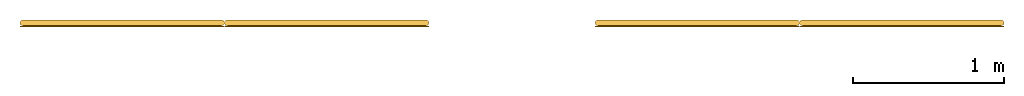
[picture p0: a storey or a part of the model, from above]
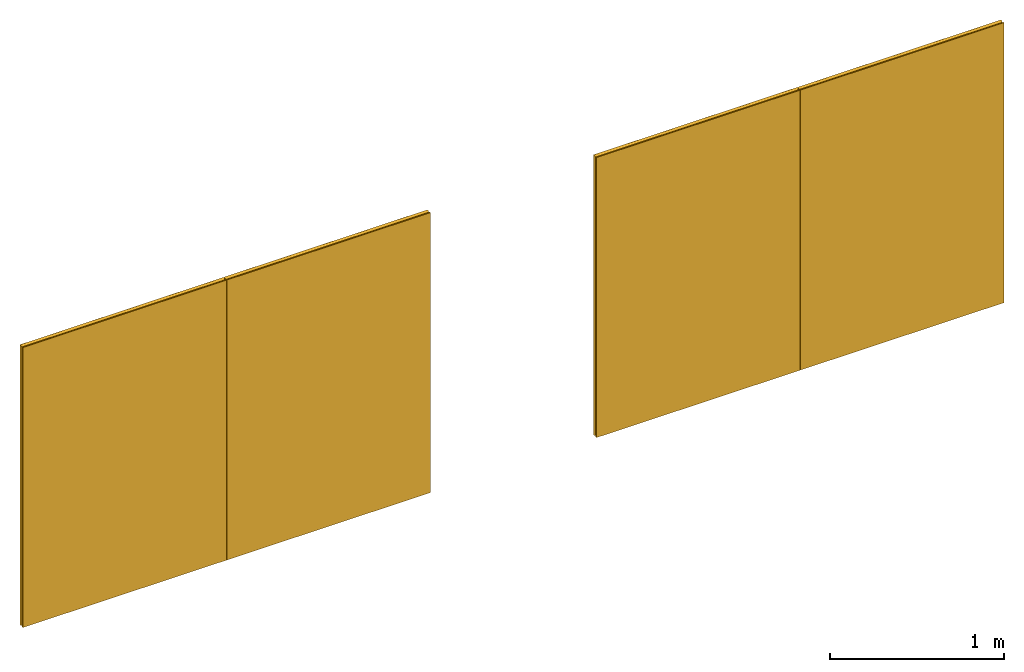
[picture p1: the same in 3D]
Properties of the parts of a building model (IFC2X3), part 1 of 11

# File
Description: ViewDefinition [CoordinationView]
File name: Project Number
Time: 2011-09-06T11:22:43
Written by: Autodesk Revit Architecture 2011 - 1.0
Made in: 20100326_1700

# IfcProject, Project Number
Phase: Project Status

# IfcSite, Default
RefLatitude: 42, 21, 30, 344238; RefLongitude: -71, -3, -35, -194702; RefElevation: 0 m

# IfcBuilding
Pset_BuildingCommon - NumberOfStoreys: 4
PSet_Revit_Other - Project Issue Date: Issue Date; Project Status: Project Status; Client Name: Owner; Project Address: Enter address here; Project Name: Project Name; Project Number: Project Number; Category Description: OmniClass Table 11 Description; Category Code: OmniClass Table 11 Code

# IfcBuildingStorey (4)
PSet_Revit_Type_Graphics - Line Weight: 1; Color: 0; Line Pattern: Centre; Symbol: M_Level Head - Circle; Symbol at End 1 Default: no; Symbol at End 2 Default: yes
PSet_Revit_Type_Constraints - Elevation Base: 0
PSet_Revit_Type_Dimensions - Automatic Room Computation Height: yes
Name | Elevation (m) | Name | PSet_Revit_Constraints, Elevation (m) | Category Code
TOF Footing | -1 | TOF Footing | -1 | Site
First Floor | -3.5315e-13 | First Floor | 0 | Floor
Second Floor | 4.57 | Second Floor | 4.57 | Floor
Roof - Main | 9.25 | Roof - Main | 9.25 | Roof

# IfcSpace (269)
InteriorOrExteriorSpace: INTERNAL
PSet_Revit_Phasing - Phase: New Construction
PSet_Revit_Other - RoomTag: RoomTag
Name | In | LongName = Name | GSA BIM Area (m2) = Area (m2) | Number | OmniClass Table 13 Category | Level | Upper Limit | Limit Offset (m) | Base Offset (m) | Perimeter (m) | Unbounded Height (m) | Volume (m3) | Category Description | Category Code | CirculationZoneName | FireAlarmZoneName | HistoricPreservationZoneName | LightingZoneName | OccupancyZoneName | VentilationZoneName
1AC2 | First Floor | CORRIDOR | 19.605 | 1AC2 | 13-85 11 11: Corridor | First Floor | First Floor | 2.8 | 0 | 24.0652 | 2.8 | 53.4757 | Corridor | 13-85 11 11 | Circulation Zone 1A | Fire Alarm Zone 1A | Historic Preservation Zone 1A | Lighting Zone 1A | Occupancy Zone 1A | Ventilation Zone 1A
1A01 | First Floor | PATIENT ADMIN. RECEPT. | 19.7671 | 1A01 | 13-11 11 31: Reception Space | First Floor | First Floor | 2.8 | 0 | 19.072 | 2.8 | 53.2474 | Reception Space | 13-11 11 31 | Circulation Zone 1A | Fire Alarm Zone 1A | Historic Preservation Zone 1A | Lighting Zone 1A | Occupancy Zone 1A | Ventilation Zone 1A
1A02 | First Floor | RMO ANALYST | 27.6932 | 1A02 | 13-15 11 34 11: Office | First Floor | First Floor | 2.8 | 0 | 26.5002 | 2.8 | 74.6419 | Office | 13-15 11 34 11 | Circulation Zone 1A | Fire Alarm Zone 1A | Historic Preservation Zone 1A | Lighting Zone 1A | Occupancy Zone 1A | Ventilation Zone 1A
1A03 | First Floor | TRICARE OFFICE | 8.87366 | 1A03 | 13-15 11 34 11: Office | First Floor | First Floor | 2.8 | 0 | 11.957 | 2.8 | 22.8438 | Office | 13-15 11 34 11 | Circulation Zone 1A | Fire Alarm Zone 1A | Historic Preservation Zone 1A | Lighting Zone 1A | Occupancy Zone 1A | Ventilation Zone 1A
1A04 | First Floor | TRICARE OFFICE | 9.54452 | 1A04 | 13-15 11 34 11: Office | First Floor | First Floor | 2.8 | 0 | 12.369 | 2.8 | 24.0527 | Office | 13-15 11 34 11 | Circulation Zone 1A | Fire Alarm Zone 1A | Historic Preservation Zone 1A | Lighting Zone 1A | Occupancy Zone 1A | Ventilation Zone 1A
1A05 | First Floor | TRICARE OFFICE | 8.99911 | 1A05 | 13-15 11 34 11: Office | First Floor | First Floor | 2.8 | 0 | 12.192 | 2.8 | 23.2335 | Office | 13-15 11 34 11 | Circulation Zone 1A | Fire Alarm Zone 1A | Historic Preservation Zone 1A | Lighting Zone 1A | Occupancy Zone 1A | Ventilation Zone 1A
1A06 | First Floor | TRICARE OFFICE | 10.4921 | 1A06 | 13-15 11 34 11: Office | First Floor | First Floor | 2.8 | 0 | 13.0265 | 2.8 | 26.1176 | Office | 13-15 11 34 11 | Circulation Zone 1A | Fire Alarm Zone 1A | Historic Preservation Zone 1A | Lighting Zone 1A | Occupancy Zone 1A | Ventilation Zone 1A
1A07 | First Floor | TRICARE OFFICE | 8.73012 | 1A07 | 13-15 11 34 11: Office | First Floor | First Floor | 2.8 | 0 | 12.5275 | 2.8 | 22.3143 | Office | 13-15 11 34 11 | Circulation Zone 1A | Fire Alarm Zone 1A | Historic Preservation Zone 1A | Lighting Zone 1A | Occupancy Zone 1A | Ventilation Zone 1A
1A08 | First Floor | PHARM. OFFICE | 10.4499 | 1A08 | 13-15 11 34 11: Office | First Floor | First Floor | 2.8 | 0 | 12.989 | 2.8 | 26.63 | Office | 13-15 11 34 11 | Circulation Zone 1A | Fire Alarm Zone 1A | Historic Preservation Zone 1A | Lighting Zone 1A | Occupancy Zone 1A | Ventilation Zone 1A
1A11 | First Floor | JAN. | 2.03661 | 1A11 | 13-75 11 11: Storage Room | First Floor | First Floor | 2.8 | 0 | 6.022 | 2.8 | 4.70014 | Storage Room | 13-75 11 11 | Circulation Zone 1A | Fire Alarm Zone 1A | Historic Preservation Zone 1A | Lighting Zone 1A | Occupancy Zone 1A | Ventilation Zone 1A
1A14 | First Floor | SUPER / NCOIC | 7.22988 | 1A14 | 13-15 11 34 11: Office | First Floor | First Floor | 2.8 | 0 | 10.1474 | 2.8 | 18.8948 | Office | 13-15 11 34 11 | Circulation Zone 1A | Fire Alarm Zone 1A | Historic Preservation Zone 1A | Lighting Zone 1A | Occupancy Zone 1A | Ventilation Zone 1A
1A15 | First Floor | COUNSELING | 6.39843 | 1A15 | 13-41 41 99: Other Healing Spaces | First Floor | First Floor | 2.8 | 0 | 10.157 | 2.8 | 16.4305 | Other Healing Spaces | 13-41 41 99 | Circulation Zone 1A | Fire Alarm Zone 1A | Historic Preservation Zone 1A | Lighting Zone 1A | Occupancy Zone 1A | Ventilation Zone 1A
1DC1 | First Floor | WAITING / ACTIVITY AREA | 182.28 | 1DC1 | 13-51 31 11: Waiting Room | First Floor | Second Floor | 0 | 0 | 80.656 | 4.57 | 814.452 | Waiting Room | 13-51 31 11 | Circulation Zone 1D | Fire Alarm Zone 1D | Historic Preservation Zone 1D | Lighting Zone 1D | Occupancy Zone 1D | Ventilation Zone 1D
1DC2 | First Floor | CORRIDOR | 6.34736 | 1DC2 | 13-85 11 11: Corridor | First Floor | First Floor | 2.8 | 0 | 10.67 | 2.8 | 16.6144 | Corridor | 13-85 11 11 | Circulation Zone 1D | Fire Alarm Zone 1D | Historic Preservation Zone 1D | Lighting Zone 1D | Occupancy Zone 1D | Ventilation Zone 1D
1DC3 | First Floor | CORRIDOR | 31.8109 | 1DC3 | 13-85 11 11: Corridor | First Floor | First Floor | 2.8 | 0 | 38.1194 | 2.8 | 83.0333 | Corridor | 13-85 11 11 | Circulation Zone 1D | Fire Alarm Zone 1D | Historic Preservation Zone 1D | Lighting Zone 1D | Occupancy Zone 1D | Ventilation Zone 1D
1DC4 | First Floor | CORRIDOR | 15.0608 | 1DC4 | 13-85 11 11: Corridor | First Floor | First Floor | 2.8 | 0 | 20.1242 | 2.8 | 39.4804 | Corridor | 13-85 11 11 | Circulation Zone 1D | Fire Alarm Zone 1D | Historic Preservation Zone 1D | Lighting Zone 1D | Occupancy Zone 1D | Ventilation Zone 1D
1CC2 | First Floor | CORRIDOR | 8.23209 | 1CC2 | 13-85 11 11: Corridor | First Floor | First Floor | 2.8 | 0 | 12.0636 | 2.8 | 21.1946 | Corridor | 13-85 11 11 | Circulation Zone 1C | Fire Alarm Zone 1C | Historic Preservation Zone 1C | Lighting Zone 1C | Occupancy Zone 1C | Ventilation Zone 1C
1CC3 | First Floor | CORRIDOR | 11.4965 | 1CC3 | 13-85 11 11: Corridor | First Floor | First Floor | 2.8 | 0 | 15.7842 | 2.8 | 29.7028 | Corridor | 13-85 11 11 | Circulation Zone 1C | Fire Alarm Zone 1C | Historic Preservation Zone 1C | Lighting Zone 1C | Occupancy Zone 1C | Ventilation Zone 1C
1C01 | First Floor | WAITING | 11.8597 | 1C01 | 13-51 31 11: Waiting Room | First Floor | First Floor | 2.8 | 0 | 13.5102 | 2.8 | 32.5825 | Waiting Room | 13-51 31 11 | Circulation Zone 1C | Fire Alarm Zone 1C | Historic Preservation Zone 1C | Lighting Zone 1C | Occupancy Zone 1C | Ventilation Zone 1C
1C02 | First Floor | RECEPTION | 9.31934 | 1C02 | 13-11 11 31: Reception Space | First Floor | First Floor | 2.8 | 0 | 12.2052 | 2.8 | 24.6922 | Reception Space | 13-11 11 31 | Circulation Zone 1C | Fire Alarm Zone 1C | Historic Preservation Zone 1C | Lighting Zone 1C | Occupancy Zone 1C | Ventilation Zone 1C
1C03 | First Floor | JAN. CL. | 4.1106 | 1C03 | 13-75 11 11: Storage Room | First Floor | First Floor | 2.8 | 0 | 8.924 | 2.8 | 9.93108 | Storage Room | 13-75 11 11 | Circulation Zone 1C | Fire Alarm Zone 1C | Historic Preservation Zone 1C | Lighting Zone 1C | Occupancy Zone 1C | Ventilation Zone 1C
1C04 | First Floor | FITTING / DISP. | 10.1189 | 1C04 | 13-41 41 99: Other Healing Spaces | First Floor | First Floor | 2.8 | 0 | 12.623 | 2.8 | 25.7339 | Other Healing Spaces | 13-41 41 99 | Circulation Zone 1C | Fire Alarm Zone 1C | Historic Preservation Zone 1C | Lighting Zone 1C | Occupancy Zone 1C | Ventilation Zone 1C
1C05 | First Floor | VISUAL FIELD | 11.3446 | 1C05 | 13-41 41 14: Physical Examination Room | First Floor | First Floor | 2.8 | 0 | 14.538 | 2.8 | 28.2926 | Physical Examination Room | 13-41 41 14 | Circulation Zone 1C | Fire Alarm Zone 1C | Historic Preservation Zone 1C | Lighting Zone 1C | Occupancy Zone 1C | Ventilation Zone 1C
1C06 | First Floor | SOIL. UTL. / TRASH | 5.40043 | 1C06 | 13-75 41 14: Soiled Storage Room Space | First Floor | First Floor | 2.8 | 0 | 9.3758 | 2.8 | 13.0309 | Soiled Storage Room Space | 13-75 41 14 | Circulation Zone 1C | Fire Alarm Zone 1C | Historic Preservation Zone 1C | Lighting Zone 1C | Occupancy Zone 1C | Ventilation Zone 1C
1C07 | First Floor | OPT. EXAM / OFF. | 17.5712 | 1C07 | 13-15 11 34 11: Office | First Floor | First Floor | 2.8 | 0 | 20.7032 | 2.8 | 45.6483 | Office | 13-15 11 34 11 | Circulation Zone 1C | Fire Alarm Zone 1C | Historic Preservation Zone 1C | Lighting Zone 1C | Occupancy Zone 1C | Ventilation Zone 1C
1C08 | First Floor | SCREEN EYE TEST | 9.81776 | 1C08 | 13-41 41 14: Physical Examination Room | First Floor | First Floor | 2.8 | 0 | 13.352 | 2.8 | 25.4762 | Physical Examination Room | 13-41 41 14 | Circulation Zone 1C | Fire Alarm Zone 1C | Historic Preservation Zone 1C | Lighting Zone 1C | Occupancy Zone 1C | Ventilation Zone 1C
1C09 | First Floor | FUNDUS CAMERA ROOM | 14.9278 | 1C09 | 13-41 41 31: Scanning/Imaging Room | First Floor | First Floor | 2.8 | 0 | 16.234 | 2.8 | 38.5611 | Scanning/Imaging Room | 13-41 41 31 | Circulation Zone 1C | Fire Alarm Zone 1C | Historic Preservation Zone 1C | Lighting Zone 1C | Occupancy Zone 1C | Ventilation Zone 1C
1C10 | First Floor | OPT. EXAM / OFF. | 18.2545 | 1C10 | 13-15 11 34 11: Office | First Floor | First Floor | 2.8 | 0 | 20.8688 | 2.8 | 47.5479 | Office | 13-15 11 34 11 | Circulation Zone 1C | Fire Alarm Zone 1C | Historic Preservation Zone 1C | Lighting Zone 1C | Occupancy Zone 1C | Ventilation Zone 1C
1D01 | First Floor | SL. LIN. / TRASH | 2.00168 | 1D01 | 13-75 41 14: Soiled Storage Room Space | First Floor | First Floor | 2.8 | 0 | 6.1929 | 2.8 | 4.65454 | Soiled Storage Room Space | 13-75 41 14 | Circulation Zone 1D | Fire Alarm Zone 1D | Historic Preservation Zone 1D | Lighting Zone 1D | Occupancy Zone 1D | Ventilation Zone 1D
1D03 | First Floor | CLEAN U. | 2.35008 | 1D03 | 13-15 21 11 21: Clean Room | First Floor | First Floor | 2.8 | 0 | 6.09322 | 2.8 | 5.84763 | Clean Room | 13-15 21 11 21 | Circulation Zone 1D | Fire Alarm Zone 1D | Historic Preservation Zone 1D | Lighting Zone 1D | Occupancy Zone 1D | Ventilation Zone 1D
1D12 | First Floor | SPECIMEN COLL. LAB | 10.2108 | 1D12 | 13-15 11 24 11: Laboratory | First Floor | First Floor | 2.8 | 0 | 13.1729 | 2.8 | 26.3971 | Laboratory | 13-15 11 24 11 | Circulation Zone 1D | Fire Alarm Zone 1D | Historic Preservation Zone 1D | Lighting Zone 1D | Occupancy Zone 1D | Ventilation Zone 1D
1D15 | First Floor | WTS & MEAS. ROOM | 5.06769 | 1D15 | 13-41 41 14: Physical Examination Room | First Floor | First Floor | 2.8 | 0 | 9.0729 | 2.8 | 12.8164 | Physical Examination Room | 13-41 41 14 | Circulation Zone 1D | Fire Alarm Zone 1D | Historic Preservation Zone 1D | Lighting Zone 1D | Occupancy Zone 1D | Ventilation Zone 1D
1D16 | First Floor | PROVIDER CUBICLES | 67.8336 | 1D16 | 13-15 11 34 11: Office | First Floor | First Floor | 2.8 | 0 | 36.731 | 2.8 | 182.732 | Office | 13-15 11 34 11 | Circulation Zone 1D | Fire Alarm Zone 1D | Historic Preservation Zone 1D | Lighting Zone 1D | Occupancy Zone 1D | Ventilation Zone 1D
1D17 | First Floor | JAN. CL. | 2.05671 | 1D17 | 13-75 11 11: Storage Room | First Floor | First Floor | 2.8 | 0 | 5.8058 | 2.8 | 4.67952 | Storage Room | 13-75 11 11 | Circulation Zone 1D | Fire Alarm Zone 1D | Historic Preservation Zone 1D | Lighting Zone 1D | Occupancy Zone 1D | Ventilation Zone 1D
1D19 | First Floor | MDIS VIEW | 5.63662 | 1D19 | 13-15 11 34 11: Office | First Floor | First Floor | 2.8 | 0 | 9.711 | 2.8 | 14.3243 | Office | 13-15 11 34 11 | Circulation Zone 1D | Fire Alarm Zone 1D | Historic Preservation Zone 1D | Lighting Zone 1D | Occupancy Zone 1D | Ventilation Zone 1D
1D20 | First Floor | APPMTS | 11.7909 | 1D20 | 13-15 11 34 11: Office | First Floor | First Floor | 2.8 | 0 | 13.74 | 2.8 | 30.6724 | Office | 13-15 11 34 11 | Circulation Zone 1D | Fire Alarm Zone 1D | Historic Preservation Zone 1D | Lighting Zone 1D | Occupancy Zone 1D | Ventilation Zone 1D
1D21 | First Floor | GROUP IS | 19.1917 | 1D21 | 13-41 41 99: Other Healing Spaces | First Floor | First Floor | 2.8 | 0 | 18.161 | 2.8 | 50.1831 | Other Healing Spaces | 13-41 41 99 | Circulation Zone 1D | Fire Alarm Zone 1D | Historic Preservation Zone 1D | Lighting Zone 1D | Occupancy Zone 1D | Ventilation Zone 1D
1D23 | First Floor | GROUP IS | 19.1868 | 1D23 | 13-41 41 99: Other Healing Spaces | First Floor | First Floor | 2.8 | 0 | 18.161 | 2.8 | 50.1702 | Other Healing Spaces | 13-41 41 99 | Circulation Zone 1D | Fire Alarm Zone 1D | Historic Preservation Zone 1D | Lighting Zone 1D | Occupancy Zone 1D | Ventilation Zone 1D
1D24 | First Floor | RECORDS | 11.7777 | 1D24 | 13-75 11 11: Storage Room | First Floor | First Floor | 2.8 | 0 | 13.705 | 2.8 | 30.6724 | Storage Room | 13-75 11 11 | Circulation Zone 1D | Fire Alarm Zone 1D | Historic Preservation Zone 1D | Lighting Zone 1D | Occupancy Zone 1D | Ventilation Zone 1D
1D25 | First Floor | PROVIDER CUBICLES | 67.8191 | 1D25 | 13-15 11 34 11: Office | First Floor | First Floor | 2.8 | 0 | 36.627 | 2.8 | 182.56 | Office | 13-15 11 34 11 | Circulation Zone 1D | Fire Alarm Zone 1D | Historic Preservation Zone 1D | Lighting Zone 1D | Occupancy Zone 1D | Ventilation Zone 1D
1D27 | First Floor | ADMIN WORK STATN. | 10.7499 | 1D27 | 13-15 11 34 11: Office | First Floor | First Floor | 2.8 | 0 | 13.412 | 2.8 | 27.8833 | Office | 13-15 11 34 11 | Circulation Zone 1D | Fire Alarm Zone 1D | Historic Preservation Zone 1D | Lighting Zone 1D | Occupancy Zone 1D | Ventilation Zone 1D
1D30 | First Floor | WTS & MEAS. ROOM | 9.26534 | 1D30 | 13-41 41 14: Physical Examination Room | First Floor | First Floor | 2.8 | 0 | 12.672 | 2.8 | 23.7861 | Physical Examination Room | 13-41 41 14 | Circulation Zone 1D | Fire Alarm Zone 1D | Historic Preservation Zone 1D | Lighting Zone 1D | Occupancy Zone 1D | Ventilation Zone 1D
1D33 | First Floor | PEDIATRIC WAITING | 12.7423 | 1D33 | 13-51 31 11: Waiting Room | First Floor | First Floor | 2.8 | 0 | 14.432 | 2.8 | 33.2712 | Waiting Room | 13-51 31 11 | Circulation Zone 1D | Fire Alarm Zone 1D | Historic Preservation Zone 1D | Lighting Zone 1D | Occupancy Zone 1D | Ventilation Zone 1D
1D37 | First Floor | CLEAN U. | 2.35008 | 1D37 | 13-15 21 11 21: Clean Room | First Floor | First Floor | 2.8 | 0 | 6.09322 | 2.8 | 5.84763 | Clean Room | 13-15 21 11 21 | Circulation Zone 1D | Fire Alarm Zone 1D | Historic Preservation Zone 1D | Lighting Zone 1D | Occupancy Zone 1D | Ventilation Zone 1D
1D39 | First Floor | JAN. CL. | 2.00067 | 1D39 | 13-75 11 11: Storage Room | First Floor | First Floor | 2.8 | 0 | 6.192 | 2.8 | 4.65202 | Storage Room | 13-75 11 11 | Circulation Zone 1D | Fire Alarm Zone 1D | Historic Preservation Zone 1D | Lighting Zone 1D | Occupancy Zone 1D | Ventilation Zone 1D
1DC5 | First Floor | CORRIDOR | 6.61219 | 1DC5 | 13-85 11 11: Corridor | First Floor | First Floor | 2.8 | 0 | 10.2786 | 2.8 | 17.0051 | Corridor | 13-85 11 11 | Circulation Zone 1D | Fire Alarm Zone 1D | Historic Preservation Zone 1D | Lighting Zone 1D | Occupancy Zone 1D | Ventilation Zone 1D
1DC6 | First Floor | CORRIDOR | 15.0065 | 1DC6 | 13-85 11 11: Corridor | First Floor | First Floor | 2.8 | 0 | 20.1568 | 2.8 | 38.8805 | Corridor | 13-85 11 11 | Circulation Zone 1D | Fire Alarm Zone 1D | Historic Preservation Zone 1D | Lighting Zone 1D | Occupancy Zone 1D | Ventilation Zone 1D
1DC7 | First Floor | CORRIDOR | 31.9069 | 1DC7 | 13-85 11 11: Corridor | First Floor | First Floor | 2.8 | 0 | 37.8435 | 2.8 | 83.5098 | Corridor | 13-85 11 11 | Circulation Zone 1D | Fire Alarm Zone 1D | Historic Preservation Zone 1D | Lighting Zone 1D | Occupancy Zone 1D | Ventilation Zone 1D
1DC8 | First Floor | CORRIDOR | 6.29243 | 1DC8 | 13-85 11 11: Corridor | First Floor | First Floor | 2.8 | 0 | 10.6091 | 2.8 | 16.4607 | Corridor | 13-85 11 11 | Circulation Zone 1D | Fire Alarm Zone 1D | Historic Preservation Zone 1D | Lighting Zone 1D | Occupancy Zone 1D | Ventilation Zone 1D
1C13 | First Floor | COMM. ROOM | 11.8973 | 1C13 | 13-15 11 34 11: Office | First Floor | First Floor | 2.8 | 0 | 14.159 | 2.8 | 30.9818 | Office | 13-15 11 34 11 | Circulation Zone 1C | Fire Alarm Zone 1C | Historic Preservation Zone 1C | Lighting Zone 1C | Occupancy Zone 1C | Ventilation Zone 1C
1C14 | First Floor | HIST. / INTV. | 8.18416 | 1C14 | 13-41 41 99: Other Healing Spaces | First Floor | First Floor | 2.8 | 0 | 11.509 | 2.8 | 20.4711 | Other Healing Spaces | 13-41 41 99 | Circulation Zone 1C | Fire Alarm Zone 1C | Historic Preservation Zone 1C | Lighting Zone 1C | Occupancy Zone 1C | Ventilation Zone 1C
1C15 | First Floor | PES ADMIN. OFFICE | 15.3931 | 1C15 | 13-15 11 34 11: Office | First Floor | First Floor | 2.8 | 0 | 15.77 | 2.8 | 40.8184 | Office | 13-15 11 34 11 | Circulation Zone 1C | Fire Alarm Zone 1C | Historic Preservation Zone 1C | Lighting Zone 1C | Occupancy Zone 1C | Ventilation Zone 1C
1C16 | First Floor | ECG TEST | 10.0079 | 1C16 | 13-41 41 31: Scanning/Imaging Room | First Floor | First Floor | 2.8 | 0 | 13.668 | 2.8 | 25.3019 | Scanning/Imaging Room | 13-41 41 31 | Circulation Zone 1C | Fire Alarm Zone 1C | Historic Preservation Zone 1C | Lighting Zone 1C | Occupancy Zone 1C | Ventilation Zone 1C
1C17 | First Floor | CHIEF AERO MED. | 9.94224 | 1C17 | 13-15 11 34 11: Office | First Floor | First Floor | 2.8 | 0 | 12.691 | 2.8 | 25.1968 | Office | 13-15 11 34 11 | Circulation Zone 1C | Fire Alarm Zone 1C | Historic Preservation Zone 1C | Lighting Zone 1C | Occupancy Zone 1C | Ventilation Zone 1C
1C18 | First Floor | PHYSICAL EXAM | 58.0301 | 1C18 | 13-41 41 14: Physical Examination Room | First Floor | First Floor | 2.8 | 0 | 41.077 | 2.8 | 155.057 | Physical Examination Room | 13-41 41 14 | Circulation Zone 1C | Fire Alarm Zone 1C | Historic Preservation Zone 1C | Lighting Zone 1C | Occupancy Zone 1C | Ventilation Zone 1C
1C19 | First Floor | AUDIO | 11.6268 | 1C19 | 13-81 21 11: Equipment Room | First Floor | First Floor | 2.8 | 0 | 13.798 | 2.8 | 29.1218 | Equipment Room | 13-81 21 11 | Circulation Zone 1C | Fire Alarm Zone 1C | Historic Preservation Zone 1C | Lighting Zone 1C | Occupancy Zone 1C | Ventilation Zone 1C
1C11 | First Floor | ELEC. CL. | 0.777824 | 1C11 | 13-81 21 21: Electrical Room | First Floor | First Floor | 2.8 | 0 | 4.44 | 2.8 | 1.51133 | Electrical Room | 13-81 21 21 | Circulation Zone 1C | Fire Alarm Zone 1C | Historic Preservation Zone 1C | Lighting Zone 1C | Occupancy Zone 1C | Ventilation Zone 1C
1CS3 | First Floor | STAIR | 13.9094 | 1CS3 | 13-85 21 11: Stairway | First Floor | First Floor | 2.8 | 0 | 18.996 | 2.8 | 35.7133 | Stairway | 13-85 21 11 | Circulation Zone 1C | Fire Alarm Zone 1C | Historic Preservation Zone 1C | Lighting Zone 1C | Occupancy Zone 1C | Ventilation Zone 1C
1E01 | First Floor | HK EQUIP. STORAGE | 9.72524 | 1E01 | 13-75 11 11: Storage Room | First Floor | First Floor | 2.8 | 0 | 12.492 | 2.8 | 25.1051 | Storage Room | 13-75 11 11 | Circulation Zone 1E | Fire Alarm Zone 1E | Historic Preservation Zone 1E | Lighting Zone 1E | Occupancy Zone 1E | Ventilation Zone 1E
1E02 | First Floor | ELEV. EQUIP. | 5.67552 | 1E02 | 13-81 21 11: Equipment Room | First Floor | First Floor | 2.8 | 0 | 9.752 | 2.8 | 14.2416 | Equipment Room | 13-81 21 11 | Circulation Zone 1E | Fire Alarm Zone 1E | Historic Preservation Zone 1E | Lighting Zone 1E | Occupancy Zone 1E | Ventilation Zone 1E
1E03 | First Floor | JAN. CL. | 3.96995 | 1E03 | 13-75 11 11: Storage Room | First Floor | First Floor | 2.8 | 0 | 8.652 | 2.8 | 9.71094 | Storage Room | 13-75 11 11 | Circulation Zone 1E | Fire Alarm Zone 1E | Historic Preservation Zone 1E | Lighting Zone 1E | Occupancy Zone 1E | Ventilation Zone 1E
1E05 | First Floor | CHIEF LOG OFFICE | 9.93876 | 1E05 | 13-15 11 34 11: Office | First Floor | First Floor | 2.8 | 0 | 12.628 | 2.8 | 25.6794 | Office | 13-15 11 34 11 | Circulation Zone 1E | Fire Alarm Zone 1E | Historic Preservation Zone 1E | Lighting Zone 1E | Occupancy Zone 1E | Ventilation Zone 1E
1E06 | First Floor | TECH. WORK STATION | 37.3792 | 1E06 | 13-15 11 34 11: Office | First Floor | First Floor | 2.8 | 0 | 24.978 | 2.8 | 100.456 | Office | 13-15 11 34 11 | Circulation Zone 1E | Fire Alarm Zone 1E | Historic Preservation Zone 1E | Lighting Zone 1E | Occupancy Zone 1E | Ventilation Zone 1E
1E07 | First Floor | CONF. LIBRARY | 11.6309 | 1E07 | 13-11 21 17: Conference Room | First Floor | First Floor | 2.8 | 0 | 13.652 | 2.8 | 30.2395 | Conference Room | 13-11 21 17 | Circulation Zone 1E | Fire Alarm Zone 1E | Historic Preservation Zone 1E | Lighting Zone 1E | Occupancy Zone 1E | Ventilation Zone 1E
1E08 | First Floor | SUPER | 9.86423 | 1E08 | 13-15 11 34 11: Office | First Floor | First Floor | 2.8 | 0 | 13.058 | 2.8 | 25.4832 | Office | 13-15 11 34 11 | Circulation Zone 1E | Fire Alarm Zone 1E | Historic Preservation Zone 1E | Lighting Zone 1E | Occupancy Zone 1E | Ventilation Zone 1E
1E14 | First Floor | DISASTER STOR. | 22.3553 | 1E14 | 13-75 11 11: Storage Room | First Floor | First Floor | 2.8 | 0 | 19.889 | 2.8 | 59.1954 | Storage Room | 13-75 11 11 | Circulation Zone 1E | Fire Alarm Zone 1E | Historic Preservation Zone 1E | Lighting Zone 1E | Occupancy Zone 1E | Ventilation Zone 1E
1E15 | First Floor | CENTRAL MECH. RM. | 28.9142 | 1E15 | 13-81 21 17: Mechanical Room | First Floor | First Floor | 2.8 | 0 | 24.1165 | 2.8 | 76.0404 | Mechanical Room | 13-81 21 17 | Circulation Zone 1E | Fire Alarm Zone 1E | Historic Preservation Zone 1E | Lighting Zone 1E | Occupancy Zone 1E | Ventilation Zone 1E
1E17 | First Floor | HAZ. STOR. | 9.78713 | 1E17 | 13-75 41 24: Hazardous Material Storage Space | First Floor | First Floor | 2.8 | 0 | 12.724 | 2.8 | 24.2384 | Hazardous Material Storage Space | 13-75 41 24 | Circulation Zone 1E | Fire Alarm Zone 1E | Historic Preservation Zone 1E | Lighting Zone 1E | Occupancy Zone 1E | Ventilation Zone 1E
1E18 | First Floor | BIOMED MAINT. ADMIN. | 15.5543 | 1E18 | 13-15 11 34 11: Office | First Floor | First Floor | 2.8 | 0 | 15.9435 | 2.8 | 40.2173 | Office | 13-15 11 34 11 | Circulation Zone 1E | Fire Alarm Zone 1E | Historic Preservation Zone 1E | Lighting Zone 1E | Occupancy Zone 1E | Ventilation Zone 1E
1E19 | First Floor | ELEC. ROOM | 9.6262 | 1E19 | 13-81 21 21: Electrical Room | First Floor | First Floor | 2.8 | 0 | 12.686 | 2.8 | 24.8866 | Electrical Room | 13-81 21 21 | Circulation Zone 1E | Fire Alarm Zone 1E | Historic Preservation Zone 1E | Lighting Zone 1E | Occupancy Zone 1E | Ventilation Zone 1E
1E20 | First Floor | TRASH | 8.95436 | 1E20 | 13-75 41 14: Soiled Storage Room Space | First Floor | First Floor | 2.8 | 0 | 12.6045 | 2.8 | 22.0557 | Soiled Storage Room Space | 13-75 41 14 | Circulation Zone 1E | Fire Alarm Zone 1E | Historic Preservation Zone 1E | Lighting Zone 1E | Occupancy Zone 1E | Ventilation Zone 1E
1E21 | First Floor | FLAMABLE STORAGE | 5.66451 | 1E21 | 13-75 41 24: Hazardous Material Storage Space | First Floor | First Floor | 2.8 | 0 | 9.75218 | 2.8 | 13.5165 | Hazardous Material Storage Space | 13-75 41 24 | Circulation Zone 1E | Fire Alarm Zone 1E | Historic Preservation Zone 1E | Lighting Zone 1E | Occupancy Zone 1E | Ventilation Zone 1E
1E22 | First Floor | SEC. STORAGE | 6.27284 | 1E22 | 13-75 11 11: Storage Room | First Floor | First Floor | 2.8 | 0 | 10.424 | 2.8 | 15.7974 | Storage Room | 13-75 11 11 | Circulation Zone 1E | Fire Alarm Zone 1E | Historic Preservation Zone 1E | Lighting Zone 1E | Occupancy Zone 1E | Ventilation Zone 1E
1E23 | First Floor | BEE EQUIP. STORAGE | 8.77894 | 1E23 | 13-81 21 11: Equipment Room | First Floor | First Floor | 2.8 | 0 | 12.981 | 2.8 | 22.5535 | Equipment Room | 13-81 21 11 | Circulation Zone 1E | Fire Alarm Zone 1E | Historic Preservation Zone 1E | Lighting Zone 1E | Occupancy Zone 1E | Ventilation Zone 1E
1E24 | First Floor | RECEIVING / STORAGE | 118.296 | 1E24 | 13-75 11 11: Storage Room | First Floor | First Floor | 2.8 | 0 | 48.0138 | 2.8 | 322.336 | Storage Room | 13-75 11 11 | Circulation Zone 1E | Fire Alarm Zone 1E | Historic Preservation Zone 1E | Lighting Zone 1E | Occupancy Zone 1E | Ventilation Zone 1E
1E25 | First Floor | ADP EQUIP SPACE | 11.3734 | 1E25 | 13-75 11 11: Storage Room | First Floor | First Floor | 2.8 | 0 | 13.9988 | 2.8 | 29.5705 | Storage Room | 13-75 11 11 | Circulation Zone 1E | Fire Alarm Zone 1E | Historic Preservation Zone 1E | Lighting Zone 1E | Occupancy Zone 1E | Ventilation Zone 1E
1E26 | First Floor | WORK ROOM | 19.7143 | 1E26 | 13-15 11 34 11: Office | First Floor | First Floor | 2.8 | 0 | 18.857 | 2.8 | 51.3677 | Office | 13-15 11 34 11 | Circulation Zone 1E | Fire Alarm Zone 1E | Historic Preservation Zone 1E | Lighting Zone 1E | Occupancy Zone 1E | Ventilation Zone 1E
1E27 | First Floor | BENCHSTOCK STORAGE | 9.51258 | 1E27 | 13-75 11 11: Storage Room | First Floor | First Floor | 2.8 | 0 | 12.337 | 2.8 | 23.9448 | Storage Room | 13-75 11 11 | Circulation Zone 1E | Fire Alarm Zone 1E | Historic Preservation Zone 1E | Lighting Zone 1E | Occupancy Zone 1E | Ventilation Zone 1E
1E28 | First Floor | FAC. MGR. OFFICE | 9.73829 | 1E28 | 13-15 11 34 11: Office | First Floor | First Floor | 2.8 | 0 | 12.614 | 2.8 | 24.1581 | Office | 13-15 11 34 11 | Circulation Zone 1E | Fire Alarm Zone 1E | Historic Preservation Zone 1E | Lighting Zone 1E | Occupancy Zone 1E | Ventilation Zone 1E
1E29 | First Floor | HK. SUPV. OFFICE | 11.0301 | 1E29 | 13-15 11 34 11: Office | First Floor | First Floor | 2.8 | 0 | 13.469 | 2.8 | 27.8587 | Office | 13-15 11 34 11 | Circulation Zone 1E | Fire Alarm Zone 1E | Historic Preservation Zone 1E | Lighting Zone 1E | Occupancy Zone 1E | Ventilation Zone 1E
1E33 | First Floor | ISOLATION INTERACTION STATION | 13.354 | 1E33 | 13-41 41 99: Other Healing Spaces | First Floor | First Floor | 2.8 | 0 | 15.028 | 2.8 | 34.8761 | Other Healing Spaces | 13-41 41 99 | Circulation Zone 1E | Fire Alarm Zone 1E | Historic Preservation Zone 1E | Lighting Zone 1E | Occupancy Zone 1E | Ventilation Zone 1E
1EC1 | First Floor | CORRIDOR | 54.6837 | 1EC1 | 13-85 11 11: Corridor | First Floor | First Floor | 2.8 | 0 | 63.909 | 2.8 | 142.662 | Corridor | 13-85 11 11 | Circulation Zone 1E | Fire Alarm Zone 1E | Historic Preservation Zone 1E | Lighting Zone 1E | Occupancy Zone 1E | Ventilation Zone 1E
1EC2 | First Floor | CORRIDOR | 7.91371 | 1EC2 | 13-85 11 11: Corridor | First Floor | First Floor | 2.8 | 0 | 11.7164 | 2.8 | 20.3634 | Corridor | 13-85 11 11 | Circulation Zone 1E | Fire Alarm Zone 1E | Historic Preservation Zone 1E | Lighting Zone 1E | Occupancy Zone 1E | Ventilation Zone 1E
1EC3 | First Floor | CORRIDOR | 8.75185 | 1EC3 | 13-85 11 11: Corridor | First Floor | First Floor | 2.8 | 0 | 12.6304 | 2.8 | 22.5515 | Corridor | 13-85 11 11 | Circulation Zone 1E | Fire Alarm Zone 1E | Historic Preservation Zone 1E | Lighting Zone 1E | Occupancy Zone 1E | Ventilation Zone 1E
1EC4 | First Floor | CORRIDOR | 9.30567 | 1EC4 | 13-85 11 11: Corridor | First Floor | First Floor | 2.8 | 0 | 12.6514 | 2.8 | 23.6975 | Corridor | 13-85 11 11 | Circulation Zone 1E | Fire Alarm Zone 1E | Historic Preservation Zone 1E | Lighting Zone 1E | Occupancy Zone 1E | Ventilation Zone 1E
1BC1 | First Floor | CORRIDOR | 5.69274 | 1BC1 | 13-85 11 11: Corridor | First Floor | First Floor | 2.8 | 0 | 9.876 | 2.8 | 14.2682 | Corridor | 13-85 11 11 | Circulation Zone 1B | Fire Alarm Zone 1B | Historic Preservation Zone 1B | Lighting Zone 1B | Occupancy Zone 1B | Ventilation Zone 1B
1BC3 | First Floor | CORRIDOR | 13.4396 | 1BC3 | 13-85 11 11: Corridor | First Floor | First Floor | 2.8 | 0 | 18.0333 | 2.8 | 34.7897 | Corridor | 13-85 11 11 | Circulation Zone 1B | Fire Alarm Zone 1B | Historic Preservation Zone 1B | Lighting Zone 1B | Occupancy Zone 1B | Ventilation Zone 1B
1BC4 | First Floor | CORRIDOR | 44.3648 | 1BC4 | 13-85 11 11: Corridor | First Floor | First Floor | 2.8 | 0 | 44.8858 | 2.8 | 116.82 | Corridor | 13-85 11 11 | Circulation Zone 1B | Fire Alarm Zone 1B | Historic Preservation Zone 1B | Lighting Zone 1B | Occupancy Zone 1B | Ventilation Zone 1B
1B01 | First Floor | RECEPTION | 9.47555 | 1B01 | 13-11 11 31: Reception Space | First Floor | First Floor | 2.8 | 0 | 12.664 | 2.8 | 24.6632 | Reception Space | 13-11 11 31 | Circulation Zone 1B | Fire Alarm Zone 1B | Historic Preservation Zone 1B | Lighting Zone 1B | Occupancy Zone 1B | Ventilation Zone 1B
1B03 | First Floor | BLOOD DRAW | 9.68098 | 1B03 | 13-41 41 99: Other Healing Spaces | First Floor | First Floor | 2.8 | 0 | 12.732 | 2.8 | 24.9395 | Other Healing Spaces | 13-41 41 99 | Circulation Zone 1B | Fire Alarm Zone 1B | Historic Preservation Zone 1B | Lighting Zone 1B | Occupancy Zone 1B | Ventilation Zone 1B
1B06 | First Floor | LAB OFFICE | 10.4755 | 1B06 | 13-15 11 34 11: Office | First Floor | First Floor | 2.8 | 0 | 13.1609 | 2.8 | 26.1831 | Office | 13-15 11 34 11 | Circulation Zone 1B | Fire Alarm Zone 1B | Historic Preservation Zone 1B | Lighting Zone 1B | Occupancy Zone 1B | Ventilation Zone 1B
1B07 | First Floor | DRESS | 4.42138 | 1B07 | 13-41 11 41 11: Dressing Room | First Floor | First Floor | 2.8 | 0 | 8.704 | 2.8 | 10.9119 | Dressing Room | 13-41 11 41 11 | Circulation Zone 1B | Fire Alarm Zone 1B | Historic Preservation Zone 1B | Lighting Zone 1B | Occupancy Zone 1B | Ventilation Zone 1B
1B08 | First Floor | CENT. STO. | 9.76711 | 1B08 | 13-75 11 11: Storage Room | First Floor | First Floor | 2.8 | 0 | 12.796 | 2.8 | 25.0222 | Storage Room | 13-75 11 11 | Circulation Zone 1B | Fire Alarm Zone 1B | Historic Preservation Zone 1B | Lighting Zone 1B | Occupancy Zone 1B | Ventilation Zone 1B
1B09 | First Floor | DRESS | 4.64607 | 1B09 | 13-41 11 41 11: Dressing Room | First Floor | First Floor | 2.8 | 0 | 8.64805 | 2.8 | 11.5507 | Dressing Room | 13-41 11 41 11 | Circulation Zone 1B | Fire Alarm Zone 1B | Historic Preservation Zone 1B | Lighting Zone 1B | Occupancy Zone 1B | Ventilation Zone 1B
1B12 | First Floor | CLEAN SUP. & EQUIP. | 3.90136 | 1B12 | 13-75 11 11: Storage Room | First Floor | First Floor | 2.8 | 0 | 8.51705 | 2.8 | 9.24604 | Storage Room | 13-75 11 11 | Circulation Zone 1B | Fire Alarm Zone 1B | Historic Preservation Zone 1B | Lighting Zone 1B | Occupancy Zone 1B | Ventilation Zone 1B
1B13 | First Floor | RECEPTION | 22.5898 | 1B13 | 13-11 11 31: Reception Space | First Floor | First Floor | 2.8 | 0 | 21.5613 | 2.8 | 60.089 | Reception Space | 13-11 11 31 | Circulation Zone 1B | Fire Alarm Zone 1B | Historic Preservation Zone 1B | Lighting Zone 1B | Occupancy Zone 1B | Ventilation Zone 1B
1B14 | First Floor | SOIL. UTL. | 4.03581 | 1B14 | 13-75 41 14: Soiled Storage Room Space | First Floor | First Floor | 2.8 | 0 | 8.609 | 2.8 | 9.59735 | Soiled Storage Room Space | 13-75 41 14 | Circulation Zone 1B | Fire Alarm Zone 1B | Historic Preservation Zone 1B | Lighting Zone 1B | Occupancy Zone 1B | Ventilation Zone 1B
1B15 | First Floor | FILM VIEW | 5.83705 | 1B15 | 13-41 41 31: Scanning/Imaging Room | First Floor | First Floor | 2.8 | 0 | 9.664 | 2.8 | 14.7091 | Scanning/Imaging Room | 13-41 41 31 | Circulation Zone 1B | Fire Alarm Zone 1B | Historic Preservation Zone 1B | Lighting Zone 1B | Occupancy Zone 1B | Ventilation Zone 1B
1B16 | First Floor | JAN. CL. | 4.03581 | 1B16 | 13-75 11 11: Storage Room | First Floor | First Floor | 2.8 | 0 | 8.609 | 2.8 | 9.59735 | Storage Room | 13-75 11 11 | Circulation Zone 1B | Fire Alarm Zone 1B | Historic Preservation Zone 1B | Lighting Zone 1B | Occupancy Zone 1B | Ventilation Zone 1B
1B17 | First Floor | TECH. WORK ROOM | 24.0437 | 1B17 | 13-15 11 34 11: Office | First Floor | First Floor | 2.8 | 0 | 20.0581 | 2.8 | 64.5027 | Office | 13-15 11 34 11 | Circulation Zone 1B | Fire Alarm Zone 1B | Historic Preservation Zone 1B | Lighting Zone 1B | Occupancy Zone 1B | Ventilation Zone 1B
1B19 | First Floor | RADIOGRAPHIC ROOM | 29.9132 | 1B19 | 13-41 41 99: Other Healing Spaces | First Floor | First Floor | 2.8 | 0 | 28.5508 | 2.8 | 79.0515 | Other Healing Spaces | 13-41 41 99 | Circulation Zone 1B | Fire Alarm Zone 1B | Historic Preservation Zone 1B | Lighting Zone 1B | Occupancy Zone 1B | Ventilation Zone 1B
1B21 | First Floor | COMM. ROOM | 9.80232 | 1B21 | 13-15 11 34 11: Office | First Floor | First Floor | 2.8 | 0 | 13.012 | 2.8 | 25.2307 | Office | 13-15 11 34 11 | Circulation Zone 1B | Fire Alarm Zone 1B | Historic Preservation Zone 1B | Lighting Zone 1B | Occupancy Zone 1B | Ventilation Zone 1B
1B23 | First Floor | ELEC. ROOM | 9.88297 | 1B23 | 13-81 21 21: Electrical Room | First Floor | First Floor | 2.8 | 0 | 13.0801 | 2.8 | 25.4447 | Electrical Room | 13-81 21 21 | Circulation Zone 1B | Fire Alarm Zone 1B | Historic Preservation Zone 1B | Lighting Zone 1B | Occupancy Zone 1B | Ventilation Zone 1B
1BS2 | First Floor | STAIR | 16.0319 | 1BS2 | 13-85 21 11: Stairway | First Floor | First Floor | 2.8 | 0 | 18.161 | 2.8 | 41.5241 | Stairway | 13-85 21 11 | Circulation Zone 1E | Fire Alarm Zone 1E | Historic Preservation Zone 1E | Lighting Zone 1E | Occupancy Zone 1E | Ventilation Zone 1E
1AS1 | First Floor | STAIR | 14.0577 | 1AS1 | 13-85 21 11: Stairway | First Floor | First Floor | 2.8 | 0 | 15.646 | 2.8 | 38.0143 | Stairway | 13-85 21 11 | Circulation Zone 1A | Fire Alarm Zone 1A | Historic Preservation Zone 1A | Lighting Zone 1A | Occupancy Zone 1A | Ventilation Zone 1A
1E15-A | First Floor | GAS STORAGE | 2.28945 | 1E15-A | 13-75 41 24: Hazardous Material Storage Space | First Floor | First Floor | 2.8 | 0 | 7.3006 | 2.8 | 4.64121 | Hazardous Material Storage Space | 13-75 41 24 | Circulation Zone 1E | Fire Alarm Zone 1E | Historic Preservation Zone 1E | Lighting Zone 1E | Occupancy Zone 1E | Ventilation Zone 1E
2AC1 | Second Floor | CORRIDOR | 39.5583 | 2AC1 | 13-85 11 11: Corridor | Second Floor | Roof - Main | 0 | 0 | 31.383 | 4.68 | 181.862 | Corridor | 13-85 11 11 | Circulation Zone 2A | Fire Alarm Zone 2A | Historic Preservation Zone 2A | Lighting Zone 2A | Occupancy Zone 2A | Ventilation Zone 2A
2AC2 | Second Floor | CORRIDOR | 15.0174 | 2AC2 | 13-85 11 11: Corridor | Second Floor | Second Floor | 2.8 | 0 | 21.167 | 2.8 | 38.9924 | Corridor | 13-85 11 11 | Circulation Zone 2A | Fire Alarm Zone 2A | Historic Preservation Zone 2A | Lighting Zone 2A | Occupancy Zone 2A | Ventilation Zone 2A
2AC3 | Second Floor | CORRIDOR | 27.093 | 2AC3 | 13-85 11 11: Corridor | Second Floor | Second Floor | 2.8 | 0 | 33.5372 | 2.8 | 71.9794 | Corridor | 13-85 11 11 | Circulation Zone 2A | Fire Alarm Zone 2A | Historic Preservation Zone 2A | Lighting Zone 2A | Occupancy Zone 2A | Ventilation Zone 2A
2AC4 | Second Floor | CORRIDOR | 14.3235 | 2AC4 | 13-85 11 11: Corridor | Second Floor | Second Floor | 2.8 | 0 | 19.474 | 2.8 | 37.5506 | Corridor | 13-85 11 11 | Circulation Zone 2A | Fire Alarm Zone 2A | Historic Preservation Zone 2A | Lighting Zone 2A | Occupancy Zone 2A | Ventilation Zone 2A
2AC5 | Second Floor | CORRIDOR | 9.10214 | 2AC5 | 13-85 11 11: Corridor | Second Floor | Second Floor | 2.8 | 0 | 13.0124 | 2.8 | 23.466 | Corridor | 13-85 11 11 | Circulation Zone 2A | Fire Alarm Zone 2A | Historic Preservation Zone 2A | Lighting Zone 2A | Occupancy Zone 2A | Ventilation Zone 2A
2AS1 | Second Floor | STAIR | 14.4483 | 2AS1 | 13-85 21 11: Stairway | Second Floor | Second Floor | 2.8 | 0 | 15.3236 | 2.8 | 38.2032 | Stairway | 13-85 21 11 | Circulation Zone 2A | Fire Alarm Zone 2A | Historic Preservation Zone 2A | Lighting Zone 2A | Occupancy Zone 2A | Ventilation Zone 2A
2A01 | Second Floor | LIBRARY / CONF. ROOM | 26.331 | 2A01 | 13-11 21 17: Conference Room | Second Floor | Second Floor | 2.8 | 0 | 21.7164 | 2.8 | 69.7917 | Conference Room | 13-11 21 17 | Circulation Zone 2A | Fire Alarm Zone 2A | Historic Preservation Zone 2A | Lighting Zone 2A | Occupancy Zone 2A | Ventilation Zone 2A
2A02 | Second Floor | SUPER OFFICE | 10.8708 | 2A02 | 13-15 11 34 11: Office | Second Floor | Second Floor | 2.8 | 0 | 14.101 | 2.8 | 28.0654 | Office | 13-15 11 34 11 | Circulation Zone 2A | Fire Alarm Zone 2A | Historic Preservation Zone 2A | Lighting Zone 2A | Occupancy Zone 2A | Ventilation Zone 2A
2A03 | Second Floor | SEC. OFFICE | 16.0095 | 2A03 | 13-15 11 34 11: Office | Second Floor | Second Floor | 2.8 | 0 | 16.097 | 2.8 | 41.3804 | Office | 13-15 11 34 11 | Circulation Zone 2A | Fire Alarm Zone 2A | Historic Preservation Zone 2A | Lighting Zone 2A | Occupancy Zone 2A | Ventilation Zone 2A
2A04 | Second Floor | DENTAL SURGEON OFFICE | 16.0139 | 2A04 | 13-15 11 34 11: Office | Second Floor | Second Floor | 2.8 | 0 | 16.099 | 2.8 | 41.8098 | Office | 13-15 11 34 11 | Circulation Zone 2A | Fire Alarm Zone 2A | Historic Preservation Zone 2A | Lighting Zone 2A | Occupancy Zone 2A | Ventilation Zone 2A
2A10 | Second Floor | DENTAL WAITING | 7.85686 | 2A10 | 13-51 31 11: Waiting Room | Second Floor | Second Floor | 2.8 | 0 | 10.8741 | 2.8 | 20.4537 | Waiting Room | 13-51 31 11 | Circulation Zone 2A | Fire Alarm Zone 2A | Historic Preservation Zone 2A | Lighting Zone 2A | Occupancy Zone 2A | Ventilation Zone 2A
2A11 | Second Floor | DENTAL WAITING | 33.4834 | 2A11 | 13-51 31 11: Waiting Room | Second Floor | Second Floor | 2.8 | 0 | 29.0513 | 2.8 | 88.9215 | Waiting Room | 13-51 31 11 | Circulation Zone 2A | Fire Alarm Zone 2A | Historic Preservation Zone 2A | Lighting Zone 2A | Occupancy Zone 2A | Ventilation Zone 2A
2A12-A | Second Floor | X-RAY ALCOVE | 2.28699 | 2A12-A | 13-41 41 31: Scanning/Imaging Room | Second Floor | Second Floor | 2.8 | 0 | 5.62774 | 2.8 | 5.58762 | Scanning/Imaging Room | 13-41 41 31 | Circulation Zone 2A | Fire Alarm Zone 2A | Historic Preservation Zone 2A | Lighting Zone 2A | Occupancy Zone 2A | Ventilation Zone 2A
2A14 | Second Floor | ADMIN | 32.8384 | 2A14 | 13-15 11 34 11: Office | Second Floor | Second Floor | 2.8 | 0 | 24.7893 | 2.8 | 88.1956 | Office | 13-15 11 34 11 | Circulation Zone 2A | Fire Alarm Zone 2A | Historic Preservation Zone 2A | Lighting Zone 2A | Occupancy Zone 2A | Ventilation Zone 2A
2C01 | Second Floor | DTR SUPPORT | 8.72505 | 2C01 | 13-15 11 34 11: Office | Second Floor | Second Floor | 2.8 | 0 | 11.958 | 2.8 | 22.7232 | Office | 13-15 11 34 11 | Circulation Zone 2C | Fire Alarm Zone 2C | Historic Preservation Zone 2C | Lighting Zone 2C | Occupancy Zone 2C | Ventilation Zone 2C
2C03 | Second Floor | CONSULT. | 33.4926 | 2C03 | 13-41 41 99: Other Healing Spaces | Second Floor | Second Floor | 2.8 | 0 | 28.4362 | 2.8 | 89.4233 | Other Healing Spaces | 13-41 41 99 | Circulation Zone 2C | Fire Alarm Zone 2C | Historic Preservation Zone 2C | Lighting Zone 2C | Occupancy Zone 2C | Ventilation Zone 2C
2C05 | Second Floor | JAN. CL. | 3.69253 | 2C05 | 13-75 11 11: Storage Room | Second Floor | Second Floor | 2.8 | 0 | 8.264 | 2.8 | 9.06385 | Storage Room | 13-75 11 11 | Circulation Zone 2C | Fire Alarm Zone 2C | Historic Preservation Zone 2C | Lighting Zone 2C | Occupancy Zone 2C | Ventilation Zone 2C
2C11 | Second Floor | HK | 5.0922 | 2C11 | 13-41 41 99: Other Healing Spaces | Second Floor | Second Floor | 2.8 | 0 | 9.49 | 2.8 | 12.8023 | Other Healing Spaces | 13-41 41 99 | Circulation Zone 2C | Fire Alarm Zone 2C | Historic Preservation Zone 2C | Lighting Zone 2C | Occupancy Zone 2C | Ventilation Zone 2C
2C13 | Second Floor | TRASH | 5.53953 | 2C13 | 13-75 41 14: Soiled Storage Room Space | Second Floor | Second Floor | 2.8 | 0 | 10.182 | 2.8 | 13.9686 | Soiled Storage Room Space | 13-75 41 14 | Circulation Zone 2C | Fire Alarm Zone 2C | Historic Preservation Zone 2C | Lighting Zone 2C | Occupancy Zone 2C | Ventilation Zone 2C
2C15 | Second Floor | COMM. ROOM | 9.58001 | 2C15 | 13-15 11 34 11: Office | Second Floor | Second Floor | 2.8 | 0 | 12.53 | 2.8 | 24.7051 | Office | 13-15 11 34 11 | Circulation Zone 2C | Fire Alarm Zone 2C | Historic Preservation Zone 2C | Lighting Zone 2C | Occupancy Zone 2C | Ventilation Zone 2C
2C18 | Second Floor | ELECTRICAL | 9.84 | 2C18 | 13-81 21 21: Electrical Room | Second Floor | Second Floor | 2.8 | 0 | 12.56 | 2.8 | 25.4146 | Electrical Room | 13-81 21 21 | Circulation Zone 2C | Fire Alarm Zone 2C | Historic Preservation Zone 2C | Lighting Zone 2C | Occupancy Zone 2C | Ventilation Zone 2C
2C19 | Second Floor | CENTRAL ISSUE | 21.0386 | 2C19 | 13-75 11 11: Storage Room | Second Floor | Second Floor | 2.8 | 0 | 19.886 | 2.8 | 55.4459 | Storage Room | 13-75 11 11 | Circulation Zone 2C | Fire Alarm Zone 2C | Historic Preservation Zone 2C | Lighting Zone 2C | Occupancy Zone 2C | Ventilation Zone 2C
2CC1 | Second Floor | CORRIDOR | 18.813 | 2CC1 | 13-85 11 11: Corridor | Second Floor | Second Floor | 2.8 | 0 | 23.5826 | 2.8 | 48.7709 | Corridor | 13-85 11 11 | Circulation Zone 2C | Fire Alarm Zone 2C | Historic Preservation Zone 2C | Lighting Zone 2C | Occupancy Zone 2C | Ventilation Zone 2C
2CC3 | Second Floor | CORRIDOR | 17.2506 | 2CC3 | 13-85 11 11: Corridor | Second Floor | Second Floor | 2.8 | 0 | 22.3132 | 2.8 | 45.0359 | Corridor | 13-85 11 11 | Circulation Zone 2C | Fire Alarm Zone 2C | Historic Preservation Zone 2C | Lighting Zone 2C | Occupancy Zone 2C | Ventilation Zone 2C
2CC4 | Second Floor | CORRIDOR | 10.846 | 2CC4 | 13-85 11 11: Corridor | Second Floor | Second Floor | 2.8 | 0 | 14.568 | 2.8 | 28.1375 | Corridor | 13-85 11 11 | Circulation Zone 2C | Fire Alarm Zone 2C | Historic Preservation Zone 2C | Lighting Zone 2C | Occupancy Zone 2C | Ventilation Zone 2C
2CC2 | Second Floor | CORRIDOR | 13.3735 | 2CC2 | 13-85 11 11: Corridor | Second Floor | Second Floor | 2.8 | 0 | 18.1884 | 2.8 | 34.7761 | Corridor | 13-85 11 11 | Circulation Zone 2C | Fire Alarm Zone 2C | Historic Preservation Zone 2C | Lighting Zone 2C | Occupancy Zone 2C | Ventilation Zone 2C
2D01 | Second Floor | PARTS STORAGE | 8.92422 | 2D01 | 13-75 11 11: Storage Room | Second Floor | Second Floor | 2.8 | 0 | 12.352 | 2.8 | 23.1004 | Storage Room | 13-75 11 11 | Circulation Zone 2D | Fire Alarm Zone 2D | Historic Preservation Zone 2D | Lighting Zone 2D | Occupancy Zone 2D | Ventilation Zone 2D
2D02 | Second Floor | DATA / ARCHIVE STORAGE | 9.92268 | 2D02 | 13-75 11 11: Storage Room | Second Floor | Second Floor | 2.8 | 0 | 12.868 | 2.8 | 25.8318 | Storage Room | 13-75 11 11 | Circulation Zone 2D | Fire Alarm Zone 2D | Historic Preservation Zone 2D | Lighting Zone 2D | Occupancy Zone 2D | Ventilation Zone 2D
2D03 | Second Floor | DIR. INFO MGR | 9.4116 | 2D03 | 13-15 11 34 11: Office | Second Floor | Second Floor | 2.8 | 0 | 12.5175 | 2.8 | 24.4264 | Office | 13-15 11 34 11 | Circulation Zone 2D | Fire Alarm Zone 2D | Historic Preservation Zone 2D | Lighting Zone 2D | Occupancy Zone 2D | Ventilation Zone 2D
2D04 | Second Floor | SYS. ANALYST | 20.7007 | 2D04 | 13-15 11 34 11: Office | Second Floor | Second Floor | 2.8 | 0 | 19.9515 | 2.8 | 54.4353 | Office | 13-15 11 34 11 | Circulation Zone 2D | Fire Alarm Zone 2D | Historic Preservation Zone 2D | Lighting Zone 2D | Occupancy Zone 2D | Ventilation Zone 2D
2D06 | Second Floor | COPY / FILE | 11.9777 | 2D06 | 13-15 11 34 27: Copy Room | Second Floor | Second Floor | 2.8 | 0 | 14.02 | 2.8 | 31.2346 | Copy Room | 13-15 11 34 27 | Circulation Zone 2D | Fire Alarm Zone 2D | Historic Preservation Zone 2D | Lighting Zone 2D | Occupancy Zone 2D | Ventilation Zone 2D
2D07 | Second Floor | SUPER | 9.21541 | 2D07 | 13-15 11 34 11: Office | Second Floor | Second Floor | 2.8 | 0 | 12.135 | 2.8 | 23.7885 | Office | 13-15 11 34 11 | Circulation Zone 2D | Fire Alarm Zone 2D | Historic Preservation Zone 2D | Lighting Zone 2D | Occupancy Zone 2D | Ventilation Zone 2D
2D08 | Second Floor | QA / HRD DIRECTOR | 8.98396 | 2D08 | 13-15 11 34 11: Office | Second Floor | Second Floor | 2.8 | 0 | 12.282 | 2.8 | 23.1926 | Office | 13-15 11 34 11 | Circulation Zone 2D | Fire Alarm Zone 2D | Historic Preservation Zone 2D | Lighting Zone 2D | Occupancy Zone 2D | Ventilation Zone 2D
2D09 | Second Floor | ADMIN OFFICE | 14.3932 | 2D09 | 13-15 11 34 11: Office | Second Floor | Second Floor | 2.8 | 0 | 15.445 | 2.8 | 37.2826 | Office | 13-15 11 34 11 | Circulation Zone 2D | Fire Alarm Zone 2D | Historic Preservation Zone 2D | Lighting Zone 2D | Occupancy Zone 2D | Ventilation Zone 2D
2D10 | Second Floor | SEC. WAIT | 16.632 | 2D10 | 13-51 31 11: Waiting Room | Second Floor | Second Floor | 2.8 | 0 | 17.017 | 2.8 | 43.8585 | Waiting Room | 13-51 31 11 | Circulation Zone 2D | Fire Alarm Zone 2D | Historic Preservation Zone 2D | Lighting Zone 2D | Occupancy Zone 2D | Ventilation Zone 2D
2D11 | Second Floor | CMDR OFFICE | 15.8554 | 2D11 | 13-15 11 34 11: Office | Second Floor | Second Floor | 2.8 | 0 | 16.0179 | 2.8 | 40.5592 | Office | 13-15 11 34 11 | Circulation Zone 2D | Fire Alarm Zone 2D | Historic Preservation Zone 2D | Lighting Zone 2D | Occupancy Zone 2D | Ventilation Zone 2D
2D12 | Second Floor | VEST. | 2.79678 | 2D12 | 13-85 31 11: Entry Vestibule | Second Floor | Second Floor | 2.8 | 0 | 6.5021 | 2.8 | 6.51539 | Entry Vestibule | 13-85 31 11 | Circulation Zone 2D | Fire Alarm Zone 2D | Historic Preservation Zone 2D | Lighting Zone 2D | Occupancy Zone 2D | Ventilation Zone 2D
2D14 | Second Floor | OPS SQUAD CMDR | 13.6001 | 2D14 | 13-15 11 34 11: Office | Second Floor | Second Floor | 2.8 | 0 | 15.4428 | 2.8 | 35.602 | Office | 13-15 11 34 11 | Circulation Zone 2D | Fire Alarm Zone 2D | Historic Preservation Zone 2D | Lighting Zone 2D | Occupancy Zone 2D | Ventilation Zone 2D
2D15 | Second Floor | 1ST SGT | 10.8297 | 2D15 | 13-15 11 34 11: Office | Second Floor | Second Floor | 2.8 | 0 | 13.588 | 2.8 | 27.7911 | Office | 13-15 11 34 11 | Circulation Zone 2D | Fire Alarm Zone 2D | Historic Preservation Zone 2D | Lighting Zone 2D | Occupancy Zone 2D | Ventilation Zone 2D
2D16 | Second Floor | RMO DIR. | 9.75054 | 2D16 | 13-15 11 34 11: Office | Second Floor | Second Floor | 2.8 | 0 | 13.1899 | 2.8 | 25.1084 | Office | 13-15 11 34 11 | Circulation Zone 2D | Fire Alarm Zone 2D | Historic Preservation Zone 2D | Lighting Zone 2D | Occupancy Zone 2D | Ventilation Zone 2D
2D17 | Second Floor | CREDENTIALS MGR | 9.64538 | 2D17 | 13-15 11 34 11: Office | Second Floor | Second Floor | 2.8 | 0 | 12.7579 | 2.8 | 24.3537 | Office | 13-15 11 34 11 | Circulation Zone 2D | Fire Alarm Zone 2D | Historic Preservation Zone 2D | Lighting Zone 2D | Occupancy Zone 2D | Ventilation Zone 2D
2D19 | Second Floor | READINESS NCOIC OFFICE | 10.9078 | 2D19 | 13-15 11 34 11: Office | Second Floor | Second Floor | 2.8 | 0 | 13.5279 | 2.8 | 27.9061 | Office | 13-15 11 34 11 | Circulation Zone 2D | Fire Alarm Zone 2D | Historic Preservation Zone 2D | Lighting Zone 2D | Occupancy Zone 2D | Ventilation Zone 2D
2D20 | Second Floor | CONF. ROOM | 30.712 | 2D20 | 13-11 21 17: Conference Room | Second Floor | Second Floor | 2.8 | 0 | 22.3024 | 2.8 | 82.195 | Conference Room | 13-11 21 17 | Circulation Zone 2D | Fire Alarm Zone 2D | Historic Preservation Zone 2D | Lighting Zone 2D | Occupancy Zone 2D | Ventilation Zone 2D
2D04A | Second Floor | COMPUTER ROOM | 33.5478 | 2D04A | 13-15 11 34 11: Office | Second Floor | Second Floor | 2.8 | 0 | 23.6075 | 2.8 | 89.8254 | Office | 13-15 11 34 11 | Circulation Zone 2D | Fire Alarm Zone 2D | Historic Preservation Zone 2D | Lighting Zone 2D | Occupancy Zone 2D | Ventilation Zone 2D
2DC2 | Second Floor | CORRIDOR | 30.1132 | 2DC2 | 13-85 11 11: Corridor | Second Floor | Second Floor | 2.8 | 0 | 36.3978 | 2.8 | 79.4525 | Corridor | 13-85 11 11 | Circulation Zone 2D | Fire Alarm Zone 2D | Historic Preservation Zone 2D | Lighting Zone 2D | Occupancy Zone 2D | Ventilation Zone 2D
2BC1 | Second Floor | CORRIDOR | 12.8241 | 2BC1 | 13-85 11 11: Corridor | Second Floor | Second Floor | 2.8 | 0 | 15.4512 | 2.8 | 34.0216 | Corridor | 13-85 11 11 | Circulation Zone 2B | Fire Alarm Zone 2B | Historic Preservation Zone 2B | Lighting Zone 2B | Occupancy Zone 2B | Ventilation Zone 2B
2BC2 | Second Floor | CORRIDOR | 29.512 | 2BC2 | 13-85 11 11: Corridor | Second Floor | Second Floor | 2.8 | 0 | 32.1099 | 2.8 | 77.2557 | Corridor | 13-85 11 11 | Circulation Zone 2B | Fire Alarm Zone 2B | Historic Preservation Zone 2B | Lighting Zone 2B | Occupancy Zone 2B | Ventilation Zone 2B
2BC3 | Second Floor | CORRIDOR | 26.8 | 2BC3 | 13-85 11 11: Corridor | Second Floor | Second Floor | 2.8 | 0 | 32.8839 | 2.8 | 69.7845 | Corridor | 13-85 11 11 | Circulation Zone 2B | Fire Alarm Zone 2B | Historic Preservation Zone 2B | Lighting Zone 2B | Occupancy Zone 2B | Ventilation Zone 2B
2BC4 | Second Floor | CORRIDOR | 12.4825 | 2BC4 | 13-85 11 11: Corridor | Second Floor | Second Floor | 2.8 | 0 | 16.6806 | 2.8 | 32.3314 | Corridor | 13-85 11 11 | Circulation Zone 2B | Fire Alarm Zone 2B | Historic Preservation Zone 2B | Lighting Zone 2B | Occupancy Zone 2B | Ventilation Zone 2B
2BC5 | Second Floor | CORRIDOR | 22.7376 | 2BC5 | 13-85 11 11: Corridor | Second Floor | Second Floor | 2.8 | 0 | 29.2148 | 2.8 | 58.6367 | Corridor | 13-85 11 11 | Circulation Zone 2B | Fire Alarm Zone 2B | Historic Preservation Zone 2B | Lighting Zone 2B | Occupancy Zone 2B | Ventilation Zone 2B
2BC6 | Second Floor | CORRIDOR | 8.57508 | 2BC6 | 13-85 11 11: Corridor | Second Floor | Second Floor | 2.8 | 0 | 12.7244 | 2.8 | 22.3116 | Corridor | 13-85 11 11 | Circulation Zone 2B | Fire Alarm Zone 2B | Historic Preservation Zone 2B | Lighting Zone 2B | Occupancy Zone 2B | Ventilation Zone 2B
2B01 | Second Floor | OFFICE | 9.36297 | 2B01 | 13-15 11 34 11: Office | Second Floor | Second Floor | 2.8 | 0 | 12.861 | 2.8 | 24.0738 | Office | 13-15 11 34 11 | Circulation Zone 2B | Fire Alarm Zone 2B | Historic Preservation Zone 2B | Lighting Zone 2B | Occupancy Zone 2B | Ventilation Zone 2B
2B2 | Second Floor | JAN. CL. | 2.20008 | 2B2 | 13-75 11 11: Storage Room | Second Floor | Second Floor | 2.8 | 0 | 5.938 | 2.8 | 5.29984 | Storage Room | 13-75 11 11 | Circulation Zone 2B | Fire Alarm Zone 2B | Historic Preservation Zone 2B | Lighting Zone 2B | Occupancy Zone 2B | Ventilation Zone 2B
2B3 | Second Floor | CONF. / GROUP THERAPY | 24.5482 | 2B3 | 13-11 21 17: Conference Room | Second Floor | Second Floor | 2.8 | 0 | 28.9479 | 2.8 | 63.2337 | Conference Room | 13-11 21 17 | Circulation Zone 2B | Fire Alarm Zone 2B | Historic Preservation Zone 2B | Lighting Zone 2B | Occupancy Zone 2B | Ventilation Zone 2B
2B4 | Second Floor | PSYCH TEST | 9.8406 | 2B4 | 13-15 11 34 11: Office | Second Floor | Second Floor | 2.8 | 0 | 12.61 | 2.8 | 25.6738 | Office | 13-15 11 34 11 | Circulation Zone 2B | Fire Alarm Zone 2B | Historic Preservation Zone 2B | Lighting Zone 2B | Occupancy Zone 2B | Ventilation Zone 2B
2B7 | Second Floor | TECH OFFICE | 9.9308 | 2B7 | 13-15 11 34 11: Office | Second Floor | Second Floor | 2.8 | 0 | 12.685 | 2.8 | 25.8629 | Office | 13-15 11 34 11 | Circulation Zone 2B | Fire Alarm Zone 2B | Historic Preservation Zone 2B | Lighting Zone 2B | Occupancy Zone 2B | Ventilation Zone 2B
2B8 | Second Floor | OFFICE / EXAM | 12.6405 | 2B8 | 13-15 11 34 11: Office | Second Floor | Second Floor | 2.8 | 0 | 14.84 | 2.8 | 32.8602 | Office | 13-15 11 34 11 | Circulation Zone 2B | Fire Alarm Zone 2B | Historic Preservation Zone 2B | Lighting Zone 2B | Occupancy Zone 2B | Ventilation Zone 2B
2B9 | Second Floor | TECH OFFICE | 9.94 | 2B9 | 13-15 11 34 11: Office | Second Floor | Second Floor | 2.8 | 0 | 12.68 | 2.8 | 25.6738 | Office | 13-15 11 34 11 | Circulation Zone 2B | Fire Alarm Zone 2B | Historic Preservation Zone 2B | Lighting Zone 2B | Occupancy Zone 2B | Ventilation Zone 2B
2B10 | Second Floor | RECEPTION | 15.1738 | 2B10 | 13-11 11 31: Reception Space | Second Floor | Second Floor | 2.8 | 0 | 16.625 | 2.8 | 39.7081 | Reception Space | 13-11 11 31 | Circulation Zone 2B | Fire Alarm Zone 2B | Historic Preservation Zone 2B | Lighting Zone 2B | Occupancy Zone 2B | Ventilation Zone 2B
2B11 | Second Floor | WAITING | 10.1069 | 2B11 | 13-51 31 11: Waiting Room | Second Floor | Second Floor | 2.8 | 0 | 12.908 | 2.8 | 26.6698 | Waiting Room | 13-51 31 11 | Circulation Zone 2B | Fire Alarm Zone 2B | Historic Preservation Zone 2B | Lighting Zone 2B | Occupancy Zone 2B | Ventilation Zone 2B
2B12 | Second Floor | COMM. ROOM | 9.92484 | 2B12 | 13-15 11 34 11: Office | Second Floor | Second Floor | 2.8 | 0 | 13.085 | 2.8 | 25.5702 | Office | 13-15 11 34 11 | Circulation Zone 2B | Fire Alarm Zone 2B | Historic Preservation Zone 2B | Lighting Zone 2B | Occupancy Zone 2B | Ventilation Zone 2B
2B13 | Second Floor | ELECTRICAL | 9.68587 | 2B13 | 13-81 21 21: Electrical Room | Second Floor | Second Floor | 2.8 | 0 | 12.977 | 2.8 | 24.9321 | Electrical Room | 13-81 21 21 | Circulation Zone 2B | Fire Alarm Zone 2B | Historic Preservation Zone 2B | Lighting Zone 2B | Occupancy Zone 2B | Ventilation Zone 2B
2B14 | Second Floor | RECS / FORMS STORAGE | 10.5466 | 2B14 | 13-75 11 11: Storage Room | Second Floor | Second Floor | 2.8 | 0 | 13.604 | 2.8 | 27.3185 | Storage Room | 13-75 11 11 | Circulation Zone 2B | Fire Alarm Zone 2B | Historic Preservation Zone 2B | Lighting Zone 2B | Occupancy Zone 2B | Ventilation Zone 2B
2B15 | Second Floor | WAIT / ERGOM | 9.11758 | 2B15 | 13-51 31 11: Waiting Room | Second Floor | Second Floor | 2.8 | 0 | 12.24 | 2.8 | 23.4474 | Waiting Room | 13-51 31 11 | Circulation Zone 2B | Fire Alarm Zone 2B | Historic Preservation Zone 2B | Lighting Zone 2B | Occupancy Zone 2B | Ventilation Zone 2B
2B16 | Second Floor | PH TECH | 9.51632 | 2B16 | 13-15 11 34 11: Office | Second Floor | Second Floor | 2.8 | 0 | 12.357 | 2.8 | 23.917 | Office | 13-15 11 34 11 | Circulation Zone 2B | Fire Alarm Zone 2B | Historic Preservation Zone 2B | Lighting Zone 2B | Occupancy Zone 2B | Ventilation Zone 2B
2B18 | Second Floor | PH TECH | 9.52429 | 2B18 | 13-15 11 34 11: Office | Second Floor | Second Floor | 2.8 | 0 | 13.8569 | 2.8 | 24.248 | Office | 13-15 11 34 11 | Circulation Zone 2B | Fire Alarm Zone 2B | Historic Preservation Zone 2B | Lighting Zone 2B | Occupancy Zone 2B | Ventilation Zone 2B
2B19 | Second Floor | OFFICE | 8.87578 | 2B19 | 13-15 11 34 11: Office | Second Floor | Second Floor | 2.8 | 0 | 12.104 | 2.8 | 22.794 | Office | 13-15 11 34 11 | Circulation Zone 2B | Fire Alarm Zone 2B | Historic Preservation Zone 2B | Lighting Zone 2B | Occupancy Zone 2B | Ventilation Zone 2B
2B20 | Second Floor | JAN. CL. | 3.23618 | 2B20 | 13-75 11 11: Storage Room | Second Floor | Second Floor | 2.8 | 0 | 7.53312 | 2.8 | 7.91441 | Storage Room | 13-75 11 11 | Circulation Zone 2B | Fire Alarm Zone 2B | Historic Preservation Zone 2B | Lighting Zone 2B | Occupancy Zone 2B | Ventilation Zone 2B
2B21 | Second Floor | PH SUPER | 9.25086 | 2B21 | 13-15 11 34 11: Office | Second Floor | Second Floor | 2.8 | 0 | 12.5366 | 2.8 | 23.6268 | Office | 13-15 11 34 11 | Circulation Zone 2B | Fire Alarm Zone 2B | Historic Preservation Zone 2B | Lighting Zone 2B | Occupancy Zone 2B | Ventilation Zone 2B
2B23 | Second Floor | BEE TECH | 10.7975 | 2B23 | 13-15 11 34 11: Office | Second Floor | Second Floor | 2.8 | 0 | 13.226 | 2.8 | 27.7575 | Office | 13-15 11 34 11 | Circulation Zone 2B | Fire Alarm Zone 2B | Historic Preservation Zone 2B | Lighting Zone 2B | Occupancy Zone 2B | Ventilation Zone 2B
2B24 | Second Floor | BEE TECH | 9.77601 | 2B24 | 13-15 11 34 11: Office | Second Floor | Second Floor | 2.8 | 0 | 12.67 | 2.8 | 24.7086 | Office | 13-15 11 34 11 | Circulation Zone 2B | Fire Alarm Zone 2B | Historic Preservation Zone 2B | Lighting Zone 2B | Occupancy Zone 2B | Ventilation Zone 2B
2B25 | Second Floor | SOIL. UTL. / TRASH | 7.46369 | 2B25 | 13-75 41 14: Soiled Storage Room Space | Second Floor | Second Floor | 2.8 | 0 | 13.21 | 2.8 | 18.8314 | Soiled Storage Room Space | 13-75 41 14 | Circulation Zone 2B | Fire Alarm Zone 2B | Historic Preservation Zone 2B | Lighting Zone 2B | Occupancy Zone 2B | Ventilation Zone 2B
2BS2 | Second Floor | STAIR | 15.4516 | 2BS2 | 13-85 21 11: Stairway | Second Floor | Second Floor | 2.8 | 0 | 17.332 | 2.8 | 40.2986 | Stairway | 13-85 21 11 | Circulation Zone 2B | Fire Alarm Zone 2B | Historic Preservation Zone 2B | Lighting Zone 2B | Occupancy Zone 2B | Ventilation Zone 2B
2CS3 | Second Floor | STAIR | 15.2659 | 2CS3 | 13-85 21 11: Stairway | Second Floor | Second Floor | 2.8 | 0 | 17.368 | 2.8 | 39.7725 | Stairway | 13-85 21 11 | Circulation Zone 2C | Fire Alarm Zone 2C | Historic Preservation Zone 2C | Lighting Zone 2C | Occupancy Zone 2C | Ventilation Zone 2C
2AC1-A | Second Floor | OPEN TO BELOW | 67.4123 | 2AC1-A | 13-85 31 99: Other Transitional Circulation Spaces | Second Floor | Second Floor | 2.8 | 0 | 37.7705 | 2.8 | 183.363 | Other Transitional Circulation Spaces | 13-85 31 99 | Circulation Zone 2A | Fire Alarm Zone 2A | Historic Preservation Zone 2A | Lighting Zone 2A | Occupancy Zone 2A | Ventilation Zone 2A
2AC1-B | Second Floor | OPEN TO BELOW | 75.807 | 2AC1-B | 13-85 31 99: Other Transitional Circulation Spaces | Second Floor | Roof - Main | 0 | 0 | 35.407 | 4.68 | 348.032 | Other Transitional Circulation Spaces | 13-85 31 99 | Circulation Zone 2A | Fire Alarm Zone 2A | Historic Preservation Zone 2A | Lighting Zone 2A | Occupancy Zone 2A | Ventilation Zone 2A
3D01 | Roof - Main | MECH. PENTHOUSE | 64.8322 | 3D01 | 13-81 21 17: Mechanical Room | Roof - Main | Roof - Main | 3.4 | 0 | 35.3365 | 3.4 | 206.555 | Mechanical Room | 13-81 21 17 | Circulation Zone 2D | Fire Alarm Zone 2D | Historic Preservation Zone 2D | Lighting Zone 2D | Occupancy Zone 2D | Ventilation Zone 2D
3AC1 | Roof - Main | OPEN TO BELOW | 99.1595 | 3AC1 | 13-85 31 99: Other Transitional Circulation Spaces | Roof - Main | Roof - Main | 3.4 | 0 | 40.4838 | 3.4 | 324.616 | Other Transitional Circulation Spaces | 13-85 31 99 | Circulation Zone 2D | Fire Alarm Zone 2D | Historic Preservation Zone 2D | Lighting Zone 2D | Occupancy Zone 2D | Ventilation Zone 2D
2CC5 | Second Floor | CORRIDOR | 8.1288 | 2CC5 | 13-85 11 11: Corridor | Second Floor | Second Floor | 4 | 0 | 12.632 | 4 | 29.6709 | Corridor | 13-85 11 11 | Circulation Zone 2C | Fire Alarm Zone 2C | Historic Preservation Zone 2C | Lighting Zone 2C | Occupancy Zone 2C | Ventilation Zone 2C
2D21 | Second Floor | LIBRARY / CLASSROOM | 27.3034 | 2D21 | 13-11 11 17: Classroom | Second Floor | Second Floor | 4 | 0 | 21.2805 | 4 | 105.77 | Classroom | 13-11 11 17 | Circulation Zone 2D | Fire Alarm Zone 2D | Historic Preservation Zone 2D | Lighting Zone 2D | Occupancy Zone 2D | Ventilation Zone 2D
1F01 | First Floor | MECH. YARD | 80.0652 | 1F01 | 13-81 21 11: Equipment Room | First Floor | Second Floor | 0 | -1 | 35.8195 | 5.57 | 439.567 | Equipment Room | 13-81 21 11 | Circulation Zone 1F | Fire Alarm Zone 1F | Historic Preservation Zone 1F | Lighting Zone 1F | Occupancy Zone 1F | Ventilation Zone 1F
2R02 | Second Floor | ROOF | 589.756 | 2R02 | 13-81 11 99: Other General Facility Service Spaces | Second Floor | Second Floor | 4 | 0 | 194.084 | 4 | 2314.97 | Other General Facility Service Spaces | 13-81 11 99 | Circulation Zone 2R | Fire Alarm Zone 2R | Historic Preservation Zone 2R | Lighting Zone 2R | Occupancy Zone 2R | Ventilation Zone 2R
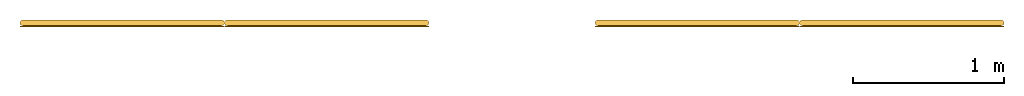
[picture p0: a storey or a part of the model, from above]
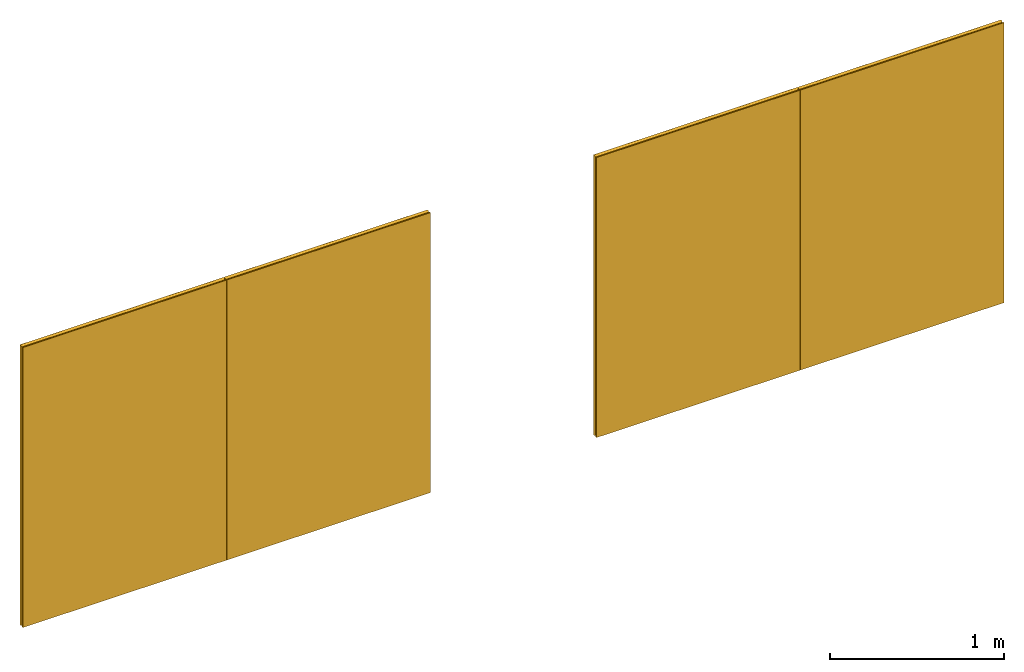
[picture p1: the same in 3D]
Properties of the parts of a building model (IFC2X3), part 2 of 11

# IfcSpace (269)
Name | In | LongName = Name | GSA BIM Area (m2) = Area (m2) | Number | OmniClass Table 13 Category | Level | Upper Limit | Limit Offset (m) | Base Offset (m) | Perimeter (m) | Unbounded Height (m) | Volume (m3) | Category Description | Category Code | CirculationZoneName | FireAlarmZoneName | HistoricPreservationZoneName | LightingZoneName | OccupancyZoneName | VentilationZoneName
2R01 | Second Floor | ROOF | 52.8728 | 2R01 | 13-81 11 99: Other General Facility Service Spaces | Second Floor | Second Floor | 4 | 0 | 29.706 | 4 | 203.631 | Other General Facility Service Spaces | 13-81 11 99 | Circulation Zone 2R | Fire Alarm Zone 2R | Historic Preservation Zone 2R | Lighting Zone 2R | Occupancy Zone 2R | Ventilation Zone 2R
3R01 | Roof - Main | ROOF | 1568.12 | 3R01 | 13-81 11 99: Other General Facility Service Spaces | Roof - Main | Roof - Main | 4 | 0 | 277.051 | 4 | 6257.34 | Other General Facility Service Spaces | 13-81 11 99 | Circulation Zone 3R | Fire Alarm Zone 3R | Historic Preservation Zone 3R | Lighting Zone 3R | Occupancy Zone 3R | Ventilation Zone 3R
3R02 | Roof - Main | ROOF | 15.1699 | 3R02 | 13-81 11 99: Other General Facility Service Spaces | Roof - Main | Roof - Main | 4 | -1.2 | 32.1464 | 5.2 | 77.0714 | Other General Facility Service Spaces | 13-81 11 99 | Circulation Zone 3R | Fire Alarm Zone 3R | Historic Preservation Zone 3R | Lighting Zone 3R | Occupancy Zone 3R | Ventilation Zone 3R
3R04 | Roof - Main | ROOF | 15.1622 | 3R04 | 13-81 11 99: Other General Facility Service Spaces | Roof - Main | Roof - Main | 4 | -1.2 | 32.1454 | 5.2 | 77.0318 | Other General Facility Service Spaces | 13-81 11 99 | Circulation Zone 3R | Fire Alarm Zone 3R | Historic Preservation Zone 3R | Lighting Zone 3R | Occupancy Zone 3R | Ventilation Zone 3R
3R03 | Roof - Main | ROOF | 58.0851 | 3R03 | 13-81 11 99: Other General Facility Service Spaces | Roof - Main | Roof - Main | 4 | -2.48688 | 30.3788 | 6.48688 | 376.329 | Other General Facility Service Spaces | 13-81 11 99 | Circulation Zone 3R | Fire Alarm Zone 3R | Historic Preservation Zone 3R | Lighting Zone 3R | Occupancy Zone 3R | Ventilation Zone 3R
E1 | First Floor | ELEVATOR | 4.35577 | E1 | 13-81 21 31: Elevator Shaft | First Floor | Roof - Main | 0 | 0 | 8.4154 | 9.25 | 36.1313 | Elevator Shaft | 13-81 21 31 | Circulation Zone 1B | Fire Alarm Zone 1B | Historic Preservation Zone 1B | Lighting Zone 1B | Occupancy Zone 1B | Ventilation Zone 1B
1D06 | First Floor | SCOPE WASH / DECON. | 8.99752 | 1D06 | 13-41 11 99: Other Grooming Spaces | First Floor | First Floor | 2.8 | 0 | 12.507 | 2.8 | 23.2834 | Other Grooming Spaces | 13-41 11 99 | Circulation Zone 1D | Fire Alarm Zone 1D | Historic Preservation Zone 1D | Lighting Zone 1D | Occupancy Zone 1D | Ventilation Zone 1D
1D40 | First Floor | IMMUNIZ'N ROOM | 16.5524 | 1D40 | 13-41 41 99: Other Healing Spaces | First Floor | First Floor | 2.8 | 0 | 19.222 | 2.8 | 43.1197 | Other Healing Spaces | 13-41 41 99 | Circulation Zone 1D | Fire Alarm Zone 1D | Historic Preservation Zone 1D | Lighting Zone 1D | Occupancy Zone 1D | Ventilation Zone 1D
1E04 | First Floor | HK BREAK ROOM | 9.73544 | 1E04 | 13-51 11 21: Break Room | First Floor | First Floor | 2.8 | 0 | 12.492 | 2.8 | 25.1337 | Break Room | 13-51 11 21 | Circulation Zone 1E | Fire Alarm Zone 1E | Historic Preservation Zone 1E | Lighting Zone 1E | Occupancy Zone 1E | Ventilation Zone 1E
1E11 | First Floor | STAFF LOUNGE | 14.5917 | 1E11 | 13-51 11 21: Break Room | First Floor | First Floor | 2.8 | 0 | 15.28 | 2.8 | 38.2473 | Break Room | 13-51 11 21 | Circulation Zone 1E | Fire Alarm Zone 1E | Historic Preservation Zone 1E | Lighting Zone 1E | Occupancy Zone 1E | Ventilation Zone 1E
1E30 | First Floor | SOIL. LIN. | 6.87827 | 1E30 | 13-75 41 14: Soiled Storage Room Space | First Floor | First Floor | 2.8 | 0 | 10.7732 | 2.8 | 17.3789 | Soiled Storage Room Space | 13-75 41 14 | Circulation Zone 1E | Fire Alarm Zone 1E | Historic Preservation Zone 1E | Lighting Zone 1E | Occupancy Zone 1E | Ventilation Zone 1E
1E16 | First Floor | BMET WORK STATION | 49.5978 | 1E16 | 13-15 11 34 11: Office | First Floor | First Floor | 2.8 | 0 | 30.9915 | 2.8 | 130.847 | Office | 13-15 11 34 11 | Circulation Zone 1E | Fire Alarm Zone 1E | Historic Preservation Zone 1E | Lighting Zone 1E | Occupancy Zone 1E | Ventilation Zone 1E
1B10 | First Floor | STAFF LOUNGE | 10.2834 | 1B10 | 13-51 11 21: Break Room | First Floor | First Floor | 2.8 | 0 | 13.649 | 2.8 | 26.3383 | Break Room | 13-51 11 21 | Circulation Zone 1B | Fire Alarm Zone 1B | Historic Preservation Zone 1B | Lighting Zone 1B | Occupancy Zone 1B | Ventilation Zone 1B
1A10 | First Floor | LOUNGE | 10.2725 | 1A10 | 13-51 11 21: Break Room | First Floor | First Floor | 2.8 | 0 | 14.38 | 2.8 | 26.6537 | Break Room | 13-51 11 21 | Circulation Zone 1A | Fire Alarm Zone 1A | Historic Preservation Zone 1A | Lighting Zone 1A | Occupancy Zone 1A | Ventilation Zone 1A
2A13 | Second Floor | DEVELOPING | 7.5623 | 2A13 | 13-41 41 31: Scanning/Imaging Room | Second Floor | Second Floor | 2.8 | 0 | 11.778 | 2.8 | 19.2781 | Scanning/Imaging Room | 13-41 41 31 | Circulation Zone 2A | Fire Alarm Zone 2A | Historic Preservation Zone 2A | Lighting Zone 2A | Occupancy Zone 2A | Ventilation Zone 2A
2A12 | Second Floor | X-RAY | 11.2172 | 2A12 | 13-41 41 31: Scanning/Imaging Room | Second Floor | Second Floor | 2.8 | 0 | 14.3622 | 2.8 | 28.9599 | Scanning/Imaging Room | 13-41 41 31 | Circulation Zone 2A | Fire Alarm Zone 2A | Historic Preservation Zone 2A | Lighting Zone 2A | Occupancy Zone 2A | Ventilation Zone 2A
2B17 | Second Floor | CL. UTL. / KITCHENET | 8.99668 | 2B17 | 13-11 19 11 11: Kitchen | Second Floor | Second Floor | 2.8 | 0 | 12.172 | 2.8 | 23.1207 | Kitchen | 13-11 19 11 11 | Circulation Zone 2B | Fire Alarm Zone 2B | Historic Preservation Zone 2B | Lighting Zone 2B | Occupancy Zone 2B | Ventilation Zone 2B
2C17 | Second Floor | PROSTH. LAB | 30.5599 | 2C17 | 13-15 11 24 11: Laboratory | Second Floor | Second Floor | 2.8 | 0 | 25.496 | 2.8 | 80.0399 | Laboratory | 13-15 11 24 11 | Circulation Zone 2C | Fire Alarm Zone 2C | Historic Preservation Zone 2C | Lighting Zone 2C | Occupancy Zone 2C | Ventilation Zone 2C
2C10 | Second Floor | DIPC DECON | 11.0309 | 2C10 | 13-41 41 99: Other Healing Spaces | Second Floor | Second Floor | 2.8 | 0 | 13.492 | 2.8 | 28.6997 | Other Healing Spaces | 13-41 41 99 | Circulation Zone 2C | Fire Alarm Zone 2C | Historic Preservation Zone 2C | Lighting Zone 2C | Occupancy Zone 2C | Ventilation Zone 2C
1BC2 | First Floor | CORRIDOR | 29.4368 | 1BC2 | 13-85 11 11: Corridor | First Floor | First Floor | 2.8 | 0 | 36.1589 | 2.8 | 76.4885 | Corridor | 13-85 11 11 | Circulation Zone 1B | Fire Alarm Zone 1B | Historic Preservation Zone 1B | Lighting Zone 1B | Occupancy Zone 1B | Ventilation Zone 1B
1AC1 | First Floor | CENTRAL WAITING | 139.755 | 1AC1 | 13-51 31 11: Waiting Room | First Floor | Second Floor | 0 | 0 | 75.3209 | 4.57 | 625.159 | Waiting Room | 13-51 31 11 | Circulation Zone 1A | Fire Alarm Zone 1A | Historic Preservation Zone 1A | Lighting Zone 1A | Occupancy Zone 1A | Ventilation Zone 1A
1AC3 | First Floor | CORRIDOR | 16.2935 | 1AC3 | 13-85 11 11: Corridor | First Floor | First Floor | 2.8 | 0 | 21.4955 | 2.8 | 42.0234 | Corridor | 13-85 11 11 | Circulation Zone 1A | Fire Alarm Zone 1A | Historic Preservation Zone 1A | Lighting Zone 1A | Occupancy Zone 1A | Ventilation Zone 1A
1AC5 | First Floor | CORRIDOR | 20.3751 | 1AC5 | 13-85 11 11: Corridor | First Floor | First Floor | 2.8 | 0 | 32.975 | 2.8 | 53.8137 | Corridor | 13-85 11 11 | Circulation Zone 1A | Fire Alarm Zone 1A | Historic Preservation Zone 1A | Lighting Zone 1A | Occupancy Zone 1A | Ventilation Zone 1A
1D22 | First Floor | TEAM INTERACTION | 24.237 | 1D22 | 13-15 11 34 11: Office | First Floor | First Floor | 2.8 | 0 | 20.765 | 2.8 | 63.1427 | Office | 13-15 11 34 11 | Circulation Zone 1D | Fire Alarm Zone 1D | Historic Preservation Zone 1D | Lighting Zone 1D | Occupancy Zone 1D | Ventilation Zone 1D
1A16 | First Floor | PHARM. DISP. | 67.5491 | 1A16 | 13-75 11 11: Storage Room | First Floor | First Floor | 2.8 | 0 | 42.597 | 2.8 | 182.629 | Storage Room | 13-75 11 11 | Circulation Zone 1A | Fire Alarm Zone 1A | Historic Preservation Zone 1A | Lighting Zone 1A | Occupancy Zone 1A | Ventilation Zone 1A
1AC4 | First Floor | CORRIDOR | 9.55147 | 1AC4 | 13-85 11 11: Corridor | First Floor | First Floor | 2.8 | 0 | 13.7932 | 2.8 | 24.639 | Corridor | 13-85 11 11 | Circulation Zone 1A | Fire Alarm Zone 1A | Historic Preservation Zone 1A | Lighting Zone 1A | Occupancy Zone 1A | Ventilation Zone 1A
2DC1 | Second Floor | CORRIDOR | 21.5518 | 2DC1 | 13-85 11 11: Corridor | Second Floor | Second Floor | 2.8 | 0 | 26.2857 | 2.8 | 56.4026 | Corridor | 13-85 11 11 | Circulation Zone 2D | Fire Alarm Zone 2D | Historic Preservation Zone 2D | Lighting Zone 2D | Occupancy Zone 2D | Ventilation Zone 2D
2D05 | Second Floor | MAIN MECHANICAL ROOM | 231.114 | 2D05 | 13-81 21 17: Mechanical Room | Second Floor | Second Floor | 2.8 | 0 | 65.482 | 2.8 | 632.921 | Mechanical Room | 13-81 21 17 | Circulation Zone 2D | Fire Alarm Zone 2D | Historic Preservation Zone 2D | Lighting Zone 2D | Occupancy Zone 2D | Ventilation Zone 2D
2C22 | Second Floor | LOUNGE | 11.1646 | 2C22 | 13-51 11 21: Break Room | Second Floor | Second Floor | 2.8 | 0 | 13.8043 | 2.8 | 28.9074 | Break Room | 13-51 11 21 | Circulation Zone 2C | Fire Alarm Zone 2C | Historic Preservation Zone 2C | Lighting Zone 2C | Occupancy Zone 2C | Ventilation Zone 2C
1D02 | First Floor | INTERACTION STATION | 11.5298 | 1D02 | 13-41 41 99: Other Healing Spaces | First Floor | First Floor | 2.8 | 0 | 13.802 | 2.8 | 30.0181 | Other Healing Spaces | 13-41 41 99 | Circulation Zone 1D | Fire Alarm Zone 1D | Historic Preservation Zone 1D | Lighting Zone 1D | Occupancy Zone 1D | Ventilation Zone 1D
1D08 | First Floor | INTERACTION STATION | 12.8273 | 1D08 | 13-41 41 99: Other Healing Spaces | First Floor | First Floor | 2.8 | 0 | 14.4329 | 2.8 | 33.4538 | Other Healing Spaces | 13-41 41 99 | Circulation Zone 1D | Fire Alarm Zone 1D | Historic Preservation Zone 1D | Lighting Zone 1D | Occupancy Zone 1D | Ventilation Zone 1D
1D10 | First Floor | INTERACTION STATION | 12.7437 | 1D10 | 13-41 41 99: Other Healing Spaces | First Floor | First Floor | 2.8 | 0 | 14.4329 | 2.8 | 33.2748 | Other Healing Spaces | 13-41 41 99 | Circulation Zone 1D | Fire Alarm Zone 1D | Historic Preservation Zone 1D | Lighting Zone 1D | Occupancy Zone 1D | Ventilation Zone 1D
1D11 | First Floor | INTERACTION STATION | 12.698 | 1D11 | 13-41 41 99: Other Healing Spaces | First Floor | First Floor | 2.8 | 0 | 14.779 | 2.8 | 33.249 | Other Healing Spaces | 13-41 41 99 | Circulation Zone 1D | Fire Alarm Zone 1D | Historic Preservation Zone 1D | Lighting Zone 1D | Occupancy Zone 1D | Ventilation Zone 1D
1D13 | First Floor | INTERACTION STATION | 12.8258 | 1D13 | 13-41 41 99: Other Healing Spaces | First Floor | First Floor | 2.8 | 0 | 14.432 | 2.8 | 33.45 | Other Healing Spaces | 13-41 41 99 | Circulation Zone 1D | Fire Alarm Zone 1D | Historic Preservation Zone 1D | Lighting Zone 1D | Occupancy Zone 1D | Ventilation Zone 1D
1D07 | First Floor | INTERACTION STATION | 12.5663 | 1D07 | 13-41 41 99: Other Healing Spaces | First Floor | First Floor | 2.8 | 0 | 14.397 | 2.8 | 32.8761 | Other Healing Spaces | 13-41 41 99 | Circulation Zone 1D | Fire Alarm Zone 1D | Historic Preservation Zone 1D | Lighting Zone 1D | Occupancy Zone 1D | Ventilation Zone 1D
1D09 | First Floor | INTERACTION STATION | 12.7792 | 1D09 | 13-41 41 99: Other Healing Spaces | First Floor | First Floor | 2.8 | 0 | 14.3048 | 2.8 | 33.45 | Other Healing Spaces | 13-41 41 99 | Circulation Zone 1D | Fire Alarm Zone 1D | Historic Preservation Zone 1D | Lighting Zone 1D | Occupancy Zone 1D | Ventilation Zone 1D
1D05 | First Floor | TRMT RM. DIRTY PROC. | 14.1331 | 1D05 | 13-41 41 11: Treatment Room | First Floor | First Floor | 2.8 | 0 | 15.0667 | 2.8 | 37.6077 | Treatment Room | 13-41 41 11 | Circulation Zone 1D | Fire Alarm Zone 1D | Historic Preservation Zone 1D | Lighting Zone 1D | Occupancy Zone 1D | Ventilation Zone 1D
1D28 | First Floor | INTERACTION STATION | 12.6883 | 1D28 | 13-41 41 99: Other Healing Spaces | First Floor | First Floor | 2.8 | 0 | 14.364 | 2.8 | 33.0766 | Other Healing Spaces | 13-41 41 99 | Circulation Zone 1D | Fire Alarm Zone 1D | Historic Preservation Zone 1D | Lighting Zone 1D | Occupancy Zone 1D | Ventilation Zone 1D
1D32 | First Floor | INTERACTION STATION | 12.7483 | 1D32 | 13-41 41 99: Other Healing Spaces | First Floor | First Floor | 2.8 | 0 | 14.814 | 2.8 | 33.249 | Other Healing Spaces | 13-41 41 99 | Circulation Zone 1D | Fire Alarm Zone 1D | Historic Preservation Zone 1D | Lighting Zone 1D | Occupancy Zone 1D | Ventilation Zone 1D
1D34 | First Floor | INTERACTION STATION | 12.8258 | 1D34 | 13-41 41 99: Other Healing Spaces | First Floor | First Floor | 2.8 | 0 | 14.432 | 2.8 | 33.45 | Other Healing Spaces | 13-41 41 99 | Circulation Zone 1D | Fire Alarm Zone 1D | Historic Preservation Zone 1D | Lighting Zone 1D | Occupancy Zone 1D | Ventilation Zone 1D
1D36 | First Floor | INTERACTION STATION | 12.7053 | 1D36 | 13-41 41 99: Other Healing Spaces | First Floor | First Floor | 2.8 | 0 | 14.432 | 2.8 | 33.1896 | Other Healing Spaces | 13-41 41 99 | Circulation Zone 1D | Fire Alarm Zone 1D | Historic Preservation Zone 1D | Lighting Zone 1D | Occupancy Zone 1D | Ventilation Zone 1D
1D38 | First Floor | TRMT ROOM | 23.2605 | 1D38 | 13-41 41 11: Treatment Room | First Floor | First Floor | 2.8 | 0 | 19.59 | 2.8 | 62.1559 | Treatment Room | 13-41 41 11 | Circulation Zone 1D | Fire Alarm Zone 1D | Historic Preservation Zone 1D | Lighting Zone 1D | Occupancy Zone 1D | Ventilation Zone 1D
1D35 | First Floor | INTERACTION STATION | 12.8258 | 1D35 | 13-41 41 99: Other Healing Spaces | First Floor | First Floor | 2.8 | 0 | 14.432 | 2.8 | 33.45 | Other Healing Spaces | 13-41 41 99 | Circulation Zone 1D | Fire Alarm Zone 1D | Historic Preservation Zone 1D | Lighting Zone 1D | Occupancy Zone 1D | Ventilation Zone 1D
1D31 | First Floor | PEDIATRIC WTS & MSRS | 11.0208 | 1D31 | 13-41 41 14: Physical Examination Room | First Floor | First Floor | 2.8 | 0 | 13.719 | 2.8 | 28.612 | Physical Examination Room | 13-41 41 14 | Circulation Zone 1D | Fire Alarm Zone 1D | Historic Preservation Zone 1D | Lighting Zone 1D | Occupancy Zone 1D | Ventilation Zone 1D
1B04 | First Floor | LAB | 53.5882 | 1B04 | 13-15 11 24 11: Laboratory | First Floor | First Floor | 2.8 | 0 | 36.948 | 2.8 | 143.346 | Laboratory | 13-15 11 24 11 | Circulation Zone 1B | Fire Alarm Zone 1B | Historic Preservation Zone 1B | Lighting Zone 1B | Occupancy Zone 1B | Ventilation Zone 1B
2C16 | Second Floor | CERAMIC LAB | 11.155 | 2C16 | 13-15 11 24 11: Laboratory | Second Floor | Second Floor | 2.8 | 0 | 14.018 | 2.8 | 28.386 | Laboratory | 13-15 11 24 11 | Circulation Zone 2C | Fire Alarm Zone 2C | Historic Preservation Zone 2C | Lighting Zone 2C | Occupancy Zone 2C | Ventilation Zone 2C
2C14 | Second Floor | GEN. DENT. DTR #10 | 12.0102 | 2C14 | 13-41 41 99: Other Healing Spaces | Second Floor | Second Floor | 2.8 | 0 | 13.997 | 2.8 | 30.9231 | Other Healing Spaces | 13-41 41 99 | Circulation Zone 2C | Fire Alarm Zone 2C | Historic Preservation Zone 2C | Lighting Zone 2C | Occupancy Zone 2C | Ventilation Zone 2C
2D18 | Second Floor | TECH. OFFICE | 84.8029 | 2D18 | 13-15 11 34 11: Office | Second Floor | Second Floor | 2.8 | 0 | 45.572 | 2.8 | 229.85 | Office | 13-15 11 34 11 | Circulation Zone 2D | Fire Alarm Zone 2D | Historic Preservation Zone 2D | Lighting Zone 2D | Occupancy Zone 2D | Ventilation Zone 2D
2C12 | Second Floor | DIPC CLEAN | 14.3677 | 2C12 | 13-41 41 99: Other Healing Spaces | Second Floor | Second Floor | 2.8 | 0 | 18.173 | 2.8 | 37.1189 | Other Healing Spaces | 13-41 41 99 | Circulation Zone 2C | Fire Alarm Zone 2C | Historic Preservation Zone 2C | Lighting Zone 2C | Occupancy Zone 2C | Ventilation Zone 2C
2C09 | Second Floor | GEN. DENT. DTR #9 | 11.3638 | 2C09 | 13-41 41 99: Other Healing Spaces | Second Floor | Second Floor | 2.8 | 0 | 13.8601 | 2.8 | 29.2875 | Other Healing Spaces | 13-41 41 99 | Circulation Zone 2C | Fire Alarm Zone 2C | Historic Preservation Zone 2C | Lighting Zone 2C | Occupancy Zone 2C | Ventilation Zone 2C
2C06 | Second Floor | GEN. DENT. DTR #8 | 12.0034 | 2C06 | 13-41 41 99: Other Healing Spaces | Second Floor | Second Floor | 2.8 | 0 | 13.8601 | 2.8 | 30.5886 | Other Healing Spaces | 13-41 41 99 | Circulation Zone 2C | Fire Alarm Zone 2C | Historic Preservation Zone 2C | Lighting Zone 2C | Occupancy Zone 2C | Ventilation Zone 2C
2C04 | Second Floor | GEN. DENT. DTR #7 | 11.1795 | 2C04 | 13-41 41 99: Other Healing Spaces | Second Floor | Second Floor | 2.8 | 0 | 13.8601 | 2.8 | 28.9039 | Other Healing Spaces | 13-41 41 99 | Circulation Zone 2C | Fire Alarm Zone 2C | Historic Preservation Zone 2C | Lighting Zone 2C | Occupancy Zone 2C | Ventilation Zone 2C
2C02 | Second Floor | GEN. DENT. DTR #6 | 12.0034 | 2C02 | 13-41 41 99: Other Healing Spaces | Second Floor | Second Floor | 2.8 | 0 | 13.8601 | 2.8 | 30.7475 | Other Healing Spaces | 13-41 41 99 | Circulation Zone 2C | Fire Alarm Zone 2C | Historic Preservation Zone 2C | Lighting Zone 2C | Occupancy Zone 2C | Ventilation Zone 2C
2A09 | Second Floor | GEN. DENT. DTR #5 | 11.3064 | 2A09 | 13-41 41 99: Other Healing Spaces | Second Floor | Second Floor | 2.8 | 0 | 13.5013 | 2.8 | 29.2712 | Other Healing Spaces | 13-41 41 99 | Circulation Zone 2A | Fire Alarm Zone 2A | Historic Preservation Zone 2A | Lighting Zone 2A | Occupancy Zone 2A | Ventilation Zone 2A
2A08 | Second Floor | GEN. DENT. DTR #4 | 11.7457 | 2A08 | 13-41 41 99: Other Healing Spaces | Second Floor | Second Floor | 2.8 | 0 | 13.5693 | 2.8 | 30.2529 | Other Healing Spaces | 13-41 41 99 | Circulation Zone 2A | Fire Alarm Zone 2A | Historic Preservation Zone 2A | Lighting Zone 2A | Occupancy Zone 2A | Ventilation Zone 2A
2A07 | Second Floor | OH DTR #3 | 12.0034 | 2A07 | 13-41 41 99: Other Healing Spaces | Second Floor | Second Floor | 2.8 | 0 | 13.5693 | 2.8 | 30.7592 | Other Healing Spaces | 13-41 41 99 | Circulation Zone 2A | Fire Alarm Zone 2A | Historic Preservation Zone 2A | Lighting Zone 2A | Occupancy Zone 2A | Ventilation Zone 2A
2A06 | Second Floor | OH DTR #2 | 12.0879 | 2A06 | 13-41 41 99: Other Healing Spaces | Second Floor | Second Floor | 2.8 | 0 | 13.9081 | 2.8 | 30.9712 | Other Healing Spaces | 13-41 41 99 | Circulation Zone 2A | Fire Alarm Zone 2A | Historic Preservation Zone 2A | Lighting Zone 2A | Occupancy Zone 2A | Ventilation Zone 2A
2A05 | Second Floor | OH DTR #1 | 11.3331 | 2A05 | 13-41 41 99: Other Healing Spaces | Second Floor | Second Floor | 2.8 | 0 | 13.8601 | 2.8 | 29.4101 | Other Healing Spaces | 13-41 41 99 | Circulation Zone 2A | Fire Alarm Zone 2A | Historic Preservation Zone 2A | Lighting Zone 2A | Occupancy Zone 2A | Ventilation Zone 2A
1CC1 | First Floor | CORRIDOR | 42.6545 | 1CC1 | 13-85 11 11: Corridor | First Floor | First Floor | 2.8 | 0 | 49.386 | 2.8 | 112.657 | Corridor | 13-85 11 11 | Circulation Zone 1C | Fire Alarm Zone 1C | Historic Preservation Zone 1C | Lighting Zone 1C | Occupancy Zone 1C | Ventilation Zone 1C
1C12 | First Floor | TOILET | 6.14704 | 1C12 | 13-41 11 14 21: Restroom | First Floor | First Floor | 2.8 | 0 | 10.0295 | 2.8 | 15.2844 | Restroom | 13-41 11 14 21 | Circulation Zone 1C | Fire Alarm Zone 1C | Historic Preservation Zone 1C | Lighting Zone 1C | Occupancy Zone 1C | Ventilation Zone 1C
1D18 | First Floor | TOILET | 8.26027 | 1D18 | 13-41 11 14 21: Restroom | First Floor | First Floor | 2.8 | 0 | 12.8768 | 2.8 | 20.6846 | Restroom | 13-41 11 14 21 | Circulation Zone 1D | Fire Alarm Zone 1D | Historic Preservation Zone 1D | Lighting Zone 1D | Occupancy Zone 1D | Ventilation Zone 1D
1D14 | First Floor | SPECIMEN TOILET | 4.75347 | 1D14 | 13-41 11 14 21: Restroom | First Floor | First Floor | 2.8 | 0 | 8.736 | 2.8 | 11.7172 | Restroom | 13-41 11 14 21 | Circulation Zone 1D | Fire Alarm Zone 1D | Historic Preservation Zone 1D | Lighting Zone 1D | Occupancy Zone 1D | Ventilation Zone 1D
1D04 | First Floor | TOILET | 5.10462 | 1D04 | 13-41 11 14 21: Restroom | First Floor | First Floor | 2.8 | 0 | 9.078 | 2.8 | 12.8262 | Restroom | 13-41 11 14 21 | Circulation Zone 1D | Fire Alarm Zone 1D | Historic Preservation Zone 1D | Lighting Zone 1D | Occupancy Zone 1D | Ventilation Zone 1D
1A12 | First Floor | M. TOILET | 9.91049 | 1A12 | 13-41 11 14 21: Restroom | First Floor | First Floor | 2.8 | 0 | 13.184 | 2.8 | 25.6114 | Restroom | 13-41 11 14 21 | Circulation Zone 1A | Fire Alarm Zone 1A | Historic Preservation Zone 1A | Lighting Zone 1A | Occupancy Zone 1A | Ventilation Zone 1A
1A09 | First Floor | W. TOILET | 10.8536 | 1A09 | 13-41 11 14 21: Restroom | First Floor | First Floor | 2.8 | 0 | 13.3715 | 2.8 | 27.4898 | Restroom | 13-41 11 14 21 | Circulation Zone 1A | Fire Alarm Zone 1A | Historic Preservation Zone 1A | Lighting Zone 1A | Occupancy Zone 1A | Ventilation Zone 1A
1A13 | First Floor | STAFF TOILET | 4.4685 | 1A13 | 13-41 11 14 21: Restroom | First Floor | First Floor | 2.8 | 0 | 8.506 | 2.8 | 11.0247 | Restroom | 13-41 11 14 21 | Circulation Zone 1A | Fire Alarm Zone 1A | Historic Preservation Zone 1A | Lighting Zone 1A | Occupancy Zone 1A | Ventilation Zone 1A
1B02 | First Floor | SPECIMEN TOILET | 5.54853 | 1B02 | 13-41 11 14 21: Restroom | First Floor | First Floor | 2.8 | 0 | 10.2769 | 2.8 | 13.7311 | Restroom | 13-41 11 14 21 | Circulation Zone 1B | Fire Alarm Zone 1B | Historic Preservation Zone 1B | Lighting Zone 1B | Occupancy Zone 1B | Ventilation Zone 1B
1B05 | First Floor | PAT. / STAFF TOILET | 4.78883 | 1B05 | 13-41 11 14 21: Restroom | First Floor | First Floor | 2.8 | 0 | 8.832 | 2.8 | 11.8083 | Restroom | 13-41 11 14 21 | Circulation Zone 1B | Fire Alarm Zone 1B | Historic Preservation Zone 1B | Lighting Zone 1B | Occupancy Zone 1B | Ventilation Zone 1B
1B11 | First Floor | STAFF TOILET | 4.99399 | 1B11 | 13-41 11 14 21: Restroom | First Floor | First Floor | 2.8 | 0 | 8.996 | 2.8 | 12.3492 | Restroom | 13-41 11 14 21 | Circulation Zone 1B | Fire Alarm Zone 1B | Historic Preservation Zone 1B | Lighting Zone 1B | Occupancy Zone 1B | Ventilation Zone 1B
1E10 | First Floor | M. TOILET | 5.06216 | 1E10 | 13-41 11 14 21: Restroom | First Floor | First Floor | 2.8 | 0 | 9.206 | 2.8 | 12.455 | Restroom | 13-41 11 14 21 | Circulation Zone 1E | Fire Alarm Zone 1E | Historic Preservation Zone 1E | Lighting Zone 1E | Occupancy Zone 1E | Ventilation Zone 1E
1E09 | First Floor | W. TOILET | 5.06216 | 1E09 | 13-41 11 14 21: Restroom | First Floor | First Floor | 2.8 | 0 | 9.206 | 2.8 | 12.455 | Restroom | 13-41 11 14 21 | Circulation Zone 1E | Fire Alarm Zone 1E | Historic Preservation Zone 1E | Lighting Zone 1E | Occupancy Zone 1E | Ventilation Zone 1E
1E12 | First Floor | ISOLATION TOILET | 5.25186 | 1E12 | 13-41 11 14 21: Restroom | First Floor | First Floor | 2.8 | 0 | 9.282 | 2.8 | 13.0241 | Restroom | 13-41 11 14 21 | Circulation Zone 1E | Fire Alarm Zone 1E | Historic Preservation Zone 1E | Lighting Zone 1E | Occupancy Zone 1E | Ventilation Zone 1E
1D26 | First Floor | TOILET | 5.04348 | 1D26 | 13-41 11 14 21: Restroom | First Floor | First Floor | 2.8 | 0 | 9.172 | 2.8 | 12.3514 | Restroom | 13-41 11 14 21 | Circulation Zone 1D | Fire Alarm Zone 1D | Historic Preservation Zone 1D | Lighting Zone 1D | Occupancy Zone 1D | Ventilation Zone 1D
2C08 | Second Floor | W. STAFF TOILET | 15.7322 | 2C08 | 13-41 11 14 21: Restroom | Second Floor | Second Floor | 2.8 | 0 | 21.984 | 2.8 | 39.9607 | Restroom | 13-41 11 14 21 | Circulation Zone 2C | Fire Alarm Zone 2C | Historic Preservation Zone 2C | Lighting Zone 2C | Occupancy Zone 2C | Ventilation Zone 2C
2C07 | Second Floor | M. STAFF TOILET | 18.2427 | 2C07 | 13-41 11 14 21: Restroom | Second Floor | Second Floor | 2.8 | 0 | 27.3188 | 2.8 | 46.0968 | Restroom | 13-41 11 14 21 | Circulation Zone 2C | Fire Alarm Zone 2C | Historic Preservation Zone 2C | Lighting Zone 2C | Occupancy Zone 2C | Ventilation Zone 2C
2C24 | Second Floor | W. TOILET | 9.22003 | 2C24 | 13-41 11 14 21: Restroom | Second Floor | Second Floor | 2.8 | 0 | 12.1502 | 2.8 | 23.7895 | Restroom | 13-41 11 14 21 | Circulation Zone 2C | Fire Alarm Zone 2C | Historic Preservation Zone 2C | Lighting Zone 2C | Occupancy Zone 2C | Ventilation Zone 2C
2C23 | Second Floor | M. TOILET | 8.65877 | 2C23 | 13-41 11 14 21: Restroom | Second Floor | Second Floor | 2.8 | 0 | 13.2267 | 2.8 | 21.4593 | Restroom | 13-41 11 14 21 | Circulation Zone 2C | Fire Alarm Zone 2C | Historic Preservation Zone 2C | Lighting Zone 2C | Occupancy Zone 2C | Ventilation Zone 2C
2B5 | Second Floor | W. TOILET | 4.73083 | 2B5 | 13-41 11 14 21: Restroom | Second Floor | Second Floor | 2.8 | 0 | 8.976 | 2.8 | 11.5666 | Restroom | 13-41 11 14 21 | Circulation Zone 2B | Fire Alarm Zone 2B | Historic Preservation Zone 2B | Lighting Zone 2B | Occupancy Zone 2B | Ventilation Zone 2B
2B6 | Second Floor | STAFF TOILET | 5.65351 | 2B6 | 13-41 11 14 21: Restroom | Second Floor | Second Floor | 2.8 | 0 | 9.636 | 2.8 | 14.0355 | Restroom | 13-41 11 14 21 | Circulation Zone 2B | Fire Alarm Zone 2B | Historic Preservation Zone 2B | Lighting Zone 2B | Occupancy Zone 2B | Ventilation Zone 2B
2B22 | Second Floor | M. TOILET | 5.16718 | 2B22 | 13-41 11 14 21: Restroom | Second Floor | Second Floor | 2.8 | 0 | 9.11944 | 2.8 | 12.433 | Restroom | 13-41 11 14 21 | Circulation Zone 2B | Fire Alarm Zone 2B | Historic Preservation Zone 2B | Lighting Zone 2B | Occupancy Zone 2B | Ventilation Zone 2B
2D13 | Second Floor | TOILET | 4.74366 | 2D13 | 13-41 11 14 21: Restroom | Second Floor | Second Floor | 2.8 | 0 | 9.012 | 2.8 | 11.7127 | Restroom | 13-41 11 14 21 | Circulation Zone 2D | Fire Alarm Zone 2D | Historic Preservation Zone 2D | Lighting Zone 2D | Occupancy Zone 2D | Ventilation Zone 2D

# IfcCovering: Compound Ceiling:ACT 600 x 600mm Grid (220)
PredefinedType: CEILING; Material: Default 0.036 m, Ceiling Tile 600 x 600 0.016 m
Pset_CoveringCommon - Reference: Compound Ceiling:ACT 600 x 600mm Grid; TotalThickness: 0.052 m
PSet_Revit_Constraints - Height Offset From Level: 2.68 m; Room Bounding: no
PSet_Revit_Other - InstallationDate: InstallationDate; SerialNumber: SerialNumber; WarrantyStartDate: WarrantyStartDate; BarCode: BarCode; AssetIdentifier: AssetIdentifier; TagNumber: TagNumber
PSet_Revit_Phasing - Phase Created: New Construction
PSet_Revit_Type_Construction - Thickness: 0.052 m
PSet_Revit_Type_Graphics - Coarse Scale Fill Color: 0
PSet_Revit_Type_Identity Data - Manufacturer: Manufacturer
PSet_Revit_Type_Other - AccessibilityPerformance: AccessibilityPerformance; CodePerformance: CodePerformance; Color: Color; Constituents: Constituents; Features: Features; Finish: Finish; Grade: Grade; Material: Material; ModelReference: ModelReference; NominalHeight: NominalHeight; NominalLength: NominalLength; NominalWidth: NominalWidth; ProductionYear: ProductionYear; Reference: Reference; Shape: Shape; Size: Size; SustainabilityPerformance: SustainabilityPerformance; WarrantyDescription: WarrantyDescription; WarrantyDurationLabor: WarrantyDurationLabor; WarrantyDurationParts: WarrantyDurationParts; WarrantyGuarantorLabor: WarrantyGuarantorLabor; WarrantyGuarantorParts: WarrantyGuarantorParts; ExpectedLife: ExpectedLife; ReplacementCost: ReplacementCost; AssetAccountingType: FIXED; Classification Code: 23-35 70 24; Classification Description: Ceilings; ModelLabel: ModelLabel
Name (Compound Ceiling:ACT 600 x 600mm Grid:...) | In | Level | Perimeter (m) | Area (m2) | Volume (m3)
268373 | First Floor | First Floor | 12.316 | 9.44535 | 0.491158 | Pset_CoveringCommon - Finish: Ceiling Tile 600 x 600;
268384 | First Floor | First Floor | 11.73 | 8.59024 | 0.446693
268392 | First Floor | First Floor | 11.696 | 8.29768 | 0.431479
268402 | First Floor | First Floor | 11.782 | 7.96938 | 0.414408
268415 | First Floor | First Floor | 11.496 | 8.15852 | 0.424243
268425 | First Floor | First Floor | 13.886 | 9.47323 | 0.492608
268437 | First Floor | First Floor | 12.42 | 9.5107 | 0.494557
268465 | First Floor | First Floor | 20.2071 | 16.303 | 0.847755
268477 | First Floor | First Floor | 142.979 | 133.191 | 6.92595
268544 | First Floor | First Floor | 8.384 | 3.54682 | 0.184434
268552 | First Floor | First Floor | 20.4078 | 16.9814 | 0.883032
268562 | First Floor | First Floor | 13.936 | 11.7415 | 0.610557
268574 | First Floor | First Floor | 13.936 | 11.9464 | 0.621213
268599 | First Floor | First Floor | 13.936 | 11.9464 | 0.621213
268607 | First Floor | First Floor | 12.116 | 8.31551 | 0.432407
268615 | First Floor | First Floor | 14.6785 | 13.4313 | 0.698429
268634 | First Floor | First Floor | 9.418 | 5.4587 | 0.283852
268643 | First Floor | First Floor | 10.87 | 7.31109 | 0.380177
268651 | First Floor | First Floor | 12.816 | 9.03638 | 0.469892
268663 | First Floor | First Floor | 13.016 | 10.4006 | 0.540833
268673 | First Floor | First Floor | 42.03 | 55.3775 | 2.87963
268695 | First Floor | First Floor | 15.344 | 14.578 | 0.758056
268719 | First Floor | First Floor | 36.219 | 65.7954 | 3.42136
268741 | First Floor | First Floor | 17.522 | 17.9225 | 0.931972
268753 | First Floor | First Floor | 13.244 | 10.9544 | 0.569631
268761 | First Floor | First Floor | 12.3368 | 7.38736 | 0.384143
268773 | First Floor | First Floor | 9.25 | 5.23442 | 0.27219
268781 | First Floor | First Floor | 20.463 | 23.2185 | 1.20736
268797 | First Floor | First Floor | 17.522 | 17.9225 | 0.931972
268809 | First Floor | First Floor | 13.244 | 10.9544 | 0.569631
268817 | First Floor | First Floor | 12.916 | 10.07 | 0.523642
268825 | First Floor | First Floor | 8.616 | 4.41123 | 0.229384
268833 | First Floor | First Floor | 35.918 | 65.1999 | 3.39039
268851 | First Floor | First Floor | 23.298 | 27.1573 | 1.41218
268864 | First Floor | First Floor | 19.428 | 21.1412 | 1.09934
268886 | First Floor | First Floor | 30.405 | 47.6375 | 2.47715
268903 | First Floor | First Floor | 12.19 | 8.88809 | 0.462181
268917 | First Floor | First Floor | 15.376 | 14.3633 | 0.746893
268930 | First Floor | First Floor | 11.942 | 8.84742 | 0.460066
268938 | First Floor | First Floor | 15.086 | 10.2462 | 0.532801
268971 | First Floor | First Floor | 11.5152 | 7.87915 | 0.409716
268981 | First Floor | First Floor | 10.2972 | 5.95577 | 0.3097
268989 | First Floor | First Floor | 9.928 | 5.64193 | 0.29338
268997 | First Floor | First Floor | 9.4192 | 4.82734 | 0.251021
269016 | First Floor | First Floor | 13.5028 | 10.5609 | 0.549166
269051 | First Floor | First Floor | 13.136 | 9.94955 | 0.517377
269061 | First Floor | First Floor | 18.218 | 18.3456 | 0.953972
269069 | First Floor | First Floor | 11.832 | 8.74554 | 0.454768
269077 | First Floor | First Floor | 11.698 | 8.55171 | 0.444689
269085 | First Floor | First Floor | 47.2508 | 115.12 | 5.98624
269125 | First Floor | First Floor | 14.784 | 13.6597 | 0.710306
269133 | First Floor | First Floor | 12.492 | 9.10116 | 0.47326
269145 | First Floor | First Floor | 8.666 | 4.4482 | 0.231307
269153 | First Floor | First Floor | 8.666 | 4.4482 | 0.231307
269161 | First Floor | First Floor | 13.156 | 10.7998 | 0.561591
269169 | First Floor | First Floor | 24.412 | 35.8771 | 1.86561
269181 | First Floor | First Floor | 12.132 | 9.1712 | 0.476902
269189 | First Floor | First Floor | 11.996 | 8.97631 | 0.466768
269197 | First Floor | First Floor | 11.996 | 8.96611 | 0.466238
269205 | First Floor | First Floor | 9.256 | 5.08627 | 0.264486
269213 | First Floor | First Floor | 50.8248 | 45.3219 | 2.35674
269237 | First Floor | First Floor | 13.868 | 11.8131 | 0.614279
269245 | First Floor | First Floor | 14.248 | 11.8747 | 0.617482
269257 | First Floor | First Floor | 13.936 | 11.9464 | 0.621213
269265 | First Floor | First Floor | 13.936 | 11.8534 | 0.616379
269275 | First Floor | First Floor | 19.164 | 22.1985 | 1.15432
269283 | First Floor | First Floor | 18.752 | 15.3999 | 0.800794
269293 | First Floor | First Floor | 13.936 | 11.8624 | 0.616843
269304 | First Floor | First Floor | 13.936 | 11.8826 | 0.617894
269314 | First Floor | First Floor | 13.188 | 10.2186 | 0.531365
269324 | First Floor | First Floor | 12.176 | 8.49505 | 0.441743
269332 | First Floor | First Floor | 5.696 | 1.81801 | 0.0945366
269365 | First Floor | First Floor | 12.516 | 9.01095 | 0.46857
269373 | First Floor | First Floor | 12.5841 | 9.08738 | 0.472544
269381 | First Floor | First Floor | 27.8608 | 28.2327 | 1.4681
269417 | First Floor | First Floor | 9.168 | 5.25326 | 0.27317
269425 | First Floor | First Floor | 50.639 | 39.8113 | 2.07019
269447 | First Floor | First Floor | 7.97 | 3.42762 | 0.178236
269455 | First Floor | First Floor | 7.97 | 3.42762 | 0.178236
269463 | First Floor | First Floor | 7.87805 | 3.30216 | 0.171712
269471 | First Floor | First Floor | 13.01 | 9.40654 | 0.48914
269483 | First Floor | First Floor | 12.256 | 8.93651 | 0.464699
269491 | First Floor | First Floor | 12.4779 | 9.35111 | 0.486258
269499 | First Floor | First Floor | 36.491 | 51.2575 | 2.66539
269523 | First Floor | First Floor | 8.456 | 4.41043 | 0.229342
269531 | First Floor | First Floor | 8.15205 | 4.12527 | 0.214514
269539 | First Floor | First Floor | 8.208 | 3.8971 | 0.202649
269547 | First Floor | First Floor | 8.292 | 4.21724 | 0.219296
269555 | First Floor | First Floor | 12.236 | 8.90697 | 0.463163
269565 | First Floor | First Floor | 9.38 | 5.0958 | 0.264982
269573 | First Floor | First Floor | 9.57795 | 4.90397 | 0.255006
269585 | First Floor | First Floor | 46.643 | 64.9592 | 3.37788
269613 | First Floor | First Floor | 12.644 | 9.09798 | 0.473095
269636 | First Floor | First Floor | 21.748 | 15.1396 | 0.787259
269651 | First Floor | First Floor | 7.988 | 3.93739 | 0.204744
269660 | First Floor | First Floor | 9.696 | 5.86803 | 0.305138
269669 | First Floor | First Floor | 13.332 | 10.7208 | 0.55748
269678 | First Floor | First Floor | 13.9369 | 11.9478 | 0.621285
269686 | First Floor | First Floor | 13.9369 | 11.8839 | 0.617961
269710 | First Floor | First Floor | 8.196 | 4.18471 | 0.217605
269718 | First Floor | First Floor | 15.688 | 13.7732 | 0.716206
269732 | First Floor | First Floor | 12.856 | 9.09866 | 0.47313
269742 | First Floor | First Floor | 8.7368 | 4.6539 | 0.242003
269750 | First Floor | First Floor | 13.756 | 10.2221 | 0.531551
269760 | First Floor | First Floor | 12.29 | 9.19069 | 0.477916
269795 | First Floor | First Floor | 8.592 | 4.58078 | 0.238201
271806 | First Floor | First Floor | 48.0894 | 51.8156 | 2.69441
271832 | First Floor | First Floor | 70.159 | 57.4393 | 2.98684
271854 | First Floor | First Floor | 72.996 | 59.0049 | 3.06826
272284 | First Floor | First Floor | 12.776 | 8.22531 | 0.427716
272729 | First Floor | First Floor | 11.9532 | 7.87029 | 0.409255
273116 | First Floor | First Floor | 11.678 | 7.06059 | 0.367151
273128 | First Floor | First Floor | 8.742 | 4.65145 | 0.241875
273149 | First Floor | First Floor | 14.532 | 12.4557 | 0.647699
273430 | First Floor | First Floor | 12.168 | 8.73296 | 0.454114
273459 | First Floor | First Floor | 13.3288 | 7.12941 | 0.370729
273488 | First Floor | First Floor | 12.6769 | 9.42752 | 0.490231
273777 | First Floor | First Floor | 12.052 | 8.99885 | 0.46794
273791 | First Floor | First Floor | 13.698 | 11.0649 | 0.575376
274187 | First Floor | First Floor | 56.56 | 80.2459 | 4.17279
274234 | First Floor | First Floor | 12.71 | 9.88238 | 0.513884
274246 | First Floor | First Floor | 5.526 | 1.67862 | 0.0872883
274286 | First Floor | First Floor | 5.2848 | 1.67126 | 0.0869055
274311 | Second Floor | Second Floor | 13.236 | 10.1378 | 0.527168
274323 | Second Floor | Second Floor | 23.912 | 18.4617 | 0.960008
274342 | Second Floor | Second Floor | 9.756 | 4.98879 | 0.259417
274352 | Second Floor | Second Floor | 53.6242 | 43.5515 | 2.26468
274368 | Second Floor | Second Floor | 13.2211 | 10.4598 | 0.54391
274378 | Second Floor | Second Floor | 9.064 | 4.57226 | 0.237757
274386 | Second Floor | Second Floor | 13.2211 | 10.9245 | 0.568074
274394 | Second Floor | Second Floor | 13.2211 | 10.3228 | 0.536786
276406 | Second Floor | Second Floor | 13.2211 | 10.9245 | 0.568074
276416 | Second Floor | Second Floor | 13.1531 | 10.3931 | 0.540439
276427 | Second Floor | Second Floor | 13.2211 | 10.7437 | 0.558672
276438 | Second Floor | Second Floor | 13.2211 | 10.9245 | 0.568074
276447 | Second Floor | Second Floor | 13.2691 | 11.0043 | 0.572223
276457 | Second Floor | Second Floor | 13.2211 | 10.4478 | 0.543285
276471 | Second Floor | Second Floor | 15.53 | 14.9321 | 0.776467
276479 | Second Floor | Second Floor | 15.458 | 14.7787 | 0.768494
276487 | Second Floor | Second Floor | 13.462 | 10.0234 | 0.521216
276499 | Second Floor | Second Floor | 18.3859 | 19.8431 | 1.03184
276513 | Second Floor | Second Floor | 50.3363 | 63.2829 | 3.29071
276544 | Second Floor | Second Floor | 71.452 | 57.8614 | 3.00879
276582 | Second Floor | Second Floor | 13.8449 | 10.3428 | 0.537826
276611 | Second Floor | Second Floor | 5.3818 | 1.87393 | 0.0974446
276687 | Second Floor | Second Floor | 11.358 | 6.88203 | 0.357866
277079 | Second Floor | Second Floor | 5.182 | 1.50651 | 0.0783385
277088 | Second Floor | Second Floor | 20.636 | 13.9259 | 0.724144
277099 | Second Floor | Second Floor | 26.1102 | 25.7128 | 1.33707
277115 | Second Floor | Second Floor | 14.2971 | 9.15778 | 0.476204
277127 | Second Floor | Second Floor | 11.9442 | 8.91626 | 0.463645
277135 | Second Floor | Second Floor | 11.532 | 8.11544 | 0.422003
277143 | Second Floor | Second Floor | 28.6413 | 32.3544 | 1.68243
277157 | Second Floor | Second Floor | 7.768 | 3.51126 | 0.182586
277165 | Second Floor | Second Floor | 21.7421 | 12.4663 | 0.648249
277185 | Second Floor | Second Floor | 7.95066 | 3.77244 | 0.196167
277194 | Second Floor | Second Floor | 6.22266 | 2.42 | 0.12584
277202 | Second Floor | Second Floor | 13.4453 | 10.3485 | 0.53812
277210 | Second Floor | Second Floor | 17.7373 | 11.7039 | 0.608604
277222 | Second Floor | Second Floor | 12.996 | 10.2499 | 0.532995
277254 | Second Floor | Second Floor | 12.064 | 8.86034 | 0.460737
277266 | Second Floor | Second Floor | 24.644 | 28.5857 | 1.48645
277320 | Second Floor | Second Floor | 12.064 | 9.07666 | 0.471986
277328 | Second Floor | Second Floor | 19.696 | 19.8021 | 1.02971
277340 | Second Floor | Second Floor | 17.668 | 13.2534 | 0.689176
277962 | Second Floor | Second Floor | 10.6509 | 7.08958 | 0.368658
278300 | Second Floor | Second Floor | 14.806 | 13.3152 | 0.692391
278310 | Second Floor | Second Floor | 11.786 | 8.28308 | 0.43072
278320 | Second Floor | Second Floor | 11.674 | 8.49589 | 0.441786
278328 | Second Floor | Second Floor | 13.524 | 11.1552 | 0.58007
278338 | Second Floor | Second Floor | 73.8269 | 63.6784 | 3.31128
278356 | Second Floor | Second Floor | 16.378 | 15.6638 | 0.814516
278389 | Second Floor | Second Floor | 45.466 | 82.1665 | 4.27266
278405 | Second Floor | Second Floor | 12.5509 | 8.96728 | 0.466299
278417 | Second Floor | Second Floor | 14.8388 | 12.7022 | 0.660512
278427 | Second Floor | Second Floor | 12.949 | 9.9254 | 0.516121
278437 | Second Floor | Second Floor | 12.1189 | 8.69774 | 0.452283
278447 | Second Floor | Second Floor | 12.8889 | 9.96802 | 0.518337
278457 | Second Floor | Second Floor | 30.7589 | 55.9301 | 2.90837
278467 | Second Floor | Second Floor | 8.516 | 4.18311 | 0.217522
278477 | Second Floor | Second Floor | 16.836 | 14.3924 | 0.748402
278485 | Second Floor | Second Floor | 11.718 | 8.54177 | 0.444172
278493 | Second Floor | Second Floor | 13.0049 | 8.66001 | 0.45032
278507 | Second Floor | Second Floor | 7.10712 | 2.82658 | 0.146982
278547 | Second Floor | Second Floor | 12.657 | 9.91341 | 0.515497
278555 | Second Floor | Second Floor | 12.031 | 8.82448 | 0.458873
278563 | Second Floor | Second Floor | 12.222 | 8.59695 | 0.447042
278576 | Second Floor | Second Floor | 45.9281 | 36.47 | 1.89644
278592 | Second Floor | Second Floor | 5.24088 | 1.52813 | 0.0794627
278600 | Second Floor | Second Floor | 12.516 | 8.90434 | 0.463025
278610 | Second Floor | Second Floor | 13.108 | 9.75662 | 0.507344
278620 | Second Floor | Second Floor | 11.744 | 8.37408 | 0.435452
278628 | Second Floor | Second Floor | 11.676 | 8.25739 | 0.429384
278636 | Second Floor | Second Floor | 11.608 | 8.1407 | 0.423317
278644 | Second Floor | Second Floor | 11.304 | 7.0337 | 0.365752
278652 | Second Floor | Second Floor | 14.344 | 11.7358 | 0.610261
278660 | Second Floor | Second Floor | 16.164 | 14.1815 | 0.737436
278671 | Second Floor | Second Floor | 12.624 | 9.1322 | 0.474874
278679 | Second Floor | Second Floor | 9.096 | 5.01267 | 0.260659
278687 | Second Floor | Second Floor | 8.436 | 4.13091 | 0.214807
278695 | Second Floor | Second Floor | 28.7188 | 20.9417 | 1.08897
278707 | Second Floor | Second Floor | 5.512 | 1.8928 | 0.0984256
278715 | Second Floor | Second Floor | 14.6881 | 12.5931 | 0.654841
278731 | Second Floor | Second Floor | 12.184 | 9.16922 | 0.476799
278739 | Second Floor | Second Floor | 12.224 | 9.23674 | 0.48031
278747 | Second Floor | Second Floor | 12.184 | 9.16922 | 0.476799
278755 | Second Floor | Second Floor | 18.9241 | 17.4934 | 0.909655
278769 | Second Floor | Second Floor | 22.5804 | 16.2993 | 0.847564
278789 | Second Floor | Second Floor | 11.926 | 8.25014 | 0.429007
278797 | Second Floor | Second Floor | 12.442 | 9.22564 | 0.479733
278805 | Second Floor | Second Floor | 12.48 | 8.83451 | 0.459394
278817 | Second Floor | Second Floor | 20.15 | 19.4927 | 1.01362
278829 | Second Floor | Second Floor | 23.63 | 32.8779 | 1.70965
278841 | Second Floor | Second Floor | 8.57488 | 4.43177 | 0.230452
279106 | Second Floor | Second Floor | 12.106 | 8.42956 | 0.438337
279431 | Second Floor | Second Floor | 19.8578 | 16.9372 | 0.880736
281666 | Second Floor | Second Floor | 15.3938 | 9.95542 | 0.517682
345544 | First Floor | First Floor | 19.5421 | 12.7946 | 0.665321
346744 | First Floor | First Floor | 18.352 | 18.7757 | 0.976335
377445 | First Floor | First Floor | 23.592 | 18.4704 | 0.960462

# IfcCovering: Compound Ceiling:Gypsum Board (30)
PredefinedType: CEILING; Material: Metal - Stud Layer 0.045 m, Plasterboard 0.012 m
Pset_CoveringCommon - Reference: Compound Ceiling:Gypsum Board; TotalThickness: 0.057 m
PSet_Revit_Constraints - Room Bounding: no
PSet_Revit_Other - InstallationDate: InstallationDate; SerialNumber: SerialNumber; WarrantyStartDate: WarrantyStartDate; BarCode: BarCode; AssetIdentifier: AssetIdentifier; TagNumber: TagNumber
PSet_Revit_Phasing - Phase Created: New Construction
PSet_Revit_Type_Construction - Thickness: 0.057 m
PSet_Revit_Type_Graphics - Coarse Scale Fill Color: 0
PSet_Revit_Type_Identity Data - Manufacturer: Manufacturer
PSet_Revit_Type_Other - AccessibilityPerformance: AccessibilityPerformance; CodePerformance: CodePerformance; Color: Color; Constituents: Constituents; Features: Features; Finish: Finish; Grade: Grade; Material: Material; ModelReference: ModelReference; NominalHeight: NominalHeight; NominalLength: NominalLength; NominalWidth: NominalWidth; ProductionYear: ProductionYear; Reference: Reference; Shape: Shape; Size: Size; SustainabilityPerformance: SustainabilityPerformance; WarrantyDescription: WarrantyDescription; WarrantyDurationLabor: WarrantyDurationLabor; WarrantyDurationParts: WarrantyDurationParts; WarrantyGuarantorLabor: WarrantyGuarantorLabor; WarrantyGuarantorParts: WarrantyGuarantorParts; ExpectedLife: ExpectedLife; ReplacementCost: ReplacementCost; AssetAccountingType: FIXED; Classification Code: 23-35 70 24; Classification Description: Ceilings; ModelLabel: ModelLabel
Name (Compound Ceiling:Gypsum Board:...) | In | Level | Height Offset From Level (m) | Perimeter (m) | Area (m2) | Volume (m3)
273443 | First Floor | First Floor | 2.8 | 4.739 | 1.12775 | 0.0642815
273451 | First Floor | First Floor | 2.8 | 5.104 | 1.43982 | 0.0820697
312926 | First Floor | First Floor | 3.8 | 23.8199 | 21.1034 | 1.20287
314477 | First Floor | First Floor | 3.8 | 2.264 | 0.19504 | 0.0111173
314485 | First Floor | First Floor | 3.8 | 2.264 | 0.19504 | 0.0111173
315041 | First Floor | First Floor | 3.8 | 43.1249 | 28.9689 | 1.65123
317328 | First Floor | First Floor | 2.8 | 65.1971 | 67.5822 | 3.85219
318636 | First Floor | First Floor | 3.8 | 4.3249 | 0.773693 | 0.0441005
318692 | First Floor | First Floor | 3.8 | 4.324 | 0.77292 | 0.0440564
371172 | First Floor | First Floor | 2.5 | 5.384 | 1.67922 | 0.0957154
371223 | First Floor | First Floor | 2.5 | 10.8561 | 3.34178 | 0.190481
371283 | First Floor | First Floor | 2.5 | 9.092 | 2.14858 | 0.122469
371391 | First Floor | First Floor | 2.5 | 4.232 | 0.69426 | 0.0395728
377269 | Roof - Main | Roof - Main | -0.05 | 85.693 | 51.8055 | 2.95291
378055 | First Floor | First Floor | 2.5 | 5.384 | 1.67922 | 0.0957154
378079 | First Floor | First Floor | 2.5 | 10.8561 | 3.34178 | 0.190481
378107 | First Floor | First Floor | 2.5 | 4.232 | 0.69426 | 0.0395728
378193 | First Floor | First Floor | 2.5 | 3.5295 | 0.551652 | 0.0314441
378212 | First Floor | First Floor | 2.5 | 4.232 | 0.69426 | 0.0395728
378229 | First Floor | First Floor | 2.5 | 3.5295 | 0.551652 | 0.0314441
396318 | Second Floor | Second Floor | 1.55 | 11.049 | 5.02992 | 0.286706
396768 | Second Floor | Second Floor | 1.55 | 10.293 | 4.82132 | 0.274815
420115 | First Floor | First Floor | 2.943 | 4.95509 | 0.840292 | 0.0478966
420122 | First Floor | First Floor | 2.943 | 4.956 | 0.841228 | 0.04795
420169 | First Floor | First Floor | 2.943 | 7.916 | 1.44211 | 0.0822004
420180 | First Floor | First Floor | 2.943 | 8.0235 | 1.46393 | 0.0834442
420246 | First Floor | First Floor | 2.943 | 4.876 | 0.824992 | 0.0470245
420253 | First Floor | First Floor | 2.943 | 8.3885 | 1.77601 | 0.101232
420313 | First Floor | First Floor | 2.943 | 10.966 | 2.06127 | 0.117493
420320 | First Floor | First Floor | 2.943 | 10.966 | 2.06126 | 0.117492

# IfcCurtainWall: Curtain Wall:Chain Link Fence:137002 (2)
In: First Floor
Pset_CurtainWallCommon - Reference: Curtain Wall:Chain Link Fence; IsExternal: yes
PSet_Revit_Constraints - Base Constraint: First Floor; Base Offset: -1 m; Base is Attached: no; Top Constraint: Up to level: First Floor; Unconnected Height: 2 m; Top Offset: 1 m; Top is Attached: no; Room Bounding: yes; Related to Mass: no
PSet_Revit_Other - InstallationDate: InstallationDate; SerialNumber: SerialNumber; WarrantyStartDate: WarrantyStartDate; BarCode: BarCode; AssetIdentifier: AssetIdentifier; TagNumber: TagNumber
PSet_Revit_Phasing - Phase Created: New Construction
PSet_Revit_Structural - Structural Usage: 0
PSet_Revit_Vertical Grid Pattern - Number: 1; Justification: 4; Angle: 0 deg; Offset: 0 m
PSet_Revit_Horizontal Grid Pattern - Justification: 1; Angle: 0 deg; Offset: 0 m
PSet_Revit_Type_Identity Data - Manufacturer: Manufacturer
PSet_Revit_Type_Construction - Function: 1; Automatically Embed: no; Curtain Panel: System Panel : Chain Link Fence Panel; Join Condition: 0
PSet_Revit_Type_Other - AccessibilityPerformance: AccessibilityPerformance; CodePerformance: CodePerformance; Color: Color; Constituents: Constituents; Features: Features; Finish: Finish; Grade: Grade; Material: Material; ModelReference: ModelReference; NominalHeight: NominalHeight; NominalLength: NominalLength; NominalWidth: NominalWidth; ProductionYear: ProductionYear; Reference: Reference; Shape: Shape; Size: Size; SustainabilityPerformance: SustainabilityPerformance; WarrantyDescription: WarrantyDescription; WarrantyDurationLabor: WarrantyDurationLabor; WarrantyDurationParts: WarrantyDurationParts; WarrantyGuarantorLabor: WarrantyGuarantorLabor; WarrantyGuarantorParts: WarrantyGuarantorParts; ExpectedLife: ExpectedLife; ReplacementCost: ReplacementCost; AssetAccountingType: FIXED; Classification Code: 23-25 40 21 17 11; Classification Description: Chain Link Fences; ModelLabel: ModelLabel
PSet_Revit_Type_Vertical Grid Pattern - Layout: 2; Spacing: 1.5 m; Adjust for Mullion Size: no
PSet_Revit_Type_Horizontal Grid Pattern - Layout: 0; Spacing: 2.4 m; Adjust for Mullion Size: no
PSet_Revit_Type_Vertical Mullions - Interior Type: Circular Mullion : 19mm Radius; Border 1 Type: Circular Mullion : 19mm Radius; Border 2 Type: Circular Mullion : 19mm Radius
PSet_Revit_Type_Horizontal Mullions - Interior Type: Circular Mullion : 19mm Radius; Border 2 Type: Circular Mullion : 19mm Radius
Name (Curtain Wall:Chain Link Fence:...) | Length (m) | Area (m2) | Number
346963 | 8.60208 | 17.2042 | 2
347580 | 2.2 | 4.4 | 4

# IfcCurtainWall: Curtain Wall:Storefront - Interior:421061 (8)
In: First Floor
Pset_CurtainWallCommon - Reference: Curtain Wall:Storefront - Interior; IsExternal: no
PSet_Revit_Constraints - Base Constraint: First Floor; Base is Attached: no; Top Constraint: Up to level: First Floor; Top is Attached: no; Related to Mass: no
PSet_Revit_Other - InstallationDate: InstallationDate; SerialNumber: SerialNumber; WarrantyStartDate: WarrantyStartDate; BarCode: BarCode; AssetIdentifier: AssetIdentifier; TagNumber: TagNumber
PSet_Revit_Phasing - Phase Created: New Construction
PSet_Revit_Structural - Structural Usage: 0
PSet_Revit_Vertical Grid Pattern - Justification: 4; Angle: 0 deg; Offset: 0 m
PSet_Revit_Horizontal Grid Pattern - Justification: 1; Angle: 0 deg; Offset: 0 m
PSet_Revit_Type_Identity Data - Manufacturer: Manufacturer
PSet_Revit_Type_Construction - Function: 0; Automatically Embed: yes; Curtain Panel: System Panel : Glazed; Join Condition: 1
PSet_Revit_Type_Other - AccessibilityPerformance: AccessibilityPerformance; CodePerformance: CodePerformance; Color: Color; Constituents: Constituents; Features: Features; Finish: Finish; Grade: Grade; Material: Material; ModelReference: ModelReference; NominalHeight: NominalHeight; NominalLength: NominalLength; NominalWidth: NominalWidth; ProductionYear: ProductionYear; Reference: Reference; Shape: Shape; Size: Size; SustainabilityPerformance: SustainabilityPerformance; WarrantyDescription: WarrantyDescription; WarrantyDurationLabor: WarrantyDurationLabor; WarrantyDurationParts: WarrantyDurationParts; WarrantyGuarantorLabor: WarrantyGuarantorLabor; WarrantyGuarantorParts: WarrantyGuarantorParts; ExpectedLife: ExpectedLife; ReplacementCost: ReplacementCost; AssetAccountingType: FIXED; Classification Code: 23-25 20 14 11; Classification Description: Curtain Walls; ModelLabel: ModelLabel
PSet_Revit_Type_Vertical Grid Pattern - Layout: 3; Spacing: 1.524 m; Adjust for Mullion Size: no
PSet_Revit_Type_Horizontal Grid Pattern - Layout: 1; Spacing: 2.4 m; Adjust for Mullion Size: no
PSet_Revit_Type_Vertical Mullions - Interior Type: Rectangular Mullion : 50 x 150mm; Border 1 Type: Rectangular Mullion : 50 x 150mm; Border 2 Type: Rectangular Mullion : 50 x 150mm; sets with these values: 2
Name (Curtain Wall:Storefront - Interior:...) | Base Offset (m) | Unconnected Height (m) | Top Offset (m) | Room Bounding | Length (m) | Area (m2) | PSet_Revit_Vertical Grid Pattern, Number | PSet_Revit_Horizontal Grid Pattern, Number
283067 | 0 | 2.8 | 2.8 | no | 1.532 | 4.116 | 4 | 1
283422 | 0 | 2.8 | 2.8 | no | 0.915 | 2.562 | 4 | 1
283650 | 0 | 2.8 | 2.8 | no | 3.23 | 9.044 | 2 | 1
283767 | 0 | 2.8 | 2.8 | no | 0.915 | 2.562 | 4 | 1
283882 | 0 | 2.8 | 2.8 | no | 1.53155 | 4.11473 | 4 | 1
284081 | 0 | 2.8 | 2.8 | no | 3.23 | 9.044 | 2 | 1
284567 | 1 | 1 | 2 | yes | 1.534 | 1.534 | 1 | 1
356367 | 1 | 1 | 2 | yes | 0.915 | 0.915 | 4 | 4

# IfcCurtainWall: Curtain Wall:Storefront:29097 (21)
Pset_CurtainWallCommon - Reference: Curtain Wall:Storefront; IsExternal: yes
PSet_Revit_Constraints - Base is Attached: no; Top is Attached: no; Room Bounding: yes; Related to Mass: no
PSet_Revit_Other - InstallationDate: InstallationDate; SerialNumber: SerialNumber; WarrantyStartDate: WarrantyStartDate; BarCode: BarCode; AssetIdentifier: AssetIdentifier; TagNumber: TagNumber
PSet_Revit_Phasing - Phase Created: New Construction
PSet_Revit_Structural - Structural Usage: 0
PSet_Revit_Vertical Grid Pattern - Justification: 4; Angle: 0 deg; Offset: 0 m
PSet_Revit_Horizontal Grid Pattern - Justification: 1; Angle: 0 deg; Offset: 0 m
PSet_Revit_Type_Identity Data - Manufacturer: Manufacturer
PSet_Revit_Type_Construction - Function: 1; Automatically Embed: yes; Curtain Panel: System Panel : Glazed; Join Condition: 1
PSet_Revit_Type_Other - AccessibilityPerformance: AccessibilityPerformance; CodePerformance: CodePerformance; Color: Color; Constituents: Constituents; Features: Features; Finish: Finish; Grade: Grade; Material: Material; ModelReference: ModelReference; NominalHeight: NominalHeight; NominalLength: NominalLength; NominalWidth: NominalWidth; ProductionYear: ProductionYear; Reference: Reference; Shape: Shape; Size: Size; SustainabilityPerformance: SustainabilityPerformance; WarrantyDescription: WarrantyDescription; WarrantyDurationLabor: WarrantyDurationLabor; WarrantyDurationParts: WarrantyDurationParts; WarrantyGuarantorLabor: WarrantyGuarantorLabor; WarrantyGuarantorParts: WarrantyGuarantorParts; ExpectedLife: ExpectedLife; ReplacementCost: ReplacementCost; AssetAccountingType: FIXED; Classification Code: 23-25 20 14 11; Classification Description: Curtain Walls; ModelLabel: ModelLabel
PSet_Revit_Type_Vertical Grid Pattern - Layout: 3; Spacing: 1.524 m; Adjust for Mullion Size: no
PSet_Revit_Type_Horizontal Grid Pattern - Layout: 1; Spacing: 2.4 m; Adjust for Mullion Size: no
PSet_Revit_Type_Vertical Mullions - Interior Type: Rectangular Mullion : 50 x 150mm; Border 1 Type: Rectangular Mullion : 50 x 150mm; Border 2 Type: Rectangular Mullion : 50 x 150mm; sets with these values: 2
Name (Curtain Wall:Storefront:...) | In | Base Constraint | Base Offset (m) | Top Constraint | Unconnected Height (m) | Top Offset (m) | Length (m) | Area (m2) | PSet_Revit_Vertical Grid Pattern, Number | PSet_Revit_Horizontal Grid Pattern, Number
200372 | Second Floor | Second Floor | 0 | Up to level: Second Floor | 2.4 | 2.4 | 6.10616 | 14.506 | 3 | 1
220417 | Second Floor | Second Floor | 0 | Up to level: Second Floor | 2.4 | 2.4 | 11.261 | 26.8776 | 7 | 1
256998 | First Floor | First Floor | 0.905 | Up to level: First Floor | 1.635 | 2.54 | 5.00051 | 8.17584 | 3 | 4
258059 | First Floor | First Floor | 0.905 | Up to level: First Floor | 1.635 | 2.54 | 5 | 8.175 | 3 | 4
258775 | First Floor | First Floor | 0.905 | Up to level: First Floor | 1.635 | 2.54 | 4 | 6.54 | 2 | 4
263355 | First Floor | First Floor | 0 | Up to level: Second Floor | 4.57 | 0 | 3.87 | 20.0381 | 2 | 2
285990 | Second Floor | Second Floor | 0 | Up to level: Second Floor | 2.4 | 2.4 | 4.95277 | 11.7379 | 3 | 1
295590 | Second Floor | Second Floor | 0 | Up to level: Roof - Main | 4.578 | -0.102 | 4.137 | 8.91992 | 2 | 1
296057 | Second Floor | Second Floor | 3.07 | Up to level: Roof - Main | 1.508 | -0.102 | 5.86 | 9.15689 | 3 | 1
298261 | Roof - Main | Roof - Main | 0 |  | 4.578 | -0.102 | 7.87031 | 12.3016 | 5 | 1
300135 | Roof - Main | Roof - Main | 0 |  | 4.578 | -0.102 | 8.31148 | 12.5546 | 5 | 1
301675 | Roof - Main | Roof - Main | 1.067 |  | 4.458 | -0.102 | 7.91637 | 22.9198 | 5 | 1
303219 | Roof - Main | Roof - Main | 1.067 |  | 1.8 | -0.102 | 5.18 | 9.324 | 3 | 1
374952 | Roof - Main | Roof - Main | 1.067 |  | 1.8 | -0.102 | 3.89 | 7.002 | 2 | 1
375176 | Roof - Main | Roof - Main | 1.067 |  | 1.8 | -0.102 | 6.905 | 12.429 | 4 | 1
379197 | Second Floor | Second Floor | 0 | Up to level: Second Floor | 2.4 | 2.4 | 11.018 | 26.3784 | 7 | 1
379239 | Second Floor | Second Floor | 0 | Up to level: Second Floor | 2.4 | 2.4 | 4.95277 | 11.7379 | 3 | 1
381804 | Roof - Main | Roof - Main | 0 |  | 4.578 | -0.102 | 7.87031 | 12.3016 | 5 | 1
381859 | Roof - Main | Roof - Main | 1.067 |  | 1.8 | -0.102 | 5.18 | 9.324 | 3 | 1
381965 | Roof - Main | Roof - Main | 1.067 |  | 1.8 | -0.102 | 3.89 | 7.002 | 2 | 1
381976 | Roof - Main | Roof - Main | 1.067 |  | 1.8 | -0.102 | 6.905 | 12.429 | 4 | 1

# IfcDoor: 0865 x 1500mm (6)
Type - OperationType: SINGLE_SWING_LEFT; ParameterTakesPrecedence: no; Sizeable: no
OverallHeight: 1.5 m; OverallWidth: 0.865 m
Pset_DoorCommon - Reference: M_Toilet Partition:0865 x 1500mm; IsExternal: no; FireRating: Fire Rating
PSet_Revit_Other - InstallationDate: InstallationDate; SerialNumber: SerialNumber; WarrantyStartDate: WarrantyStartDate; BarCode: BarCode; AssetIdentifier: AssetIdentifier
PSet_Revit_Phasing - Phase Created: New Construction
PSet_Revit_Type_Dimensions - Thickness: 0.025 m; Height: 1.5 m; Width: 0.865 m
PSet_Revit_Type_Construction - Function: 0; Wall Closure: 0; Construction Type: Construction Type
PSet_Revit_Type_Materials and Finishes - Door Material: Laminate - Ivory, Matte
PSet_Revit_Type_Identity Data - Manufacturer: Manufacturer; Type Mark: 56; Fire Rating: Fire Rating; OmniClass Number: 23.30.10.00; OmniClass Title: Doors
PSet_Revit_Type_Other - AccessibilityPerformance: AccessibilityPerformance; CodePerformance: CodePerformance; IsFireExit: IsFireExit; GlazingAreaFraction: GlazingAreaFraction; OperationType: OperationType; Area: Area; Color: Color; Constituents: Constituents; Features: Features; Finish: Finish; Grade: Grade; Material: Material; ModelReference: ModelReference; NominalHeight: NominalHeight; NominalLength: NominalLength; NominalWidth: NominalWidth; ProductionYear: ProductionYear; Reference: Reference; Shape: Shape; Size: Size; SustainabilityPerformance: SustainabilityPerformance; WarrantyDescription: WarrantyDescription; WarrantyDurationLabor: WarrantyDurationLabor; WarrantyDurationParts: WarrantyDurationParts; WarrantyGuarantorLabor: WarrantyGuarantorLabor; WarrantyGuarantorParts: WarrantyGuarantorParts; ExpectedLife: ExpectedLife; ReplacementCost: ReplacementCost; AssetAccountingType: FIXED; ModelLabel: ModelLabel
Name (M_Toilet Partition:0865 x 1500mm:0865 x 1500mm:...) | In | Level | Sill Height (m) | Head Height (m) | TagNumber = Mark
408825 | Second Floor | Second Floor | 0 | 1.5 | 2C07tp1
411832 | First Floor | First Floor | 0.25 | 1.75 | 1A09tp1
412670 | First Floor | First Floor | 0.25 | 1.75 | 1A09tp2
413234 | Second Floor | Second Floor | 0.25 | 1.75 | 2C24tp1
413317 | Second Floor | Second Floor | 0.25 | 1.75 | 2C24tp2
237666 | Second Floor | Second Floor | 0 | 1.5 | 2C08tp1

# IfcDoor: 0865 x 1500mm (2)
Type - OperationType: SINGLE_SWING_RIGHT; ParameterTakesPrecedence: no; Sizeable: no
OverallHeight: 1.5 m; OverallWidth: 0.865 m
Pset_DoorCommon - Reference: M_Toilet Partition:0865 x 1500mm; IsExternal: no; FireRating: Fire Rating
PSet_Revit_Constraints - Sill Height: 0.25 m
PSet_Revit_Other - Head Height: 1.75 m; InstallationDate: InstallationDate; SerialNumber: SerialNumber; WarrantyStartDate: WarrantyStartDate; BarCode: BarCode; AssetIdentifier: AssetIdentifier
PSet_Revit_Phasing - Phase Created: New Construction
PSet_Revit_Type_Dimensions - Thickness: 0.025 m; Height: 1.5 m; Width: 0.865 m
PSet_Revit_Type_Construction - Function: 0; Wall Closure: 0; Construction Type: Construction Type
PSet_Revit_Type_Materials and Finishes - Door Material: Laminate - Ivory, Matte
PSet_Revit_Type_Identity Data - Manufacturer: Manufacturer; Type Mark: 56; Fire Rating: Fire Rating; OmniClass Number: 23.30.10.00; OmniClass Title: Doors
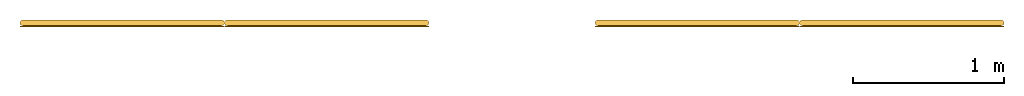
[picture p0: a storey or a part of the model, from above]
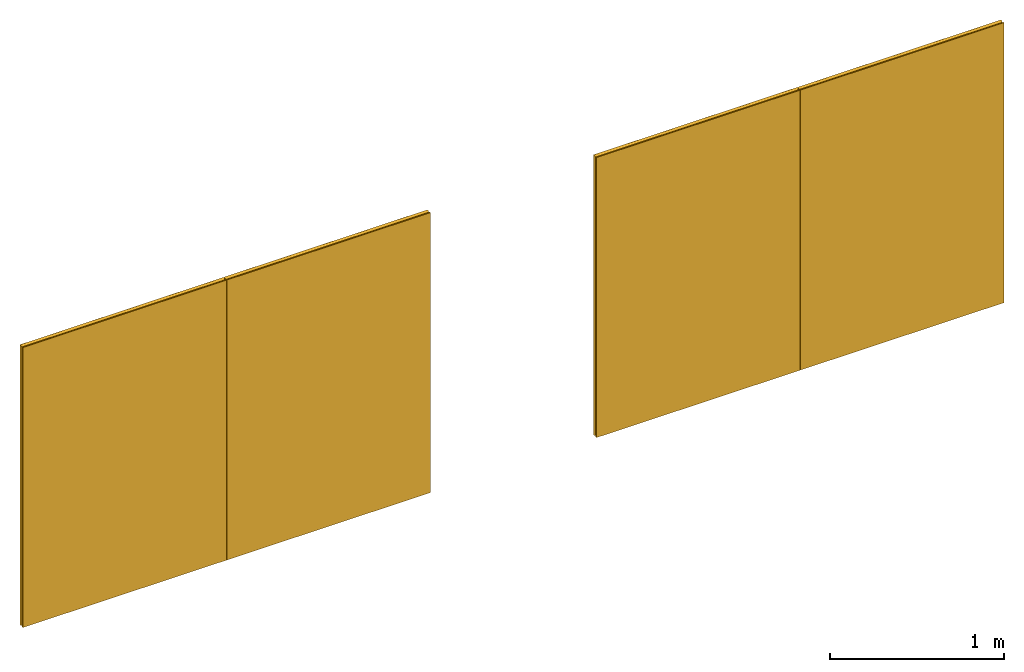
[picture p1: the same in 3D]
Properties of the parts of a building model (IFC2X3), part 3 of 11

# IfcDoor: 0865 x 1500mm (2)
PSet_Revit_Type_Other - AccessibilityPerformance: AccessibilityPerformance; CodePerformance: CodePerformance; IsFireExit: IsFireExit; GlazingAreaFraction: GlazingAreaFraction; OperationType: OperationType; Area: Area; Color: Color; Constituents: Constituents; Features: Features; Finish: Finish; Grade: Grade; Material: Material; ModelReference: ModelReference; NominalHeight: NominalHeight; NominalLength: NominalLength; NominalWidth: NominalWidth; ProductionYear: ProductionYear; Reference: Reference; Shape: Shape; Size: Size; SustainabilityPerformance: SustainabilityPerformance; WarrantyDescription: WarrantyDescription; WarrantyDurationLabor: WarrantyDurationLabor; WarrantyDurationParts: WarrantyDurationParts; WarrantyGuarantorLabor: WarrantyGuarantorLabor; WarrantyGuarantorParts: WarrantyGuarantorParts; ExpectedLife: ExpectedLife; ReplacementCost: ReplacementCost; AssetAccountingType: FIXED; ModelLabel: ModelLabel
Name (M_Toilet Partition:0865 x 1500mm:0865 x 1500mm:...) | In | Level | TagNumber = Mark
412771 | First Floor | First Floor | 1A12tp1
412955 | Second Floor | Second Floor | 2C23tp1

# IfcDoor: 0915 x 2134mm (102)
Type - OperationType: SINGLE_SWING_LEFT; ParameterTakesPrecedence: no; Sizeable: no
OverallHeight: 2.134 m; OverallWidth: 0.915 m
Pset_DoorCommon - Reference: M_Single-Flush:0915 x 2134mm; IsExternal: no; FireRating: Fire Rating
PSet_Revit_Constraints - Sill Height: 0 m
PSet_Revit_Other - Head Height: 2.134 m; InstallationDate: InstallationDate; SerialNumber: SerialNumber; WarrantyStartDate: WarrantyStartDate; BarCode: BarCode; AssetIdentifier: AssetIdentifier
PSet_Revit_Phasing - Phase Created: New Construction
PSet_Revit_Type_Dimensions - Thickness: 0.051 m; Height: 2.134 m; Trim Projection Ext: 0.025 m; Trim Projection Int: 0.025 m; Trim Width: 0.076 m; Width: 0.915 m
PSet_Revit_Type_Construction - Function: 0; Wall Closure: 0; Construction Type: Construction Type
PSet_Revit_Type_Materials and Finishes - Door Material: Door - Panel; Frame Material: Door - Frame
PSet_Revit_Type_Identity Data - Manufacturer: Manufacturer; Type Mark: 20; Fire Rating: Fire Rating; OmniClass Number: 23.30.10.00; OmniClass Title: Doors
PSet_Revit_Type_Other - AccessibilityPerformance: AccessibilityPerformance; CodePerformance: CodePerformance; IsFireExit: IsFireExit; GlazingAreaFraction: GlazingAreaFraction; OperationType: OperationType; Area: Area; Color: Color; Constituents: Constituents; Features: Features; Finish: Finish; Grade: Grade; Material: Material; ModelReference: ModelReference; NominalHeight: NominalHeight; NominalLength: NominalLength; NominalWidth: NominalWidth; ProductionYear: ProductionYear; Reference: Reference; Shape: Shape; Size: Size; SustainabilityPerformance: SustainabilityPerformance; WarrantyDescription: WarrantyDescription; WarrantyDurationLabor: WarrantyDurationLabor; WarrantyDurationParts: WarrantyDurationParts; WarrantyGuarantorLabor: WarrantyGuarantorLabor; WarrantyGuarantorParts: WarrantyGuarantorParts; ExpectedLife: ExpectedLife; ReplacementCost: ReplacementCost; AssetAccountingType: FIXED; ModelLabel: ModelLabel
Name (M_Single-Flush:0915 x 2134mm:0915 x 2134mm:...) | In | Level | TagNumber = Mark
221992 | First Floor | First Floor | 1C16
222050 | First Floor | First Floor | 1C14
222117 | First Floor | First Floor | 1C12
222740 | First Floor | First Floor | 1C09
222929 | First Floor | First Floor | 1C08
223212 | First Floor | First Floor | 1C06
223301 | First Floor | First Floor | 1C02
223378 | First Floor | First Floor | 1C10
223504 | First Floor | First Floor | 1A09
223773 | First Floor | First Floor | 1A08
223957 | First Floor | First Floor | 1A07
224146 | First Floor | First Floor | 1A05
224207 | First Floor | First Floor | 1A03
224424 | First Floor | First Floor | 1A15
224561 | First Floor | First Floor | 1AC4
224600 | First Floor | First Floor | 1AC2
224653 | First Floor | First Floor | 1D02
224873 | First Floor | First Floor | 1DC2
224980 | First Floor | First Floor | 1D05
225128 | First Floor | First Floor | 1D06A
225305 | First Floor | First Floor | 1D07
225574 | First Floor | First Floor | 1D11
225761 | First Floor | First Floor | 1D12
225828 | First Floor | First Floor | 1D10
226135 | First Floor | First Floor | 1D19
226564 | First Floor | First Floor | 1C17
226850 | First Floor | First Floor | 1D22A
226967 | First Floor | First Floor | 1D23
227366 | First Floor | First Floor | 1D26
227536 | First Floor | First Floor | 1D28
227769 | First Floor | First Floor | 1D34
228297 | First Floor | First Floor | 1B13
228575 | First Floor | First Floor | 1B01
229319 | First Floor | First Floor | 1B09
229539 | First Floor | First Floor | 1B10
229578 | First Floor | First Floor | 1B04a
230556 | First Floor | First Floor | 1B17
230814 | First Floor | First Floor | 1E02
230949 | First Floor | First Floor | 1E01
231041 | First Floor | First Floor | 1E29
231213 | First Floor | First Floor | 1E26
231377 | First Floor | First Floor | 1E27
231990 | First Floor | First Floor | 1E10
232154 | First Floor | First Floor | 1E12
232339 | First Floor | First Floor | 1E08
232576 | First Floor | First Floor | 1E06
232828 | First Floor | First Floor | 1E14
233072 | First Floor | First Floor | 1E16
233264 | First Floor | First Floor | 1E18
234428 | Second Floor | Second Floor | 2C13
234926 | Second Floor | Second Floor | 2C15
235194 | Second Floor | Second Floor | 2C07
235450 | Second Floor | Second Floor | 2C03
235529 | Second Floor | Second Floor | 2C01
236673 | Second Floor | Second Floor | 2A04
236858 | Second Floor | Second Floor | 2A13
236916 | Second Floor | Second Floor | 2A12
236942 | Second Floor | Second Floor | 2A11A
237063 | Second Floor | Second Floor | 2A01
237102 | Second Floor | Second Floor | 2A14
237452 | Second Floor | Second Floor | 2C22
237743 | Second Floor | Second Floor | 2C10
237881 | Second Floor | Second Floor | 2C12
238011 | Second Floor | Second Floor | 2C18
238096 | Second Floor | Second Floor | 2CC1
238499 | Second Floor | Second Floor | 2DC2
238538 | Second Floor | Second Floor | 2D06A
238815 | Second Floor | Second Floor | 2D01
239241 | Second Floor | Second Floor | 2BC6
239326 | Second Floor | Second Floor | 2B10
239383 | Second Floor | Second Floor | 2B9
239432 | Second Floor | Second Floor | 2B8
239639 | Second Floor | Second Floor | 2B4
239694 | Second Floor | Second Floor | 2B5
239799 | Second Floor | Second Floor | 2BC4
239888 | Second Floor | Second Floor | 2B01
240003 | Second Floor | Second Floor | 2B3
240928 | Second Floor | Second Floor | 2B17
241049 | Second Floor | Second Floor | 2B15
241616 | Second Floor | Second Floor | 2D11
241681 | Second Floor | Second Floor | 2D13
241822 | Second Floor | Second Floor | 2D15
241869 | Second Floor | Second Floor | 2D17
242080 | Second Floor | Second Floor | 2BC3
242262 | Second Floor | Second Floor | 2B16
250444 | Second Floor | Second Floor | 2A11
250602 | Second Floor | Second Floor | 2D20A
350102 | First Floor | First Floor | 1E03
355218 | First Floor | First Floor | 1D40A
364769 | First Floor | First Floor | 1C03
402047 | First Floor | First Floor | 1D01
225637 | First Floor | First Floor | 1D16
226297 | First Floor | First Floor | 1D18
227026 | First Floor | First Floor | 1D24
227305 | First Floor | First Floor | 1D33A
229736 | First Floor | First Floor | 1B14
229819 | First Floor | First Floor | 1B16
231726 | First Floor | First Floor | 1E30
237121 | Second Floor | Second Floor | 2C24
238316 | Second Floor | Second Floor | 2D08
238438 | Second Floor | Second Floor | 2D06
241351 | Second Floor | Second Floor | 2D21

# IfcDoor: 0915 x 2134mm (113)
Type - OperationType: SINGLE_SWING_RIGHT; ParameterTakesPrecedence: no; Sizeable: no
OverallHeight: 2.134 m; OverallWidth: 0.915 m
Pset_DoorCommon - Reference: M_Single-Flush:0915 x 2134mm; IsExternal: no; FireRating: Fire Rating
PSet_Revit_Constraints - Sill Height: 0 m
PSet_Revit_Other - Head Height: 2.134 m; InstallationDate: InstallationDate; SerialNumber: SerialNumber; WarrantyStartDate: WarrantyStartDate; BarCode: BarCode; AssetIdentifier: AssetIdentifier
PSet_Revit_Phasing - Phase Created: New Construction
PSet_Revit_Type_Dimensions - Thickness: 0.051 m; Height: 2.134 m; Trim Projection Ext: 0.025 m; Trim Projection Int: 0.025 m; Trim Width: 0.076 m; Width: 0.915 m
PSet_Revit_Type_Construction - Function: 0; Wall Closure: 0; Construction Type: Construction Type
PSet_Revit_Type_Materials and Finishes - Door Material: Door - Panel; Frame Material: Door - Frame
PSet_Revit_Type_Identity Data - Manufacturer: Manufacturer; Type Mark: 20; Fire Rating: Fire Rating; OmniClass Number: 23.30.10.00; OmniClass Title: Doors
PSet_Revit_Type_Other - AccessibilityPerformance: AccessibilityPerformance; CodePerformance: CodePerformance; IsFireExit: IsFireExit; GlazingAreaFraction: GlazingAreaFraction; OperationType: OperationType; Area: Area; Color: Color; Constituents: Constituents; Features: Features; Finish: Finish; Grade: Grade; Material: Material; ModelReference: ModelReference; NominalHeight: NominalHeight; NominalLength: NominalLength; NominalWidth: NominalWidth; ProductionYear: ProductionYear; Reference: Reference; Shape: Shape; Size: Size; SustainabilityPerformance: SustainabilityPerformance; WarrantyDescription: WarrantyDescription; WarrantyDurationLabor: WarrantyDurationLabor; WarrantyDurationParts: WarrantyDurationParts; WarrantyGuarantorLabor: WarrantyGuarantorLabor; WarrantyGuarantorParts: WarrantyGuarantorParts; ExpectedLife: ExpectedLife; ReplacementCost: ReplacementCost; AssetAccountingType: FIXED; ModelLabel: ModelLabel
Name (M_Single-Flush:0915 x 2134mm:0915 x 2134mm:...) | In | Level | TagNumber | Mark
221919 | First Floor | First Floor | 1C19 | 1C19
222344 | First Floor | First Floor | 1C18 | 1C18
223030 | First Floor | First Floor | 1C05 | 1C05
223137 | First Floor | First Floor | 1C04 | 1C04
223429 | First Floor | First Floor | 1C07 | 1C07
223457 | First Floor | First Floor | 1CC1 | 1CC1
223667 | First Floor | First Floor | 1A12 | 1A12
223704 | First Floor | First Floor | 1A10 | 1A10
223840 | First Floor | First Floor | 1A11 | 1A11
224018 | First Floor | First Floor | 1A06 | 1A06
224077 | First Floor | First Floor | 1A04 | 1A04
224302 | First Floor | First Floor | 1AC5 | 1AC5
224343 | First Floor | First Floor | 1A15a | 1A15a
224469 | First Floor | First Floor | 1A13 | 1A13
225051 | First Floor | First Floor | 1D06 | 1D06
225472 | First Floor | First Floor | 1D09 | 1D09
225517 | First Floor | First Floor | 1D13 | 1D13
225680 | First Floor | First Floor | 1D14 | 1D14
225883 | First Floor | First Floor | 1D08 | 1D08
225922 | First Floor | First Floor | 1DC4 | 1DC4
226204 | First Floor | First Floor | 1D20 | 1D20
226489 | First Floor | First Floor | 1C18A | 1C18A
226625 | First Floor | First Floor | 1C15 | 1C15
226737 | First Floor | First Floor | 1D22 | 1D22
227136 | First Floor | First Floor | 1D30 | 1D30
227199 | First Floor | First Floor | 1D33 | 1D33
227455 | First Floor | First Floor | 1D25 | 1D25
227615 | First Floor | First Floor | 1D32 | 1D32
227830 | First Floor | First Floor | 1D36 | 1D36
227879 | First Floor | First Floor | 1D38 | 1D38
227926 | First Floor | First Floor | 1D40 | 1D40
228354 | First Floor | First Floor | 1B15 | 1B15
228516 | First Floor | First Floor | 1BC2 | 1BC2
228650 | First Floor | First Floor | 1B03 | 1B03
228897 | First Floor | First Floor | 1BC1 | 1BC1
228938 | First Floor | First Floor | 1B02 | 1B02
228981 | First Floor | First Floor | 1B04 | 1B04
229120 | First Floor | First Floor | 1B05 | 1B05
229157 | First Floor | First Floor | 1B07 | 1B07
229354 | First Floor | First Floor | 1B11 | 1B11
229427 | First Floor | First Floor | 1B06 | 1B06
229478 | First Floor | First Floor | 1B08 | 1B08
230607 | First Floor | First Floor | 1B23 | 1B23
230738 | First Floor | First Floor | 1B21 | 1B21
230994 | First Floor | First Floor | 1E04 | 1E04
231180 | First Floor | First Floor | 1EC1 | 1EC1
231274 | First Floor | First Floor | 1E25 | 1E25
231452 | First Floor | First Floor | 1E28 | 1E28
231651 | First Floor | First Floor | 1E22 | 1E22
231755 | First Floor | First Floor | 1E23 | 1E23
232087 | First Floor | First Floor | 1E09 | 1E09
232239 | First Floor | First Floor | 1E11 | 1E11
232292 | First Floor | First Floor | 1E33 | 1E33
232388 | First Floor | First Floor | 1E07A | 1E07A
232467 | First Floor | First Floor | 1E07 | 1E07
232789 | First Floor | First Floor | 1EC3 | 1EC3
233169 | First Floor | First Floor | 1E19 | 1E19
234077 | First Floor | First Floor | 1D39 | 1D39
234202 | First Floor | First Floor | 1DC8 | 1DC8
234796 | Second Floor | Second Floor | 2CC3A | 2CC3A
234843 | Second Floor | Second Floor | 2C17 | 2C17
235137 | Second Floor | Second Floor | 2C05 | 2C05
235326 | Second Floor | Second Floor | 2CC3 | 2CC3
235604 | Second Floor | Second Floor | 2AC2 | 2AC2
236780 | Second Floor | Second Floor | 2A03 | 2A03
236819 | Second Floor | Second Floor | 2A02 | 2A02
236966 | Second Floor | Second Floor | 2AC5 | 2AC5
237365 | Second Floor | Second Floor | 2C23 | 2C23
237928 | Second Floor | Second Floor | 2C19 | 2C19
238171 | Second Floor | Second Floor | 2D09 | 2D09
238617 | Second Floor | Second Floor | 2D04A | 2D04A
238748 | Second Floor | Second Floor | 2D04 | 2D04
238886 | Second Floor | Second Floor | 2D02 | 2D02
238921 | Second Floor | Second Floor | 2D03 | 2D03
239113 | Second Floor | Second Floor | 2BC2 | 2BC2
239186 | Second Floor | Second Floor | 2BC1 | 2BC1
239511 | Second Floor | Second Floor | 2B6 | 2B6
239590 | Second Floor | Second Floor | 2B7 | 2B7
240310 | Second Floor | Second Floor | 2B2 | 2B2
240347 | Second Floor | Second Floor | 2B24 | 2B24
240436 | Second Floor | Second Floor | 2B25 | 2B25
240501 | Second Floor | Second Floor | 2B23 | 2B23
240588 | Second Floor | Second Floor | 2B19 | 2B19
240676 | Second Floor | Second Floor | 2B22 | 2B22
240742 | Second Floor | Second Floor | 2B21 | 2B21
240845 | Second Floor | Second Floor | 2B20 | 2B20
241124 | Second Floor | Second Floor | 2B14 | 2B14
241191 | Second Floor | Second Floor | 2B13 | 2B13
241266 | Second Floor | Second Floor | 2B13 | 2B12
241581 | Second Floor | Second Floor | 2D10 | 2D10
241748 | Second Floor | Second Floor | 2D16 | 2D16
241789 | Second Floor | Second Floor | 2D14 | 2D14
241966 | Second Floor | Second Floor | 2D19 | 2D19
242003 | Second Floor | Second Floor | 2D20 | 2D20
242319 | Second Floor | Second Floor | 2B18 | 2B18
250515 | Second Floor | Second Floor | 2AC2A | 2AC2A
403890 | First Floor | First Floor | 1DC5 | 1DC5
226378 | First Floor | First Floor | 1D21 | 1D21
226666 | First Floor | First Floor | 1C13 | 1C13
227089 | First Floor | First Floor | 1D27 | 1D27
227228 | First Floor | First Floor | 1D31 | 1D31
227652 | First Floor | First Floor | 1D35 | 1D35
229671 | First Floor | First Floor | 1B12 | 1B12
230781 | First Floor | First Floor | 1BC4 | 1BC4
234389 | Second Floor | Second Floor | 2C16 | 2C16
234745 | Second Floor | Second Floor | 2C11 | 2C11
234995 | Second Floor | Second Floor | 2C09 | 2C09
235051 | Second Floor | Second Floor | 2C06 | 2C06
235096 | Second Floor | Second Floor | 2C04 | 2C04
235395 | Second Floor | Second Floor | 2C08 | 2C08
238379 | Second Floor | Second Floor | 2D07 | 2D07
241448 | Second Floor | Second Floor | 2D21A | 2D21A
362567 | First Floor | First Floor | 1D17 | 1D17

# IfcDoor: 0915 x 2134mm Exterior (2)
In: First Floor
Type - OperationType: SINGLE_SWING_LEFT; ParameterTakesPrecedence: no; Sizeable: no
OverallHeight: 2.134 m; OverallWidth: 0.915 m
Pset_DoorCommon - Reference: M_Single-Flush:0915 x 2134mm Exterior; IsExternal: yes; FireRating: Fire Rating
PSet_Revit_Constraints - Level: First Floor; Sill Height: 0 m
PSet_Revit_Other - Head Height: 2.134 m; InstallationDate: InstallationDate; SerialNumber: SerialNumber; WarrantyStartDate: WarrantyStartDate; BarCode: BarCode; AssetIdentifier: AssetIdentifier
PSet_Revit_Phasing - Phase Created: New Construction
PSet_Revit_Type_Dimensions - Thickness: 0.051 m; Height: 2.134 m; Trim Projection Ext: 0.025 m; Trim Projection Int: 0.025 m; Trim Width: 0.076 m; Width: 0.915 m
PSet_Revit_Type_Construction - Function: 1; Wall Closure: 0; Construction Type: Construction Type
PSet_Revit_Type_Materials and Finishes - Door Material: Door - Panel; Frame Material: Door - Frame
PSet_Revit_Type_Identity Data - Manufacturer: Manufacturer; Type Mark: 59; Fire Rating: Fire Rating; OmniClass Number: 23.30.10.00; OmniClass Title: Doors
PSet_Revit_Type_Other - AccessibilityPerformance: AccessibilityPerformance; CodePerformance: CodePerformance; IsFireExit: IsFireExit; GlazingAreaFraction: GlazingAreaFraction; OperationType: OperationType; Area: Area; Color: Color; Constituents: Constituents; Features: Features; Finish: Finish; Grade: Grade; Material: Material; ModelReference: ModelReference; NominalHeight: NominalHeight; NominalLength: NominalLength; NominalWidth: NominalWidth; ProductionYear: ProductionYear; Reference: Reference; Shape: Shape; Size: Size; SustainabilityPerformance: SustainabilityPerformance; WarrantyDescription: WarrantyDescription; WarrantyDurationLabor: WarrantyDurationLabor; WarrantyDurationParts: WarrantyDurationParts; WarrantyGuarantorLabor: WarrantyGuarantorLabor; WarrantyGuarantorParts: WarrantyGuarantorParts; ExpectedLife: ExpectedLife; ReplacementCost: ReplacementCost; AssetAccountingType: FIXED; ModelLabel: ModelLabel
Name (M_Single-Flush:0915 x 2134mm Exterior:0915 x 2134mm Exterior:...) | TagNumber = Mark
231495 | 1E20
233711 | 1E17

# IfcDoor: 0915 x 2134mm Exterior (5)
In: First Floor
Type - OperationType: SINGLE_SWING_RIGHT; ParameterTakesPrecedence: no; Sizeable: no
OverallHeight: 2.134 m; OverallWidth: 0.915 m
Pset_DoorCommon - Reference: M_Single-Flush:0915 x 2134mm Exterior; IsExternal: yes; FireRating: Fire Rating
PSet_Revit_Constraints - Level: First Floor; Sill Height: 0 m
PSet_Revit_Other - Head Height: 2.134 m; InstallationDate: InstallationDate; SerialNumber: SerialNumber; WarrantyStartDate: WarrantyStartDate; BarCode: BarCode; AssetIdentifier: AssetIdentifier
PSet_Revit_Phasing - Phase Created: New Construction
PSet_Revit_Type_Dimensions - Thickness: 0.051 m; Height: 2.134 m; Trim Projection Ext: 0.025 m; Trim Projection Int: 0.025 m; Trim Width: 0.076 m; Width: 0.915 m
PSet_Revit_Type_Construction - Function: 1; Wall Closure: 0; Construction Type: Construction Type
PSet_Revit_Type_Materials and Finishes - Door Material: Door - Panel; Frame Material: Door - Frame
PSet_Revit_Type_Identity Data - Manufacturer: Manufacturer; Type Mark: 59; Fire Rating: Fire Rating; OmniClass Number: 23.30.10.00; OmniClass Title: Doors
PSet_Revit_Type_Other - AccessibilityPerformance: AccessibilityPerformance; CodePerformance: CodePerformance; IsFireExit: IsFireExit; GlazingAreaFraction: GlazingAreaFraction; OperationType: OperationType; Area: Area; Color: Color; Constituents: Constituents; Features: Features; Finish: Finish; Grade: Grade; Material: Material; ModelReference: ModelReference; NominalHeight: NominalHeight; NominalLength: NominalLength; NominalWidth: NominalWidth; ProductionYear: ProductionYear; Reference: Reference; Shape: Shape; Size: Size; SustainabilityPerformance: SustainabilityPerformance; WarrantyDescription: WarrantyDescription; WarrantyDurationLabor: WarrantyDurationLabor; WarrantyDurationParts: WarrantyDurationParts; WarrantyGuarantorLabor: WarrantyGuarantorLabor; WarrantyGuarantorParts: WarrantyGuarantorParts; ExpectedLife: ExpectedLife; ReplacementCost: ReplacementCost; AssetAccountingType: FIXED; ModelLabel: ModelLabel
Name (M_Single-Flush:0915 x 2134mm Exterior:0915 x 2134mm Exterior:...) | TagNumber = Mark
222415 | 1CC3
231622 | 1E21
232975 | 1EC1A
252441 | 1AC3
252490 | 1AC5a

# IfcDoor: 0915 x 2134mm Rated (3)
Type - OperationType: SINGLE_SWING_LEFT; ParameterTakesPrecedence: no; Sizeable: no
OverallHeight: 2.134 m; OverallWidth: 0.915 m
Pset_DoorCommon - Reference: M_Single-Flush:0915 x 2134mm Rated; IsExternal: no; FireRating: Fire Rating
PSet_Revit_Constraints - Sill Height: 0 m
PSet_Revit_Other - Head Height: 2.134 m; InstallationDate: InstallationDate; SerialNumber: SerialNumber; WarrantyStartDate: WarrantyStartDate; BarCode: BarCode; AssetIdentifier: AssetIdentifier
PSet_Revit_Phasing - Phase Created: New Construction
PSet_Revit_Type_Dimensions - Thickness: 0.051 m; Height: 2.134 m; Trim Projection Ext: 0.025 m; Trim Projection Int: 0.025 m; Trim Width: 0.076 m; Width: 0.915 m
PSet_Revit_Type_Construction - Function: 0; Wall Closure: 0; Construction Type: Construction Type
PSet_Revit_Type_Materials and Finishes - Door Material: Door - Panel; Frame Material: Door - Frame
PSet_Revit_Type_Identity Data - Manufacturer: Manufacturer; Type Mark: 61; Fire Rating: Fire Rating; OmniClass Number: 23.30.10.00; OmniClass Title: Doors
PSet_Revit_Type_Other - AccessibilityPerformance: AccessibilityPerformance; CodePerformance: CodePerformance; IsFireExit: IsFireExit; GlazingAreaFraction: GlazingAreaFraction; OperationType: OperationType; Area: Area; Color: Color; Constituents: Constituents; Features: Features; Finish: Finish; Grade: Grade; Material: Material; ModelReference: ModelReference; NominalHeight: NominalHeight; NominalLength: NominalLength; NominalWidth: NominalWidth; ProductionYear: ProductionYear; Reference: Reference; Shape: Shape; Size: Size; SustainabilityPerformance: SustainabilityPerformance; WarrantyDescription: WarrantyDescription; WarrantyDurationLabor: WarrantyDurationLabor; WarrantyDurationParts: WarrantyDurationParts; WarrantyGuarantorLabor: WarrantyGuarantorLabor; WarrantyGuarantorParts: WarrantyGuarantorParts; ExpectedLife: ExpectedLife; ReplacementCost: ReplacementCost; AssetAccountingType: FIXED; ModelLabel: ModelLabel
Name (M_Single-Flush:0915 x 2134mm Rated:0915 x 2134mm Rated:...) | In | Level | TagNumber = Mark
222571 | First Floor | First Floor | 1CS3
230209 | First Floor | First Floor | 1BS2
234664 | Second Floor | Second Floor | 2CS3

# IfcDoor: 0915 x 2134mm Rated (2)
Type - OperationType: SINGLE_SWING_RIGHT; ParameterTakesPrecedence: no; Sizeable: no
OverallHeight: 2.134 m; OverallWidth: 0.915 m
Pset_DoorCommon - Reference: M_Single-Flush:0915 x 2134mm Rated; IsExternal: no; FireRating: Fire Rating
PSet_Revit_Other - InstallationDate: InstallationDate; SerialNumber: SerialNumber; WarrantyStartDate: WarrantyStartDate; BarCode: BarCode; AssetIdentifier: AssetIdentifier
PSet_Revit_Phasing - Phase Created: New Construction
PSet_Revit_Type_Dimensions - Thickness: 0.051 m; Height: 2.134 m; Trim Projection Ext: 0.025 m; Trim Projection Int: 0.025 m; Trim Width: 0.076 m; Width: 0.915 m
PSet_Revit_Type_Construction - Function: 0; Wall Closure: 0; Construction Type: Construction Type
PSet_Revit_Type_Materials and Finishes - Door Material: Door - Panel; Frame Material: Door - Frame
PSet_Revit_Type_Identity Data - Manufacturer: Manufacturer; Type Mark: 61; Fire Rating: Fire Rating; OmniClass Number: 23.30.10.00; OmniClass Title: Doors
PSet_Revit_Type_Other - AccessibilityPerformance: AccessibilityPerformance; CodePerformance: CodePerformance; IsFireExit: IsFireExit; GlazingAreaFraction: GlazingAreaFraction; OperationType: OperationType; Area: Area; Color: Color; Constituents: Constituents; Features: Features; Finish: Finish; Grade: Grade; Material: Material; ModelReference: ModelReference; NominalHeight: NominalHeight; NominalLength: NominalLength; NominalWidth: NominalWidth; ProductionYear: ProductionYear; Reference: Reference; Shape: Shape; Size: Size; SustainabilityPerformance: SustainabilityPerformance; WarrantyDescription: WarrantyDescription; WarrantyDurationLabor: WarrantyDurationLabor; WarrantyDurationParts: WarrantyDurationParts; WarrantyGuarantorLabor: WarrantyGuarantorLabor; WarrantyGuarantorParts: WarrantyGuarantorParts; ExpectedLife: ExpectedLife; ReplacementCost: ReplacementCost; AssetAccountingType: FIXED; ModelLabel: ModelLabel
Name (M_Single-Flush:0915 x 2134mm Rated:0915 x 2134mm Rated:...) | In | Level | Sill Height (m) | Head Height (m) | TagNumber = Mark
242185 | Second Floor | Second Floor | 0 | 2.134 | 2BS2
471867 | First Floor | First Floor | 0.25 | 2.384 | 1E05

# IfcDoor: 1.220 x 2134mm, M_Single-Flush:1.220 x 2134mm:1.220 x 2134mm:230394
In: First Floor
Type - OperationType: SINGLE_SWING_RIGHT; ParameterTakesPrecedence: no; Sizeable: no
OverallHeight: 2.134 m; OverallWidth: 1.22 m
Pset_DoorCommon - Reference: M_Single-Flush:1.220 x 2134mm; IsExternal: no; FireRating: Fire Rating
PSet_Revit_Constraints - Level: First Floor; Sill Height: 0 m
PSet_Revit_Other - Head Height: 2.134 m; InstallationDate: InstallationDate; SerialNumber: SerialNumber; WarrantyStartDate: WarrantyStartDate; BarCode: BarCode; AssetIdentifier: AssetIdentifier; TagNumber: 1B19
PSet_Revit_Identity Data - Mark: 1B19
PSet_Revit_Phasing - Phase Created: New Construction
PSet_Revit_Type_Dimensions - Thickness: 0.051 m; Height: 2.134 m; Trim Projection Ext: 0.025 m; Trim Projection Int: 0.025 m; Trim Width: 0.076 m; Width: 1.22 m
PSet_Revit_Type_Construction - Function: 0; Wall Closure: 0; Construction Type: Construction Type
PSet_Revit_Type_Materials and Finishes - Door Material: Door - Panel; Frame Material: Door - Frame
PSet_Revit_Type_Identity Data - Manufacturer: Manufacturer; Type Mark: 60; Fire Rating: Fire Rating; OmniClass Number: 23.30.10.00; OmniClass Title: Doors
PSet_Revit_Type_Other - AccessibilityPerformance: AccessibilityPerformance; CodePerformance: CodePerformance; IsFireExit: IsFireExit; GlazingAreaFraction: GlazingAreaFraction; OperationType: OperationType; Area: Area; Color: Color; Constituents: Constituents; Features: Features; Finish: Finish; Grade: Grade; Material: Material; ModelReference: ModelReference; NominalHeight: NominalHeight; NominalLength: NominalLength; NominalWidth: NominalWidth; ProductionYear: ProductionYear; Reference: Reference; Shape: Shape; Size: Size; SustainabilityPerformance: SustainabilityPerformance; WarrantyDescription: WarrantyDescription; WarrantyDurationLabor: WarrantyDurationLabor; WarrantyDurationParts: WarrantyDurationParts; WarrantyGuarantorLabor: WarrantyGuarantorLabor; WarrantyGuarantorParts: WarrantyGuarantorParts; ExpectedLife: ExpectedLife; ReplacementCost: ReplacementCost; AssetAccountingType: FIXED; ModelLabel: ModelLabel

# IfcDoor: 1.220 x 2134mm Exterior, M_Single-Flush:1.220 x 2134mm Exterior:1.220 x 2134mm Exterior:233580
In: First Floor
Type - OperationType: SINGLE_SWING_RIGHT; ParameterTakesPrecedence: no; Sizeable: no
OverallHeight: 2.134 m; OverallWidth: 1.22 m
Pset_DoorCommon - Reference: M_Single-Flush:1.220 x 2134mm Exterior; IsExternal: yes; FireRating: Fire Rating
PSet_Revit_Constraints - Level: First Floor; Sill Height: 0 m
PSet_Revit_Other - Head Height: 2.134 m; InstallationDate: InstallationDate; SerialNumber: SerialNumber; WarrantyStartDate: WarrantyStartDate; BarCode: BarCode; AssetIdentifier: AssetIdentifier; TagNumber: 1EC4
PSet_Revit_Identity Data - Mark: 1EC4
PSet_Revit_Phasing - Phase Created: New Construction
PSet_Revit_Type_Dimensions - Thickness: 0.051 m; Height: 2.134 m; Trim Projection Ext: 0.025 m; Trim Projection Int: 0.025 m; Trim Width: 0.076 m; Width: 1.22 m
PSet_Revit_Type_Construction - Function: 1; Wall Closure: 0; Construction Type: Construction Type
PSet_Revit_Type_Materials and Finishes - Door Material: Door - Panel; Frame Material: Door - Frame
PSet_Revit_Type_Identity Data - Manufacturer: Manufacturer; Type Mark: 34; Fire Rating: Fire Rating; OmniClass Number: 23.30.10.00; OmniClass Title: Doors
PSet_Revit_Type_Other - AccessibilityPerformance: AccessibilityPerformance; CodePerformance: CodePerformance; IsFireExit: IsFireExit; GlazingAreaFraction: GlazingAreaFraction; OperationType: OperationType; Area: Area; Color: Color; Constituents: Constituents; Features: Features; Finish: Finish; Grade: Grade; Material: Material; ModelReference: ModelReference; NominalHeight: NominalHeight; NominalLength: NominalLength; NominalWidth: NominalWidth; ProductionYear: ProductionYear; Reference: Reference; Shape: Shape; Size: Size; SustainabilityPerformance: SustainabilityPerformance; WarrantyDescription: WarrantyDescription; WarrantyDurationLabor: WarrantyDurationLabor; WarrantyDurationParts: WarrantyDurationParts; WarrantyGuarantorLabor: WarrantyGuarantorLabor; WarrantyGuarantorParts: WarrantyGuarantorParts; ExpectedLife: ExpectedLife; ReplacementCost: ReplacementCost; AssetAccountingType: FIXED; ModelLabel: ModelLabel

# IfcDoor: 1000 x 2134mm, M_Single-Flush:1000 x 2134mm:1000 x 2134mm:230127
In: First Floor
Type - OperationType: SINGLE_SWING_RIGHT; ParameterTakesPrecedence: no; Sizeable: no
OverallHeight: 2.134 m; OverallWidth: 1 m
Pset_DoorCommon - Reference: M_Single-Flush:1000 x 2134mm; IsExternal: no; FireRating: Fire Rating
PSet_Revit_Constraints - Level: First Floor; Sill Height: 0 m
PSet_Revit_Other - Head Height: 2.134 m; InstallationDate: InstallationDate; SerialNumber: SerialNumber; WarrantyStartDate: WarrantyStartDate; BarCode: BarCode; AssetIdentifier: AssetIdentifier; TagNumber: 1BC3
PSet_Revit_Identity Data - Mark: 1BC3
PSet_Revit_Phasing - Phase Created: New Construction
PSet_Revit_Type_Dimensions - Thickness: 0.051 m; Height: 2.134 m; Trim Projection Ext: 0.025 m; Trim Projection Int: 0.025 m; Trim Width: 0.076 m; Width: 1 m
PSet_Revit_Type_Construction - Function: 0; Wall Closure: 0; Construction Type: Construction Type
PSet_Revit_Type_Materials and Finishes - Door Material: Door - Panel; Frame Material: Door - Frame
PSet_Revit_Type_Identity Data - Manufacturer: Manufacturer; Type Mark: 33; Fire Rating: Fire Rating; OmniClass Number: 23.30.10.00; OmniClass Title: Doors
PSet_Revit_Type_Other - AccessibilityPerformance: AccessibilityPerformance; CodePerformance: CodePerformance; IsFireExit: IsFireExit; GlazingAreaFraction: GlazingAreaFraction; OperationType: OperationType; Area: Area; Color: Color; Constituents: Constituents; Features: Features; Finish: Finish; Grade: Grade; Material: Material; ModelReference: ModelReference; NominalHeight: NominalHeight; NominalLength: NominalLength; NominalWidth: NominalWidth; ProductionYear: ProductionYear; Reference: Reference; Shape: Shape; Size: Size; SustainabilityPerformance: SustainabilityPerformance; WarrantyDescription: WarrantyDescription; WarrantyDurationLabor: WarrantyDurationLabor; WarrantyDurationParts: WarrantyDurationParts; WarrantyGuarantorLabor: WarrantyGuarantorLabor; WarrantyGuarantorParts: WarrantyGuarantorParts; ExpectedLife: ExpectedLife; ReplacementCost: ReplacementCost; AssetAccountingType: FIXED; ModelLabel: ModelLabel

# IfcDoor: 1730 x 2134mm, M_Double-Flush:1730 x 2134mm:1730 x 2134mm:367888
In: First Floor
Type - OperationType: DOUBLE_DOOR_SINGLE_SWING; ParameterTakesPrecedence: no; Sizeable: no
OverallHeight: 2.134 m; OverallWidth: 1.73 m
Pset_DoorCommon - Reference: M_Double-Flush:1730 x 2134mm; IsExternal: no; FireRating: Fire Rating
PSet_Revit_Constraints - Level: First Floor; Sill Height: 0 m
PSet_Revit_Other - Head Height: 2.134 m; InstallationDate: InstallationDate; SerialNumber: SerialNumber; WarrantyStartDate: WarrantyStartDate; BarCode: BarCode; AssetIdentifier: AssetIdentifier; TagNumber: 1C11
PSet_Revit_Identity Data - Mark: 1C11
PSet_Revit_Phasing - Phase Created: New Construction
PSet_Revit_Type_Dimensions - Thickness: 0.051 m; Height: 2.134 m; Trim Projection Ext: 0.025 m; Trim Projection Int: 0.025 m; Trim Width: 0.076 m; Width: 1.73 m
PSet_Revit_Type_Construction - Function: 0; Wall Closure: 0; Construction Type: Construction Type
PSet_Revit_Type_Materials and Finishes - Door Material: Door - Panel; Frame Material: Door - Frame
PSet_Revit_Type_Identity Data - Manufacturer: Manufacturer; Type Mark: 40; Fire Rating: Fire Rating; OmniClass Number: 23.30.10.00; OmniClass Title: Doors
PSet_Revit_Type_Other - AccessibilityPerformance: AccessibilityPerformance; CodePerformance: CodePerformance; IsFireExit: IsFireExit; GlazingAreaFraction: GlazingAreaFraction; OperationType: OperationType; Area: Area; Color: Color; Constituents: Constituents; Features: Features; Finish: Finish; Grade: Grade; Material: Material; ModelReference: ModelReference; NominalHeight: NominalHeight; NominalLength: NominalLength; NominalWidth: NominalWidth; ProductionYear: ProductionYear; Reference: Reference; Shape: Shape; Size: Size; SustainabilityPerformance: SustainabilityPerformance; WarrantyDescription: WarrantyDescription; WarrantyDurationLabor: WarrantyDurationLabor; WarrantyDurationParts: WarrantyDurationParts; WarrantyGuarantorLabor: WarrantyGuarantorLabor; WarrantyGuarantorParts: WarrantyGuarantorParts; ExpectedLife: ExpectedLife; ReplacementCost: ReplacementCost; AssetAccountingType: FIXED; ModelLabel: ModelLabel

# IfcDoor: 1830 x 2134mm, M_Double-Flush:1830 x 2134mm:1830 x 2134mm:250360
In: Second Floor
Type - OperationType: DOUBLE_DOOR_SINGLE_SWING; ParameterTakesPrecedence: no; Sizeable: no
OverallHeight: 2.134 m; OverallWidth: 1.83 m
Pset_DoorCommon - Reference: M_Double-Flush:1830 x 2134mm; IsExternal: no; FireRating: Fire Rating
PSet_Revit_Constraints - Level: Second Floor; Sill Height: 0 m
PSet_Revit_Other - Head Height: 2.134 m; InstallationDate: InstallationDate; SerialNumber: SerialNumber; WarrantyStartDate: WarrantyStartDate; BarCode: BarCode; AssetIdentifier: AssetIdentifier; TagNumber: 2D05
PSet_Revit_Identity Data - Mark: 2D05
PSet_Revit_Phasing - Phase Created: New Construction
PSet_Revit_Type_Dimensions - Thickness: 0.051 m; Height: 2.134 m; Trim Projection Ext: 0.025 m; Trim Projection Int: 0.025 m; Trim Width: 0.076 m; Width: 1.83 m
PSet_Revit_Type_Construction - Function: 0; Wall Closure: 0; Construction Type: Construction Type
PSet_Revit_Type_Materials and Finishes - Door Material: Door - Panel; Frame Material: Door - Frame
PSet_Revit_Type_Identity Data - Manufacturer: Manufacturer; Type Mark: 42; Fire Rating: Fire Rating; OmniClass Number: 23.30.10.00; OmniClass Title: Doors
PSet_Revit_Type_Other - AccessibilityPerformance: AccessibilityPerformance; CodePerformance: CodePerformance; IsFireExit: IsFireExit; GlazingAreaFraction: GlazingAreaFraction; OperationType: OperationType; Area: Area; Color: Color; Constituents: Constituents; Features: Features; Finish: Finish; Grade: Grade; Material: Material; ModelReference: ModelReference; NominalHeight: NominalHeight; NominalLength: NominalLength; NominalWidth: NominalWidth; ProductionYear: ProductionYear; Reference: Reference; Shape: Shape; Size: Size; SustainabilityPerformance: SustainabilityPerformance; WarrantyDescription: WarrantyDescription; WarrantyDurationLabor: WarrantyDurationLabor; WarrantyDurationParts: WarrantyDurationParts; WarrantyGuarantorLabor: WarrantyGuarantorLabor; WarrantyGuarantorParts: WarrantyGuarantorParts; ExpectedLife: ExpectedLife; ReplacementCost: ReplacementCost; AssetAccountingType: FIXED; ModelLabel: ModelLabel

# IfcDoor: 1830 x 2134mm Exterior (4)
Type - OperationType: DOUBLE_DOOR_SINGLE_SWING; ParameterTakesPrecedence: no; Sizeable: no
OverallHeight: 2.134 m; OverallWidth: 1.83 m
Pset_DoorCommon - Reference: M_Double-Flush:1830 x 2134mm Exterior; IsExternal: yes; FireRating: Fire Rating
PSet_Revit_Constraints - Sill Height: 0 m
PSet_Revit_Other - Head Height: 2.134 m; InstallationDate: InstallationDate; SerialNumber: SerialNumber; WarrantyStartDate: WarrantyStartDate; BarCode: BarCode; AssetIdentifier: AssetIdentifier
PSet_Revit_Phasing - Phase Created: New Construction
PSet_Revit_Type_Dimensions - Thickness: 0.051 m; Height: 2.134 m; Trim Projection Ext: 0.025 m; Trim Projection Int: 0.025 m; Trim Width: 0.076 m; Width: 1.83 m
PSet_Revit_Type_Construction - Function: 1; Wall Closure: 0; Construction Type: Construction Type
PSet_Revit_Type_Materials and Finishes - Door Material: Door - Panel; Frame Material: Door - Frame
PSet_Revit_Type_Identity Data - Manufacturer: Manufacturer; Type Mark: 58; Fire Rating: Fire Rating; OmniClass Number: 23.30.10.00; OmniClass Title: Doors
PSet_Revit_Type_Other - AccessibilityPerformance: AccessibilityPerformance; CodePerformance: CodePerformance; IsFireExit: IsFireExit; GlazingAreaFraction: GlazingAreaFraction; OperationType: OperationType; Area: Area; Color: Color; Constituents: Constituents; Features: Features; Finish: Finish; Grade: Grade; Material: Material; ModelReference: ModelReference; NominalHeight: NominalHeight; NominalLength: NominalLength; NominalWidth: NominalWidth; ProductionYear: ProductionYear; Reference: Reference; Shape: Shape; Size: Size; SustainabilityPerformance: SustainabilityPerformance; WarrantyDescription: WarrantyDescription; WarrantyDurationLabor: WarrantyDurationLabor; WarrantyDurationParts: WarrantyDurationParts; WarrantyGuarantorLabor: WarrantyGuarantorLabor; WarrantyGuarantorParts: WarrantyGuarantorParts; ExpectedLife: ExpectedLife; ReplacementCost: ReplacementCost; AssetAccountingType: FIXED; ModelLabel: ModelLabel
Name (M_Double-Flush:1830 x 2134mm Exterior:1830 x 2134mm Exterior:...) | In | Level | TagNumber = Mark
252102 | First Floor | First Floor | 1E15A
252224 | First Floor | First Floor | 1E15
252860 | First Floor | First Floor | 1E24
411107 | Second Floor | Second Floor | 2D05A

# IfcDoor: M_Curtain Wall Dbl Chain Link (4)
Type - ParameterTakesPrecedence: no; Sizeable: no
OverallHeight: 1.96386 m; OverallWidth: 2.702 m
Pset_DoorCommon - Reference: M_Curtain Wall Dbl Chain Link:M_Curtain Wall Dbl Chain Link; IsExternal: yes; FireRating: Fire Rating
PSet_Revit_Other - InstallationDate: InstallationDate; SerialNumber: SerialNumber; WarrantyStartDate: WarrantyStartDate; BarCode: BarCode; AssetIdentifier: AssetIdentifier
PSet_Revit_Phasing - Phase Created: New Construction
PSet_Revit_Dimensions - Width: 2.702 m; Height: 1.962 m
PSet_Revit_Type_Dimensions - Pipe Radius: 0.019 m
PSet_Revit_Type_Materials and Finishes - Glazing Material: Metal - Chain Link; Frame Material: Metal - Aluminum
PSet_Revit_Type_Construction - Function: 1; Construction Type: Construction Type
PSet_Revit_Type_Identity Data - Manufacturer: Manufacturer; Type Mark: 35; Fire Rating: Fire Rating; OmniClass Number: 23.30.10.00; OmniClass Title: Doors
PSet_Revit_Type_Other - AccessibilityPerformance: AccessibilityPerformance; CodePerformance: CodePerformance; IsFireExit: IsFireExit; GlazingAreaFraction: GlazingAreaFraction; OperationType: OperationType; Area: Area; Color: Color; Constituents: Constituents; Features: Features; Finish: Finish; Grade: Grade; Material: Material; ModelReference: ModelReference; NominalHeight: NominalHeight; NominalLength: NominalLength; NominalWidth: NominalWidth; ProductionYear: ProductionYear; Reference: Reference; Shape: Shape; Size: Size; SustainabilityPerformance: SustainabilityPerformance; WarrantyDescription: WarrantyDescription; WarrantyDurationLabor: WarrantyDurationLabor; WarrantyDurationParts: WarrantyDurationParts; WarrantyGuarantorLabor: WarrantyGuarantorLabor; WarrantyGuarantorParts: WarrantyGuarantorParts; ExpectedLife: ExpectedLife; ReplacementCost: ReplacementCost; AssetAccountingType: FIXED; ModelLabel: ModelLabel
Name (M_Curtain Wall Dbl Chain Link:M_Curtain Wall Dbl Chain Link:M_Curtain Wall Dbl Chain Link:...) | In | Mark = TagNumber
346969 | First Floor | 1F01a
346973 | First Floor | 1F01b
346969 | TOF Footing | 1F01a
346973 | TOF Footing | 1F01b

# IfcDoor: M_Curtain Wall Dbl Glass (2)
In: First Floor
Type - OperationType: DOUBLE_DOOR_SINGLE_SWING; ParameterTakesPrecedence: no; Sizeable: no
OverallHeight: 2.32686 m; OverallWidth: 1.8 m
Pset_DoorCommon - Reference: M_Curtain Wall Dbl Glass:M_Curtain Wall Dbl Glass; IsExternal: yes; FireRating: Fire Rating
PSet_Revit_Identity Data - Mark: 1CA1
PSet_Revit_Other - InstallationDate: InstallationDate; SerialNumber: SerialNumber; WarrantyStartDate: WarrantyStartDate; BarCode: BarCode; AssetIdentifier: AssetIdentifier; TagNumber: 1CA1
PSet_Revit_Phasing - Phase Created: New Construction
PSet_Revit_Dimensions - Width: 1.8 m; Height: 2.325 m
PSet_Revit_Type_Dimensions - Offset: 0.05 m
PSet_Revit_Type_Materials and Finishes - Glazing Material: Glass
PSet_Revit_Type_Construction - Function: 1; Construction Type: Construction Type
PSet_Revit_Type_Identity Data - Manufacturer: Manufacturer; Type Mark: 36; Fire Rating: Fire Rating; OmniClass Number: 23.30.10.00; OmniClass Title: Doors
PSet_Revit_Type_Other - AccessibilityPerformance: AccessibilityPerformance; CodePerformance: CodePerformance; IsFireExit: IsFireExit; GlazingAreaFraction: GlazingAreaFraction; OperationType: OperationType; Area: Area; Color: Color; Constituents: Constituents; Features: Features; Finish: Finish; Grade: Grade; Material: Material; ModelReference: ModelReference; NominalHeight: NominalHeight; NominalLength: NominalLength; NominalWidth: NominalWidth; ProductionYear: ProductionYear; Reference: Reference; Shape: Shape; Size: Size; SustainabilityPerformance: SustainabilityPerformance; WarrantyDescription: WarrantyDescription; WarrantyDurationLabor: WarrantyDurationLabor; WarrantyDurationParts: WarrantyDurationParts; WarrantyGuarantorLabor: WarrantyGuarantorLabor; WarrantyGuarantorParts: WarrantyGuarantorParts; ExpectedLife: ExpectedLife; ReplacementCost: ReplacementCost; AssetAccountingType: FIXED; ModelLabel: ModelLabel

# IfcDoor: M_Curtain Wall Sgl Glass (2)
In: First Floor
Type - OperationType: SINGLE_SWING_LEFT; ParameterTakesPrecedence: no; Sizeable: no
OverallHeight: 2.325 m; OverallWidth: 0.901001 m
Pset_DoorCommon - Reference: M_Curtain Wall Sgl Glass:M_Curtain Wall Sgl Glass; IsExternal: no; FireRating: Fire Rating
PSet_Revit_Identity Data - Mark: 1DC5a
PSet_Revit_Other - InstallationDate: InstallationDate; SerialNumber: SerialNumber; WarrantyStartDate: WarrantyStartDate; BarCode: BarCode; AssetIdentifier: AssetIdentifier; TagNumber: 1DC5a
PSet_Revit_Phasing - Phase Created: New Construction
PSet_Revit_Dimensions - Width: 0.901001 m; Height: 2.325 m
PSet_Revit_Type_Dimensions - Offset: 0.051 m
PSet_Revit_Type_Materials and Finishes - Glazing Material: Glass
PSet_Revit_Type_Construction - Function: 0; Construction Type: Construction Type
PSet_Revit_Type_Identity Data - Manufacturer: Manufacturer; Type Mark: 37; Fire Rating: Fire Rating; OmniClass Number: 23.30.10.00; OmniClass Title: Doors
PSet_Revit_Type_Other - AccessibilityPerformance: AccessibilityPerformance; CodePerformance: CodePerformance; IsFireExit: IsFireExit; GlazingAreaFraction: GlazingAreaFraction; OperationType: OperationType; Area: Area; Color: Color; Constituents: Constituents; Features: Features; Finish: Finish; Grade: Grade; Material: Material; ModelReference: ModelReference; NominalHeight: NominalHeight; NominalLength: NominalLength; NominalWidth: NominalWidth; ProductionYear: ProductionYear; Reference: Reference; Shape: Shape; Size: Size; SustainabilityPerformance: SustainabilityPerformance; WarrantyDescription: WarrantyDescription; WarrantyDurationLabor: WarrantyDurationLabor; WarrantyDurationParts: WarrantyDurationParts; WarrantyGuarantorLabor: WarrantyGuarantorLabor; WarrantyGuarantorParts: WarrantyGuarantorParts; ExpectedLife: ExpectedLife; ReplacementCost: ReplacementCost; AssetAccountingType: FIXED; ModelLabel: ModelLabel

# IfcDoor: M_Curtain Wall Sgl Glass (2)
In: First Floor
Type - OperationType: SINGLE_SWING_RIGHT; ParameterTakesPrecedence: no; Sizeable: no
OverallHeight: 2.325 m; OverallWidth: 0.899549 m
Pset_DoorCommon - Reference: M_Curtain Wall Sgl Glass:M_Curtain Wall Sgl Glass; IsExternal: no; FireRating: Fire Rating
PSet_Revit_Identity Data - Mark: 1DC5b
PSet_Revit_Other - InstallationDate: InstallationDate; SerialNumber: SerialNumber; WarrantyStartDate: WarrantyStartDate; BarCode: BarCode; AssetIdentifier: AssetIdentifier; TagNumber: 1DC5b
PSet_Revit_Phasing - Phase Created: New Construction
PSet_Revit_Dimensions - Width: 0.899549 m; Height: 2.325 m
PSet_Revit_Type_Dimensions - Offset: 0.051 m
PSet_Revit_Type_Materials and Finishes - Glazing Material: Glass
PSet_Revit_Type_Construction - Function: 0; Construction Type: Construction Type
PSet_Revit_Type_Identity Data - Manufacturer: Manufacturer; Type Mark: 37; Fire Rating: Fire Rating; OmniClass Number: 23.30.10.00; OmniClass Title: Doors
PSet_Revit_Type_Other - AccessibilityPerformance: AccessibilityPerformance; CodePerformance: CodePerformance; IsFireExit: IsFireExit; GlazingAreaFraction: GlazingAreaFraction; OperationType: OperationType; Area: Area; Color: Color; Constituents: Constituents; Features: Features; Finish: Finish; Grade: Grade; Material: Material; ModelReference: ModelReference; NominalHeight: NominalHeight; NominalLength: NominalLength; NominalWidth: NominalWidth; ProductionYear: ProductionYear; Reference: Reference; Shape: Shape; Size: Size; SustainabilityPerformance: SustainabilityPerformance; WarrantyDescription: WarrantyDescription; WarrantyDurationLabor: WarrantyDurationLabor; WarrantyDurationParts: WarrantyDurationParts; WarrantyGuarantorLabor: WarrantyGuarantorLabor; WarrantyGuarantorParts: WarrantyGuarantorParts; ExpectedLife: ExpectedLife; ReplacementCost: ReplacementCost; AssetAccountingType: FIXED; ModelLabel: ModelLabel

# IfcFlowTerminal: 17" Depth x 18 1/2" Width (3)
Type - ElementType: 17" Depth x 18 1/2" Width
PSet_Revit_Constraints - Elevation: 0.915 m
PSet_Revit_Other - InstallationDate: InstallationDate; SerialNumber: SerialNumber; WarrantyStartDate: WarrantyStartDate; BarCode: BarCode; AssetIdentifier: AssetIdentifier; TagNumber: TagNumber
PSet_Revit_Phasing - Phase Created: New Construction
PSet_Revit_Type_Dimensions - Width: 0.569913 m; Radius Seat: 0.01905 m; Radius Frame: 0.0166687 m; Height: 0.193675 m; Elevation: 0.955675 m; Diameter: 0.0333375 m; Depth: 0.430212 m
PSet_Revit_Type_Materials and Finishes - Special Color: no; White: yes; Triton Color Palette: www.inprocorp.com/Products/Files.aspx?FileId=3054; Ivory: no; Finish: PVC-InPro-White
PSet_Revit_Type_Identity Data - URL: www.inprocorp.com; Type Comments: 18 1/2 in.; Series: Folding Seat; Revit Family Created by: CADdetails, LTD.; Revisions Date: 07/14/2010; OmniClass Title: Shower/Bath Seats; OmniClass Number: 23.45.05.14.11.17; Model: DSGBFSTADA-WHT; MasterFormat Title: Bath Accessories; MasterFormat Number: 10 28 16; Manufacturer: InPro Corporation; Description: Folding Seat White 17in.; Assembly Code: E1020810; Architectural Design Manual: www.inprocorp.com/Products/Details.aspx?ProductId=460#info; Assembly Description: Medical Furniture & Equipment
PSet_Revit_Type_Green Building Properties - LEED: www.inprocorp.com/Products/Files.aspx?FileId=8357
PSet_Revit_Type_Other - AccessibilityPerformance: AccessibilityPerformance; CodePerformance: CodePerformance; Color: Color; Constituents: Constituents; Features: Features; Finish: Finish; Grade: Grade; Material: Material; ModelReference: ModelReference; NominalHeight: NominalHeight; NominalLength: NominalLength; NominalWidth: NominalWidth; ProductionYear: ProductionYear; Reference: Reference; Shape: Shape; Size: Size; SustainabilityPerformance: SustainabilityPerformance; WarrantyDescription: WarrantyDescription; WarrantyDurationLabor: WarrantyDurationLabor; WarrantyDurationParts: WarrantyDurationParts; WarrantyGuarantorLabor: WarrantyGuarantorLabor; WarrantyGuarantorParts: WarrantyGuarantorParts; ExpectedLife: ExpectedLife; ReplacementCost: ReplacementCost; AssetAccountingType: AssetAccountingType; ModelLabel: ModelLabel
Name (M_ADA shower Seat:17" Depth x 18 1/2" Width:17" Depth x 18 1/2" Width:...) | In | Level | Mark
443560 | 2C07 | Second Floor | 77
443641 | 2C08 | Second Floor | 78
443686 | 1D18 | First Floor | 79

# IfcFlowTerminal: 2000 lbs, M_Elevator-Hydraulic:2000 lbs:2000 lbs:306114
In: E1
Type - ElementType: 2000 lbs
PSet_Revit_Other - Height: 8.23 m; InstallationDate: InstallationDate; SerialNumber: SerialNumber; WarrantyStartDate: WarrantyStartDate; BarCode: BarCode; AssetIdentifier: AssetIdentifier; TagNumber: TagNumber
PSet_Revit_Constraints - Level: First Floor; Host: Level : First Floor; Offset: 0 m; Moves With Nearby Elements: no
PSet_Revit_Identity Data - Mark: 2
PSet_Revit_Phasing - Phase Created: New Construction
PSet_Revit_Type_Other - Cab Location: 3.6576 m; Width: 2.2352 m; Pit Depth: 1.2192 m; Door Opening: 0.9144 m; Depth: 1.7526 m; Cab Width: 1.8288 m; Cab Height: 2.286 m; Cab Depth: 1.524 m; AccessibilityPerformance: AccessibilityPerformance; CodePerformance: CodePerformance; Color: Color; Constituents: Constituents; Features: Features; Finish: Finish; Grade: Grade; Material: Material; ModelReference: ModelReference; NominalHeight: NominalHeight; NominalLength: NominalLength; NominalWidth: NominalWidth; ProductionYear: ProductionYear; Reference: Reference; Shape: Shape; Size: Size; SustainabilityPerformance: SustainabilityPerformance; WarrantyDescription: WarrantyDescription; WarrantyDurationLabor: WarrantyDurationLabor; WarrantyDurationParts: WarrantyDurationParts; WarrantyGuarantorLabor: WarrantyGuarantorLabor; WarrantyGuarantorParts: WarrantyGuarantorParts; ExpectedLife: ExpectedLife; ReplacementCost: ReplacementCost; AssetAccountingType: FIXED; ModelLabel: ModelLabel
PSet_Revit_Type_Identity Data - Manufacturer: Manufacturer; OmniClass Number: 23.50.05.11; OmniClass Title: Elevators

# IfcFlowTerminal: 305 x 215 x 813mm (10)
Type - ElementType: 305 x 215 x 813mm
PSet_Revit_Constraints - Elevation: 0.915 m
PSet_Revit_Other - InstallationDate: InstallationDate; SerialNumber: SerialNumber; WarrantyStartDate: WarrantyStartDate; BarCode: BarCode; AssetIdentifier: AssetIdentifier; TagNumber: TagNumber
PSet_Revit_Phasing - Phase Created: New Construction
PSet_Revit_Type_Materials and Finishes - Cabinet Material: Metal - Paint Finish - Indian Red, Matte; Glass Pane Material: Glass
PSet_Revit_Type_Dimensions - Depth: 0.215 m; Height: 0.813 m; Mounting Height: 0.915 m; Width: 0.305 m
PSet_Revit_Type_Identity Data - Manufacturer: Manufacturer; OmniClass Number: 23.65.70.17.11; OmniClass Title: Fire Fighting Terminal Components
PSet_Revit_Type_Other - AccessibilityPerformance: AccessibilityPerformance; CodePerformance: CodePerformance; Color: Color; Constituents: Constituents; Features: Features; Finish: Finish; Grade: Grade; Material: Material; ModelReference: ModelReference; NominalHeight: NominalHeight; NominalLength: NominalLength; NominalWidth: NominalWidth; ProductionYear: ProductionYear; Reference: Reference; Shape: Shape; Size: Size; SustainabilityPerformance: SustainabilityPerformance; WarrantyDescription: WarrantyDescription; WarrantyDurationLabor: WarrantyDurationLabor; WarrantyDurationParts: WarrantyDurationParts; WarrantyGuarantorLabor: WarrantyGuarantorLabor; WarrantyGuarantorParts: WarrantyGuarantorParts; ExpectedLife: ExpectedLife; ReplacementCost: ReplacementCost; AssetAccountingType: FIXED; ModelLabel: ModelLabel
Name (M_Fire Extinguisher Cabinet:305 x 215 x 813mm:305 x 215 x 813mm:...) | In | Level | Mark
350693 | 1BC2 | First Floor | 1
350968 | 1AC1 | First Floor | 2
351171 | 1AC3 | First Floor | 3
351256 | 1AC5 | First Floor | 5
351533 | 1B04 | First Floor | 6
363794 | 1AC4 | First Floor | 7
387916 | 2DC1 | Second Floor | 8
390697 | 2D05 | Second Floor | 9
425968 | 2D18 | Second Floor | 10
427576 | 1CC1 | First Floor | 11

# IfcFlowTerminal: 8370-001300 (22)
Type - ElementType: 8370-001300
PSet_Revit_Other - InstallationDate: InstallationDate; SerialNumber: SerialNumber; WarrantyStartDate: WarrantyStartDate; BarCode: BarCode; AssetIdentifier: AssetIdentifier; TagNumber: TagNumber
PSet_Revit_Constraints - Elevation: 0.915 m
PSet_Revit_Phasing - Phase Created: New Construction
PSet_Revit_Type_Identity Data - Warranty Information: Complete unit, one (1) year; Version: 1.0; Technical Data: http://www.bradleycorp.com/products/techdata/8825.pdf; URL: www.bradleycorp.com; Type Comments: All grab bar configurations are specified using centerline to centerline dimensions.; OmniClass Number: 0; Model: 8370-001300; Material Note: FLANGES - 11 GA., TUBING - 18 GA.; Manufacturer: Bradley Corporation; Industry Standards: ANSI Standard A117.1, ADA, ABA, ADAAG, UFAS; Description: Grab Bars; Copyright: This Model Data is Property of Bradley Corporation; Assembly Code: C1030200; ADA Compliant: Yes; Assembly Description: Bath & Toilet Accessories; OmniClass Title: Bath Grab Bars
PSet_Revit_Type_Green Building Properties - Percentage of Recycled Content: 51.61; Complies to NAFTA: Yes; Complies To Buy American Act: Yes
PSet_Revit_Type_Dimensions - Overall Length: 0.841375 m; Length: 0.762 m; Diameter: 0.03175 m
PSet_Revit_Type_Materials and Finishes - Material and Finish: Bradley Corp Stainless Steel - Satin
PSet_Revit_Type_Constraints - Instructions: This is a face mounted fixture.; Default Elevation: 0.8382 m
PSet_Revit_Type_Other - AccessibilityPerformance: AccessibilityPerformance; CodePerformance: CodePerformance; Color: Color; Constituents: Constituents; Features: Features; Finish: Finish; Grade: Grade; Material: Material; ModelReference: ModelReference; NominalHeight: NominalHeight; NominalLength: NominalLength; NominalWidth: NominalWidth; ProductionYear: ProductionYear; Reference: Reference; Shape: Shape; Size: Size; SustainabilityPerformance: SustainabilityPerformance; WarrantyDescription: WarrantyDescription; WarrantyDurationLabor: WarrantyDurationLabor; WarrantyDurationParts: WarrantyDurationParts; WarrantyGuarantorLabor: WarrantyGuarantorLabor; WarrantyGuarantorParts: WarrantyGuarantorParts; ExpectedLife: ExpectedLife; ReplacementCost: ReplacementCost; AssetAccountingType: AssetAccountingType; ModelLabel: ModelLabel
Name (M_Grab Bars:8370-001300:8370-001300:...) | In | Schedule Level | Host | Mark
430296 | 1A09 | First Floor | Basic Wall : Interior - Furring (152 mm Stud) | 13
430358 | 1A12 | First Floor | Basic Wall : Interior - Furring (152 mm Stud) | 15
430429 | 1A13 | First Floor | Basic Wall : Interior - Furring (152 mm Stud) | 17
430518 | 1D04 | First Floor | Basic Wall : Interior - Plumbing (152mm Stud) | 18
430800 | 1D18 | First Floor | Basic Wall : Interior - Furring (152 mm Stud) | 22
430827 | 1D14 | First Floor | Basic Wall : Interior - Furring (152 mm Stud) | 23
431006 | 1C12 | First Floor | Basic Wall : Interior - Furring (152 mm Stud) | 24
431863 | 1D26 | First Floor | Basic Wall : Interior - Plumbing (152mm Stud) | 27
431907 | 1E12 | First Floor | Basic Wall : Interior - Furring (152 mm Stud) | 28
432784 | 1E10 | First Floor | Basic Wall : Interior - Furring (152 mm Stud) | 32
432803 | 1E09 | First Floor | Basic Wall : Interior - Furring (152 mm Stud) | 33
432918 | 1B11 | First Floor | Basic Wall : Interior - Furring (152 mm Stud) | 34
432957 | 1B05 | First Floor | Basic Wall : Interior - Furring (152 mm Stud) | 35
433165 | 1B02 | First Floor | Basic Wall : Interior - Plumbing (152mm Stud) | 36
433925 | 2B22 | Second Floor | Basic Wall : Interior - Furring (152 mm Stud) | 41
433960 | 2B5 | Second Floor | Basic Wall : Interior - Furring (152 mm Stud) | 42
434154 | 2B6 | Second Floor | Basic Wall : Interior - Furring (152 mm Stud) | 43
434939 | 2D13 | Second Floor | Basic Wall : Interior - Furring (152 mm Stud) | 47
434977 | 2C08 | Second Floor | Basic Wall : Interior - Plumbing (152mm Stud) | 48
435555 | 2C07 | Second Floor | Basic Wall : Interior - Plumbing (152mm Stud) | 49
436616 | 2C24 | Second Floor | Basic Wall : Interior - Plumbing (152mm Stud) | 54
436634 | 2C23 | Second Floor | Basic Wall : Interior - Plumbing (152mm Stud) | 55

# IfcFlowTerminal: 8370-001420 (22)
Type - ElementType: 8370-001420
PSet_Revit_Other - InstallationDate: InstallationDate; SerialNumber: SerialNumber; WarrantyStartDate: WarrantyStartDate; BarCode: BarCode; AssetIdentifier: AssetIdentifier; TagNumber: TagNumber
PSet_Revit_Constraints - Elevation: 0.915 m
PSet_Revit_Phasing - Phase Created: New Construction
PSet_Revit_Type_Identity Data - Warranty Information: Complete unit, one (1) year; Version: 1.0; Technical Data: http://www.bradleycorp.com/products/techdata/8825.pdf; URL: www.bradleycorp.com; Type Comments: All grab bar configurations are specified using centerline to centerline dimensions.; OmniClass Number: 0; Model: 8370-001420; Material Note: FLANGES - 11 GA., TUBING - 18 GA.; Manufacturer: Bradley Corporation; Industry Standards: ANSI Standard A117.1, ADA, ABA, ADAAG, UFAS; Description: Grab Bars; Copyright: This Model Data is Property of Bradley Corporation; Assembly Code: C1030200; ADA Compliant: Yes; Assembly Description: Bath & Toilet Accessories; OmniClass Title: Bath Grab Bars
PSet_Revit_Type_Green Building Properties - Percentage of Recycled Content: 54.99; Complies to NAFTA: Yes; Complies To Buy American Act: Yes
PSet_Revit_Type_Dimensions - Overall Length: 1.14617 m; Length: 1.0668 m; Diameter: 0.03175 m
PSet_Revit_Type_Materials and Finishes - Material and Finish: Bradley Corp Stainless Steel - Satin
PSet_Revit_Type_Constraints - Instructions: This is a face mounted fixture.; Default Elevation: 0.8382 m
PSet_Revit_Type_Other - AccessibilityPerformance: AccessibilityPerformance; CodePerformance: CodePerformance; Color: Color; Constituents: Constituents; Features: Features; Finish: Finish; Grade: Grade; Material: Material; ModelReference: ModelReference; NominalHeight: NominalHeight; NominalLength: NominalLength; NominalWidth: NominalHeight; ProductionYear: ProductionYear; Reference: Reference; Shape: Shape; Size: Size; SustainabilityPerformance: SustainabilityPerformance; WarrantyDescription: WarrantyDescription; WarrantyDurationLabor: WarrantyDurationLabor; WarrantyDurationParts: WarrantyDurationParts; WarrantyGuarantorLabor: WarrantyGuarantorLabor; WarrantyGuarantorParts: WarrantyGuarantorParts; ExpectedLife: ExpectedLife; ReplacementCost: ReplacementCost; AssetAccountingType: AssetAccountingType; ModelLabel: ModelLabel
Name (M_Grab Bars:8370-001420:8370-001420:...) | In | Schedule Level | Host | Mark
430186 | 1A09 | First Floor | Basic Wall : Interior - Toilet Partition (25mm) | 12
430356 | 1A12 | First Floor | Basic Wall : Interior - Toilet Partition (25mm) | 14
430428 | 1A13 | First Floor | Basic Wall : Interior - Partition (92mm Stud) | 16
430573 | 1D04 | First Floor | Basic Wall : Interior - Furring (38 mm Stud) | 19
430606 | 1D18 | First Floor | Basic Wall : Interior - Partition (92mm Stud) | 20
430635 | 1D14 | First Floor | Basic Wall : Interior - Partition (92mm Stud) | 21
431453 | 1C12 | First Floor | Basic Wall : Interior - Partition (92mm Stud) | 25
431750 | 1D26 | First Floor | Basic Wall : Interior - Partition (92mm Stud) | 26
432204 | 1E12 | First Floor | Basic Wall : Interior - Partition (92mm Stud) | 29
432255 | 1E10 | First Floor | Basic Wall : Interior - Partition (92mm Stud) | 30
432601 | 1E09 | First Floor | Basic Wall : Interior - Partition (92mm Stud) | 31
433384 | 1B02 | First Floor | Basic Wall : Interior - Partition (92mm Stud) | 37
433434 | 1B05 | First Floor | Basic Wall : Interior - Partition (92mm Stud) | 38
433622 | 1B11 | First Floor | Basic Wall : Interior - Partition (92mm Stud) | 39
433844 | 2B22 | Second Floor | Basic Wall : Exterior - Insul Panel on Mtl. Stud | 40
434363 | 2B6 | Second Floor | Basic Wall : Interior - Partition (92mm Stud) | 44
434392 | 2B5 | Second Floor | Basic Wall : Interior - Partition (92mm Stud) | 45
434582 | 2D13 | Second Floor | Basic Wall : Interior - Partition (92mm Stud) | 46
435755 | 2C08 | Second Floor | Basic Wall : Interior - Partition (92mm Stud) | 50
435792 | 2C07 | Second Floor | Basic Wall : Interior - Partition (92mm Stud) | 51
435940 | 2C23 | Second Floor | Basic Wall : Interior - Partition (92mm Stud) | 52
436370 | 2C24 | Second Floor | Basic Wall : Interior - Partition (92mm Stud) | 53

# IfcFlowTerminal: Mirror 600mm x 900mm (22)
Type - ElementType: Mirror 600mm x 900mm
PSet_Revit_Other - InstallationDate: InstallationDate; SerialNumber: SerialNumber; WarrantyStartDate: WarrantyStartDate; BarCode: BarCode; AssetIdentifier: AssetIdentifier; TagNumber: TagNumber
PSet_Revit_Phasing - Phase Created: New Construction
PSet_Revit_Type_Identity Data - Assembly Code: C1030200; Manufacturer: Manufacturer; Assembly Description: Bath & Toilet Accessories; OmniClass Number: 23.40.20.21; OmniClass Title: Toilet and Bath Specialties
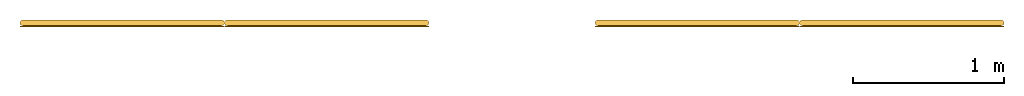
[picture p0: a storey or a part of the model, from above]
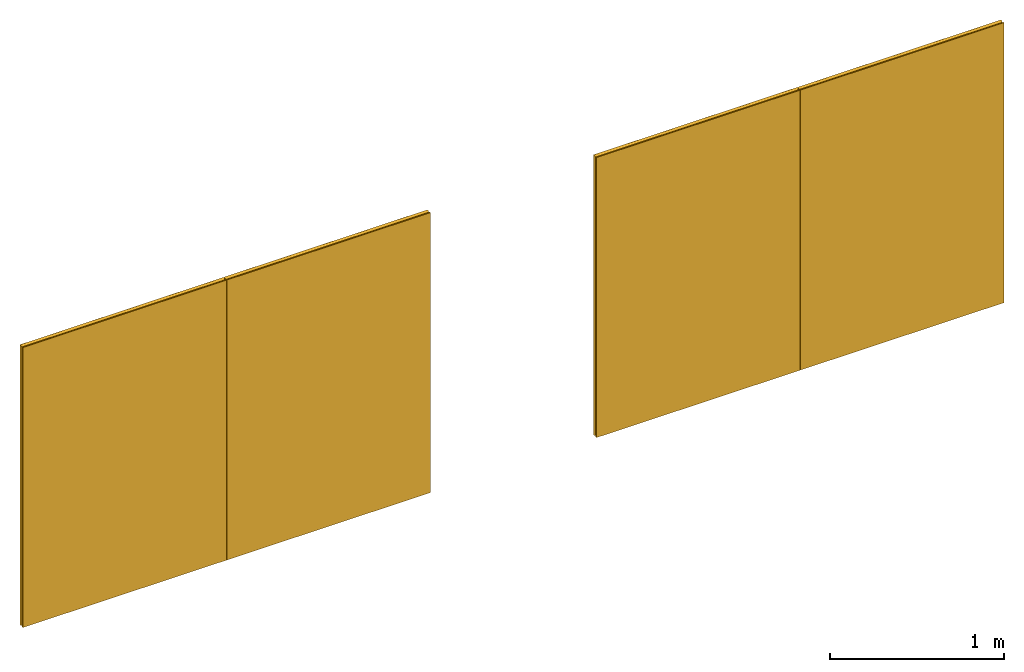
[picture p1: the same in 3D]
Properties of the parts of a building model (IFC2X3), part 4 of 11

# IfcFlowTerminal: Mirror 600mm x 900mm (22)
PSet_Revit_Type_Other - Height: 0.9 m; Mounting Height: 1 m; Width: 0.6 m; AccessibilityPerformance: AccessibilityPerformance; CodePerformance: CodePerformance; Color: Color; Constituents: Constituents; Features: Features; Finish: Finish; Grade: Grade; Material: Material; ModelReference: ModelReference; NominalHeight: NominalHeight; NominalLength: NominalLength; NominalWidth: NominalWidth; ProductionYear: ProductionYear; Reference: Reference; Shape: Shape; Size: Size; SustainabilityPerformance: SustainabilityPerformance; WarrantyDescription: WarrantyDescription; WarrantyDurationLabor: WarrantyDurationLabor; WarrantyDurationParts: WarrantyDurationParts; WarrantyGuarantorLabor: WarrantyGuarantorLabor; WarrantyGuarantorParts: WarrantyGuarantorParts; ExpectedLife: ExpectedLife; ReplacementCost: ReplacementCost; AssetAccountingType: FIXED; ModelLabel: ModelLabel
Name (M_Mirror:Mirror 600mm x 900mm:Mirror 600mm x 900mm:...) | In | Level | Elevation (m) | Mark
437797 | 1C12 | First Floor | 0.915 | 56
437958 | 1D18 | First Floor | 0.915 | 57
437997 | 1D14 | First Floor | 0.915 | 58
438063 | 1D04 | First Floor | 0.915 | 59
438167 | 1A09 | First Floor | 0.915 | 60
438390 | 1A12 | First Floor | 0.915 | 61
438525 | 1A13 | First Floor | 0.915 | 62
438592 | 1B02 | First Floor | 0.915 | 63
438697 | 1B05 | First Floor | 0.915 | 64
438749 | 1B11 | First Floor | 0.915 | 65
438815 | 1E09 | First Floor | 0.915 | 66
438982 | 1E10 | First Floor | 0.915 | 67
439008 | 1E12 | First Floor | 0.915 | 68
439132 | 2C24 | Second Floor | 0.915 | 69
439425 | 2C23 | Second Floor | 0.915 | 70
439477 | 2C08 | Second Floor | 0.915 | 71
439593 | 2C07 | Second Floor | 0.915 | 72
440023 | 2D13 | Second Floor | 0.915 | 73
440147 | 2B22 | Second Floor | 0.915 | 74
440201 | 2B6 | Second Floor | 0.915 | 75
440307 | 2B5 | Second Floor | 0.915 | 76
449908 | 1D26 | First Floor | 1 | 94

# IfcFlowTerminal: Semi-Recessed (22)
Type - ElementType: Semi-Recessed
PSet_Revit_Other - InstallationDate: InstallationDate; SerialNumber: SerialNumber; WarrantyStartDate: WarrantyStartDate; BarCode: BarCode; AssetIdentifier: AssetIdentifier; TagNumber: TagNumber
PSet_Revit_Phasing - Phase Created: New Construction
PSet_Revit_Type_Dimensions - Width: 0.3302 m; Void Width: 0.29845 m; Void Height: 1.36207 m; Void Depth: 0.0889 m; Height: 1.397 m; Depth of which projects: 0.0635 m; Depth: 0.1524 m
PSet_Revit_Type_Identity Data - Manufacturer: Manufacturer; OmniClass Number: 23.40.20.21.17; OmniClass Title: Paper Towel Dispensers, Disposal Units
PSet_Revit_Type_Constraints - Default Elevation: 1.2192 m
PSet_Revit_Type_Other - AccessibilityPerformance: AccessibilityPerformance; CodePerformance: CodePerformance; Color: Color; Constituents: Constituents; Features: Features; Finish: Finish; Grade: Grade; Material: Material; ModelReference: ModelReference; NominalHeight: NominalHeight; NominalLength: NominalLength; NominalWidth: NominalWidth; ProductionYear: ProductionYear; Reference: Reference; Shape: Shape; Size: Size; SustainabilityPerformance: SustainabilityPerformance; WarrantyDescription: WarrantyDescription; WarrantyDurationLabor: WarrantyDurationLabor; WarrantyDurationParts: WarrantyDurationParts; WarrantyGuarantorLabor: WarrantyGuarantorLabor; WarrantyGuarantorParts: WarrantyGuarantorParts; ExpectedLife: ExpectedLife; ReplacementCost: ReplacementCost; AssetAccountingType: FIXED; ModelLabel: ModelLabel
Name (M_Towel Dispensers - receptical:Semi-Recessed:Semi-Recessed:...) | In | Schedule Level | Host | Elevation (m) | Mark
445047 | 1C12 | First Floor | Basic Wall : Interior - Partition (92mm Stud) | 0.915 | 80
446560 | 1D18 | First Floor | Basic Wall : Interior - Partition (92mm Stud) | 1.2192 | 81
446621 | 1D14 | First Floor | Basic Wall : Interior - Partition (92mm Stud) | 1.2192 | 82
446729 | 1D04 | First Floor | Basic Wall : Interior - Partition (92mm Stud) | 1.2192 | 83
447051 | 1A12 | First Floor | Basic Wall : Interior - Partition (92mm Stud) | 1.2192 | 84
447354 | 1A09 | First Floor | Basic Wall : Exterior - Insul Panel on Mtl. Stud | 1.2192 | 85
447624 | 1A13 | First Floor | Basic Wall : Interior - Partition (92mm Stud) | 1.2192 | 86
448412 | 1B02 | First Floor | Basic Wall : Interior - Furring (38 mm Stud) | 1.2192 | 87
448627 | 1B05 | First Floor | Basic Wall : Interior - Partition (92mm Stud) | 1.2192 | 88
448708 | 1B11 | First Floor | Basic Wall : Interior - Partition (92mm Stud) | 1.2192 | 89
448821 | 1E10 | First Floor | Basic Wall : Interior - Furring (152 mm Stud) | 1.2192 | 90
449231 | 1E09 | First Floor | Basic Wall : Interior - Furring (152 mm Stud) | 1.2192 | 91
449283 | 1E12 | First Floor | Basic Wall : Interior - Partition (92mm Stud) | 1.2192 | 92
449421 | 1D26 | First Floor | Basic Wall : Interior - Plumbing (152mm Stud) | 1.2192 | 93
452118 | 2C08 | Second Floor | Basic Wall : Interior - Partition (92mm Stud) | 1.2192 | 95
452259 | 2C07 | Second Floor | Basic Wall : Interior - Partition (92mm Stud) | 1.2192 | 96
452378 | 2C24 | Second Floor | Basic Wall : Interior - Furring (38 mm Stud) | 1.2192 | 97
452606 | 2C23 | Second Floor | Basic Wall : Interior - Partition (92mm Stud) | 1.2192 | 98
452851 | 2B5 | Second Floor | Basic Wall : Interior - Furring (152 mm Stud) | 1.2192 | 99
453335 | 2B6 | Second Floor | Basic Wall : Interior - Furring (152 mm Stud) | 1.2192 | 100
453467 | 2B22 | Second Floor | Basic Wall : Interior - Furring (152 mm Stud) | 1.2192 | 101
453673 | 2D13 | Second Floor | Basic Wall : Interior - Partition (92mm Stud) | 1.2192 | 102

# IfcFurnishingElement: .7112mm (3)
In: 2C12
Type - ElementType: .7112mm
PSet_Revit_Constraints - Level: Second Floor; Elevation: 1.4 m
PSet_Revit_Other - InstallationDate: InstallationDate; SerialNumber: SerialNumber; WarrantyStartDate: WarrantyStartDate; BarCode: BarCode; AssetIdentifier: AssetIdentifier; TagNumber: TagNumber
PSet_Revit_Phasing - Phase Created: New Construction
PSet_Revit_Type_Materials and Finishes - Handle Material: Cabinets - Handles; Finish: Finish
PSet_Revit_Type_Dimensions - Depth: 0.3 m; Height: 0.6 m; Top Of Cabinet: 2 m; Width: 0.7112 m
PSet_Revit_Type_Identity Data - Manufacturer: Manufacturer; OmniClass Number: 23.40.35.17.47.11; OmniClass Title: Kitchen Casework
PSet_Revit_Type_Construction - Construction Type: Construction Type
PSet_Revit_Type_Other - AccessibilityPerformance: AccessibilityPerformance; CodePerformance: CodePerformance; Area: Area; Color: Color; Constituents: Constituents; Features: Features; Finish: Finish; Grade: Grade; Material: Material; ModelReference: ModelReference; NominalHeight: NominalHeight; NominalLength: NominalLength; NominalWidth: NominalWidth; ProductionYear: ProductionYear; Reference: Reference; Shape: Shape; Size: Size; SustainabilityPerformance: SustainabilityPerformance; WarrantyDescription: WarrantyDescription; WarrantyDurationLabor: WarrantyDurationLabor; WarrantyDurationParts: WarrantyDurationParts; WarrantyGuarantorLabor: WarrantyGuarantorLabor; WarrantyGuarantorParts: WarrantyGuarantorParts; ExpectedLife: ExpectedLife; ReplacementCost: ReplacementCost; AssetAccountingType: FIXED; ModelLabel: ModelLabel
Name (M_Upper Cabinet-Double Door-Wall:.7112mm:.7112mm:...)
340892
341187
341273

# IfcFurnishingElement: 1000mm, M_Base Cabinet-Double Door & 2 Drawer:1000mm:1000mm:336204
In: 2C17
Type - ElementType: 1000mm
PSet_Revit_Constraints - Level: Second Floor; Host: Level : Second Floor; Offset: 0 m; Moves With Nearby Elements: no
PSet_Revit_Other - InstallationDate: InstallationDate; SerialNumber: SerialNumber; WarrantyStartDate: WarrantyStartDate; BarCode: BarCode; AssetIdentifier: AssetIdentifier; TagNumber: TagNumber
PSet_Revit_Phasing - Phase Created: New Construction
PSet_Revit_Type_Materials and Finishes - Handle Material: Cabinets - Handles; Finish: Finish
PSet_Revit_Type_Dimensions - Depth: 0.6 m; Height: 0.86 m; Plinth Depth: 0.035 m; Plinth Height: 0.1 m; Width: 1 m
PSet_Revit_Type_Identity Data - Manufacturer: Manufacturer; OmniClass Number: 23.40.35.17.47.11; OmniClass Title: Kitchen Casework
PSet_Revit_Type_Construction - Construction Type: Construction Type
PSet_Revit_Type_Other - AccessibilityPerformance: AccessibilityPerformance; CodePerformance: CodePerformance; Area: Area; Color: Color; Constituents: Constituents; Features: Features; Finish: Finish; Grade: Grade; Material: Material; ModelReference: ModelReference; NominalHeight: NominalHeight; NominalLength: NominalLength; NominalWidth: NominalWidth; ProductionYear: ProductionYear; Reference: Reference; Shape: Shape; Size: Size; SustainabilityPerformance: SustainabilityPerformance; WarrantyDescription: WarrantyDescription; WarrantyDurationLabor: WarrantyDurationLabor; WarrantyDurationParts: WarrantyDurationParts; WarrantyGuarantorLabor: WarrantyGuarantorLabor; WarrantyGuarantorParts: WarrantyGuarantorParts; ExpectedLife: ExpectedLife; ReplacementCost: ReplacementCost; AssetAccountingType: FIXED; ModelLabel: ModelLabel

# IfcFurnishingElement: 1030mm (2)
Type - ElementType: 1030mm
PSet_Revit_Constraints - Offset: 0 m; Moves With Nearby Elements: no
PSet_Revit_Other - InstallationDate: InstallationDate; SerialNumber: SerialNumber; WarrantyStartDate: WarrantyStartDate; BarCode: BarCode; AssetIdentifier: AssetIdentifier; TagNumber: TagNumber
PSet_Revit_Phasing - Phase Created: New Construction
PSet_Revit_Type_Materials and Finishes - Handle Material: Cabinets - Handles; Finish: Finish
PSet_Revit_Type_Dimensions - Depth: 0.6 m; Height: 0.86 m; Plinth Depth: 0.035 m; Plinth Height: 0.1 m; Width: 1.03 m
PSet_Revit_Type_Identity Data - Manufacturer: Manufacturer; OmniClass Number: 23.40.35.17.47.11; OmniClass Title: Kitchen Casework
PSet_Revit_Type_Construction - Construction Type: Construction Type
PSet_Revit_Type_Other - AccessibilityPerformance: AccessibilityPerformance; CodePerformance: CodePerformance; Area: Area; Color: Color; Constituents: Constituents; Features: Features; Finish: Finish; Grade: Grade; Material: Material; ModelReference: ModelReference; NominalHeight: NominalHeight; NominalLength: NominalLength; NominalWidth: NominalWidth; ProductionYear: ProductionYear; Reference: Reference; Shape: Shape; Size: Size; SustainabilityPerformance: SustainabilityPerformance; WarrantyDescription: WarrantyDescription; WarrantyDurationLabor: WarrantyDurationLabor; WarrantyDurationParts: WarrantyDurationParts; WarrantyGuarantorLabor: WarrantyGuarantorLabor; WarrantyGuarantorParts: WarrantyGuarantorParts; ExpectedLife: ExpectedLife; ReplacementCost: ReplacementCost; AssetAccountingType: FIXED; ModelLabel: ModelLabel
Name (M_Base Cabinet-Double Door & 2 Drawer:1030mm:1030mm:...) | In | Level | Host
324898 | 1D06 | First Floor | Level : First Floor
342040 | 2C10 | Second Floor | Level : Second Floor

# IfcFurnishingElement: 1100mm (2)
In: 2C17
Type - ElementType: 1100mm
PSet_Revit_Constraints - Level: Second Floor; Host: Level : Second Floor; Offset: 0 m; Moves With Nearby Elements: no
PSet_Revit_Other - InstallationDate: InstallationDate; SerialNumber: SerialNumber; WarrantyStartDate: WarrantyStartDate; BarCode: BarCode; AssetIdentifier: AssetIdentifier; TagNumber: TagNumber
PSet_Revit_Phasing - Phase Created: New Construction
PSet_Revit_Type_Materials and Finishes - Handle Material: Cabinets - Handles; Finish: Finish
PSet_Revit_Type_Dimensions - Depth: 0.6 m; Height: 0.86 m; Plinth Depth: 0.035 m; Plinth Height: 0.1 m; Width: 1.1 m
PSet_Revit_Type_Identity Data - Manufacturer: Manufacturer; OmniClass Number: 23.40.35.17.47.11; OmniClass Title: Kitchen Casework
PSet_Revit_Type_Construction - Construction Type: Construction Type
PSet_Revit_Type_Other - AccessibilityPerformance: AccessibilityPerformance; CodePerformance: CodePerformance; Area: Area; Color: Color; Constituents: Constituents; Features: Features; Finish: Finish; Grade: Grade; Material: Material; ModelReference: ModelReference; NominalHeight: NominalHeight; NominalLength: NominalLength; NominalWidth: NominalWidth; ProductionYear: ProductionYear; Reference: Reference; Shape: Shape; Size: Size; SustainabilityPerformance: SustainabilityPerformance; WarrantyDescription: WarrantyDescription; WarrantyDurationLabor: WarrantyDurationLabor; WarrantyDurationParts: WarrantyDurationParts; WarrantyGuarantorLabor: WarrantyGuarantorLabor; WarrantyGuarantorParts: WarrantyGuarantorParts; ExpectedLife: ExpectedLife; ReplacementCost: ReplacementCost; AssetAccountingType: FIXED; ModelLabel: ModelLabel
Name (M_Base Cabinet-Double Door & 2 Drawer:1100mm:1100mm:...)
337237
337528

# IfcFurnishingElement: 1170mm (2)
In: 2C17
Type - ElementType: 1170mm
PSet_Revit_Constraints - Level: Second Floor; Elevation: 1.4 m
PSet_Revit_Other - InstallationDate: InstallationDate; SerialNumber: SerialNumber; WarrantyStartDate: WarrantyStartDate; BarCode: BarCode; AssetIdentifier: AssetIdentifier; TagNumber: TagNumber
PSet_Revit_Phasing - Phase Created: New Construction
PSet_Revit_Type_Materials and Finishes - Handle Material: Cabinets - Handles; Finish: Finish
PSet_Revit_Type_Dimensions - Depth: 0.3 m; Height: 0.6 m; Top Of Cabinet: 2 m; Width: 1.17 m
PSet_Revit_Type_Identity Data - Manufacturer: Manufacturer; OmniClass Number: 23.40.35.17.47.11; OmniClass Title: Kitchen Casework
PSet_Revit_Type_Construction - Construction Type: Construction Type
PSet_Revit_Type_Other - AccessibilityPerformance: AccessibilityPerformance; CodePerformance: CodePerformance; Area: Area; Color: Color; Constituents: Constituents; Features: Features; Finish: Finish; Grade: Grade; Material: Material; ModelReference: ModelReference; NominalHeight: NominalHeight; NominalLength: NominalLength; NominalWidth: NominalWidth; ProductionYear: ProductionYear; Reference: Reference; Shape: Shape; Size: Size; SustainabilityPerformance: SustainabilityPerformance; WarrantyDescription: WarrantyDescription; WarrantyDurationLabor: WarrantyDurationLabor; WarrantyDurationParts: WarrantyDurationParts; WarrantyGuarantorLabor: WarrantyGuarantorLabor; WarrantyGuarantorParts: WarrantyGuarantorParts; ExpectedLife: ExpectedLife; ReplacementCost: ReplacementCost; AssetAccountingType: FIXED; ModelLabel: ModelLabel
Name (M_Upper Cabinet-Double Door-Wall:1170mm:1170mm:...)
338233
339446

# IfcFurnishingElement: 1200mm (21)
Type - ElementType: 1200mm
PSet_Revit_Constraints - Offset: 0 m; Moves With Nearby Elements: no
PSet_Revit_Other - InstallationDate: InstallationDate; SerialNumber: SerialNumber; WarrantyStartDate: WarrantyStartDate; BarCode: BarCode; AssetIdentifier: AssetIdentifier; TagNumber: TagNumber
PSet_Revit_Phasing - Phase Created: New Construction
PSet_Revit_Type_Materials and Finishes - Handle Material: Cabinets - Handles; Finish: Finish
PSet_Revit_Type_Dimensions - Depth: 0.6 m; Height: 0.86 m; Plinth Depth: 0.035 m; Plinth Height: 0.1 m; Width: 1.2 m
PSet_Revit_Type_Identity Data - Manufacturer: Manufacturer; OmniClass Number: 23.40.35.17.47.11; OmniClass Title: Kitchen Casework
PSet_Revit_Type_Construction - Construction Type: Construction Type
PSet_Revit_Type_Other - AccessibilityPerformance: AccessibilityPerformance; CodePerformance: CodePerformance; Area: Area; Color: Color; Constituents: Constituents; Features: Features; Finish: Finish; Grade: Grade; Material: Material; ModelReference: ModelReference; NominalHeight: NominalHeight; NominalLength: NominalLength; NominalWidth: NominalWidth; ProductionYear: ProductionYear; Reference: Reference; Shape: Shape; Size: Size; SustainabilityPerformance: SustainabilityPerformance; WarrantyDescription: WarrantyDescription; WarrantyDurationLabor: WarrantyDurationLabor; WarrantyDurationParts: WarrantyDurationParts; WarrantyGuarantorLabor: WarrantyGuarantorLabor; WarrantyGuarantorParts: WarrantyGuarantorParts; ExpectedLife: ExpectedLife; ReplacementCost: ReplacementCost; AssetAccountingType: FIXED; ModelLabel: ModelLabel
Name (M_Base Cabinet-Double Door & 2 Drawer:1200mm:1200mm:...) | In | Level | Host
327512 | 1D38 | First Floor | Level : First Floor
330509 | 1E16 | First Floor | Level : First Floor
331445 | 1B10 | First Floor | Level : First Floor
332134 | 1A10 | First Floor | Level : First Floor
334263 | 2A12 | Second Floor | Level : Second Floor
334830 | 2B17 | Second Floor | Level : Second Floor
335272 | 2C17 | Second Floor | Level : Second Floor
335369 | 2C17 | Second Floor | Level : Second Floor
421917 | 1D02 | First Floor | Level : First Floor
422551 | 1D08 | First Floor | Level : First Floor
422727 | 1D10 | First Floor | Level : First Floor
422740 | 1D11 | First Floor | Level : First Floor
422813 | 1D13 | First Floor | Level : First Floor
422833 | 1D07 | First Floor | Level : First Floor
422835 | 1D09 | First Floor | Level : First Floor
424041 | 1D28 | First Floor | Level : First Floor
424044 | 1D32 | First Floor | Level : First Floor
424066 | 1D34 | First Floor | Level : First Floor
424068 | 1D36 | First Floor | Level : First Floor
424225 | 1D35 | First Floor | Level : First Floor
424254 | 1D31 | First Floor | Level : First Floor

# IfcFurnishingElement: 1270mm (2)
Type - ElementType: 1270mm
PSet_Revit_Constraints - Offset: 0 m; Moves With Nearby Elements: no
PSet_Revit_Other - InstallationDate: InstallationDate; SerialNumber: SerialNumber; WarrantyStartDate: WarrantyStartDate; BarCode: BarCode; AssetIdentifier: AssetIdentifier; TagNumber: TagNumber
PSet_Revit_Phasing - Phase Created: New Construction
PSet_Revit_Type_Materials and Finishes - Handle Material: Cabinets - Handles; Finish: Finish
PSet_Revit_Type_Dimensions - Depth: 0.6 m; Height: 0.86 m; Plinth Depth: 0.035 m; Plinth Height: 0.1 m; Width: 1.27 m
PSet_Revit_Type_Identity Data - Manufacturer: Manufacturer; OmniClass Number: 23.40.35.17.47.11; OmniClass Title: Kitchen Casework
PSet_Revit_Type_Construction - Construction Type: Construction Type
PSet_Revit_Type_Other - AccessibilityPerformance: AccessibilityPerformance; CodePerformance: CodePerformance; Area: Area; Color: Color; Constituents: Constituents; Features: Features; Finish: Finish; Grade: Grade; Material: Material; ModelReference: ModelReference; NominalHeight: NominalHeight; NominalLength: NominalLength; NominalWidth: NominalWidth; ProductionYear: ProductionYear; Reference: Reference; Shape: Shape; Size: Size; SustainabilityPerformance: SustainabilityPerformance; WarrantyDescription: WarrantyDescription; WarrantyDurationLabor: WarrantyDurationLabor; WarrantyDurationParts: WarrantyDurationParts; WarrantyGuarantorLabor: WarrantyGuarantorLabor; WarrantyGuarantorParts: WarrantyGuarantorParts; ExpectedLife: ExpectedLife; ReplacementCost: ReplacementCost; AssetAccountingType: FIXED; ModelLabel: ModelLabel
Name (M_Base Cabinet-Double Door & 2 Drawer:1270mm:1270mm:...) | In | Level | Host
329846 | 1E30 | First Floor | Level : First Floor
335821 | 2C17 | Second Floor | Level : Second Floor

# IfcFurnishingElement: 1360mm, M_Base Cabinet-Double Door & 2 Drawer:1360mm:1360mm:332839
In: 2A13
Type - ElementType: 1360mm
PSet_Revit_Constraints - Level: Second Floor; Host: Level : Second Floor; Offset: 0 m; Moves With Nearby Elements: no
PSet_Revit_Other - InstallationDate: InstallationDate; SerialNumber: SerialNumber; WarrantyStartDate: WarrantyStartDate; BarCode: BarCode; AssetIdentifier: AssetIdentifier; TagNumber: TagNumber
PSet_Revit_Phasing - Phase Created: New Construction
PSet_Revit_Type_Materials and Finishes - Handle Material: Cabinets - Handles; Finish: Finish
PSet_Revit_Type_Dimensions - Depth: 0.6 m; Height: 0.86 m; Plinth Depth: 0.035 m; Plinth Height: 0.1 m; Width: 1.36 m
PSet_Revit_Type_Identity Data - Manufacturer: Manufacturer; OmniClass Number: 23.40.35.17.47.11; OmniClass Title: Kitchen Casework
PSet_Revit_Type_Construction - Construction Type: Construction Type
PSet_Revit_Type_Other - AccessibilityPerformance: AccessibilityPerformance; CodePerformance: CodePerformance; Area: Area; Color: Color; Constituents: Constituents; Features: Features; Finish: Finish; Grade: Grade; Material: Material; ModelReference: ModelReference; NominalHeight: NominalHeight; NominalLength: NominalLength; NominalWidth: NominalWidth; ProductionYear: ProductionYear; Reference: Reference; Shape: Shape; Size: Size; SustainabilityPerformance: SustainabilityPerformance; WarrantyDescription: WarrantyDescription; WarrantyDurationLabor: WarrantyDurationLabor; WarrantyDurationParts: WarrantyDurationParts; WarrantyGuarantorLabor: WarrantyGuarantorLabor; WarrantyGuarantorParts: WarrantyGuarantorParts; ExpectedLife: ExpectedLife; ReplacementCost: ReplacementCost; AssetAccountingType: FIXED; ModelLabel: ModelLabel

# IfcFurnishingElement: 600mm (17)
Type - ElementType: 600mm
PSet_Revit_Other - InstallationDate: InstallationDate; SerialNumber: SerialNumber; WarrantyStartDate: WarrantyStartDate; BarCode: BarCode; AssetIdentifier: AssetIdentifier; TagNumber: TagNumber
PSet_Revit_Phasing - Phase Created: New Construction
PSet_Revit_Type_Materials and Finishes - Handle Material: Cabinets - Handles; Finish: Finish
PSet_Revit_Type_Dimensions - Width: 0.6 m
PSet_Revit_Type_Identity Data - Manufacturer: Manufacturer; OmniClass Number: 23.40.35.17.47.11; OmniClass Title: Kitchen Casework
PSet_Revit_Type_Construction - Construction Type: Construction Type
PSet_Revit_Type_Other - AccessibilityPerformance: AccessibilityPerformance; CodePerformance: CodePerformance; Area: Area; Color: Color; Constituents: Constituents; Features: Features; Finish: Finish; Grade: Grade; Material: Material; ModelReference: ModelReference; NominalHeight: NominalHeight; NominalLength: NominalLength; NominalWidth: NominalWidth; ProductionYear: ProductionYear; Reference: Reference; Shape: Shape; Size: Size; SustainabilityPerformance: SustainabilityPerformance; WarrantyDescription: WarrantyDescription; WarrantyDurationLabor: WarrantyDurationLabor; WarrantyDurationParts: WarrantyDurationParts; WarrantyGuarantorLabor: WarrantyGuarantorLabor; WarrantyGuarantorParts: WarrantyGuarantorParts; ExpectedLife: ExpectedLife; ReplacementCost: ReplacementCost; AssetAccountingType: FIXED; ModelLabel: ModelLabel
Name | In | Level | Host | Offset (m) | Moves With Nearby Elements | Depth (m) | Height (m) | Plinth Depth (m) | Plinth Height (m)
M_Base Cabinet-Double Door & 2 Drawer:600mm:600mm:327015 | 1D40 | First Floor | Level : First Floor | 0 | no | 0.6 | 0.86 | 0.035 | 0.1
M_Base Cabinet-Double Door & 2 Drawer:600mm:600mm:328330 | 1E11 | First Floor | Level : First Floor | 0 | no | 0.6 | 0.86 | 0.035 | 0.1
M_Base Cabinet-Double Door & 2 Drawer:600mm:600mm:329197 | 1E04 | First Floor | Level : First Floor | 0 | no | 0.6 | 0.86 | 0.035 | 0.1
M_Base Cabinet-Double Door & 2 Drawer:600mm:600mm:331196 | 1B10 | First Floor | Level : First Floor | 0 | no | 0.6 | 0.86 | 0.035 | 0.1
M_Base Cabinet-Double Door & 2 Drawer:600mm:600mm:334667 | 2B17 | Second Floor | Level : Second Floor | 0 | no | 0.6 | 0.86 | 0.035 | 0.1
M_Upper Cabinet-Double Door-Wall:600mm:600mm:336423 | 2C17 | Second Floor |  |  |  | 0.3 | 0.6 | PSet_Revit_Constraints - Elevation: 1.4 m; PSet_Revit_Type_Dimensions - Top Of Cabinet: 2 m
M_Upper Cabinet-Double Door-Wall:600mm:600mm:336513 | 2C17 | Second Floor |  |  |  | 0.3 | 0.6 | PSet_Revit_Constraints - Elevation: 1.4 m; PSet_Revit_Type_Dimensions - Top Of Cabinet: 2 m
M_Upper Cabinet-Double Door-Wall:600mm:600mm:336684 | 2C17 | Second Floor |  |  |  | 0.3 | 0.6 | PSet_Revit_Constraints - Elevation: 1.4 m; PSet_Revit_Type_Dimensions - Top Of Cabinet: 2 m
M_Base Cabinet-Double Door & 2 Drawer:600mm:600mm:337565 | 2C17 | Second Floor | Level : Second Floor | 0 | no | 0.6 | 0.86 | 0.035 | 0.1
M_Base Cabinet-Double Door & 2 Drawer:600mm:600mm:337712 | 2C17 | Second Floor | Level : Second Floor | 0 | no | 0.6 | 0.86 | 0.035 | 0.1
M_Base Cabinet-Double Door & 2 Drawer:600mm:600mm:337783 | 2C17 | Second Floor | Level : Second Floor | 0 | no | 0.6 | 0.86 | 0.035 | 0.1
M_Base Cabinet-Double Door & 2 Drawer:600mm:600mm:337842 | 2C17 | Second Floor | Level : Second Floor | 0 | no | 0.6 | 0.86 | 0.035 | 0.1
M_Base Cabinet-Double Door & 2 Drawer:600mm:600mm:339551 | 2C12 | Second Floor | Level : Second Floor | 0 | no | 0.6 | 0.86 | 0.035 | 0.1
M_Base Cabinet-Double Door & 2 Drawer:600mm:600mm:341762 | 2C10 | Second Floor | Level : Second Floor | 0 | no | 0.6 | 0.86 | 0.035 | 0.1
M_Base Cabinet-Double Door & 2 Drawer:600mm:600mm:342685 | 2C22 | Second Floor | Level : Second Floor | 0 | no | 0.6 | 0.86 | 0.035 | 0.1
M_Base Cabinet-Double Door & 2 Drawer:600mm:600mm:423249 | 1D05 | First Floor | Level : First Floor | 0 | no | 0.6 | 0.86 | 0.035 | 0.1
M_Base Cabinet-Double Door & 2 Drawer:600mm:600mm:426210 | 2C12 | Second Floor | Level : Second Floor | 0 | no | 0.6 | 0.86 | 0.035 | 0.1

# IfcFurnishingElement: 600mm Depth (51)
Type - ElementType: 600mm Depth
PSet_Revit_Constraints - Offset: 0 m; Moves With Nearby Elements: no
PSet_Revit_Other - InstallationDate: InstallationDate; SerialNumber: SerialNumber; WarrantyStartDate: WarrantyStartDate; BarCode: BarCode; AssetIdentifier: AssetIdentifier; TagNumber: TagNumber
PSet_Revit_Phasing - Phase Created: New Construction
PSet_Revit_Type_Dimensions - Counter Thickness: 0.04 m; Height: 0.9 m
PSet_Revit_Type_Materials and Finishes - Finish: Finish
PSet_Revit_Type_Identity Data - Manufacturer: Manufacturer; OmniClass Number: 23.40.35.17.47.11; OmniClass Title: Kitchen Casework
PSet_Revit_Type_Construction - Construction Type: Construction Type
PSet_Revit_Type_Other - AccessibilityPerformance: AccessibilityPerformance; CodePerformance: CodePerformance; Area: Area; Color: Color; Constituents: Constituents; Features: Features; Finish: Finish; Grade: Grade; Material: Material; ModelReference: ModelReference; NominalHeight: NominalHeight; NominalLength: NominalLength; NominalWidth: NominalWidth; ProductionYear: ProductionYear; Reference: Reference; Shape: Shape; Size: Size; SustainabilityPerformance: SustainabilityPerformance; WarrantyDescription: WarrantyDescription; WarrantyDurationLabor: WarrantyDurationLabor; WarrantyDurationParts: WarrantyDurationParts; WarrantyGuarantorLabor: WarrantyGuarantorLabor; WarrantyGuarantorParts: WarrantyGuarantorParts; ExpectedLife: ExpectedLife; ReplacementCost: ReplacementCost; AssetAccountingType: FIXED; ModelLabel: ModelLabel
Name | In | Length (m) | Level | Host | Depth (m) | Sink Location (m) | Sink Location To Wall (m) | Sink Opening Depth (m) | Sink Opening Width (m)
M_Counter Top:600mm Depth:600mm Depth:326252 | 1D06 | 1.946 | First Floor | Level : First Floor | 0.6 | PSet_Revit_Construction - Backsplash Visibility: yes
M_Counter Top:600mm Depth:600mm Depth:327273 | 1D40 | 0.61 | First Floor | Level : First Floor | 0.6 | PSet_Revit_Construction - Backsplash Visibility: yes
M_Counter Top:600mm Depth:600mm Depth:328859 | 1E04 | 1.525 | First Floor | Level : First Floor | 0.6 | PSet_Revit_Construction - Backsplash Visibility: yes
M_Counter Top:600mm Depth:600mm Depth:329412 | 1E11 | 1.525 | First Floor | Level : First Floor | 0.6 | PSet_Revit_Construction - Backsplash Visibility: yes
M_Counter Top w Sink Hole:600mm Depth:600mm Depth:330055 | 1E30 | 1.27 | First Floor | Level : First Floor | 0.625 | 0.351918 | 0.1 | 0.378 | 0.4826
M_Counter Top w Sink Hole:600mm Depth:600mm Depth:330800 | 1E16 | 1.21 | First Floor | Level : First Floor | 0.625 | 0.908082 | 0.113 | 0.403931 | 0.4826
M_Counter Top w Sink Hole:600mm Depth:600mm Depth:331805 | 1B10 | 1.81 | First Floor | Level : First Floor | 0.625 | 0.263836 | 0.1 | 0.378 | 0.31515
M_Counter Top:600mm Depth:600mm Depth:332580 | 1A10 | 1.2 | First Floor | Level : First Floor | 0.6 | PSet_Revit_Construction - Backsplash Visibility: yes
M_Counter Top-L Shaped:600mm Depth:600mm Depth:333309 | 2A13 |  | Second Floor | Level : Second Floor | 0.625 | PSet_Revit_Dimensions - Length - Leg 1: 2.026 m; Length - Leg 2: 2.11804 m
M_Counter Top:600mm Depth:600mm Depth:334473 | 2A12 | 1.22 | Second Floor | Level : Second Floor | 0.6 | PSet_Revit_Construction - Backsplash Visibility: yes
M_Counter Top:600mm Depth:600mm Depth:334957 | 2B17 | 2.406 | Second Floor | Level : Second Floor | 0.6 | PSet_Revit_Construction - Backsplash Visibility: yes
M_Counter Top:600mm Depth:600mm Depth:338272 | 2C17 | 2.18932 | Second Floor | Level : Second Floor | 0.6 | PSet_Revit_Construction - Backsplash Visibility: yes
M_Counter Top w Sink Hole:600mm Depth:600mm Depth:338411 | 2C17 | 2.46715 | Second Floor | Level : Second Floor | 0.625 | 2.14329 | 0.1 | 0.378 | 0.587
M_Counter Top w Sink Hole:600mm Depth:600mm Depth:338826 | 2C17 | 4.69696 | Second Floor | Level : Second Floor | 0.625 | 0.36704 | 0.1 | 0.378 | 0.587
M_Counter Top:600mm Depth:600mm Depth:339049 | 2C17 | 1 | Second Floor | Level : Second Floor | 0.6 | PSet_Revit_Construction - Backsplash Visibility: yes
M_Counter Top w Sink Hole:600mm Depth:600mm Depth:341491 | 2C12 | 3.872 | Second Floor | Level : Second Floor | 0.625 | 1.03026 | 0.1 | 0.378 | 0.587
M_Counter Top w Sink Hole:600mm Depth:600mm Depth:342492 | 2C10 | 3.036 | Second Floor | Level : Second Floor | 0.625 | 1.346 | 0.1 | 0.378 | 0.587
M_Counter Top w Sink Hole:600mm Depth:600mm Depth:357065 | 1D22 | 3.05 | First Floor | Level : First Floor | 0.625 | 2.72545 | 0.122044 | 0.417956 | 0.4826
M_Counter Top:600mm Depth:600mm Depth:359594 | 1A16 | 0.92 | First Floor | Level : First Floor | 0.6 | PSet_Revit_Construction - Backsplash Visibility: no
M_Counter Top:600mm Depth:600mm Depth:360318 | 1A16 | 0.92 | First Floor | Level : First Floor | 0.6 | PSet_Revit_Construction - Backsplash Visibility: no
M_Counter Top:600mm Depth:600mm Depth:392794 | Second Floor | 1.27547 | Second Floor | Level : Second Floor | 0.6 | PSet_Revit_Construction - Backsplash Visibility: no
M_Counter Top:600mm Depth:600mm Depth:400374 | 2C22 | 1.50644 | Second Floor | Level : Second Floor | 0.6 | PSet_Revit_Construction - Backsplash Visibility: yes
M_Counter Top w Sink Hole:600mm Depth:600mm Depth:422054 | 1D02 | 1.2 | First Floor | Level : First Floor | 0.625 | 0.6 | 0.16973 | 0.391258 | 0.587
M_Counter Top w Sink Hole:600mm Depth:600mm Depth:422552 | 1D08 | 1.2 | First Floor | Level : First Floor | 0.625 | 0.6 | 0.16973 | 0.391258 | 0.587
M_Counter Top w Sink Hole:600mm Depth:600mm Depth:422728 | 1D10 | 1.2 | First Floor | Level : First Floor | 0.625 | 0.6 | 0.16973 | 0.391258 | 0.587
M_Counter Top w Sink Hole:600mm Depth:600mm Depth:422741 | 1D11 | 1.2 | First Floor | Level : First Floor | 0.625 | 0.6 | 0.16973 | 0.391258 | 0.587
M_Counter Top w Sink Hole:600mm Depth:600mm Depth:422814 | 1D13 | 1.2 | First Floor | Level : First Floor | 0.625 | 0.6 | 0.16973 | 0.391258 | 0.587
M_Counter Top w Sink Hole:600mm Depth:600mm Depth:422834 | 1D07 | 1.2 | First Floor | Level : First Floor | 0.625 | 0.6 | 0.16973 | 0.391258 | 0.587
M_Counter Top w Sink Hole:600mm Depth:600mm Depth:422836 | 1D09 | 1.2 | First Floor | Level : First Floor | 0.625 | 0.6 | 0.16973 | 0.391258 | 0.587
M_Counter Top w Sink Hole:600mm Depth:600mm Depth:422863 | 1D05 | 2.41 | First Floor | Level : First Floor | 0.625 | 1.205 | 0.137017 | 0.4064 | 0.587
M_Counter Top w Sink Hole:600mm Depth:600mm Depth:424042 | 1D28 | 1.2 | First Floor | Level : First Floor | 0.625 | 0.6 | 0.16973 | 0.391258 | 0.587
M_Counter Top w Sink Hole:600mm Depth:600mm Depth:424045 | 1D32 | 1.2 | First Floor | Level : First Floor | 0.625 | 0.6 | 0.16973 | 0.391258 | 0.587
M_Counter Top w Sink Hole:600mm Depth:600mm Depth:424067 | 1D34 | 1.2 | First Floor | Level : First Floor | 0.625 | 0.6 | 0.16973 | 0.391258 | 0.587
M_Counter Top w Sink Hole:600mm Depth:600mm Depth:424069 | 1D36 | 1.2 | First Floor | Level : First Floor | 0.625 | 0.6 | 0.16973 | 0.391258 | 0.587
M_Counter Top w Sink Hole:600mm Depth:600mm Depth:424107 | 1D38 | 1.2 | First Floor | Level : First Floor | 0.625 | 0.842659 | 0.16973 | 0.391258 | 0.587
M_Counter Top w Sink Hole:600mm Depth:600mm Depth:424226 | 1D35 | 1.2 | First Floor | Level : First Floor | 0.625 | 0.6 | 0.16973 | 0.391258 | 0.587
M_Counter Top w Sink Hole:600mm Depth:600mm Depth:424255 | 1D31 | 1.2 | First Floor | Level : First Floor | 0.625 | 0.6 | 0.16973 | 0.391258 | 0.587
M_Counter Top w Sink Hole:600mm Depth:600mm Depth:424493 | 1B04 | 2.5 | First Floor | Level : First Floor | 0.625 | 1.628 | 0.1 | 0.378 | 0.587
M_Counter Top w Sink Hole:600mm Depth:600mm Depth:424614 | 1B04 | 4.35711 | First Floor | Level : First Floor | 0.625 | 0.751909 | 0.1 | 0.378 | 0.587
M_Counter Top w Sink Hole:600mm Depth:600mm Depth:424797 | 1B04 | 2.57089 | First Floor | Level : First Floor | 0.625 | 1 | 0.1 | 0.378 | 0.587
M_Counter Top:600mm Depth:600mm Depth:425375 | 2C16 | 2.12954 | Second Floor | Level : Second Floor | 0.6 | PSet_Revit_Construction - Backsplash Visibility: yes
M_Counter Top w Sink Hole:600mm Depth:600mm Depth:425594 | 2C14 | 2.10996 | Second Floor | Level : Second Floor | 0.625 | 0.338951 | 0.1 | 0.378 | 0.3556
M_Counter Top w Sink Hole:600mm Depth:600mm Depth:426710 | 2C09 | 2.10996 | Second Floor | Level : Second Floor | 0.625 | 0.338951 | 0.1 | 0.378 | 0.3556
M_Counter Top w Sink Hole:600mm Depth:600mm Depth:426720 | 2C06 | 2.10996 | Second Floor | Level : Second Floor | 0.625 | 0.338951 | 0.1 | 0.378 | 0.3556
M_Counter Top w Sink Hole:600mm Depth:600mm Depth:426730 | 2C04 | 2.10996 | Second Floor | Level : Second Floor | 0.625 | 0.338951 | 0.1 | 0.378 | 0.3556
M_Counter Top w Sink Hole:600mm Depth:600mm Depth:426738 | 2C02 | 2.10996 | Second Floor | Level : Second Floor | 0.625 | 0.338951 | 0.1 | 0.378 | 0.3556
M_Counter Top w Sink Hole:600mm Depth:600mm Depth:426746 | 2A09 | 2.10996 | Second Floor | Level : Second Floor | 0.625 | 0.338951 | 0.1 | 0.378 | 0.3556
M_Counter Top w Sink Hole:600mm Depth:600mm Depth:426758 | 2A08 | 2.10996 | Second Floor | Level : Second Floor | 0.625 | 0.338951 | 0.1 | 0.378 | 0.3556
M_Counter Top w Sink Hole:600mm Depth:600mm Depth:426806 | 2A07 | 2.10996 | Second Floor | Level : Second Floor | 0.625 | 0.338951 | 0.1 | 0.378 | 0.3556
M_Counter Top w Sink Hole:600mm Depth:600mm Depth:426851 | 2A06 | 2.10996 | Second Floor | Level : Second Floor | 0.625 | 0.338951 | 0.1 | 0.378 | 0.3556
M_Counter Top w Sink Hole:600mm Depth:600mm Depth:426911 | 2A05 | 2.10996 | Second Floor | Level : Second Floor | 0.625 | 0.338951 | 0.1 | 0.378 | 0.3556

# IfcFurnishingElement: 610mm (2)
Type - ElementType: 610mm
PSet_Revit_Constraints - Level: First Floor; Elevation: 1.4 m
PSet_Revit_Other - InstallationDate: InstallationDate; SerialNumber: SerialNumber; WarrantyStartDate: WarrantyStartDate; BarCode: BarCode; AssetIdentifier: AssetIdentifier; TagNumber: TagNumber
PSet_Revit_Phasing - Phase Created: New Construction
PSet_Revit_Type_Materials and Finishes - Handle Material: Cabinets - Handles; Finish: Finish
PSet_Revit_Type_Dimensions - Depth: 0.3 m; Height: 0.6 m; Top Of Cabinet: 2 m; Width: 0.61 m
PSet_Revit_Type_Identity Data - Manufacturer: Manufacturer; OmniClass Number: 23.40.35.17.47.11; OmniClass Title: Kitchen Casework
PSet_Revit_Type_Construction - Construction Type: Construction Type
PSet_Revit_Type_Other - AccessibilityPerformance: AccessibilityPerformance; CodePerformance: CodePerformance; Area: Area; Color: Color; Constituents: Constituents; Features: Features; Finish: Finish; Grade: Grade; Material: Material; ModelReference: ModelReference; NominalHeight: NominalHeight; NominalLength: NominalLength; NominalWidth: NominalWidth; ProductionYear: ProductionYear; Reference: Reference; Shape: Shape; Size: Size; SustainabilityPerformance: SustainabilityPerformance; WarrantyDescription: WarrantyDescription; WarrantyDurationLabor: WarrantyDurationLabor; WarrantyDurationParts: WarrantyDurationParts; WarrantyGuarantorLabor: WarrantyGuarantorLabor; WarrantyGuarantorParts: WarrantyGuarantorParts; ExpectedLife: ExpectedLife; ReplacementCost: ReplacementCost; AssetAccountingType: FIXED; ModelLabel: ModelLabel
Name (M_Upper Cabinet-Single Door-Wall:610mm:610mm:...) | In
326852 | 1D40
332323 | 1A10

# IfcFurnishingElement: 760mm (2)
In: 2C12
Type - ElementType: 760mm
PSet_Revit_Constraints - Level: Second Floor; Host: Level : Second Floor; Offset: 0 m; Moves With Nearby Elements: no
PSet_Revit_Other - InstallationDate: InstallationDate; SerialNumber: SerialNumber; WarrantyStartDate: WarrantyStartDate; BarCode: BarCode; AssetIdentifier: AssetIdentifier; TagNumber: TagNumber
PSet_Revit_Phasing - Phase Created: New Construction
PSet_Revit_Type_Materials and Finishes - Handle Material: Cabinets - Handles; Finish: Finish
PSet_Revit_Type_Dimensions - Depth: 0.6 m; Height: 0.86 m; Plinth Depth: 0.035 m; Plinth Height: 0.1 m; Width: 0.76 m
PSet_Revit_Type_Identity Data - Manufacturer: Manufacturer; OmniClass Number: 23.40.35.17.47.11; OmniClass Title: Kitchen Casework
PSet_Revit_Type_Construction - Construction Type: Construction Type
PSet_Revit_Type_Other - AccessibilityPerformance: AccessibilityPerformance; CodePerformance: CodePerformance; Area: Area; Color: Color; Constituents: Constituents; Features: Features; Finish: Finish; Grade: Grade; Material: Material; ModelReference: ModelReference; NominalHeight: NominalHeight; NominalLength: NominalLength; NominalWidth: NominalWidth; ProductionYear: ProductionYear; Reference: Reference; Shape: Shape; Size: Size; SustainabilityPerformance: SustainabilityPerformance; WarrantyDescription: WarrantyDescription; WarrantyDurationLabor: WarrantyDurationLabor; WarrantyDurationParts: WarrantyDurationParts; WarrantyGuarantorLabor: WarrantyGuarantorLabor; WarrantyGuarantorParts: WarrantyGuarantorParts; ExpectedLife: ExpectedLife; ReplacementCost: ReplacementCost; AssetAccountingType: FIXED; ModelLabel: ModelLabel
Name (M_Base Cabinet-Double Door & 2 Drawer:760mm:760mm:...)
339760
340333

# IfcFurnishingElement: 762mm, M_Upper Cabinet-Double Door-Wall:762mm:762mm:343193
In: 2C22
Type - ElementType: 762mm
PSet_Revit_Constraints - Level: Second Floor; Elevation: 1.4 m
PSet_Revit_Other - InstallationDate: InstallationDate; SerialNumber: SerialNumber; WarrantyStartDate: WarrantyStartDate; BarCode: BarCode; AssetIdentifier: AssetIdentifier; TagNumber: TagNumber
PSet_Revit_Phasing - Phase Created: New Construction
PSet_Revit_Type_Materials and Finishes - Handle Material: Cabinets - Handles; Finish: Finish
PSet_Revit_Type_Dimensions - Depth: 0.3 m; Height: 0.6 m; Top Of Cabinet: 2 m; Width: 0.762 m
PSet_Revit_Type_Identity Data - Manufacturer: Manufacturer; OmniClass Number: 23.40.35.17.47.11; OmniClass Title: Kitchen Casework
PSet_Revit_Type_Construction - Construction Type: Construction Type
PSet_Revit_Type_Other - AccessibilityPerformance: AccessibilityPerformance; CodePerformance: CodePerformance; Area: Area; Color: Color; Constituents: Constituents; Features: Features; Finish: Finish; Grade: Grade; Material: Material; ModelReference: ModelReference; NominalHeight: NominalHeight; NominalLength: NominalLength; NominalWidth: NominalWidth; ProductionYear: ProductionYear; Reference: Reference; Shape: Shape; Size: Size; SustainabilityPerformance: SustainabilityPerformance; WarrantyDescription: WarrantyDescription; WarrantyDurationLabor: WarrantyDurationLabor; WarrantyDurationParts: WarrantyDurationParts; WarrantyGuarantorLabor: WarrantyGuarantorLabor; WarrantyGuarantorParts: WarrantyGuarantorParts; ExpectedLife: ExpectedLife; ReplacementCost: ReplacementCost; AssetAccountingType: FIXED; ModelLabel: ModelLabel

# IfcFurnishingElement: 900mm (7)
Type - ElementType: 900mm
PSet_Revit_Constraints - Offset: 0 m; Moves With Nearby Elements: no
PSet_Revit_Other - InstallationDate: InstallationDate; SerialNumber: SerialNumber; WarrantyStartDate: WarrantyStartDate; BarCode: BarCode; AssetIdentifier: AssetIdentifier; TagNumber: TagNumber
PSet_Revit_Phasing - Phase Created: New Construction
PSet_Revit_Type_Materials and Finishes - Handle Material: Cabinets - Handles; Finish: Finish
PSet_Revit_Type_Dimensions - Depth: 0.6 m; Height: 0.86 m; Plinth Depth: 0.035 m; Plinth Height: 0.1 m; Width: 0.9 m
PSet_Revit_Type_Identity Data - Manufacturer: Manufacturer; OmniClass Number: 23.40.35.17.47.11; OmniClass Title: Kitchen Casework
PSet_Revit_Type_Construction - Construction Type: Construction Type
PSet_Revit_Type_Other - AccessibilityPerformance: AccessibilityPerformance; CodePerformance: CodePerformance; Area: Area; Color: Color; Constituents: Constituents; Features: Features; Finish: Finish; Grade: Grade; Material: Material; ModelReference: ModelReference; NominalHeight: NominalHeight; NominalLength: NominalLength; NominalWidth: NominalWidth; ProductionYear: ProductionYear; Reference: Reference; Shape: Shape; Size: Size; SustainabilityPerformance: SustainabilityPerformance; WarrantyDescription: WarrantyDescription; WarrantyDurationLabor: WarrantyDurationLabor; WarrantyDurationParts: WarrantyDurationParts; WarrantyGuarantorLabor: WarrantyGuarantorLabor; WarrantyGuarantorParts: WarrantyGuarantorParts; ExpectedLife: ExpectedLife; ReplacementCost: ReplacementCost; AssetAccountingType: FIXED; ModelLabel: ModelLabel
Name (M_Base Cabinet-Double Door & 2 Drawer:900mm:900mm:...) | In | Level | Host
324205 | 1D06 | First Floor | Level : First Floor
328134 | 1E11 | First Floor | Level : First Floor
328719 | 1E04 | First Floor | Level : First Floor
339983 | 2C12 | Second Floor | Level : Second Floor
342914 | 2C22 | Second Floor | Level : Second Floor
422862 | 1D05 | First Floor | Level : First Floor
423176 | 1D05 | First Floor | Level : First Floor

# IfcFurnishingElement: 915mm (4)
Type - ElementType: 915mm
PSet_Revit_Constraints - Level: First Floor; Elevation: 1.4 m
PSet_Revit_Other - InstallationDate: InstallationDate; SerialNumber: SerialNumber; WarrantyStartDate: WarrantyStartDate; BarCode: BarCode; AssetIdentifier: AssetIdentifier; TagNumber: TagNumber
PSet_Revit_Phasing - Phase Created: New Construction
PSet_Revit_Type_Materials and Finishes - Handle Material: Cabinets - Handles; Finish: Finish
PSet_Revit_Type_Dimensions - Depth: 0.305 m; Height: 0.6 m; Top Of Cabinet: 2 m; Width: 0.915 m
PSet_Revit_Type_Identity Data - Manufacturer: Manufacturer; OmniClass Number: 23.40.35.17.47.11; OmniClass Title: Kitchen Casework
PSet_Revit_Type_Construction - Construction Type: Construction Type
PSet_Revit_Type_Other - AccessibilityPerformance: AccessibilityPerformance; CodePerformance: CodePerformance; Area: Area; Color: Color; Constituents: Constituents; Features: Features; Finish: Finish; Grade: Grade; Material: Material; ModelReference: ModelReference; NominalHeight: NominalHeight; NominalLength: NominalLength; NominalWidth: NominalWidth; ProductionYear: ProductionYear; Reference: Reference; Shape: Shape; Size: Size; SustainabilityPerformance: SustainabilityPerformance; WarrantyDescription: WarrantyDescription; WarrantyDurationLabor: WarrantyDurationLabor; WarrantyDurationParts: WarrantyDurationParts; WarrantyGuarantorLabor: WarrantyGuarantorLabor; WarrantyGuarantorParts: WarrantyGuarantorParts; ExpectedLife: ExpectedLife; ReplacementCost: ReplacementCost; AssetAccountingType: FIXED; ModelLabel: ModelLabel
Name (M_Upper Cabinet-Double Door-Wall:915mm:915mm:...) | In
324018 | 1D06
328573 | 1E11
328637 | 1E04
331680 | 1B10

# IfcMember: 19mm Radius (16)
In: First Floor
Type - ElementType: 19mm Radius; PredefinedType: MULLION
Material: Metal - Aluminium
PSet_Revit_Other - InstallationDate: InstallationDate; SerialNumber: SerialNumber; WarrantyStartDate: WarrantyStartDate; BarCode: BarCode; AssetIdentifier: AssetIdentifier; TagNumber: TagNumber
PSet_Revit_Phasing - Phase Created: New Construction
PSet_Revit_Type_Materials and Finishes - Material: Metal - Aluminium
PSet_Revit_Type_Construction - Profile: System Mullion Profile: Circular; Position: Perpendicular to Face; Corner Mullion: no
PSet_Revit_Type_Constraints - Angle: 0 deg; Offset: 0 m
PSet_Revit_Type_Other - Radius: 0.019 m; AccessibilityPerformance: AccessibilityPerformance; CodePerformance: CodePerformance; Color: Color; Constituents: Constituents; Features: Features; Finish: Finish; Grade: Grade; Material: Material; ModelReference: ModelReference; NominalHeight: NominalHeight; NominalLength: NominalLength; NominalWidth: NominalWidth; ProductionYear: ProductionYear; Reference: Reference; Shape: Shape; Size: Size; SustainabilityPerformance: SustainabilityPerformance; WarrantyDescription: WarrantyDescription; WarrantyDurationLabor: WarrantyDurationLabor; WarrantyDurationParts: WarrantyDurationParts; WarrantyGuarantorLabor: WarrantyGuarantorLabor; WarrantyGuarantorParts: WarrantyGuarantorParts; ExpectedLife: ExpectedLife; ReplacementCost: ReplacementCost; AssetAccountingType: FIXED; Classification Code: 23-25 20 14 11 11 11; Classification Description: Curtain Wall Frames; ModelLabel: ModelLabel
PSet_Revit_Type_Identity Data - Manufacturer: Manufacturer
Name (Circular Mullion:19mm Radius:19mm Radius:...) | Length (m)
346994 | 1.59213
346996 | 0.355576
346997 | 2.702
346998 | 1.02237
346999 | 2.702
347000 | 2
347003 | 2
347019 | 2
347020 | 2
347021 | 2
347022 | 2
347593 | 1.043
347594 | 1.043
347598 | 2
347599 | 2
347600 | 2

# IfcMember: 50 x 150mm (506)
Type - ElementType: 50 x 150mm; PredefinedType: MULLION
Material: Metal - Aluminium
PSet_Revit_Other - InstallationDate: InstallationDate; SerialNumber: SerialNumber; WarrantyStartDate: WarrantyStartDate; BarCode: BarCode; AssetIdentifier: AssetIdentifier; TagNumber: TagNumber
PSet_Revit_Phasing - Phase Created: New Construction
PSet_Revit_Type_Materials and Finishes - Material: Metal - Aluminium
PSet_Revit_Type_Construction - Position: Perpendicular to Face; Corner Mullion: no; Thickness: 0.15 m
PSet_Revit_Type_Constraints - Angle: 0 deg; Offset: 0 m
PSet_Revit_Type_Dimensions - Width on side 2: 0.025 m; Width on side 1: 0.025 m
PSet_Revit_Type_Identity Data - Manufacturer: Manufacturer
PSet_Revit_Type_Other - AccessibilityPerformance: AccessibilityPerformance; CodePerformance: CodePerformance; Color: Color; Constituents: Constituents; Features: Features; Finish: Finish; Grade: Grade; Material: Material; ModelReference: ModelReference; NominalHeight: NominalHeight; NominalLength: NominalLength; NominalWidth: NominalWidth; ProductionYear: ProductionYear; Reference: Reference; Shape: Shape; Size: Size; SustainabilityPerformance: SustainabilityPerformance; WarrantyDescription: WarrantyDescription; WarrantyDurationLabor: WarrantyDurationLabor; WarrantyDurationParts: WarrantyDurationParts; WarrantyGuarantorLabor: WarrantyGuarantorLabor; WarrantyGuarantorParts: WarrantyGuarantorParts; ExpectedLife: ExpectedLife; ReplacementCost: ReplacementCost; AssetAccountingType: FIXED; Classification Code: 23-25 20 14 11 11 11; Classification Description: Curtain Wall Frames; ModelLabel: ModelLabel
Name (Rectangular Mullion:50 x 150mm:50 x 150mm:...) | In | Length (m)
281396 | Second Floor | 1.43604
281397 | Second Floor | 1.43604
281398 | Second Floor | 2.4
281399 | Second Floor | 2.4
281459 | Second Floor | 1.43604
281460 | Second Floor | 1.46104
281461 | Second Floor | 1.46104
281463 | Second Floor | 1.46104
281464 | Second Floor | 1.46104
281465 | Second Floor | 1.43604
281474 | Second Floor | 2.4
281475 | Second Floor | 2.4
281476 | Second Floor | 2.4
281018 | Second Floor | 1.32488
281019 | Second Floor | 1.32488
281020 | Second Floor | 2.4
281021 | Second Floor | 2.4
281055 | Second Floor | 1.32488
281056 | Second Floor | 1.34988
281057 | Second Floor | 1.34988
281058 | Second Floor | 1.34988
281059 | Second Floor | 1.34988
281060 | Second Floor | 1.34988
281061 | Second Floor | 1.34988
281062 | Second Floor | 1.34988
281063 | Second Floor | 1.34988
281064 | Second Floor | 1.34988
281065 | Second Floor | 1.34988
281066 | Second Floor | 1.34988
281067 | Second Floor | 1.34988
281068 | Second Floor | 1.32488
281079 | Second Floor | 2.4
281080 | Second Floor | 2.4
281081 | Second Floor | 2.4
281082 | Second Floor | 2.4
281083 | Second Floor | 2.4
281084 | Second Floor | 2.4
281085 | Second Floor | 2.4
257010 | First Floor | 1
257011 | First Floor | 1
257012 | First Floor | 1.50026
257013 | First Floor | 1.50026
257014 | First Floor | 1
257015 | First Floor | 1.50026
257016 | First Floor | 1.50026
257017 | First Floor | 0.95
257018 | First Floor | 1.585
257019 | First Floor | 1.535
257655 | First Floor | 1.535
257663 | First Floor | 1.535
257667 | First Floor | 1.535
258067 | First Floor | 1
258068 | First Floor | 1
258069 | First Floor | 1.5
258070 | First Floor | 1.5
258071 | First Floor | 1
258072 | First Floor | 1.5
258073 | First Floor | 1.5
258074 | First Floor | 1
258075 | First Floor | 1.535
258076 | First Floor | 1.535
258517 | First Floor | 1.535
258521 | First Floor | 1.535
258525 | First Floor | 1.535
258783 | First Floor | 1.5
258784 | First Floor | 1.5
258785 | First Floor | 1
258787 | First Floor | 1.5
258788 | First Floor | 1
258789 | First Floor | 1.5
258791 | First Floor | 1.535
258792 | First Floor | 1.535
259271 | First Floor | 1.535
259278 | First Floor | 1.535
263371 | First Floor | 0.935
263372 | First Floor | 1.8
263373 | First Floor | 0.935
263374 | First Floor | 2.4
263375 | First Floor | 1.335
263376 | First Floor | 1.20566
263377 | First Floor | 0.04
264729 | First Floor | 1.03657
264730 | First Floor | 1.03657
264731 | First Floor | 1.85629
264748 | First Floor | 0.04
264749 | First Floor | 1.20566
264750 | First Floor | 1.335
264751 | First Floor | 2.4
264752 | First Floor | 0.935
264753 | First Floor | 1.8
264754 | First Floor | 0.935
264758 | First Floor | 0.04
264759 | First Floor | 0.04
265061 | First Floor | 1.335
265062 | First Floor | 2.4
265072 | First Floor | 1.335
265073 | First Floor | 2.4
265080 | First Floor | 1.8
265081 | First Floor | 0.935
265082 | First Floor | 0.935
265135 | First Floor | 1.43393
265151 | First Floor | 1.43393
283076 | First Floor | 0.443999
283077 | First Floor | 0.901001
283078 | First Floor | 2.4
283079 | First Floor | 0.4
283080 | First Floor | 0.4
283081 | First Floor | 2.4
283082 | First Floor | 0.901001
285051 | First Floor | 0.926001
285052 | First Floor | 0.418999
285053 | First Floor | 0.418999
285054 | First Floor | 2.425
283429 | First Floor | 0.815
283430 | First Floor | 0.815
283431 | First Floor | 2.4
283432 | First Floor | 0.4
283433 | First Floor | 0.4
283434 | First Floor | 2.4
283435 | First Floor | 0.815
283664 | First Floor | 1.00167
283665 | First Floor | 1.00167
283666 | First Floor | 1.02667
283667 | First Floor | 1.00167
283668 | First Floor | 1.02667
283669 | First Floor | 1.00167
283670 | First Floor | 2.4
283671 | First Floor | 0.4
283672 | First Floor | 0.4
283673 | First Floor | 2.4
283674 | First Floor | 1.00167
283675 | First Floor | 1.02667
283676 | First Floor | 1.00167
283677 | First Floor | 2.4
283678 | First Floor | 2.4
283679 | First Floor | 0.4
283680 | First Floor | 0.4
283774 | First Floor | 0.815
283775 | First Floor | 0.815
283776 | First Floor | 2.4
283777 | First Floor | 0.4
283778 | First Floor | 0.4
283779 | First Floor | 2.4
283780 | First Floor | 0.815
283890 | First Floor | 0.924549
283891 | First Floor | 0.419999
283892 | First Floor | 2.4
283893 | First Floor | 0.4
283894 | First Floor | 0.4
283895 | First Floor | 2.4
283896 | First Floor | 0.419999
285198 | First Floor | 0.444999
285199 | First Floor | 0.899549
285200 | First Floor | 0.899549
285201 | First Floor | 2.425
284097 | First Floor | 1.00167
284098 | First Floor | 1.00167
284099 | First Floor | 1.02667
284100 | First Floor | 1.00167
284101 | First Floor | 1.02667
284102 | First Floor | 1.00167
284103 | First Floor | 2.4
284104 | First Floor | 0.4
284105 | First Floor | 0.4
284106 | First Floor | 2.4
284107 | First Floor | 1.00167
284108 | First Floor | 1.02667
284109 | First Floor | 1.00167
284110 | First Floor | 2.4
284111 | First Floor | 2.4
284112 | First Floor | 0.4
284113 | First Floor | 0.4
284579 | First Floor | 0.692
284580 | First Floor | 0.692
284581 | First Floor | 0.692
284582 | First Floor | 0.692
284583 | First Floor | 1
284585 | First Floor | 1
284589 | First Floor | 1
286008 | Second Floor | 1.14769
286009 | Second Floor | 1.14769
286010 | Second Floor | 1.17269
286011 | Second Floor | 1.17269
286012 | Second Floor | 1.14769
286013 | Second Floor | 1.17269
286014 | Second Floor | 1.17269
286015 | Second Floor | 1.14769
286016 | Second Floor | 2.4
286018 | Second Floor | 2.4
286024 | Second Floor | 2.4
286025 | Second Floor | 2.4
286026 | Second Floor | 2.4
295611 | Second Floor | 1.64443
295613 | Second Floor | 0.564012
295618 | Second Floor | 1.39548
295619 | Second Floor | 1.39548
295812 | Second Floor | 1.34841
295813 | Second Floor | 1.34841
295814 | Second Floor | 1.29416
310160 | Second Floor | 1.31583
310161 | Second Floor | 1.29192
310162 | Second Floor | 1.31583
314110 | Second Floor | 0.564012
314111 | Second Floor | 1.64443
314112 | Second Floor | 0.940099
314113 | Second Floor | 0.940099
314114 | Second Floor | 1.215
314115 | Second Floor | 1.24
314116 | Second Floor | 1.215
296083 | Second Floor | 1.45915
296085 | Second Floor | 1.44906
296091 | Second Floor | 1.56391
296092 | Second Floor | 1.51
296093 | Second Floor | 1.56239
372105 | Second Floor | 0.442791
372396 | Second Floor | 1.56178
372397 | Second Floor | 1.56366
372398 | Second Floor | 1.47806
372399 | Second Floor | 1.47753
372400 | Second Floor | 1.0614
372401 | Second Floor | 0.422891
372402 | Second Floor | 1.4876
372403 | Second Floor | 1.48668
372404 | Second Floor | 1.08223
298297 | Roof - Main | 1.39764
298299 | Roof - Main | 1.39764
298307 | Roof - Main | 1.6143
298308 | Roof - Main | 1.5344
298309 | Roof - Main | 1.51
298310 | Roof - Main | 1.53359
298311 | Roof - Main | 1.61257
299073 | Roof - Main | 1.42948
299074 | Roof - Main | 1.42948
299075 | Roof - Main | 1.3516
299076 | Roof - Main | 1.31719
299077 | Roof - Main | 1.31719
299078 | Roof - Main | 1.3516
299079 | Roof - Main | 0.552271
299080 | Roof - Main | 0.790245
299081 | Roof - Main | 0.548154
299082 | Roof - Main | 1.37358
299083 | Roof - Main | 1.32005
299084 | Roof - Main | 1.31997
299085 | Roof - Main | 1.37332
299086 | Roof - Main | 0.794709
300172 | Roof - Main | 0.674853
300174 | Roof - Main | 0.996677
300182 | Roof - Main | 0.110376
300183 | Roof - Main | 1.52569
300184 | Roof - Main | 1.51002
300185 | Roof - Main | 1.52569
300186 | Roof - Main | 0.11027
300456 | Roof - Main | 1.42147
300457 | Roof - Main | 1.42149
300458 | Roof - Main | 1.36886
300459 | Roof - Main | 1.34465
300460 | Roof - Main | 1.34465
300461 | Roof - Main | 1.36885
300462 | Roof - Main | 1.45651
300463 | Roof - Main | 0.382837
300464 | Roof - Main | 1.34615
300465 | Roof - Main | 1.34615
300466 | Roof - Main | 0.997578
300467 | Roof - Main | 1.45648
376480 | Roof - Main | 0.997246
376481 | Roof - Main | 0.382492
376482 | Roof - Main | 0.996818
376483 | Roof - Main | 0.675024
376488 | Roof - Main | 1.46544
376489 | Roof - Main | 1.46553
301704 | Roof - Main | 1.2444
301705 | Roof - Main | 1.2694
301706 | Roof - Main | 1.2694
301707 | Roof - Main | 1.2694
301708 | Roof - Main | 1.2694
301709 | Roof - Main | 1.2444
301710 | Roof - Main | 0.986894
301711 | Roof - Main | 1.37115
301712 | Roof - Main | 1.37115
301713 | Roof - Main | 0.986894
301714 | Roof - Main | 1.2444
301715 | Roof - Main | 1.2694
301716 | Roof - Main | 1.2694
301717 | Roof - Main | 1.2694
301718 | Roof - Main | 1.2694
301719 | Roof - Main | 1.2444
301720 | Roof - Main | 0.986894
301721 | Roof - Main | 0.986894
301722 | Roof - Main | 0.986894
301723 | Roof - Main | 0.986894
301724 | Roof - Main | 0.986894
301725 | Roof - Main | 1.41311
301726 | Roof - Main | 1.41311
301727 | Roof - Main | 1.41311
301728 | Roof - Main | 1.41311
301729 | Roof - Main | 1.41311
307730 | Roof - Main | 0.410079
307731 | Roof - Main | 0.671606
307732 | Roof - Main | 0.757291
307733 | Roof - Main | 0.671606
307734 | Roof - Main | 0.410079
307735 | Roof - Main | 1.19324
307736 | Roof - Main | 1.2694
307737 | Roof - Main | 1.2694
307738 | Roof - Main | 1.2694
307739 | Roof - Main | 1.2694
307740 | Roof - Main | 1.19324
308983 | Roof - Main | 0.109513
308984 | Roof - Main | 1.28626
308985 | Roof - Main | 1.34604
308986 | Roof - Main | 1.3231
308987 | Roof - Main | 1.3231
308988 | Roof - Main | 1.34604
309275 | Roof - Main | 0.109513
309276 | Roof - Main | 1.28626
303259 | Roof - Main | 1.22
303260 | Roof - Main | 1.245
303261 | Roof - Main | 1.245
303269 | Roof - Main | 1.22
303270 | Roof - Main | 1.245
303271 | Roof - Main | 1.245
303272 | Roof - Main | 1.22
303283 | Roof - Main | 0.986894
303284 | Roof - Main | 1.22
303285 | Roof - Main | 1.245
303286 | Roof - Main | 1.245
303287 | Roof - Main | 1.22
303295 | Roof - Main | 0.986894
303296 | Roof - Main | 0.986894
303297 | Roof - Main | 0.986894
374707 | Roof - Main | 0.813106
374708 | Roof - Main | 0.813106
374709 | Roof - Main | 0.813106
374710 | Roof - Main | 0.813106
375164 | Roof - Main | 1.22
375223 | Roof - Main | 0.986894
375224 | Roof - Main | 0.813106
303258 | Roof - Main | 1.22167
303267 | Roof - Main | 1.22167
303268 | Roof - Main | 1.24667
303278 | Roof - Main | 1.24667
303279 | Roof - Main | 1.22167
303280 | Roof - Main | 0.986894
303293 | Roof - Main | 1.24667
303294 | Roof - Main | 1.22167
303303 | Roof - Main | 0.986894
303304 | Roof - Main | 0.986894
374706 | Roof - Main | 0.813106
374716 | Roof - Main | 0.813106
374717 | Roof - Main | 0.813106
374941 | Roof - Main | 1.22167
374942 | Roof - Main | 1.22167
375001 | Roof - Main | 0.813106
375002 | Roof - Main | 0.986894
303262 | Roof - Main | 1.306
303263 | Roof - Main | 1.331
303264 | Roof - Main | 1.331
303265 | Roof - Main | 1.331
303273 | Roof - Main | 1.331
303274 | Roof - Main | 1.331
303275 | Roof - Main | 1.331
303276 | Roof - Main | 1.306
303288 | Roof - Main | 1.331
303289 | Roof - Main | 1.331
303290 | Roof - Main | 1.331
303291 | Roof - Main | 1.306
303298 | Roof - Main | 0.986894
303299 | Roof - Main | 0.986894
303300 | Roof - Main | 0.986894
303301 | Roof - Main | 0.986894
374711 | Roof - Main | 0.813106
374712 | Roof - Main | 0.813106
374713 | Roof - Main | 0.813106
374714 | Roof - Main | 0.813106
374940 | Roof - Main | 1.306
374999 | Roof - Main | 0.986894
375000 | Roof - Main | 0.813106
375165 | Roof - Main | 1.306
375166 | Roof - Main | 1.306
375225 | Roof - Main | 0.813106
375226 | Roof - Main | 0.986894
379199 | Second Floor | 1.29887
379200 | Second Floor | 1.29888
379201 | Second Floor | 2.4
379202 | Second Floor | 2.4
379217 | Second Floor | 1.29887
379218 | Second Floor | 1.32388
379219 | Second Floor | 1.32388
379220 | Second Floor | 1.32388
379221 | Second Floor | 1.32388
379222 | Second Floor | 1.32388
379223 | Second Floor | 1.32388
379224 | Second Floor | 1.32388
379225 | Second Floor | 1.32388
379226 | Second Floor | 1.32388
379227 | Second Floor | 1.32388
379228 | Second Floor | 1.32388
379229 | Second Floor | 1.32388
379230 | Second Floor | 1.29888
379231 | Second Floor | 2.4
379232 | Second Floor | 2.4
379233 | Second Floor | 2.4
379234 | Second Floor | 2.4
379235 | Second Floor | 2.4
379236 | Second Floor | 2.4
379237 | Second Floor | 2.4
379247 | Second Floor | 1.14769
379248 | Second Floor | 1.14769
379249 | Second Floor | 1.17269
379250 | Second Floor | 1.17269
379251 | Second Floor | 1.14769
379252 | Second Floor | 1.17269
379253 | Second Floor | 1.17269
379254 | Second Floor | 1.14769
379255 | Second Floor | 2.4
379256 | Second Floor | 2.4
379257 | Second Floor | 2.4
379258 | Second Floor | 2.4
379259 | Second Floor | 2.4
381816 | Roof - Main | 1.39764
381817 | Roof - Main | 1.39764
381818 | Roof - Main | 1.6143
381819 | Roof - Main | 1.5344
381820 | Roof - Main | 1.51
381821 | Roof - Main | 1.53359
381822 | Roof - Main | 1.61257
381845 | Roof - Main | 1.42948
381846 | Roof - Main | 1.42948
381847 | Roof - Main | 1.3516
381848 | Roof - Main | 1.31719
381849 | Roof - Main | 1.31719
381850 | Roof - Main | 1.3516
381851 | Roof - Main | 0.552271
381852 | Roof - Main | 0.790245
381853 | Roof - Main | 0.548154
381854 | Roof - Main | 1.37358
381855 | Roof - Main | 1.32005
381856 | Roof - Main | 1.31997
381857 | Roof - Main | 1.37332
381858 | Roof - Main | 0.794709
381891 | Roof - Main | 1.22
381892 | Roof - Main | 1.245
381893 | Roof - Main | 1.245
381900 | Roof - Main | 1.22
381901 | Roof - Main | 1.245
381902 | Roof - Main | 1.245
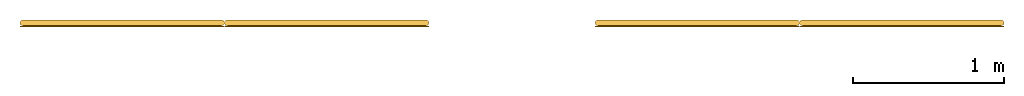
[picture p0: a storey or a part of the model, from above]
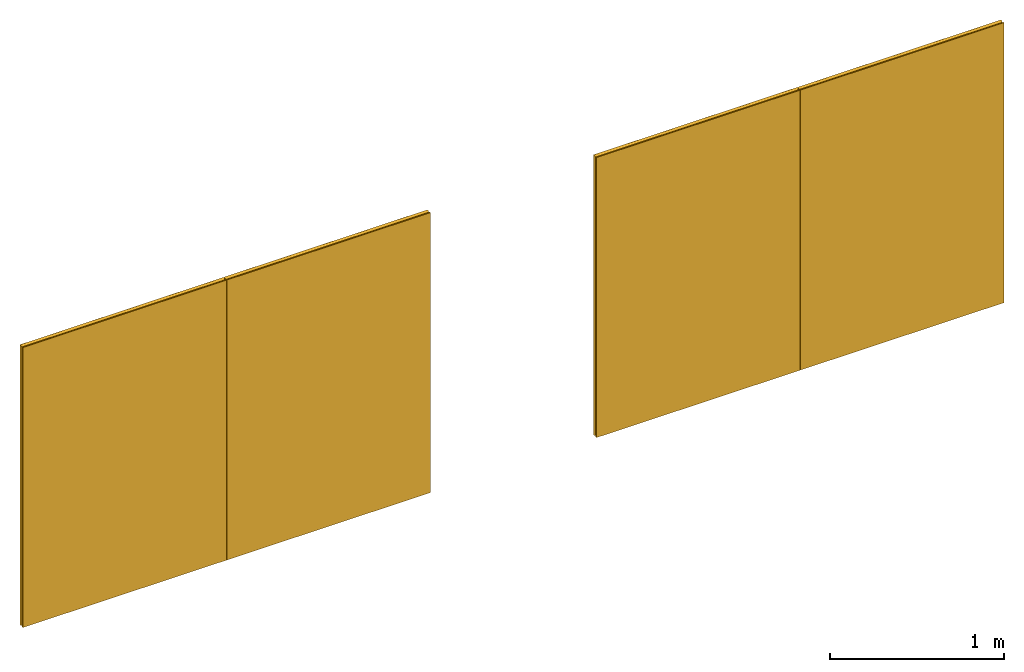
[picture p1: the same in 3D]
Properties of the parts of a building model (IFC2X3), part 5 of 11

# IfcMember: 50 x 150mm (506)
Name (Rectangular Mullion:50 x 150mm:50 x 150mm:...) | In | Length (m)
381903 | Roof - Main | 1.22
381911 | Roof - Main | 0.986894
381912 | Roof - Main | 1.22
381913 | Roof - Main | 1.245
381914 | Roof - Main | 1.245
381915 | Roof - Main | 1.22
381922 | Roof - Main | 0.986894
381923 | Roof - Main | 0.986894
381924 | Roof - Main | 0.986894
381950 | Roof - Main | 0.813106
381951 | Roof - Main | 0.813106
381952 | Roof - Main | 0.813106
381953 | Roof - Main | 0.813106
381973 | Roof - Main | 1.22
381978 | Roof - Main | 0.986894
381979 | Roof - Main | 0.813106
381890 | Roof - Main | 1.22167
381898 | Roof - Main | 1.22167
381899 | Roof - Main | 1.24667
381908 | Roof - Main | 1.24667
381909 | Roof - Main | 1.22167
381910 | Roof - Main | 0.986894
381920 | Roof - Main | 1.24667
381921 | Roof - Main | 1.22167
381929 | Roof - Main | 0.986894
381930 | Roof - Main | 0.986894
381949 | Roof - Main | 0.813106
381958 | Roof - Main | 0.813106
381959 | Roof - Main | 0.813106
381963 | Roof - Main | 1.22167
381964 | Roof - Main | 1.22167
381969 | Roof - Main | 0.813106
381970 | Roof - Main | 0.986894
381894 | Roof - Main | 1.306
381895 | Roof - Main | 1.331
381896 | Roof - Main | 1.331
381897 | Roof - Main | 1.331
381904 | Roof - Main | 1.331
381905 | Roof - Main | 1.331
381906 | Roof - Main | 1.331
381907 | Roof - Main | 1.306
381916 | Roof - Main | 1.331
381917 | Roof - Main | 1.331
381918 | Roof - Main | 1.331
381919 | Roof - Main | 1.306
381925 | Roof - Main | 0.986894
381926 | Roof - Main | 0.986894
381927 | Roof - Main | 0.986894
381928 | Roof - Main | 0.986894
381954 | Roof - Main | 0.813106
381955 | Roof - Main | 0.813106
381956 | Roof - Main | 0.813106
381957 | Roof - Main | 0.813106
381962 | Roof - Main | 1.306
381967 | Roof - Main | 0.986894
381968 | Roof - Main | 0.813106
381974 | Roof - Main | 1.306
381975 | Roof - Main | 1.306
381980 | Roof - Main | 0.813106
381981 | Roof - Main | 0.986894

# IfcOpeningElement: Opening (403)
Name | In
Basic Wall:Exterior - Insul Panel on Mtl. Stud:141152:2 | First Floor | Pset_WallCommon - Reference: Basic Wall:Exterior - Insul Panel on Mtl. Stud; LoadBearing: no; ExtendToStructure: no; IsExternal: yes; PSet_Revit_Constraints - Location Line: 2; Base Constraint: First Floor; Base Offset: 0 m; Base is Attached: no; Base Extension Distance: 0 m; Top Constraint: Up to level: Second Floor; Unconnected Height: 5.027 m; Top Offset: 0.457 m; Top is Attached: no; Top Extension Distance: 0 m; Room Bounding: yes; Related to Mass: no; PSet_Revit_Other - InstallationDate: InstallationDate; SerialNumber: SerialNumber; WarrantyStartDate: WarrantyStartDate; BarCode: BarCode; AssetIdentifier: AssetIdentifier; TagNumber: TagNumber; PSet_Revit_Phasing - Phase Created: New Construction; PSet_Revit_Structural - Structural Usage: 0; PSet_Revit_Dimensions - Length: 32.333 m; Area: 153.657 m2; Volume: 41.0265 m3; PSet_Revit_Type_Construction - Wrapping at Inserts: 0; Wrapping at Ends: 1; Width: 0.267 m; Function: 1; PSet_Revit_Type_Graphics - Coarse Scale Fill Color: 0; PSet_Revit_Type_Identity Data - Manufacturer: Manufacturer; PSet_Revit_Type_Other - AccessibilityPerformance: AccessibilityPerformance; CodePerformance: CodePerformance; Color: Color; Constituents: Constituents; Features: Features; Finish: Finish; Grade: Grade; Material: Material; ModelReference: ModelReference; NominalHeight: NominalHeight; NominalLength: NominalLength; NominalWidth: NominalWidth; ProductionYear: ProductionYear; Reference: Reference; Shape: Shape; Size: Size; SustainabilityPerformance: SustainabilityPerformance; WarrantyDescription: WarrantyDescription; WarrantyDurationLabor: WarrantyDurationLabor; WarrantyDurationParts: WarrantyDurationParts; WarrantyGuarantorLabor: WarrantyGuarantorLabor; WarrantyGuarantorParts: WarrantyGuarantorParts; ExpectedLife: ExpectedLife; ReplacementCost: ReplacementCost; AssetAccountingType: FIXED; Classification Code: 23-25 30 24 21; Classification Description: Metal Framed Structural Walls; ModelLabel: ModelLabel
 | First Floor | Pset_WallCommon - Reference: Basic Wall:Exterior - Insul Panel on Mtl. Stud; LoadBearing: no; ExtendToStructure: no; IsExternal: yes; PSet_Revit_Constraints - Location Line: 2; Base Constraint: First Floor; Base Offset: 0 m; Base is Attached: no; Base Extension Distance: 0 m; Top Constraint: Up to level: Second Floor; Unconnected Height: 4.57 m; Top Offset: 0 m; Top is Attached: no; Top Extension Distance: 0 m; Room Bounding: yes; Related to Mass: no; PSet_Revit_Other - InstallationDate: InstallationDate; SerialNumber: SerialNumber; WarrantyStartDate: WarrantyStartDate; BarCode: BarCode; AssetIdentifier: AssetIdentifier; TagNumber: TagNumber; PSet_Revit_Phasing - Phase Created: New Construction; PSet_Revit_Structural - Structural Usage: 0; PSet_Revit_Dimensions - Length: 13.338 m; Area: 56.4301 m2; Volume: 15.0307 m3; PSet_Revit_Type_Construction - Wrapping at Inserts: 0; Wrapping at Ends: 1; Width: 0.267 m; Function: 1; PSet_Revit_Type_Graphics - Coarse Scale Fill Color: 0; PSet_Revit_Type_Identity Data - Manufacturer: Manufacturer; PSet_Revit_Type_Other - AccessibilityPerformance: AccessibilityPerformance; CodePerformance: CodePerformance; Color: Color; Constituents: Constituents; Features: Features; Finish: Finish; Grade: Grade; Material: Material; ModelReference: ModelReference; NominalHeight: NominalHeight; NominalLength: NominalLength; NominalWidth: NominalWidth; ProductionYear: ProductionYear; Reference: Reference; Shape: Shape; Size: Size; SustainabilityPerformance: SustainabilityPerformance; WarrantyDescription: WarrantyDescription; WarrantyDurationLabor: WarrantyDurationLabor; WarrantyDurationParts: WarrantyDurationParts; WarrantyGuarantorLabor: WarrantyGuarantorLabor; WarrantyGuarantorParts: WarrantyGuarantorParts; ExpectedLife: ExpectedLife; ReplacementCost: ReplacementCost; AssetAccountingType: FIXED; Classification Code: 23-25 30 24 21; Classification Description: Metal Framed Structural Walls; ModelLabel: ModelLabel
Basic Wall:Exterior - Insul Panel on Mtl. Stud:144524:2 | Second Floor | Pset_WallCommon - Reference: Basic Wall:Exterior - Insul Panel on Mtl. Stud; LoadBearing: no; ExtendToStructure: no; IsExternal: yes; PSet_Revit_Constraints - Location Line: 2; Base Constraint: Second Floor; Base Offset: 0 m; Base is Attached: no; Base Extension Distance: 0 m; Top Constraint: Up to level: Roof - Main; Unconnected Height: 5.137 m; Top Offset: 0.457 m; Top is Attached: no; Top Extension Distance: 0 m; Room Bounding: yes; Related to Mass: no; PSet_Revit_Other - InstallationDate: InstallationDate; SerialNumber: SerialNumber; WarrantyStartDate: WarrantyStartDate; BarCode: BarCode; AssetIdentifier: AssetIdentifier; TagNumber: TagNumber; PSet_Revit_Phasing - Phase Created: New Construction; PSet_Revit_Structural - Structural Usage: 0; PSet_Revit_Dimensions - Length: 16.7065 m; Area: 75.4877 m2; Volume: 20.1552 m3; PSet_Revit_Type_Construction - Wrapping at Inserts: 0; Wrapping at Ends: 1; Width: 0.267 m; Function: 1; PSet_Revit_Type_Graphics - Coarse Scale Fill Color: 0; PSet_Revit_Type_Identity Data - Manufacturer: Manufacturer; PSet_Revit_Type_Other - AccessibilityPerformance: AccessibilityPerformance; CodePerformance: CodePerformance; Color: Color; Constituents: Constituents; Features: Features; Finish: Finish; Grade: Grade; Material: Material; ModelReference: ModelReference; NominalHeight: NominalHeight; NominalLength: NominalLength; NominalWidth: NominalWidth; ProductionYear: ProductionYear; Reference: Reference; Shape: Shape; Size: Size; SustainabilityPerformance: SustainabilityPerformance; WarrantyDescription: WarrantyDescription; WarrantyDurationLabor: WarrantyDurationLabor; WarrantyDurationParts: WarrantyDurationParts; WarrantyGuarantorLabor: WarrantyGuarantorLabor; WarrantyGuarantorParts: WarrantyGuarantorParts; ExpectedLife: ExpectedLife; ReplacementCost: ReplacementCost; AssetAccountingType: FIXED; Classification Code: 23-25 30 24 21; Classification Description: Metal Framed Structural Walls; ModelLabel: ModelLabel
Basic Wall:Exterior - Insul Panel on Mtl. Stud:144932:2 | Second Floor | Pset_WallCommon - Reference: Basic Wall:Exterior - Insul Panel on Mtl. Stud; LoadBearing: no; ExtendToStructure: no; IsExternal: yes; PSet_Revit_Constraints - Location Line: 2; Base Constraint: Second Floor; Base Offset: 0 m; Base is Attached: no; Base Extension Distance: 0 m; Top Constraint: Up to level: Roof - Main; Unconnected Height: 5.137 m; Top Offset: 0.457 m; Top is Attached: no; Top Extension Distance: 0 m; Room Bounding: yes; Related to Mass: no; PSet_Revit_Other - InstallationDate: InstallationDate; SerialNumber: SerialNumber; WarrantyStartDate: WarrantyStartDate; BarCode: BarCode; AssetIdentifier: AssetIdentifier; TagNumber: TagNumber; PSet_Revit_Phasing - Phase Created: New Construction; PSet_Revit_Structural - Structural Usage: 0; PSet_Revit_Dimensions - Length: 19.9665 m; Area: 90.8333 m2; Volume: 24.2525 m3; PSet_Revit_Type_Construction - Wrapping at Inserts: 0; Wrapping at Ends: 1; Width: 0.267 m; Function: 1; PSet_Revit_Type_Graphics - Coarse Scale Fill Color: 0; PSet_Revit_Type_Identity Data - Manufacturer: Manufacturer; PSet_Revit_Type_Other - AccessibilityPerformance: AccessibilityPerformance; CodePerformance: CodePerformance; Color: Color; Constituents: Constituents; Features: Features; Finish: Finish; Grade: Grade; Material: Material; ModelReference: ModelReference; NominalHeight: NominalHeight; NominalLength: NominalLength; NominalWidth: NominalWidth; ProductionYear: ProductionYear; Reference: Reference; Shape: Shape; Size: Size; SustainabilityPerformance: SustainabilityPerformance; WarrantyDescription: WarrantyDescription; WarrantyDurationLabor: WarrantyDurationLabor; WarrantyDurationParts: WarrantyDurationParts; WarrantyGuarantorLabor: WarrantyGuarantorLabor; WarrantyGuarantorParts: WarrantyGuarantorParts; ExpectedLife: ExpectedLife; ReplacementCost: ReplacementCost; AssetAccountingType: FIXED; Classification Code: 23-25 30 24 21; Classification Description: Metal Framed Structural Walls; ModelLabel: ModelLabel
 | First Floor | Pset_WallCommon - Reference: Basic Wall:Interior - Partition (92mm Stud); LoadBearing: no; ExtendToStructure: no; IsExternal: no; PSet_Revit_Constraints - Location Line: 3; Base Constraint: First Floor; Base Offset: 0 m; Base is Attached: no; Base Extension Distance: 0 m; Top Constraint: Up to level: Second Floor; Unconnected Height: 4.468 m; Top Offset: -0.102 m; Top is Attached: no; Top Extension Distance: 0 m; Room Bounding: yes; Related to Mass: no; PSet_Revit_Other - InstallationDate: InstallationDate; SerialNumber: SerialNumber; WarrantyStartDate: WarrantyStartDate; BarCode: BarCode; AssetIdentifier: AssetIdentifier; TagNumber: TagNumber; PSet_Revit_Phasing - Phase Created: New Construction; PSet_Revit_Structural - Structural Usage: 0; PSet_Revit_Dimensions - Length: 2.2195 m; Area: 7.09062 m2; Volume: 0.843098 m3; PSet_Revit_Type_Construction - Wrapping at Inserts: 0; Wrapping at Ends: 2; Width: 0.124 m; Function: 0; PSet_Revit_Type_Graphics - Coarse Scale Fill Color: 0; PSet_Revit_Type_Identity Data - Manufacturer: Manufacturer; PSet_Revit_Type_Other - AccessibilityPerformance: AccessibilityPerformance; CodePerformance: CodePerformance; Color: Color; Constituents: Constituents; Features: Features; Finish: Finish; Grade: Grade; Material: Material; ModelReference: ModelReference; NominalHeight: NominalHeight; NominalLength: NominalLength; NominalWidth: NominalWidth; ProductionYear: ProductionYear; Reference: Reference; Shape: Shape; Size: Size; SustainabilityPerformance: SustainabilityPerformance; WarrantyDescription: WarrantyDescription; WarrantyDurationLabor: WarrantyDurationLabor; WarrantyDurationParts: WarrantyDurationParts; WarrantyGuarantorLabor: WarrantyGuarantorLabor; WarrantyGuarantorParts: WarrantyGuarantorParts; ExpectedLife: ExpectedLife; ReplacementCost: ReplacementCost; AssetAccountingType: FIXED; Classification Code: 23-25 40 11 11 11; Classification Description: Metal-Framed Gypsum Board Fixed Partitions; ModelLabel: ModelLabel
 | First Floor | Pset_WallCommon - Reference: Basic Wall:Interior - Partition (92mm Stud); LoadBearing: no; ExtendToStructure: no; IsExternal: no; PSet_Revit_Constraints - Location Line: 2; Base Constraint: First Floor; Base Offset: 0 m; Base is Attached: no; Base Extension Distance: 0 m; Top Constraint: Up to level: Second Floor; Unconnected Height: 4.468 m; Top Offset: -0.102 m; Top is Attached: no; Top Extension Distance: 0 m; Room Bounding: yes; Related to Mass: no; PSet_Revit_Other - InstallationDate: InstallationDate; SerialNumber: SerialNumber; WarrantyStartDate: WarrantyStartDate; BarCode: BarCode; AssetIdentifier: AssetIdentifier; TagNumber: TagNumber; PSet_Revit_Phasing - Phase Created: New Construction; PSet_Revit_Structural - Structural Usage: 0; PSet_Revit_Dimensions - Length: 2.745 m; Area: 11.5542 m2; Volume: 1.39659 m3; PSet_Revit_Type_Construction - Wrapping at Inserts: 0; Wrapping at Ends: 2; Width: 0.124 m; Function: 0; PSet_Revit_Type_Graphics - Coarse Scale Fill Color: 0; PSet_Revit_Type_Identity Data - Manufacturer: Manufacturer; PSet_Revit_Type_Other - AccessibilityPerformance: AccessibilityPerformance; CodePerformance: CodePerformance; Color: Color; Constituents: Constituents; Features: Features; Finish: Finish; Grade: Grade; Material: Material; ModelReference: ModelReference; NominalHeight: NominalHeight; NominalLength: NominalLength; NominalWidth: NominalWidth; ProductionYear: ProductionYear; Reference: Reference; Shape: Shape; Size: Size; SustainabilityPerformance: SustainabilityPerformance; WarrantyDescription: WarrantyDescription; WarrantyDurationLabor: WarrantyDurationLabor; WarrantyDurationParts: WarrantyDurationParts; WarrantyGuarantorLabor: WarrantyGuarantorLabor; WarrantyGuarantorParts: WarrantyGuarantorParts; ExpectedLife: ExpectedLife; ReplacementCost: ReplacementCost; AssetAccountingType: FIXED; Classification Code: 23-25 40 11 11 11; Classification Description: Metal-Framed Gypsum Board Fixed Partitions; ModelLabel: ModelLabel
 | First Floor | Pset_WallCommon - Reference: Basic Wall:Interior - Partition (92mm Stud); LoadBearing: no; ExtendToStructure: no; IsExternal: no; PSet_Revit_Constraints - Location Line: 2; Base Constraint: First Floor; Base Offset: 0 m; Base is Attached: no; Base Extension Distance: 0 m; Top Constraint: Up to level: Second Floor; Unconnected Height: 4.468 m; Top Offset: -0.102 m; Top is Attached: no; Top Extension Distance: 0 m; Room Bounding: yes; Related to Mass: no; PSet_Revit_Other - InstallationDate: InstallationDate; SerialNumber: SerialNumber; WarrantyStartDate: WarrantyStartDate; BarCode: BarCode; AssetIdentifier: AssetIdentifier; TagNumber: TagNumber; PSet_Revit_Phasing - Phase Created: New Construction; PSet_Revit_Structural - Structural Usage: 0; PSet_Revit_Dimensions - Length: 12.344 m; Area: 49.2952 m2; Volume: 6.07646 m3; PSet_Revit_Type_Construction - Wrapping at Inserts: 0; Wrapping at Ends: 2; Width: 0.124 m; Function: 0; PSet_Revit_Type_Graphics - Coarse Scale Fill Color: 0; PSet_Revit_Type_Identity Data - Manufacturer: Manufacturer; PSet_Revit_Type_Other - AccessibilityPerformance: AccessibilityPerformance; CodePerformance: CodePerformance; Color: Color; Constituents: Constituents; Features: Features; Finish: Finish; Grade: Grade; Material: Material; ModelReference: ModelReference; NominalHeight: NominalHeight; NominalLength: NominalLength; NominalWidth: NominalWidth; ProductionYear: ProductionYear; Reference: Reference; Shape: Shape; Size: Size; SustainabilityPerformance: SustainabilityPerformance; WarrantyDescription: WarrantyDescription; WarrantyDurationLabor: WarrantyDurationLabor; WarrantyDurationParts: WarrantyDurationParts; WarrantyGuarantorLabor: WarrantyGuarantorLabor; WarrantyGuarantorParts: WarrantyGuarantorParts; ExpectedLife: ExpectedLife; ReplacementCost: ReplacementCost; AssetAccountingType: FIXED; Classification Code: 23-25 40 11 11 11; Classification Description: Metal-Framed Gypsum Board Fixed Partitions; ModelLabel: ModelLabel
 | First Floor | Pset_WallCommon - Reference: Basic Wall:Interior - Partition (92mm Stud); LoadBearing: no; ExtendToStructure: no; IsExternal: no; PSet_Revit_Constraints - Location Line: 2; Base Constraint: First Floor; Base Offset: 0 m; Base is Attached: no; Base Extension Distance: 0 m; Top Constraint: Up to level: Second Floor; Unconnected Height: 4.468 m; Top Offset: -0.102 m; Top is Attached: no; Top Extension Distance: 0 m; Room Bounding: yes; Related to Mass: no; PSet_Revit_Other - InstallationDate: InstallationDate; SerialNumber: SerialNumber; WarrantyStartDate: WarrantyStartDate; BarCode: BarCode; AssetIdentifier: AssetIdentifier; TagNumber: TagNumber; PSet_Revit_Phasing - Phase Created: New Construction; PSet_Revit_Structural - Structural Usage: 0; PSet_Revit_Dimensions - Length: 3.174 m; Area: 12.0934 m2; Volume: 1.49958 m3; PSet_Revit_Type_Construction - Wrapping at Inserts: 0; Wrapping at Ends: 2; Width: 0.124 m; Function: 0; PSet_Revit_Type_Graphics - Coarse Scale Fill Color: 0; PSet_Revit_Type_Identity Data - Manufacturer: Manufacturer; PSet_Revit_Type_Other - AccessibilityPerformance: AccessibilityPerformance; CodePerformance: CodePerformance; Color: Color; Constituents: Constituents; Features: Features; Finish: Finish; Grade: Grade; Material: Material; ModelReference: ModelReference; NominalHeight: NominalHeight; NominalLength: NominalLength; NominalWidth: NominalWidth; ProductionYear: ProductionYear; Reference: Reference; Shape: Shape; Size: Size; SustainabilityPerformance: SustainabilityPerformance; WarrantyDescription: WarrantyDescription; WarrantyDurationLabor: WarrantyDurationLabor; WarrantyDurationParts: WarrantyDurationParts; WarrantyGuarantorLabor: WarrantyGuarantorLabor; WarrantyGuarantorParts: WarrantyGuarantorParts; ExpectedLife: ExpectedLife; ReplacementCost: ReplacementCost; AssetAccountingType: FIXED; Classification Code: 23-25 40 11 11 11; Classification Description: Metal-Framed Gypsum Board Fixed Partitions; ModelLabel: ModelLabel
 | First Floor | Pset_WallCommon - Reference: Basic Wall:Interior - Plumbing (152mm Stud); LoadBearing: no; ExtendToStructure: no; IsExternal: no; PSet_Revit_Constraints - Location Line: 2; Base Constraint: First Floor; Base Offset: 0 m; Base is Attached: no; Base Extension Distance: 0 m; Top Constraint: Up to level: Second Floor; Unconnected Height: 4.468 m; Top Offset: -0.102 m; Top is Attached: no; Top Extension Distance: 0 m; Room Bounding: yes; Related to Mass: no; PSet_Revit_Other - InstallationDate: InstallationDate; SerialNumber: SerialNumber; WarrantyStartDate: WarrantyStartDate; BarCode: BarCode; AssetIdentifier: AssetIdentifier; TagNumber: TagNumber; PSet_Revit_Phasing - Phase Created: New Construction; PSet_Revit_Structural - Structural Usage: 0; PSet_Revit_Dimensions - Length: 2.756 m; Area: 11.7598 m2; Volume: 2.12766 m3; PSet_Revit_Type_Construction - Wrapping at Inserts: 0; Wrapping at Ends: 2; Width: 0.184 m; Function: 0; PSet_Revit_Type_Graphics - Coarse Scale Fill Color: 0; PSet_Revit_Type_Identity Data - Manufacturer: Manufacturer; PSet_Revit_Type_Other - AccessibilityPerformance: AccessibilityPerformance; CodePerformance: CodePerformance; Color: Color; Constituents: Constituents; Features: Features; Finish: Finish; Grade: Grade; Material: Material; ModelReference: ModelReference; NominalHeight: NominalHeight; NominalLength: NominalLength; NominalWidth: NominalWidth; ProductionYear: ProductionYear; Reference: Reference; Shape: Shape; Size: Size; SustainabilityPerformance: SustainabilityPerformance; WarrantyDescription: WarrantyDescription; WarrantyDurationLabor: WarrantyDurationLabor; WarrantyDurationParts: WarrantyDurationParts; WarrantyGuarantorLabor: WarrantyGuarantorLabor; WarrantyGuarantorParts: WarrantyGuarantorParts; ExpectedLife: ExpectedLife; ReplacementCost: ReplacementCost; AssetAccountingType: FIXED; Classification Code: 23-25 40 11 11 11; Classification Description: Metal-Framed Gypsum Board Fixed Partitions; ModelLabel: ModelLabel
 | First Floor | Pset_WallCommon - Reference: Basic Wall:Interior - Partition (92mm Stud); LoadBearing: no; ExtendToStructure: no; IsExternal: no; PSet_Revit_Constraints - Location Line: 2; Base Constraint: First Floor; Base Offset: 0 m; Base is Attached: no; Base Extension Distance: 0 m; Top Constraint: Up to level: Second Floor; Unconnected Height: 4.468 m; Top Offset: -0.102 m; Top is Attached: no; Top Extension Distance: 0 m; Room Bounding: yes; Related to Mass: no; PSet_Revit_Other - InstallationDate: InstallationDate; SerialNumber: SerialNumber; WarrantyStartDate: WarrantyStartDate; BarCode: BarCode; AssetIdentifier: AssetIdentifier; TagNumber: TagNumber; PSet_Revit_Phasing - Phase Created: New Construction; PSet_Revit_Structural - Structural Usage: 0; PSet_Revit_Dimensions - Length: 18.766 m; Area: 71.7699 m2; Volume: 8.89946 m3; PSet_Revit_Type_Construction - Wrapping at Inserts: 0; Wrapping at Ends: 2; Width: 0.124 m; Function: 0; PSet_Revit_Type_Graphics - Coarse Scale Fill Color: 0; PSet_Revit_Type_Identity Data - Manufacturer: Manufacturer; PSet_Revit_Type_Other - AccessibilityPerformance: AccessibilityPerformance; CodePerformance: CodePerformance; Color: Color; Constituents: Constituents; Features: Features; Finish: Finish; Grade: Grade; Material: Material; ModelReference: ModelReference; NominalHeight: NominalHeight; NominalLength: NominalLength; NominalWidth: NominalWidth; ProductionYear: ProductionYear; Reference: Reference; Shape: Shape; Size: Size; SustainabilityPerformance: SustainabilityPerformance; WarrantyDescription: WarrantyDescription; WarrantyDurationLabor: WarrantyDurationLabor; WarrantyDurationParts: WarrantyDurationParts; WarrantyGuarantorLabor: WarrantyGuarantorLabor; WarrantyGuarantorParts: WarrantyGuarantorParts; ExpectedLife: ExpectedLife; ReplacementCost: ReplacementCost; AssetAccountingType: FIXED; Classification Code: 23-25 40 11 11 11; Classification Description: Metal-Framed Gypsum Board Fixed Partitions; ModelLabel: ModelLabel
2 x  | First Floor | Pset_WallCommon - Reference: Basic Wall:Interior - Furring (152 mm Stud); LoadBearing: no; ExtendToStructure: no; IsExternal: no; PSet_Revit_Constraints - Location Line: 0; Base Constraint: First Floor; Base Offset: 0 m; Base is Attached: no; Base Extension Distance: 0 m; Top Constraint: Up to level: Second Floor; Unconnected Height: 4.468 m; Top Offset: -0.102 m; Top is Attached: no; Top Extension Distance: 0 m; Room Bounding: yes; Related to Mass: no; PSet_Revit_Other - InstallationDate: InstallationDate; SerialNumber: SerialNumber; WarrantyStartDate: WarrantyStartDate; BarCode: BarCode; AssetIdentifier: AssetIdentifier; TagNumber: TagNumber; PSet_Revit_Phasing - Phase Created: New Construction; PSet_Revit_Structural - Structural Usage: 0; PSet_Revit_Dimensions - Length: 2.786 m; Area: 11.8938 m2; Volume: 1.96202 m3; PSet_Revit_Type_Construction - Wrapping at Inserts: 0; Wrapping at Ends: 0; Width: 0.168 m; Function: 0; PSet_Revit_Type_Graphics - Coarse Scale Fill Color: 0; PSet_Revit_Type_Identity Data - Manufacturer: Manufacturer; PSet_Revit_Type_Other - AccessibilityPerformance: AccessibilityPerformance; CodePerformance: CodePerformance; Color: Color; Constituents: Constituents; Features: Features; Finish: Finish; Grade: Grade; Material: Material; ModelReference: ModelReference; NominalHeight: NominalHeight; NominalLength: NominalLength; NominalWidth: NominalWidth; ProductionYear: ProductionYear; Reference: Reference; Shape: Shape; Size: Size; SustainabilityPerformance: SustainabilityPerformance; WarrantyDescription: WarrantyDescription; WarrantyDurationLabor: WarrantyDurationLabor; WarrantyDurationParts: WarrantyDurationParts; WarrantyGuarantorLabor: WarrantyGuarantorLabor; WarrantyGuarantorParts: WarrantyGuarantorParts; ExpectedLife: ExpectedLife; ReplacementCost: ReplacementCost; AssetAccountingType: FIXED; Classification Code: 23-25 40 11 11 11; Classification Description: Metal-Framed Gypsum Board Fixed Partitions; ModelLabel: ModelLabel
 | First Floor | Pset_WallCommon - Reference: Basic Wall:Interior - Partition (92mm Stud); LoadBearing: no; ExtendToStructure: no; IsExternal: no; PSet_Revit_Constraints - Location Line: 2; Base Constraint: First Floor; Base Offset: 0 m; Base is Attached: no; Base Extension Distance: 0 m; Top Constraint: Up to level: Second Floor; Unconnected Height: 4.468 m; Top Offset: -0.102 m; Top is Attached: no; Top Extension Distance: 0 m; Room Bounding: yes; Related to Mass: no; PSet_Revit_Other - InstallationDate: InstallationDate; SerialNumber: SerialNumber; WarrantyStartDate: WarrantyStartDate; BarCode: BarCode; AssetIdentifier: AssetIdentifier; TagNumber: TagNumber; PSet_Revit_Phasing - Phase Created: New Construction; PSet_Revit_Structural - Structural Usage: 0; PSet_Revit_Dimensions - Length: 7.326 m; Area: 30.78 m2; Volume: 3.78058 m3; PSet_Revit_Type_Construction - Wrapping at Inserts: 0; Wrapping at Ends: 2; Width: 0.124 m; Function: 0; PSet_Revit_Type_Graphics - Coarse Scale Fill Color: 0; PSet_Revit_Type_Identity Data - Manufacturer: Manufacturer; PSet_Revit_Type_Other - AccessibilityPerformance: AccessibilityPerformance; CodePerformance: CodePerformance; Color: Color; Constituents: Constituents; Features: Features; Finish: Finish; Grade: Grade; Material: Material; ModelReference: ModelReference; NominalHeight: NominalHeight; NominalLength: NominalLength; NominalWidth: NominalWidth; ProductionYear: ProductionYear; Reference: Reference; Shape: Shape; Size: Size; SustainabilityPerformance: SustainabilityPerformance; WarrantyDescription: WarrantyDescription; WarrantyDurationLabor: WarrantyDurationLabor; WarrantyDurationParts: WarrantyDurationParts; WarrantyGuarantorLabor: WarrantyGuarantorLabor; WarrantyGuarantorParts: WarrantyGuarantorParts; ExpectedLife: ExpectedLife; ReplacementCost: ReplacementCost; AssetAccountingType: FIXED; Classification Code: 23-25 40 11 11 11; Classification Description: Metal-Framed Gypsum Board Fixed Partitions; ModelLabel: ModelLabel
 | First Floor | Pset_WallCommon - Reference: Basic Wall:Interior - Partition (92mm Stud); LoadBearing: no; ExtendToStructure: no; IsExternal: no; PSet_Revit_Constraints - Location Line: 2; Base Constraint: First Floor; Base Offset: 0 m; Base is Attached: no; Base Extension Distance: 0 m; Top Constraint: Up to level: Second Floor; Unconnected Height: 4.57 m; Top Offset: 0 m; Top is Attached: no; Top Extension Distance: 0 m; Room Bounding: yes; Related to Mass: no; PSet_Revit_Other - InstallationDate: InstallationDate; SerialNumber: SerialNumber; WarrantyStartDate: WarrantyStartDate; BarCode: BarCode; AssetIdentifier: AssetIdentifier; TagNumber: TagNumber; PSet_Revit_Phasing - Phase Created: New Construction; PSet_Revit_Structural - Structural Usage: 0; PSet_Revit_Dimensions - Length: 6.945 m; Area: 27.9934 m2; Volume: 3.43504 m3; PSet_Revit_Type_Construction - Wrapping at Inserts: 0; Wrapping at Ends: 2; Width: 0.124 m; Function: 0; PSet_Revit_Type_Graphics - Coarse Scale Fill Color: 0; PSet_Revit_Type_Identity Data - Manufacturer: Manufacturer; PSet_Revit_Type_Other - AccessibilityPerformance: AccessibilityPerformance; CodePerformance: CodePerformance; Color: Color; Constituents: Constituents; Features: Features; Finish: Finish; Grade: Grade; Material: Material; ModelReference: ModelReference; NominalHeight: NominalHeight; NominalLength: NominalLength; NominalWidth: NominalWidth; ProductionYear: ProductionYear; Reference: Reference; Shape: Shape; Size: Size; SustainabilityPerformance: SustainabilityPerformance; WarrantyDescription: WarrantyDescription; WarrantyDurationLabor: WarrantyDurationLabor; WarrantyDurationParts: WarrantyDurationParts; WarrantyGuarantorLabor: WarrantyGuarantorLabor; WarrantyGuarantorParts: WarrantyGuarantorParts; ExpectedLife: ExpectedLife; ReplacementCost: ReplacementCost; AssetAccountingType: FIXED; Classification Code: 23-25 40 11 11 11; Classification Description: Metal-Framed Gypsum Board Fixed Partitions; ModelLabel: ModelLabel
 | First Floor | Pset_WallCommon - Reference: Basic Wall:Interior - Furring (38 mm Stud); LoadBearing: no; ExtendToStructure: no; IsExternal: no; PSet_Revit_Constraints - Location Line: 0; Base Constraint: First Floor; Base Offset: 0 m; Base is Attached: no; Base Extension Distance: 0 m; Top Constraint: Up to level: Second Floor; Unconnected Height: 4.468 m; Top Offset: -0.102 m; Top is Attached: no; Top Extension Distance: 0 m; Room Bounding: yes; Related to Mass: no; PSet_Revit_Other - InstallationDate: InstallationDate; SerialNumber: SerialNumber; WarrantyStartDate: WarrantyStartDate; BarCode: BarCode; AssetIdentifier: AssetIdentifier; TagNumber: TagNumber; PSet_Revit_Phasing - Phase Created: New Construction; PSet_Revit_Structural - Structural Usage: 0; PSet_Revit_Dimensions - Length: 4.446 m; Area: 19.4582 m2; Volume: 1.05074 m3; PSet_Revit_Type_Construction - Wrapping at Inserts: 0; Wrapping at Ends: 0; Width: 0.054 m; Function: 0; PSet_Revit_Type_Graphics - Coarse Scale Fill Color: 0; PSet_Revit_Type_Identity Data - Manufacturer: Manufacturer; PSet_Revit_Type_Other - AccessibilityPerformance: AccessibilityPerformance; CodePerformance: CodePerformance; Color: Color; Constituents: Constituents; Features: Features; Finish: Finish; Grade: Grade; Material: Material; ModelReference: ModelReference; NominalHeight: NominalHeight; NominalLength: NominalLength; NominalWidth: NominalWidth; ProductionYear: ProductionYear; Reference: Reference; Shape: Shape; Size: Size; SustainabilityPerformance: SustainabilityPerformance; WarrantyDescription: WarrantyDescription; WarrantyDurationLabor: WarrantyDurationLabor; WarrantyDurationParts: WarrantyDurationParts; WarrantyGuarantorLabor: WarrantyGuarantorLabor; WarrantyGuarantorParts: WarrantyGuarantorParts; ExpectedLife: ExpectedLife; ReplacementCost: ReplacementCost; AssetAccountingType: FIXED; Classification Code: 23-25 40 11 11 11; Classification Description: Metal-Framed Gypsum Board Fixed Partitions; ModelLabel: ModelLabel
 | First Floor | Pset_WallCommon - Reference: Basic Wall:Interior - Partition (92mm Stud); LoadBearing: no; ExtendToStructure: no; IsExternal: no; PSet_Revit_Constraints - Location Line: 2; Base Constraint: First Floor; Base Offset: 0 m; Base is Attached: no; Base Extension Distance: 0 m; Top Constraint: Up to level: Second Floor; Unconnected Height: 4.468 m; Top Offset: -0.102 m; Top is Attached: no; Top Extension Distance: 0 m; Room Bounding: yes; Related to Mass: no; PSet_Revit_Other - InstallationDate: InstallationDate; SerialNumber: SerialNumber; WarrantyStartDate: WarrantyStartDate; BarCode: BarCode; AssetIdentifier: AssetIdentifier; TagNumber: TagNumber; PSet_Revit_Phasing - Phase Created: New Construction; PSet_Revit_Structural - Structural Usage: 0; PSet_Revit_Dimensions - Length: 2.714 m; Area: 10.2718 m2; Volume: 1.23757 m3; PSet_Revit_Type_Construction - Wrapping at Inserts: 0; Wrapping at Ends: 2; Width: 0.124 m; Function: 0; PSet_Revit_Type_Graphics - Coarse Scale Fill Color: 0; PSet_Revit_Type_Identity Data - Manufacturer: Manufacturer; PSet_Revit_Type_Other - AccessibilityPerformance: AccessibilityPerformance; CodePerformance: CodePerformance; Color: Color; Constituents: Constituents; Features: Features; Finish: Finish; Grade: Grade; Material: Material; ModelReference: ModelReference; NominalHeight: NominalHeight; NominalLength: NominalLength; NominalWidth: NominalWidth; ProductionYear: ProductionYear; Reference: Reference; Shape: Shape; Size: Size; SustainabilityPerformance: SustainabilityPerformance; WarrantyDescription: WarrantyDescription; WarrantyDurationLabor: WarrantyDurationLabor; WarrantyDurationParts: WarrantyDurationParts; WarrantyGuarantorLabor: WarrantyGuarantorLabor; WarrantyGuarantorParts: WarrantyGuarantorParts; ExpectedLife: ExpectedLife; ReplacementCost: ReplacementCost; AssetAccountingType: FIXED; Classification Code: 23-25 40 11 11 11; Classification Description: Metal-Framed Gypsum Board Fixed Partitions; ModelLabel: ModelLabel
 | First Floor | Pset_WallCommon - Reference: Basic Wall:Interior - Partition (92mm Stud); LoadBearing: no; ExtendToStructure: no; IsExternal: no; PSet_Revit_Constraints - Location Line: 2; Base Constraint: First Floor; Base Offset: 0 m; Base is Attached: no; Base Extension Distance: 0 m; Top Constraint: Up to level: Second Floor; Unconnected Height: 4.468 m; Top Offset: -0.102 m; Top is Attached: no; Top Extension Distance: 0 m; Room Bounding: yes; Related to Mass: no; PSet_Revit_Other - InstallationDate: InstallationDate; SerialNumber: SerialNumber; WarrantyStartDate: WarrantyStartDate; BarCode: BarCode; AssetIdentifier: AssetIdentifier; TagNumber: TagNumber; PSet_Revit_Phasing - Phase Created: New Construction; PSet_Revit_Structural - Structural Usage: 0; PSet_Revit_Dimensions - Length: 2.736 m; Area: 11.6704 m2; Volume: 1.41099 m3; PSet_Revit_Type_Construction - Wrapping at Inserts: 0; Wrapping at Ends: 2; Width: 0.124 m; Function: 0; PSet_Revit_Type_Graphics - Coarse Scale Fill Color: 0; PSet_Revit_Type_Identity Data - Manufacturer: Manufacturer; PSet_Revit_Type_Other - AccessibilityPerformance: AccessibilityPerformance; CodePerformance: CodePerformance; Color: Color; Constituents: Constituents; Features: Features; Finish: Finish; Grade: Grade; Material: Material; ModelReference: ModelReference; NominalHeight: NominalHeight; NominalLength: NominalLength; NominalWidth: NominalWidth; ProductionYear: ProductionYear; Reference: Reference; Shape: Shape; Size: Size; SustainabilityPerformance: SustainabilityPerformance; WarrantyDescription: WarrantyDescription; WarrantyDurationLabor: WarrantyDurationLabor; WarrantyDurationParts: WarrantyDurationParts; WarrantyGuarantorLabor: WarrantyGuarantorLabor; WarrantyGuarantorParts: WarrantyGuarantorParts; ExpectedLife: ExpectedLife; ReplacementCost: ReplacementCost; AssetAccountingType: FIXED; Classification Code: 23-25 40 11 11 11; Classification Description: Metal-Framed Gypsum Board Fixed Partitions; ModelLabel: ModelLabel
Basic Wall:Interior - Rated 1-HR (92mm Stud):182976:2 | First Floor | Pset_WallCommon - Reference: Basic Wall:Interior - Rated 1-HR (92mm Stud); LoadBearing: no; ExtendToStructure: no; IsExternal: no; FireRating: 1 HR; PSet_Revit_Constraints - Location Line: 2; Base Constraint: First Floor; Base Offset: 0 m; Base is Attached: no; Base Extension Distance: 0 m; Top Constraint: Up to level: Second Floor; Unconnected Height: 4.468 m; Top Offset: -0.102 m; Top is Attached: no; Top Extension Distance: 0 m; Room Bounding: yes; Related to Mass: no; PSet_Revit_Other - InstallationDate: InstallationDate; SerialNumber: SerialNumber; WarrantyStartDate: WarrantyStartDate; BarCode: BarCode; AssetIdentifier: AssetIdentifier; TagNumber: TagNumber; PSet_Revit_Phasing - Phase Created: New Construction; PSet_Revit_Structural - Structural Usage: 0; PSet_Revit_Dimensions - Length: 2.3692 m; Area: 8.63426 m2; Volume: 1.07065 m3; PSet_Revit_Type_Construction - Wrapping at Inserts: 0; Wrapping at Ends: 0; Width: 0.124 m; Function: 0; PSet_Revit_Type_Graphics - Coarse Scale Fill Color: 8421504; Coarse Scale Fill Pattern: Solid fill; PSet_Revit_Type_Identity Data - Manufacturer: Manufacturer; Fire Rating: 1 HR; PSet_Revit_Type_Other - AccessibilityPerformance: AccessibilityPerformance; CodePerformance: CodePerformance; Color: Color; Constituents: Constituents; Features: Features; Finish: Finish; Grade: Grade; Material: Material; ModelReference: ModelReference; NominalHeight: NominalHeight; NominalLength: NominalLength; NominalWidth: NominalWidth; ProductionYear: ProductionYear; Reference: Reference; Shape: Shape; Size: Size; SustainabilityPerformance: SustainabilityPerformance; WarrantyDescription: WarrantyDescription; WarrantyDurationLabor: WarrantyDurationLabor; WarrantyDurationParts: WarrantyDurationParts; WarrantyGuarantorLabor: WarrantyGuarantorLabor; WarrantyGuarantorParts: WarrantyGuarantorParts; ExpectedLife: ExpectedLife; ReplacementCost: ReplacementCost; AssetAccountingType: FIXED; Classification Code: 23-25 40 11 11 11; Classification Description: Metal-Framed Gypsum Board Fixed Partitions; ModelLabel: ModelLabel
Basic Wall:Interior - Furring (152 mm Stud):184583:2 | First Floor | Pset_WallCommon - Reference: Basic Wall:Interior - Furring (152 mm Stud); LoadBearing: no; ExtendToStructure: no; IsExternal: no; PSet_Revit_Constraints - Location Line: 3; Base Constraint: First Floor; Base Offset: 0 m; Base is Attached: no; Base Extension Distance: 0 m; Top Constraint: Up to level: Second Floor; Unconnected Height: 4.468 m; Top Offset: -0.102 m; Top is Attached: no; Top Extension Distance: 0 m; Room Bounding: yes; Related to Mass: no; PSet_Revit_Other - InstallationDate: InstallationDate; SerialNumber: SerialNumber; WarrantyStartDate: WarrantyStartDate; BarCode: BarCode; AssetIdentifier: AssetIdentifier; TagNumber: TagNumber; PSet_Revit_Phasing - Phase Created: New Construction; PSet_Revit_Structural - Structural Usage: 0; PSet_Revit_Dimensions - Length: 9.15715 m; Area: 25.9775 m2; Volume: 4.36421 m3; PSet_Revit_Type_Construction - Wrapping at Inserts: 0; Wrapping at Ends: 0; Width: 0.168 m; Function: 0; PSet_Revit_Type_Graphics - Coarse Scale Fill Color: 0; PSet_Revit_Type_Identity Data - Manufacturer: Manufacturer; PSet_Revit_Type_Other - AccessibilityPerformance: AccessibilityPerformance; CodePerformance: CodePerformance; Color: Color; Constituents: Constituents; Features: Features; Finish: Finish; Grade: Grade; Material: Material; ModelReference: ModelReference; NominalHeight: NominalHeight; NominalLength: NominalLength; NominalWidth: NominalWidth; ProductionYear: ProductionYear; Reference: Reference; Shape: Shape; Size: Size; SustainabilityPerformance: SustainabilityPerformance; WarrantyDescription: WarrantyDescription; WarrantyDurationLabor: WarrantyDurationLabor; WarrantyDurationParts: WarrantyDurationParts; WarrantyGuarantorLabor: WarrantyGuarantorLabor; WarrantyGuarantorParts: WarrantyGuarantorParts; ExpectedLife: ExpectedLife; ReplacementCost: ReplacementCost; AssetAccountingType: FIXED; Classification Code: 23-25 40 11 11 11; Classification Description: Metal-Framed Gypsum Board Fixed Partitions; ModelLabel: ModelLabel
Basic Wall:Interior - Partition (92mm Stud):196610:2 | Second Floor | Pset_WallCommon - Reference: Basic Wall:Interior - Partition (92mm Stud); LoadBearing: no; ExtendToStructure: no; IsExternal: no; PSet_Revit_Constraints - Location Line: 2; Base Constraint: Second Floor; Base Offset: 0 m; Base is Attached: no; Base Extension Distance: 0 m; Top Constraint: Up to level: Roof - Main; Unconnected Height: 4.38 m; Top Offset: -0.3 m; Top is Attached: no; Top Extension Distance: 0 m; Room Bounding: yes; Related to Mass: no; PSet_Revit_Other - InstallationDate: InstallationDate; SerialNumber: SerialNumber; WarrantyStartDate: WarrantyStartDate; BarCode: BarCode; AssetIdentifier: AssetIdentifier; TagNumber: TagNumber; PSet_Revit_Phasing - Phase Created: New Construction; PSet_Revit_Structural - Structural Usage: 0; PSet_Revit_Dimensions - Length: 7.96064 m; Area: 31.4877 m2; Volume: 3.90447 m3; PSet_Revit_Type_Construction - Wrapping at Inserts: 0; Wrapping at Ends: 2; Width: 0.124 m; Function: 0; PSet_Revit_Type_Graphics - Coarse Scale Fill Color: 0; PSet_Revit_Type_Identity Data - Manufacturer: Manufacturer; PSet_Revit_Type_Other - AccessibilityPerformance: AccessibilityPerformance; CodePerformance: CodePerformance; Color: Color; Constituents: Constituents; Features: Features; Finish: Finish; Grade: Grade; Material: Material; ModelReference: ModelReference; NominalHeight: NominalHeight; NominalLength: NominalLength; NominalWidth: NominalWidth; ProductionYear: ProductionYear; Reference: Reference; Shape: Shape; Size: Size; SustainabilityPerformance: SustainabilityPerformance; WarrantyDescription: WarrantyDescription; WarrantyDurationLabor: WarrantyDurationLabor; WarrantyDurationParts: WarrantyDurationParts; WarrantyGuarantorLabor: WarrantyGuarantorLabor; WarrantyGuarantorParts: WarrantyGuarantorParts; ExpectedLife: ExpectedLife; ReplacementCost: ReplacementCost; AssetAccountingType: FIXED; Classification Code: 23-25 40 11 11 11; Classification Description: Metal-Framed Gypsum Board Fixed Partitions; ModelLabel: ModelLabel
Basic Wall:Interior - Partition (92mm Stud):198188:2 | Second Floor | Pset_WallCommon - Reference: Basic Wall:Interior - Partition (92mm Stud); LoadBearing: no; ExtendToStructure: no; IsExternal: no; PSet_Revit_Constraints - Location Line: 2; Base Constraint: Second Floor; Base Offset: 0 m; Base is Attached: no; Base Extension Distance: 0 m; Top Constraint: Up to level: Roof - Main; Unconnected Height: 4.578 m; Top Offset: -0.102 m; Top is Attached: no; Top Extension Distance: 0 m; Room Bounding: yes; Related to Mass: no; PSet_Revit_Other - InstallationDate: InstallationDate; SerialNumber: SerialNumber; WarrantyStartDate: WarrantyStartDate; BarCode: BarCode; AssetIdentifier: AssetIdentifier; TagNumber: TagNumber; PSet_Revit_Phasing - Phase Created: New Construction; PSet_Revit_Structural - Structural Usage: 0; PSet_Revit_Dimensions - Length: 3.37317 m; Area: 13.87 m2; Volume: 1.71988 m3; PSet_Revit_Type_Construction - Wrapping at Inserts: 0; Wrapping at Ends: 2; Width: 0.124 m; Function: 0; PSet_Revit_Type_Graphics - Coarse Scale Fill Color: 0; PSet_Revit_Type_Identity Data - Manufacturer: Manufacturer; PSet_Revit_Type_Other - AccessibilityPerformance: AccessibilityPerformance; CodePerformance: CodePerformance; Color: Color; Constituents: Constituents; Features: Features; Finish: Finish; Grade: Grade; Material: Material; ModelReference: ModelReference; NominalHeight: NominalHeight; NominalLength: NominalLength; NominalWidth: NominalWidth; ProductionYear: ProductionYear; Reference: Reference; Shape: Shape; Size: Size; SustainabilityPerformance: SustainabilityPerformance; WarrantyDescription: WarrantyDescription; WarrantyDurationLabor: WarrantyDurationLabor; WarrantyDurationParts: WarrantyDurationParts; WarrantyGuarantorLabor: WarrantyGuarantorLabor; WarrantyGuarantorParts: WarrantyGuarantorParts; ExpectedLife: ExpectedLife; ReplacementCost: ReplacementCost; AssetAccountingType: FIXED; Classification Code: 23-25 40 11 11 11; Classification Description: Metal-Framed Gypsum Board Fixed Partitions; ModelLabel: ModelLabel
Basic Wall:Interior - Partition (92mm Stud):198335:2 | Second Floor | Pset_WallCommon - Reference: Basic Wall:Interior - Partition (92mm Stud); LoadBearing: no; ExtendToStructure: no; IsExternal: no; PSet_Revit_Constraints - Location Line: 2; Base Constraint: Second Floor; Base Offset: 0 m; Base is Attached: no; Base Extension Distance: 0 m; Top Constraint: Up to level: Roof - Main; Unconnected Height: 4.578 m; Top Offset: -0.102 m; Top is Attached: no; Top Extension Distance: 0 m; Room Bounding: yes; Related to Mass: no; PSet_Revit_Other - InstallationDate: InstallationDate; SerialNumber: SerialNumber; WarrantyStartDate: WarrantyStartDate; BarCode: BarCode; AssetIdentifier: AssetIdentifier; TagNumber: TagNumber; PSet_Revit_Phasing - Phase Created: New Construction; PSet_Revit_Structural - Structural Usage: 0; PSet_Revit_Dimensions - Length: 1.889 m; Area: 6.10074 m2; Volume: 0.756492 m3; PSet_Revit_Type_Construction - Wrapping at Inserts: 0; Wrapping at Ends: 2; Width: 0.124 m; Function: 0; PSet_Revit_Type_Graphics - Coarse Scale Fill Color: 0; PSet_Revit_Type_Identity Data - Manufacturer: Manufacturer; PSet_Revit_Type_Other - AccessibilityPerformance: AccessibilityPerformance; CodePerformance: CodePerformance; Color: Color; Constituents: Constituents; Features: Features; Finish: Finish; Grade: Grade; Material: Material; ModelReference: ModelReference; NominalHeight: NominalHeight; NominalLength: NominalLength; NominalWidth: NominalWidth; ProductionYear: ProductionYear; Reference: Reference; Shape: Shape; Size: Size; SustainabilityPerformance: SustainabilityPerformance; WarrantyDescription: WarrantyDescription; WarrantyDurationLabor: WarrantyDurationLabor; WarrantyDurationParts: WarrantyDurationParts; WarrantyGuarantorLabor: WarrantyGuarantorLabor; WarrantyGuarantorParts: WarrantyGuarantorParts; ExpectedLife: ExpectedLife; ReplacementCost: ReplacementCost; AssetAccountingType: FIXED; Classification Code: 23-25 40 11 11 11; Classification Description: Metal-Framed Gypsum Board Fixed Partitions; ModelLabel: ModelLabel
 | Second Floor | Pset_WallCommon - Reference: Basic Wall:Interior - Partition (92mm Stud); LoadBearing: no; ExtendToStructure: no; IsExternal: no; PSet_Revit_Constraints - Location Line: 2; Base Constraint: Second Floor; Base Offset: 0 m; Base is Attached: no; Base Extension Distance: 0 m; Top Constraint: Up to level: Roof - Main; Unconnected Height: 4.578 m; Top Offset: -0.102 m; Top is Attached: no; Top Extension Distance: 0 m; Room Bounding: yes; Related to Mass: no; PSet_Revit_Other - InstallationDate: InstallationDate; SerialNumber: SerialNumber; WarrantyStartDate: WarrantyStartDate; BarCode: BarCode; AssetIdentifier: AssetIdentifier; TagNumber: TagNumber; PSet_Revit_Phasing - Phase Created: New Construction; PSet_Revit_Structural - Structural Usage: 0; PSet_Revit_Dimensions - Length: 2.36464 m; Area: 10.2576 m2; Volume: 1.23581 m3; PSet_Revit_Type_Construction - Wrapping at Inserts: 0; Wrapping at Ends: 2; Width: 0.124 m; Function: 0; PSet_Revit_Type_Graphics - Coarse Scale Fill Color: 0; PSet_Revit_Type_Identity Data - Manufacturer: Manufacturer; PSet_Revit_Type_Other - AccessibilityPerformance: AccessibilityPerformance; CodePerformance: CodePerformance; Color: Color; Constituents: Constituents; Features: Features; Finish: Finish; Grade: Grade; Material: Material; ModelReference: ModelReference; NominalHeight: NominalHeight; NominalLength: NominalLength; NominalWidth: NominalWidth; ProductionYear: ProductionYear; Reference: Reference; Shape: Shape; Size: Size; SustainabilityPerformance: SustainabilityPerformance; WarrantyDescription: WarrantyDescription; WarrantyDurationLabor: WarrantyDurationLabor; WarrantyDurationParts: WarrantyDurationParts; WarrantyGuarantorLabor: WarrantyGuarantorLabor; WarrantyGuarantorParts: WarrantyGuarantorParts; ExpectedLife: ExpectedLife; ReplacementCost: ReplacementCost; AssetAccountingType: FIXED; Classification Code: 23-25 40 11 11 11; Classification Description: Metal-Framed Gypsum Board Fixed Partitions; ModelLabel: ModelLabel
Basic Wall:Interior - Rated 1-HR (92mm Stud):202564:2 | Second Floor | Pset_WallCommon - Reference: Basic Wall:Interior - Rated 1-HR (92mm Stud); LoadBearing: no; ExtendToStructure: no; IsExternal: no; FireRating: 1 HR; PSet_Revit_Constraints - Location Line: 2; Base Constraint: Second Floor; Base Offset: 0 m; Base is Attached: no; Base Extension Distance: 0 m; Top Constraint: Up to level: Roof - Main; Unconnected Height: 4.578 m; Top Offset: -0.102 m; Top is Attached: no; Top Extension Distance: 0 m; Room Bounding: yes; Related to Mass: no; PSet_Revit_Other - InstallationDate: InstallationDate; SerialNumber: SerialNumber; WarrantyStartDate: WarrantyStartDate; BarCode: BarCode; AssetIdentifier: AssetIdentifier; TagNumber: TagNumber; PSet_Revit_Phasing - Phase Created: New Construction; PSet_Revit_Structural - Structural Usage: 0; PSet_Revit_Dimensions - Length: 2.3592 m; Area: 8.28142 m2; Volume: 1.0269 m3; PSet_Revit_Type_Construction - Wrapping at Inserts: 0; Wrapping at Ends: 0; Width: 0.124 m; Function: 0; PSet_Revit_Type_Graphics - Coarse Scale Fill Color: 8421504; Coarse Scale Fill Pattern: Solid fill; PSet_Revit_Type_Identity Data - Manufacturer: Manufacturer; Fire Rating: 1 HR; PSet_Revit_Type_Other - AccessibilityPerformance: AccessibilityPerformance; CodePerformance: CodePerformance; Color: Color; Constituents: Constituents; Features: Features; Finish: Finish; Grade: Grade; Material: Material; ModelReference: ModelReference; NominalHeight: NominalHeight; NominalLength: NominalLength; NominalWidth: NominalWidth; ProductionYear: ProductionYear; Reference: Reference; Shape: Shape; Size: Size; SustainabilityPerformance: SustainabilityPerformance; WarrantyDescription: WarrantyDescription; WarrantyDurationLabor: WarrantyDurationLabor; WarrantyDurationParts: WarrantyDurationParts; WarrantyGuarantorLabor: WarrantyGuarantorLabor; WarrantyGuarantorParts: WarrantyGuarantorParts; ExpectedLife: ExpectedLife; ReplacementCost: ReplacementCost; AssetAccountingType: FIXED; Classification Code: 23-25 40 11 11 11; Classification Description: Metal-Framed Gypsum Board Fixed Partitions; ModelLabel: ModelLabel
Basic Wall:Interior - Partition (92mm Stud):204593:2 | Second Floor | Pset_WallCommon - Reference: Basic Wall:Interior - Partition (92mm Stud); LoadBearing: no; ExtendToStructure: no; IsExternal: no; PSet_Revit_Constraints - Location Line: 2; Base Constraint: Second Floor; Base Offset: 0 m; Base is Attached: no; Base Extension Distance: 0 m; Top Constraint: Up to level: Roof - Main; Unconnected Height: 4.578 m; Top Offset: -0.102 m; Top is Attached: no; Top Extension Distance: 0 m; Room Bounding: yes; Related to Mass: no; PSet_Revit_Other - InstallationDate: InstallationDate; SerialNumber: SerialNumber; WarrantyStartDate: WarrantyStartDate; BarCode: BarCode; AssetIdentifier: AssetIdentifier; TagNumber: TagNumber; PSet_Revit_Phasing - Phase Created: New Construction; PSet_Revit_Structural - Structural Usage: 0; PSet_Revit_Dimensions - Length: 3.465 m; Area: 14.644 m2; Volume: 1.81586 m3; PSet_Revit_Type_Construction - Wrapping at Inserts: 0; Wrapping at Ends: 2; Width: 0.124 m; Function: 0; PSet_Revit_Type_Graphics - Coarse Scale Fill Color: 0; PSet_Revit_Type_Identity Data - Manufacturer: Manufacturer; PSet_Revit_Type_Other - AccessibilityPerformance: AccessibilityPerformance; CodePerformance: CodePerformance; Color: Color; Constituents: Constituents; Features: Features; Finish: Finish; Grade: Grade; Material: Material; ModelReference: ModelReference; NominalHeight: NominalHeight; NominalLength: NominalLength; NominalWidth: NominalWidth; ProductionYear: ProductionYear; Reference: Reference; Shape: Shape; Size: Size; SustainabilityPerformance: SustainabilityPerformance; WarrantyDescription: WarrantyDescription; WarrantyDurationLabor: WarrantyDurationLabor; WarrantyDurationParts: WarrantyDurationParts; WarrantyGuarantorLabor: WarrantyGuarantorLabor; WarrantyGuarantorParts: WarrantyGuarantorParts; ExpectedLife: ExpectedLife; ReplacementCost: ReplacementCost; AssetAccountingType: FIXED; Classification Code: 23-25 40 11 11 11; Classification Description: Metal-Framed Gypsum Board Fixed Partitions; ModelLabel: ModelLabel
Basic Wall:Interior - Partition (92mm Stud):204658:2 | Second Floor | Pset_WallCommon - Reference: Basic Wall:Interior - Partition (92mm Stud); LoadBearing: no; ExtendToStructure: no; IsExternal: no; PSet_Revit_Constraints - Location Line: 2; Base Constraint: Second Floor; Base Offset: 0 m; Base is Attached: no; Base Extension Distance: 0 m; Top Constraint: Up to level: Roof - Main; Unconnected Height: 4.578 m; Top Offset: -0.102 m; Top is Attached: no; Top Extension Distance: 0 m; Room Bounding: yes; Related to Mass: no; PSet_Revit_Other - InstallationDate: InstallationDate; SerialNumber: SerialNumber; WarrantyStartDate: WarrantyStartDate; BarCode: BarCode; AssetIdentifier: AssetIdentifier; TagNumber: TagNumber; PSet_Revit_Phasing - Phase Created: New Construction; PSet_Revit_Structural - Structural Usage: 0; PSet_Revit_Dimensions - Length: 3.5 m; Area: 14.6178 m2; Volume: 1.8126 m3; PSet_Revit_Type_Construction - Wrapping at Inserts: 0; Wrapping at Ends: 2; Width: 0.124 m; Function: 0; PSet_Revit_Type_Graphics - Coarse Scale Fill Color: 0; PSet_Revit_Type_Identity Data - Manufacturer: Manufacturer; PSet_Revit_Type_Other - AccessibilityPerformance: AccessibilityPerformance; CodePerformance: CodePerformance; Color: Color; Constituents: Constituents; Features: Features; Finish: Finish; Grade: Grade; Material: Material; ModelReference: ModelReference; NominalHeight: NominalHeight; NominalLength: NominalLength; NominalWidth: NominalWidth; ProductionYear: ProductionYear; Reference: Reference; Shape: Shape; Size: Size; SustainabilityPerformance: SustainabilityPerformance; WarrantyDescription: WarrantyDescription; WarrantyDurationLabor: WarrantyDurationLabor; WarrantyDurationParts: WarrantyDurationParts; WarrantyGuarantorLabor: WarrantyGuarantorLabor; WarrantyGuarantorParts: WarrantyGuarantorParts; ExpectedLife: ExpectedLife; ReplacementCost: ReplacementCost; AssetAccountingType: FIXED; Classification Code: 23-25 40 11 11 11; Classification Description: Metal-Framed Gypsum Board Fixed Partitions; ModelLabel: ModelLabel
Basic Wall:Interior - Partition (92mm Stud):204720:2 | Second Floor | Pset_WallCommon - Reference: Basic Wall:Interior - Partition (92mm Stud); LoadBearing: no; ExtendToStructure: no; IsExternal: no; PSet_Revit_Constraints - Location Line: 2; Base Constraint: Second Floor; Base Offset: 0 m; Base is Attached: no; Base Extension Distance: 0 m; Top Constraint: Up to level: Roof - Main; Unconnected Height: 4.578 m; Top Offset: -0.102 m; Top is Attached: no; Top Extension Distance: 0 m; Room Bounding: yes; Related to Mass: no; PSet_Revit_Other - InstallationDate: InstallationDate; SerialNumber: SerialNumber; WarrantyStartDate: WarrantyStartDate; BarCode: BarCode; AssetIdentifier: AssetIdentifier; TagNumber: TagNumber; PSet_Revit_Phasing - Phase Created: New Construction; PSet_Revit_Structural - Structural Usage: 0; PSet_Revit_Dimensions - Length: 3.5 m; Area: 14.6086 m2; Volume: 1.81146 m3; PSet_Revit_Type_Construction - Wrapping at Inserts: 0; Wrapping at Ends: 2; Width: 0.124 m; Function: 0; PSet_Revit_Type_Graphics - Coarse Scale Fill Color: 0; PSet_Revit_Type_Identity Data - Manufacturer: Manufacturer; PSet_Revit_Type_Other - AccessibilityPerformance: AccessibilityPerformance; CodePerformance: CodePerformance; Color: Color; Constituents: Constituents; Features: Features; Finish: Finish; Grade: Grade; Material: Material; ModelReference: ModelReference; NominalHeight: NominalHeight; NominalLength: NominalLength; NominalWidth: NominalWidth; ProductionYear: ProductionYear; Reference: Reference; Shape: Shape; Size: Size; SustainabilityPerformance: SustainabilityPerformance; WarrantyDescription: WarrantyDescription; WarrantyDurationLabor: WarrantyDurationLabor; WarrantyDurationParts: WarrantyDurationParts; WarrantyGuarantorLabor: WarrantyGuarantorLabor; WarrantyGuarantorParts: WarrantyGuarantorParts; ExpectedLife: ExpectedLife; ReplacementCost: ReplacementCost; AssetAccountingType: FIXED; Classification Code: 23-25 40 11 11 11; Classification Description: Metal-Framed Gypsum Board Fixed Partitions; ModelLabel: ModelLabel
 | Second Floor | Pset_WallCommon - Reference: Basic Wall:Interior - Furring (152 mm Stud); LoadBearing: no; ExtendToStructure: no; IsExternal: no; PSet_Revit_Constraints - Location Line: 0; Base Constraint: Second Floor; Base Offset: 0 m; Base is Attached: no; Base Extension Distance: 0 m; Top Constraint: Up to level: Roof - Main; Unconnected Height: 4.578 m; Top Offset: -0.102 m; Top is Attached: no; Top Extension Distance: 0 m; Room Bounding: yes; Related to Mass: no; PSet_Revit_Other - InstallationDate: InstallationDate; SerialNumber: SerialNumber; WarrantyStartDate: WarrantyStartDate; BarCode: BarCode; AssetIdentifier: AssetIdentifier; TagNumber: TagNumber; PSet_Revit_Phasing - Phase Created: New Construction; PSet_Revit_Structural - Structural Usage: 0; PSet_Revit_Dimensions - Length: 2.6485 m; Area: 11.7975 m2; Volume: 1.94584 m3; PSet_Revit_Type_Construction - Wrapping at Inserts: 0; Wrapping at Ends: 0; Width: 0.168 m; Function: 0; PSet_Revit_Type_Graphics - Coarse Scale Fill Color: 0; PSet_Revit_Type_Identity Data - Manufacturer: Manufacturer; PSet_Revit_Type_Other - AccessibilityPerformance: AccessibilityPerformance; CodePerformance: CodePerformance; Color: Color; Constituents: Constituents; Features: Features; Finish: Finish; Grade: Grade; Material: Material; ModelReference: ModelReference; NominalHeight: NominalHeight; NominalLength: NominalLength; NominalWidth: NominalWidth; ProductionYear: ProductionYear; Reference: Reference; Shape: Shape; Size: Size; SustainabilityPerformance: SustainabilityPerformance; WarrantyDescription: WarrantyDescription; WarrantyDurationLabor: WarrantyDurationLabor; WarrantyDurationParts: WarrantyDurationParts; WarrantyGuarantorLabor: WarrantyGuarantorLabor; WarrantyGuarantorParts: WarrantyGuarantorParts; ExpectedLife: ExpectedLife; ReplacementCost: ReplacementCost; AssetAccountingType: FIXED; Classification Code: 23-25 40 11 11 11; Classification Description: Metal-Framed Gypsum Board Fixed Partitions; ModelLabel: ModelLabel
2 x  | Second Floor | Pset_WallCommon - Reference: Basic Wall:Interior - Furring (152 mm Stud); LoadBearing: no; ExtendToStructure: no; IsExternal: no; PSet_Revit_Constraints - Location Line: 2; Base Constraint: Second Floor; Base Offset: 0 m; Base is Attached: no; Base Extension Distance: 0 m; Top Constraint: Up to level: Roof - Main; Unconnected Height: 4.578 m; Top Offset: -0.102 m; Top is Attached: no; Top Extension Distance: 0 m; Room Bounding: yes; Related to Mass: no; PSet_Revit_Other - InstallationDate: InstallationDate; SerialNumber: SerialNumber; WarrantyStartDate: WarrantyStartDate; BarCode: BarCode; AssetIdentifier: AssetIdentifier; TagNumber: TagNumber; PSet_Revit_Phasing - Phase Created: New Construction; PSet_Revit_Structural - Structural Usage: 0; PSet_Revit_Dimensions - Length: 2.796 m; Area: 12.2324 m2; Volume: 2.01891 m3; PSet_Revit_Type_Construction - Wrapping at Inserts: 0; Wrapping at Ends: 0; Width: 0.168 m; Function: 0; PSet_Revit_Type_Graphics - Coarse Scale Fill Color: 0; PSet_Revit_Type_Identity Data - Manufacturer: Manufacturer; PSet_Revit_Type_Other - AccessibilityPerformance: AccessibilityPerformance; CodePerformance: CodePerformance; Color: Color; Constituents: Constituents; Features: Features; Finish: Finish; Grade: Grade; Material: Material; ModelReference: ModelReference; NominalHeight: NominalHeight; NominalLength: NominalLength; NominalWidth: NominalWidth; ProductionYear: ProductionYear; Reference: Reference; Shape: Shape; Size: Size; SustainabilityPerformance: SustainabilityPerformance; WarrantyDescription: WarrantyDescription; WarrantyDurationLabor: WarrantyDurationLabor; WarrantyDurationParts: WarrantyDurationParts; WarrantyGuarantorLabor: WarrantyGuarantorLabor; WarrantyGuarantorParts: WarrantyGuarantorParts; ExpectedLife: ExpectedLife; ReplacementCost: ReplacementCost; AssetAccountingType: FIXED; Classification Code: 23-25 40 11 11 11; Classification Description: Metal-Framed Gypsum Board Fixed Partitions; ModelLabel: ModelLabel
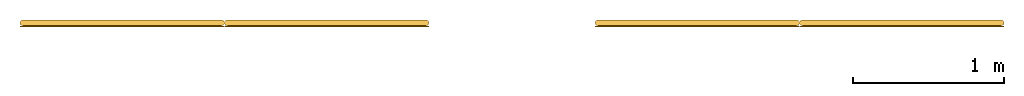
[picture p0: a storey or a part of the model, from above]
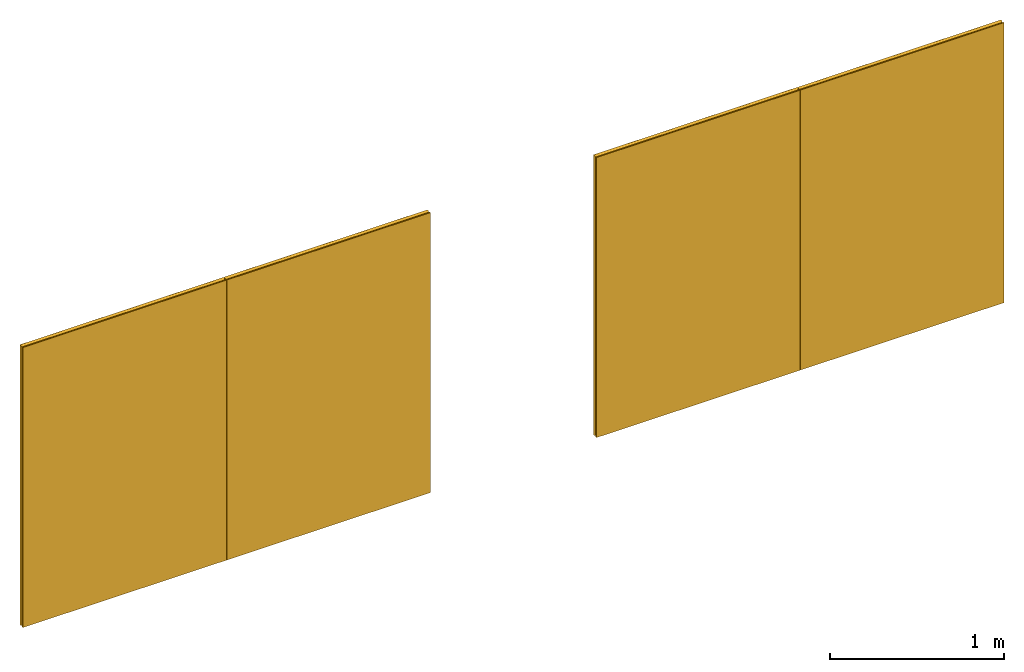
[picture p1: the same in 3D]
Properties of the parts of a building model (IFC2X3), part 6 of 11

# IfcOpeningElement: Opening (403)
Name | In
 | Second Floor | Pset_WallCommon - Reference: Basic Wall:Interior - Partition (92mm Stud); LoadBearing: no; ExtendToStructure: no; IsExternal: no; PSet_Revit_Constraints - Location Line: 2; Base Constraint: Second Floor; Base Offset: 0 m; Base is Attached: no; Base Extension Distance: 0 m; Top Constraint: Up to level: Roof - Main; Unconnected Height: 4.578 m; Top Offset: -0.102 m; Top is Attached: no; Top Extension Distance: 0 m; Room Bounding: yes; Related to Mass: no; PSet_Revit_Other - InstallationDate: InstallationDate; SerialNumber: SerialNumber; WarrantyStartDate: WarrantyStartDate; BarCode: BarCode; AssetIdentifier: AssetIdentifier; TagNumber: TagNumber; PSet_Revit_Phasing - Phase Created: New Construction; PSet_Revit_Structural - Structural Usage: 0; PSet_Revit_Dimensions - Length: 2.548 m; Area: 11.3809 m2; Volume: 1.37509 m3; PSet_Revit_Type_Construction - Wrapping at Inserts: 0; Wrapping at Ends: 2; Width: 0.124 m; Function: 0; PSet_Revit_Type_Graphics - Coarse Scale Fill Color: 0; PSet_Revit_Type_Identity Data - Manufacturer: Manufacturer; PSet_Revit_Type_Other - AccessibilityPerformance: AccessibilityPerformance; CodePerformance: CodePerformance; Color: Color; Constituents: Constituents; Features: Features; Finish: Finish; Grade: Grade; Material: Material; ModelReference: ModelReference; NominalHeight: NominalHeight; NominalLength: NominalLength; NominalWidth: NominalWidth; ProductionYear: ProductionYear; Reference: Reference; Shape: Shape; Size: Size; SustainabilityPerformance: SustainabilityPerformance; WarrantyDescription: WarrantyDescription; WarrantyDurationLabor: WarrantyDurationLabor; WarrantyDurationParts: WarrantyDurationParts; WarrantyGuarantorLabor: WarrantyGuarantorLabor; WarrantyGuarantorParts: WarrantyGuarantorParts; ExpectedLife: ExpectedLife; ReplacementCost: ReplacementCost; AssetAccountingType: FIXED; Classification Code: 23-25 40 11 11 11; Classification Description: Metal-Framed Gypsum Board Fixed Partitions; ModelLabel: ModelLabel
 | Second Floor | Pset_WallCommon - Reference: Basic Wall:Interior - Partition (92mm Stud); LoadBearing: no; ExtendToStructure: no; IsExternal: no; PSet_Revit_Constraints - Location Line: 2; Base Constraint: Second Floor; Base Offset: 0 m; Base is Attached: no; Base Extension Distance: 0 m; Top Constraint: Up to level: Roof - Main; Unconnected Height: 4.578 m; Top Offset: -0.102 m; Top is Attached: no; Top Extension Distance: 0 m; Room Bounding: yes; Related to Mass: no; PSet_Revit_Other - InstallationDate: InstallationDate; SerialNumber: SerialNumber; WarrantyStartDate: WarrantyStartDate; BarCode: BarCode; AssetIdentifier: AssetIdentifier; TagNumber: TagNumber; PSet_Revit_Phasing - Phase Created: New Construction; PSet_Revit_Structural - Structural Usage: 0; PSet_Revit_Dimensions - Length: 1.834 m; Area: 6.43624 m2; Volume: 0.798094 m3; PSet_Revit_Type_Construction - Wrapping at Inserts: 0; Wrapping at Ends: 2; Width: 0.124 m; Function: 0; PSet_Revit_Type_Graphics - Coarse Scale Fill Color: 0; PSet_Revit_Type_Identity Data - Manufacturer: Manufacturer; PSet_Revit_Type_Other - AccessibilityPerformance: AccessibilityPerformance; CodePerformance: CodePerformance; Color: Color; Constituents: Constituents; Features: Features; Finish: Finish; Grade: Grade; Material: Material; ModelReference: ModelReference; NominalHeight: NominalHeight; NominalLength: NominalLength; NominalWidth: NominalWidth; ProductionYear: ProductionYear; Reference: Reference; Shape: Shape; Size: Size; SustainabilityPerformance: SustainabilityPerformance; WarrantyDescription: WarrantyDescription; WarrantyDurationLabor: WarrantyDurationLabor; WarrantyDurationParts: WarrantyDurationParts; WarrantyGuarantorLabor: WarrantyGuarantorLabor; WarrantyGuarantorParts: WarrantyGuarantorParts; ExpectedLife: ExpectedLife; ReplacementCost: ReplacementCost; AssetAccountingType: FIXED; Classification Code: 23-25 40 11 11 11; Classification Description: Metal-Framed Gypsum Board Fixed Partitions; ModelLabel: ModelLabel
 | Second Floor | Pset_WallCommon - Reference: Basic Wall:Interior - Partition (92mm Stud); LoadBearing: no; ExtendToStructure: no; IsExternal: no; PSet_Revit_Constraints - Location Line: 2; Base Constraint: Second Floor; Base Offset: 0 m; Base is Attached: no; Base Extension Distance: 0 m; Top Constraint: Up to level: Roof - Main; Unconnected Height: 4.578 m; Top Offset: -0.102 m; Top is Attached: no; Top Extension Distance: 0 m; Room Bounding: yes; Related to Mass: no; PSet_Revit_Other - InstallationDate: InstallationDate; SerialNumber: SerialNumber; WarrantyStartDate: WarrantyStartDate; BarCode: BarCode; AssetIdentifier: AssetIdentifier; TagNumber: TagNumber; PSet_Revit_Phasing - Phase Created: New Construction; PSet_Revit_Structural - Structural Usage: 0; PSet_Revit_Dimensions - Length: 5.69064 m; Area: 26.1753 m2; Volume: 3.2096 m3; PSet_Revit_Type_Construction - Wrapping at Inserts: 0; Wrapping at Ends: 2; Width: 0.124 m; Function: 0; PSet_Revit_Type_Graphics - Coarse Scale Fill Color: 0; PSet_Revit_Type_Identity Data - Manufacturer: Manufacturer; PSet_Revit_Type_Other - AccessibilityPerformance: AccessibilityPerformance; CodePerformance: CodePerformance; Color: Color; Constituents: Constituents; Features: Features; Finish: Finish; Grade: Grade; Material: Material; ModelReference: ModelReference; NominalHeight: NominalHeight; NominalLength: NominalLength; NominalWidth: NominalWidth; ProductionYear: ProductionYear; Reference: Reference; Shape: Shape; Size: Size; SustainabilityPerformance: SustainabilityPerformance; WarrantyDescription: WarrantyDescription; WarrantyDurationLabor: WarrantyDurationLabor; WarrantyDurationParts: WarrantyDurationParts; WarrantyGuarantorLabor: WarrantyGuarantorLabor; WarrantyGuarantorParts: WarrantyGuarantorParts; ExpectedLife: ExpectedLife; ReplacementCost: ReplacementCost; AssetAccountingType: FIXED; Classification Code: 23-25 40 11 11 11; Classification Description: Metal-Framed Gypsum Board Fixed Partitions; ModelLabel: ModelLabel
 | Second Floor | Pset_WallCommon - Reference: Basic Wall:Interior - Furring (38 mm Stud); LoadBearing: no; ExtendToStructure: no; IsExternal: no; PSet_Revit_Constraints - Location Line: 2; Base Constraint: Second Floor; Base Offset: 0 m; Base is Attached: no; Base Extension Distance: 0 m; Top Constraint: Up to level: Roof - Main; Unconnected Height: 4.578 m; Top Offset: -0.102 m; Top is Attached: no; Top Extension Distance: 0 m; Room Bounding: yes; Related to Mass: no; PSet_Revit_Other - InstallationDate: InstallationDate; SerialNumber: SerialNumber; WarrantyStartDate: WarrantyStartDate; BarCode: BarCode; AssetIdentifier: AssetIdentifier; TagNumber: TagNumber; PSet_Revit_Phasing - Phase Created: New Construction; PSet_Revit_Structural - Structural Usage: 0; PSet_Revit_Dimensions - Length: 6.44109 m; Area: 28.6733 m2; Volume: 1.53971 m3; PSet_Revit_Type_Construction - Wrapping at Inserts: 0; Wrapping at Ends: 0; Width: 0.054 m; Function: 0; PSet_Revit_Type_Graphics - Coarse Scale Fill Color: 0; PSet_Revit_Type_Identity Data - Manufacturer: Manufacturer; PSet_Revit_Type_Other - AccessibilityPerformance: AccessibilityPerformance; CodePerformance: CodePerformance; Color: Color; Constituents: Constituents; Features: Features; Finish: Finish; Grade: Grade; Material: Material; ModelReference: ModelReference; NominalHeight: NominalHeight; NominalLength: NominalLength; NominalWidth: NominalWidth; ProductionYear: ProductionYear; Reference: Reference; Shape: Shape; Size: Size; SustainabilityPerformance: SustainabilityPerformance; WarrantyDescription: WarrantyDescription; WarrantyDurationLabor: WarrantyDurationLabor; WarrantyDurationParts: WarrantyDurationParts; WarrantyGuarantorLabor: WarrantyGuarantorLabor; WarrantyGuarantorParts: WarrantyGuarantorParts; ExpectedLife: ExpectedLife; ReplacementCost: ReplacementCost; AssetAccountingType: FIXED; Classification Code: 23-25 40 11 11 11; Classification Description: Metal-Framed Gypsum Board Fixed Partitions; ModelLabel: ModelLabel
M_Single-Flush:0915 x 2134mm:0915 x 2134mm:221919:1 | First Floor
M_Single-Flush:0915 x 2134mm:0915 x 2134mm:221992:1 | First Floor
M_Single-Flush:0915 x 2134mm:0915 x 2134mm:222050:1 | First Floor
M_Single-Flush:0915 x 2134mm:0915 x 2134mm:222117:1 | First Floor
M_Single-Flush:0915 x 2134mm:0915 x 2134mm:222344:1 | First Floor
M_Single-Flush:0915 x 2134mm Exterior:0915 x 2134mm Exterior:222415:1 | First Floor
M_Single-Flush:0915 x 2134mm Rated:0915 x 2134mm Rated:222571:1 | First Floor
M_Single-Flush:0915 x 2134mm:0915 x 2134mm:222740:1 | First Floor
M_Single-Flush:0915 x 2134mm:0915 x 2134mm:222929:1 | First Floor
M_Single-Flush:0915 x 2134mm:0915 x 2134mm:223030:1 | First Floor
M_Single-Flush:0915 x 2134mm:0915 x 2134mm:223137:1 | First Floor
M_Single-Flush:0915 x 2134mm:0915 x 2134mm:223212:1 | First Floor
M_Single-Flush:0915 x 2134mm:0915 x 2134mm:223301:1 | First Floor
M_Single-Flush:0915 x 2134mm:0915 x 2134mm:223378:1 | First Floor
M_Single-Flush:0915 x 2134mm:0915 x 2134mm:223429:1 | First Floor
M_Single-Flush:0915 x 2134mm:0915 x 2134mm:223457:1 | First Floor
M_Single-Flush:0915 x 2134mm:0915 x 2134mm:223504:1 | First Floor
M_Single-Flush:0915 x 2134mm:0915 x 2134mm:223667:1 | First Floor
M_Single-Flush:0915 x 2134mm:0915 x 2134mm:223704:1 | First Floor
M_Single-Flush:0915 x 2134mm:0915 x 2134mm:223773:1 | First Floor
M_Single-Flush:0915 x 2134mm:0915 x 2134mm:223840:1 | First Floor
M_Single-Flush:0915 x 2134mm:0915 x 2134mm:223957:1 | First Floor
M_Single-Flush:0915 x 2134mm:0915 x 2134mm:224018:1 | First Floor
M_Single-Flush:0915 x 2134mm:0915 x 2134mm:224077:1 | First Floor
M_Single-Flush:0915 x 2134mm:0915 x 2134mm:224146:1 | First Floor
M_Single-Flush:0915 x 2134mm:0915 x 2134mm:224207:1 | First Floor
M_Single-Flush:0915 x 2134mm:0915 x 2134mm:224302:1 | First Floor
M_Single-Flush:0915 x 2134mm:0915 x 2134mm:224343:1 | First Floor
M_Single-Flush:0915 x 2134mm:0915 x 2134mm:224424:1 | First Floor
M_Single-Flush:0915 x 2134mm:0915 x 2134mm:224469:1 | First Floor
M_Single-Flush:0915 x 2134mm:0915 x 2134mm:224561:1 | First Floor
M_Single-Flush:0915 x 2134mm:0915 x 2134mm:224600:1 | First Floor
M_Single-Flush:0915 x 2134mm:0915 x 2134mm:224653:1 | First Floor
M_Single-Flush:0915 x 2134mm:0915 x 2134mm:224873:1 | First Floor
M_Single-Flush:0915 x 2134mm:0915 x 2134mm:224980:1 | First Floor
M_Single-Flush:0915 x 2134mm:0915 x 2134mm:225051:1 | First Floor
M_Single-Flush:0915 x 2134mm:0915 x 2134mm:225128:1 | First Floor
M_Single-Flush:0915 x 2134mm:0915 x 2134mm:225305:1 | First Floor
M_Single-Flush:0915 x 2134mm:0915 x 2134mm:225472:1 | First Floor
M_Single-Flush:0915 x 2134mm:0915 x 2134mm:225517:1 | First Floor
M_Single-Flush:0915 x 2134mm:0915 x 2134mm:225574:1 | First Floor
M_Single-Flush:0915 x 2134mm:0915 x 2134mm:225680:1 | First Floor
M_Single-Flush:0915 x 2134mm:0915 x 2134mm:225761:1 | First Floor
M_Single-Flush:0915 x 2134mm:0915 x 2134mm:225828:1 | First Floor
M_Single-Flush:0915 x 2134mm:0915 x 2134mm:225883:1 | First Floor
M_Single-Flush:0915 x 2134mm:0915 x 2134mm:225922:1 | First Floor
M_Single-Flush:0915 x 2134mm:0915 x 2134mm:226135:1 | First Floor
M_Single-Flush:0915 x 2134mm:0915 x 2134mm:226204:1 | First Floor
M_Single-Flush:0915 x 2134mm:0915 x 2134mm:226489:1 | First Floor
M_Single-Flush:0915 x 2134mm:0915 x 2134mm:226564:1 | First Floor
M_Single-Flush:0915 x 2134mm:0915 x 2134mm:226625:1 | First Floor
M_Single-Flush:0915 x 2134mm:0915 x 2134mm:226737:1 | First Floor
M_Single-Flush:0915 x 2134mm:0915 x 2134mm:226850:1 | First Floor
M_Single-Flush:0915 x 2134mm:0915 x 2134mm:226967:1 | First Floor
M_Single-Flush:0915 x 2134mm:0915 x 2134mm:227136:1 | First Floor
M_Single-Flush:0915 x 2134mm:0915 x 2134mm:227199:1 | First Floor
M_Single-Flush:0915 x 2134mm:0915 x 2134mm:227366:1 | First Floor
M_Single-Flush:0915 x 2134mm:0915 x 2134mm:227455:1 | First Floor
M_Single-Flush:0915 x 2134mm:0915 x 2134mm:227536:1 | First Floor
M_Single-Flush:0915 x 2134mm:0915 x 2134mm:227615:1 | First Floor
M_Single-Flush:0915 x 2134mm:0915 x 2134mm:227769:1 | First Floor
M_Single-Flush:0915 x 2134mm:0915 x 2134mm:227830:1 | First Floor
M_Single-Flush:0915 x 2134mm:0915 x 2134mm:227879:1 | First Floor
M_Single-Flush:0915 x 2134mm:0915 x 2134mm:227926:1 | First Floor
M_Single-Flush:0915 x 2134mm:0915 x 2134mm:228297:1 | First Floor
M_Single-Flush:0915 x 2134mm:0915 x 2134mm:228354:1 | First Floor
M_Single-Flush:0915 x 2134mm:0915 x 2134mm:228516:1 | First Floor
M_Single-Flush:0915 x 2134mm:0915 x 2134mm:228575:1 | First Floor
M_Single-Flush:0915 x 2134mm:0915 x 2134mm:228650:1 | First Floor
M_Single-Flush:0915 x 2134mm:0915 x 2134mm:228897:1 | First Floor
M_Single-Flush:0915 x 2134mm:0915 x 2134mm:228938:1 | First Floor
M_Single-Flush:0915 x 2134mm:0915 x 2134mm:228981:1 | First Floor
M_Single-Flush:0915 x 2134mm:0915 x 2134mm:229120:1 | First Floor
M_Single-Flush:0915 x 2134mm:0915 x 2134mm:229157:1 | First Floor
M_Single-Flush:0915 x 2134mm:0915 x 2134mm:229319:1 | First Floor
M_Single-Flush:0915 x 2134mm:0915 x 2134mm:229354:1 | First Floor
M_Single-Flush:0915 x 2134mm:0915 x 2134mm:229427:1 | First Floor
M_Single-Flush:0915 x 2134mm:0915 x 2134mm:229478:1 | First Floor
M_Single-Flush:0915 x 2134mm:0915 x 2134mm:229539:1 | First Floor
M_Single-Flush:0915 x 2134mm:0915 x 2134mm:229578:1 | First Floor
M_Single-Flush:1000 x 2134mm:1000 x 2134mm:230127:1 | First Floor
M_Single-Flush:0915 x 2134mm Rated:0915 x 2134mm Rated:230209:1 | First Floor
M_Single-Flush:1.220 x 2134mm:1.220 x 2134mm:230394:1 | First Floor
M_Single-Flush:0915 x 2134mm:0915 x 2134mm:230556:1 | First Floor
M_Single-Flush:0915 x 2134mm:0915 x 2134mm:230607:1 | First Floor
M_Single-Flush:0915 x 2134mm:0915 x 2134mm:230738:1 | First Floor
M_Single-Flush:0915 x 2134mm:0915 x 2134mm:230814:1 | First Floor
M_Single-Flush:0915 x 2134mm:0915 x 2134mm:230949:1 | First Floor
M_Single-Flush:0915 x 2134mm:0915 x 2134mm:230994:1 | First Floor
M_Single-Flush:0915 x 2134mm:0915 x 2134mm:231041:1 | First Floor
M_Single-Flush:0915 x 2134mm:0915 x 2134mm:231180:1 | First Floor
M_Single-Flush:0915 x 2134mm:0915 x 2134mm:231213:1 | First Floor
M_Single-Flush:0915 x 2134mm:0915 x 2134mm:231274:1 | First Floor
M_Single-Flush:0915 x 2134mm:0915 x 2134mm:231377:1 | First Floor
M_Single-Flush:0915 x 2134mm:0915 x 2134mm:231452:1 | First Floor
M_Single-Flush:0915 x 2134mm Exterior:0915 x 2134mm Exterior:231495:1 | First Floor
M_Single-Flush:0915 x 2134mm Exterior:0915 x 2134mm Exterior:231622:1 | First Floor
M_Single-Flush:0915 x 2134mm:0915 x 2134mm:231651:1 | First Floor
M_Single-Flush:0915 x 2134mm:0915 x 2134mm:231755:1 | First Floor
 | First Floor | Pset_WallCommon - Reference: Basic Wall:Interior - Partition (92mm Stud); LoadBearing: no; ExtendToStructure: no; IsExternal: no; PSet_Revit_Constraints - Location Line: 2; Base Constraint: First Floor; Base Offset: 0 m; Base is Attached: no; Base Extension Distance: 0 m; Top Constraint: Up to level: Second Floor; Unconnected Height: 4.468 m; Top Offset: -0.102 m; Top is Attached: no; Top Extension Distance: 0 m; Room Bounding: yes; Related to Mass: no; PSet_Revit_Other - InstallationDate: InstallationDate; SerialNumber: SerialNumber; WarrantyStartDate: WarrantyStartDate; BarCode: BarCode; AssetIdentifier: AssetIdentifier; TagNumber: TagNumber; PSet_Revit_Phasing - Phase Created: New Construction; PSet_Revit_Structural - Structural Usage: 0; PSet_Revit_Dimensions - Length: 2.924 m; Area: 10.5578 m2; Volume: 1.27303 m3; PSet_Revit_Type_Construction - Wrapping at Inserts: 0; Wrapping at Ends: 2; Width: 0.124 m; Function: 0; PSet_Revit_Type_Graphics - Coarse Scale Fill Color: 0; PSet_Revit_Type_Identity Data - Manufacturer: Manufacturer; PSet_Revit_Type_Other - AccessibilityPerformance: AccessibilityPerformance; CodePerformance: CodePerformance; Color: Color; Constituents: Constituents; Features: Features; Finish: Finish; Grade: Grade; Material: Material; ModelReference: ModelReference; NominalHeight: NominalHeight; NominalLength: NominalLength; NominalWidth: NominalWidth; ProductionYear: ProductionYear; Reference: Reference; Shape: Shape; Size: Size; SustainabilityPerformance: SustainabilityPerformance; WarrantyDescription: WarrantyDescription; WarrantyDurationLabor: WarrantyDurationLabor; WarrantyDurationParts: WarrantyDurationParts; WarrantyGuarantorLabor: WarrantyGuarantorLabor; WarrantyGuarantorParts: WarrantyGuarantorParts; ExpectedLife: ExpectedLife; ReplacementCost: ReplacementCost; AssetAccountingType: FIXED; Classification Code: 23-25 40 11 11 11; Classification Description: Metal-Framed Gypsum Board Fixed Partitions; ModelLabel: ModelLabel
M_Single-Flush:0915 x 2134mm:0915 x 2134mm:231990:1 | First Floor
M_Single-Flush:0915 x 2134mm:0915 x 2134mm:232087:1 | First Floor
M_Single-Flush:0915 x 2134mm:0915 x 2134mm:232154:1 | First Floor
M_Single-Flush:0915 x 2134mm:0915 x 2134mm:232239:1 | First Floor
M_Single-Flush:0915 x 2134mm:0915 x 2134mm:232292:1 | First Floor
M_Single-Flush:0915 x 2134mm:0915 x 2134mm:232339:1 | First Floor
M_Single-Flush:0915 x 2134mm:0915 x 2134mm:232388:1 | First Floor
M_Single-Flush:0915 x 2134mm:0915 x 2134mm:232467:1 | First Floor
M_Single-Flush:0915 x 2134mm:0915 x 2134mm:232576:1 | First Floor
M_Single-Flush:0915 x 2134mm:0915 x 2134mm:232789:1 | First Floor
M_Single-Flush:0915 x 2134mm:0915 x 2134mm:232828:1 | First Floor
M_Single-Flush:0915 x 2134mm Exterior:0915 x 2134mm Exterior:232975:1 | First Floor
M_Single-Flush:0915 x 2134mm:0915 x 2134mm:233072:1 | First Floor
M_Single-Flush:0915 x 2134mm:0915 x 2134mm:233169:1 | First Floor
M_Single-Flush:0915 x 2134mm:0915 x 2134mm:233264:1 | First Floor
M_Single-Flush:1.220 x 2134mm Exterior:1.220 x 2134mm Exterior:233580:1 | First Floor
M_Single-Flush:0915 x 2134mm Exterior:0915 x 2134mm Exterior:233711:1 | First Floor
M_Single-Flush:0915 x 2134mm:0915 x 2134mm:234077:1 | First Floor
M_Single-Flush:0915 x 2134mm:0915 x 2134mm:234202:1 | First Floor
M_Single-Flush:0915 x 2134mm:0915 x 2134mm:234428:1 | Second Floor
M_Single-Flush:0915 x 2134mm Rated:0915 x 2134mm Rated:234664:1 | Second Floor
M_Single-Flush:0915 x 2134mm:0915 x 2134mm:234796:1 | Second Floor
M_Single-Flush:0915 x 2134mm:0915 x 2134mm:234843:1 | Second Floor
M_Single-Flush:0915 x 2134mm:0915 x 2134mm:234926:1 | Second Floor
M_Single-Flush:0915 x 2134mm:0915 x 2134mm:235137:1 | Second Floor
M_Single-Flush:0915 x 2134mm:0915 x 2134mm:235194:1 | Second Floor
M_Single-Flush:0915 x 2134mm:0915 x 2134mm:235326:1 | Second Floor
M_Single-Flush:0915 x 2134mm:0915 x 2134mm:235450:1 | Second Floor
M_Single-Flush:0915 x 2134mm:0915 x 2134mm:235529:1 | Second Floor
M_Single-Flush:0915 x 2134mm:0915 x 2134mm:235604:1 | Second Floor
Basic Wall:Interior - Partition (92mm Stud):235927:2 | Second Floor | Pset_WallCommon - Reference: Basic Wall:Interior - Partition (92mm Stud); LoadBearing: no; ExtendToStructure: no; IsExternal: no; PSet_Revit_Constraints - Location Line: 2; Base Constraint: Second Floor; Base Offset: 0 m; Base is Attached: no; Base Extension Distance: 0 m; Top Constraint: Up to level: Roof - Main; Unconnected Height: 4.578 m; Top Offset: -0.102 m; Top is Attached: no; Top Extension Distance: 0 m; Room Bounding: yes; Related to Mass: no; PSet_Revit_Other - InstallationDate: InstallationDate; SerialNumber: SerialNumber; WarrantyStartDate: WarrantyStartDate; BarCode: BarCode; AssetIdentifier: AssetIdentifier; TagNumber: TagNumber; PSet_Revit_Phasing - Phase Created: New Construction; PSet_Revit_Structural - Structural Usage: 0; PSet_Revit_Dimensions - Length: 32.32 m; Area: 127.04 m2; Volume: 15.7529 m3; PSet_Revit_Type_Construction - Wrapping at Inserts: 0; Wrapping at Ends: 2; Width: 0.124 m; Function: 0; PSet_Revit_Type_Graphics - Coarse Scale Fill Color: 0; PSet_Revit_Type_Identity Data - Manufacturer: Manufacturer; PSet_Revit_Type_Other - AccessibilityPerformance: AccessibilityPerformance; CodePerformance: CodePerformance; Color: Color; Constituents: Constituents; Features: Features; Finish: Finish; Grade: Grade; Material: Material; ModelReference: ModelReference; NominalHeight: NominalHeight; NominalLength: NominalLength; NominalWidth: NominalWidth; ProductionYear: ProductionYear; Reference: Reference; Shape: Shape; Size: Size; SustainabilityPerformance: SustainabilityPerformance; WarrantyDescription: WarrantyDescription; WarrantyDurationLabor: WarrantyDurationLabor; WarrantyDurationParts: WarrantyDurationParts; WarrantyGuarantorLabor: WarrantyGuarantorLabor; WarrantyGuarantorParts: WarrantyGuarantorParts; ExpectedLife: ExpectedLife; ReplacementCost: ReplacementCost; AssetAccountingType: FIXED; Classification Code: 23-25 40 11 11 11; Classification Description: Metal-Framed Gypsum Board Fixed Partitions; ModelLabel: ModelLabel
Basic Wall:Interior - Partition (92mm Stud):235927:3 | Second Floor | Pset_WallCommon - Reference: Basic Wall:Interior - Partition (92mm Stud); LoadBearing: no; ExtendToStructure: no; IsExternal: no; PSet_Revit_Constraints - Location Line: 2; Base Constraint: Second Floor; Base Offset: 0 m; Base is Attached: no; Base Extension Distance: 0 m; Top Constraint: Up to level: Roof - Main; Unconnected Height: 4.578 m; Top Offset: -0.102 m; Top is Attached: no; Top Extension Distance: 0 m; Room Bounding: yes; Related to Mass: no; PSet_Revit_Other - InstallationDate: InstallationDate; SerialNumber: SerialNumber; WarrantyStartDate: WarrantyStartDate; BarCode: BarCode; AssetIdentifier: AssetIdentifier; TagNumber: TagNumber; PSet_Revit_Phasing - Phase Created: New Construction; PSet_Revit_Structural - Structural Usage: 0; PSet_Revit_Dimensions - Length: 32.32 m; Area: 127.04 m2; Volume: 15.7529 m3; PSet_Revit_Type_Construction - Wrapping at Inserts: 0; Wrapping at Ends: 2; Width: 0.124 m; Function: 0; PSet_Revit_Type_Graphics - Coarse Scale Fill Color: 0; PSet_Revit_Type_Identity Data - Manufacturer: Manufacturer; PSet_Revit_Type_Other - AccessibilityPerformance: AccessibilityPerformance; CodePerformance: CodePerformance; Color: Color; Constituents: Constituents; Features: Features; Finish: Finish; Grade: Grade; Material: Material; ModelReference: ModelReference; NominalHeight: NominalHeight; NominalLength: NominalLength; NominalWidth: NominalWidth; ProductionYear: ProductionYear; Reference: Reference; Shape: Shape; Size: Size; SustainabilityPerformance: SustainabilityPerformance; WarrantyDescription: WarrantyDescription; WarrantyDurationLabor: WarrantyDurationLabor; WarrantyDurationParts: WarrantyDurationParts; WarrantyGuarantorLabor: WarrantyGuarantorLabor; WarrantyGuarantorParts: WarrantyGuarantorParts; ExpectedLife: ExpectedLife; ReplacementCost: ReplacementCost; AssetAccountingType: FIXED; Classification Code: 23-25 40 11 11 11; Classification Description: Metal-Framed Gypsum Board Fixed Partitions; ModelLabel: ModelLabel
Basic Wall:Interior - Partition (92mm Stud):235927:4 | Second Floor | Pset_WallCommon - Reference: Basic Wall:Interior - Partition (92mm Stud); LoadBearing: no; ExtendToStructure: no; IsExternal: no; PSet_Revit_Constraints - Location Line: 2; Base Constraint: Second Floor; Base Offset: 0 m; Base is Attached: no; Base Extension Distance: 0 m; Top Constraint: Up to level: Roof - Main; Unconnected Height: 4.578 m; Top Offset: -0.102 m; Top is Attached: no; Top Extension Distance: 0 m; Room Bounding: yes; Related to Mass: no; PSet_Revit_Other - InstallationDate: InstallationDate; SerialNumber: SerialNumber; WarrantyStartDate: WarrantyStartDate; BarCode: BarCode; AssetIdentifier: AssetIdentifier; TagNumber: TagNumber; PSet_Revit_Phasing - Phase Created: New Construction; PSet_Revit_Structural - Structural Usage: 0; PSet_Revit_Dimensions - Length: 32.32 m; Area: 127.04 m2; Volume: 15.7529 m3; PSet_Revit_Type_Construction - Wrapping at Inserts: 0; Wrapping at Ends: 2; Width: 0.124 m; Function: 0; PSet_Revit_Type_Graphics - Coarse Scale Fill Color: 0; PSet_Revit_Type_Identity Data - Manufacturer: Manufacturer; PSet_Revit_Type_Other - AccessibilityPerformance: AccessibilityPerformance; CodePerformance: CodePerformance; Color: Color; Constituents: Constituents; Features: Features; Finish: Finish; Grade: Grade; Material: Material; ModelReference: ModelReference; NominalHeight: NominalHeight; NominalLength: NominalLength; NominalWidth: NominalWidth; ProductionYear: ProductionYear; Reference: Reference; Shape: Shape; Size: Size; SustainabilityPerformance: SustainabilityPerformance; WarrantyDescription: WarrantyDescription; WarrantyDurationLabor: WarrantyDurationLabor; WarrantyDurationParts: WarrantyDurationParts; WarrantyGuarantorLabor: WarrantyGuarantorLabor; WarrantyGuarantorParts: WarrantyGuarantorParts; ExpectedLife: ExpectedLife; ReplacementCost: ReplacementCost; AssetAccountingType: FIXED; Classification Code: 23-25 40 11 11 11; Classification Description: Metal-Framed Gypsum Board Fixed Partitions; ModelLabel: ModelLabel
Basic Wall:Interior - Partition (92mm Stud):235927:5 | Second Floor | Pset_WallCommon - Reference: Basic Wall:Interior - Partition (92mm Stud); LoadBearing: no; ExtendToStructure: no; IsExternal: no; PSet_Revit_Constraints - Location Line: 2; Base Constraint: Second Floor; Base Offset: 0 m; Base is Attached: no; Base Extension Distance: 0 m; Top Constraint: Up to level: Roof - Main; Unconnected Height: 4.578 m; Top Offset: -0.102 m; Top is Attached: no; Top Extension Distance: 0 m; Room Bounding: yes; Related to Mass: no; PSet_Revit_Other - InstallationDate: InstallationDate; SerialNumber: SerialNumber; WarrantyStartDate: WarrantyStartDate; BarCode: BarCode; AssetIdentifier: AssetIdentifier; TagNumber: TagNumber; PSet_Revit_Phasing - Phase Created: New Construction; PSet_Revit_Structural - Structural Usage: 0; PSet_Revit_Dimensions - Length: 32.32 m; Area: 127.04 m2; Volume: 15.7529 m3; PSet_Revit_Type_Construction - Wrapping at Inserts: 0; Wrapping at Ends: 2; Width: 0.124 m; Function: 0; PSet_Revit_Type_Graphics - Coarse Scale Fill Color: 0; PSet_Revit_Type_Identity Data - Manufacturer: Manufacturer; PSet_Revit_Type_Other - AccessibilityPerformance: AccessibilityPerformance; CodePerformance: CodePerformance; Color: Color; Constituents: Constituents; Features: Features; Finish: Finish; Grade: Grade; Material: Material; ModelReference: ModelReference; NominalHeight: NominalHeight; NominalLength: NominalLength; NominalWidth: NominalWidth; ProductionYear: ProductionYear; Reference: Reference; Shape: Shape; Size: Size; SustainabilityPerformance: SustainabilityPerformance; WarrantyDescription: WarrantyDescription; WarrantyDurationLabor: WarrantyDurationLabor; WarrantyDurationParts: WarrantyDurationParts; WarrantyGuarantorLabor: WarrantyGuarantorLabor; WarrantyGuarantorParts: WarrantyGuarantorParts; ExpectedLife: ExpectedLife; ReplacementCost: ReplacementCost; AssetAccountingType: FIXED; Classification Code: 23-25 40 11 11 11; Classification Description: Metal-Framed Gypsum Board Fixed Partitions; ModelLabel: ModelLabel
Basic Wall:Interior - Partition (92mm Stud):235927:6 | Second Floor | Pset_WallCommon - Reference: Basic Wall:Interior - Partition (92mm Stud); LoadBearing: no; ExtendToStructure: no; IsExternal: no; PSet_Revit_Constraints - Location Line: 2; Base Constraint: Second Floor; Base Offset: 0 m; Base is Attached: no; Base Extension Distance: 0 m; Top Constraint: Up to level: Roof - Main; Unconnected Height: 4.578 m; Top Offset: -0.102 m; Top is Attached: no; Top Extension Distance: 0 m; Room Bounding: yes; Related to Mass: no; PSet_Revit_Other - InstallationDate: InstallationDate; SerialNumber: SerialNumber; WarrantyStartDate: WarrantyStartDate; BarCode: BarCode; AssetIdentifier: AssetIdentifier; TagNumber: TagNumber; PSet_Revit_Phasing - Phase Created: New Construction; PSet_Revit_Structural - Structural Usage: 0; PSet_Revit_Dimensions - Length: 32.32 m; Area: 127.04 m2; Volume: 15.7529 m3; PSet_Revit_Type_Construction - Wrapping at Inserts: 0; Wrapping at Ends: 2; Width: 0.124 m; Function: 0; PSet_Revit_Type_Graphics - Coarse Scale Fill Color: 0; PSet_Revit_Type_Identity Data - Manufacturer: Manufacturer; PSet_Revit_Type_Other - AccessibilityPerformance: AccessibilityPerformance; CodePerformance: CodePerformance; Color: Color; Constituents: Constituents; Features: Features; Finish: Finish; Grade: Grade; Material: Material; ModelReference: ModelReference; NominalHeight: NominalHeight; NominalLength: NominalLength; NominalWidth: NominalWidth; ProductionYear: ProductionYear; Reference: Reference; Shape: Shape; Size: Size; SustainabilityPerformance: SustainabilityPerformance; WarrantyDescription: WarrantyDescription; WarrantyDurationLabor: WarrantyDurationLabor; WarrantyDurationParts: WarrantyDurationParts; WarrantyGuarantorLabor: WarrantyGuarantorLabor; WarrantyGuarantorParts: WarrantyGuarantorParts; ExpectedLife: ExpectedLife; ReplacementCost: ReplacementCost; AssetAccountingType: FIXED; Classification Code: 23-25 40 11 11 11; Classification Description: Metal-Framed Gypsum Board Fixed Partitions; ModelLabel: ModelLabel
Basic Wall:Interior - Partition (92mm Stud):235927:7 | Second Floor | Pset_WallCommon - Reference: Basic Wall:Interior - Partition (92mm Stud); LoadBearing: no; ExtendToStructure: no; IsExternal: no; PSet_Revit_Constraints - Location Line: 2; Base Constraint: Second Floor; Base Offset: 0 m; Base is Attached: no; Base Extension Distance: 0 m; Top Constraint: Up to level: Roof - Main; Unconnected Height: 4.578 m; Top Offset: -0.102 m; Top is Attached: no; Top Extension Distance: 0 m; Room Bounding: yes; Related to Mass: no; PSet_Revit_Other - InstallationDate: InstallationDate; SerialNumber: SerialNumber; WarrantyStartDate: WarrantyStartDate; BarCode: BarCode; AssetIdentifier: AssetIdentifier; TagNumber: TagNumber; PSet_Revit_Phasing - Phase Created: New Construction; PSet_Revit_Structural - Structural Usage: 0; PSet_Revit_Dimensions - Length: 32.32 m; Area: 127.04 m2; Volume: 15.7529 m3; PSet_Revit_Type_Construction - Wrapping at Inserts: 0; Wrapping at Ends: 2; Width: 0.124 m; Function: 0; PSet_Revit_Type_Graphics - Coarse Scale Fill Color: 0; PSet_Revit_Type_Identity Data - Manufacturer: Manufacturer; PSet_Revit_Type_Other - AccessibilityPerformance: AccessibilityPerformance; CodePerformance: CodePerformance; Color: Color; Constituents: Constituents; Features: Features; Finish: Finish; Grade: Grade; Material: Material; ModelReference: ModelReference; NominalHeight: NominalHeight; NominalLength: NominalLength; NominalWidth: NominalWidth; ProductionYear: ProductionYear; Reference: Reference; Shape: Shape; Size: Size; SustainabilityPerformance: SustainabilityPerformance; WarrantyDescription: WarrantyDescription; WarrantyDurationLabor: WarrantyDurationLabor; WarrantyDurationParts: WarrantyDurationParts; WarrantyGuarantorLabor: WarrantyGuarantorLabor; WarrantyGuarantorParts: WarrantyGuarantorParts; ExpectedLife: ExpectedLife; ReplacementCost: ReplacementCost; AssetAccountingType: FIXED; Classification Code: 23-25 40 11 11 11; Classification Description: Metal-Framed Gypsum Board Fixed Partitions; ModelLabel: ModelLabel
M_Single-Flush:0915 x 2134mm:0915 x 2134mm:236673:1 | Second Floor
M_Single-Flush:0915 x 2134mm:0915 x 2134mm:236780:1 | Second Floor
M_Single-Flush:0915 x 2134mm:0915 x 2134mm:236819:1 | Second Floor
M_Single-Flush:0915 x 2134mm:0915 x 2134mm:236858:1 | Second Floor
M_Single-Flush:0915 x 2134mm:0915 x 2134mm:236916:1 | Second Floor
M_Single-Flush:0915 x 2134mm:0915 x 2134mm:236942:1 | Second Floor
M_Single-Flush:0915 x 2134mm:0915 x 2134mm:236966:1 | Second Floor
M_Single-Flush:0915 x 2134mm:0915 x 2134mm:237063:1 | Second Floor
M_Single-Flush:0915 x 2134mm:0915 x 2134mm:237102:1 | Second Floor
M_Single-Flush:0915 x 2134mm:0915 x 2134mm:237365:1 | Second Floor
M_Single-Flush:0915 x 2134mm:0915 x 2134mm:237452:1 | Second Floor
M_Single-Flush:0915 x 2134mm:0915 x 2134mm:237743:1 | Second Floor
M_Single-Flush:0915 x 2134mm:0915 x 2134mm:237881:1 | Second Floor
M_Single-Flush:0915 x 2134mm:0915 x 2134mm:237928:1 | Second Floor
M_Single-Flush:0915 x 2134mm:0915 x 2134mm:238011:1 | Second Floor
M_Single-Flush:0915 x 2134mm:0915 x 2134mm:238096:1 | Second Floor
M_Single-Flush:0915 x 2134mm:0915 x 2134mm:238171:1 | Second Floor
M_Single-Flush:0915 x 2134mm:0915 x 2134mm:238499:1 | Second Floor
M_Single-Flush:0915 x 2134mm:0915 x 2134mm:238538:1 | Second Floor
M_Single-Flush:0915 x 2134mm:0915 x 2134mm:238617:1 | Second Floor
M_Single-Flush:0915 x 2134mm:0915 x 2134mm:238748:1 | Second Floor
M_Single-Flush:0915 x 2134mm:0915 x 2134mm:238815:1 | Second Floor
M_Single-Flush:0915 x 2134mm:0915 x 2134mm:238886:1 | Second Floor
M_Single-Flush:0915 x 2134mm:0915 x 2134mm:238921:1 | Second Floor
M_Single-Flush:0915 x 2134mm:0915 x 2134mm:239113:1 | Second Floor
M_Single-Flush:0915 x 2134mm:0915 x 2134mm:239186:1 | Second Floor
M_Single-Flush:0915 x 2134mm:0915 x 2134mm:239241:1 | Second Floor
M_Single-Flush:0915 x 2134mm:0915 x 2134mm:239326:1 | Second Floor
M_Single-Flush:0915 x 2134mm:0915 x 2134mm:239383:1 | Second Floor
M_Single-Flush:0915 x 2134mm:0915 x 2134mm:239432:1 | Second Floor
M_Single-Flush:0915 x 2134mm:0915 x 2134mm:239511:1 | Second Floor
M_Single-Flush:0915 x 2134mm:0915 x 2134mm:239590:1 | Second Floor
M_Single-Flush:0915 x 2134mm:0915 x 2134mm:239639:1 | Second Floor
M_Single-Flush:0915 x 2134mm:0915 x 2134mm:239694:1 | Second Floor
M_Single-Flush:0915 x 2134mm:0915 x 2134mm:239799:1 | Second Floor
M_Single-Flush:0915 x 2134mm:0915 x 2134mm:239888:1 | Second Floor
M_Single-Flush:0915 x 2134mm:0915 x 2134mm:240003:1 | Second Floor
M_Single-Flush:0915 x 2134mm:0915 x 2134mm:240310:1 | Second Floor
M_Single-Flush:0915 x 2134mm:0915 x 2134mm:240347:1 | Second Floor
M_Single-Flush:0915 x 2134mm:0915 x 2134mm:240436:1 | Second Floor
M_Single-Flush:0915 x 2134mm:0915 x 2134mm:240501:1 | Second Floor
M_Single-Flush:0915 x 2134mm:0915 x 2134mm:240588:1 | Second Floor
M_Single-Flush:0915 x 2134mm:0915 x 2134mm:240676:1 | Second Floor
M_Single-Flush:0915 x 2134mm:0915 x 2134mm:240742:1 | Second Floor
M_Single-Flush:0915 x 2134mm:0915 x 2134mm:240845:1 | Second Floor
M_Single-Flush:0915 x 2134mm:0915 x 2134mm:240928:1 | Second Floor
M_Single-Flush:0915 x 2134mm:0915 x 2134mm:241049:1 | Second Floor
M_Single-Flush:0915 x 2134mm:0915 x 2134mm:241124:1 | Second Floor
M_Single-Flush:0915 x 2134mm:0915 x 2134mm:241191:1 | Second Floor
M_Single-Flush:0915 x 2134mm:0915 x 2134mm:241266:1 | Second Floor
M_Single-Flush:0915 x 2134mm:0915 x 2134mm:241581:1 | Second Floor
M_Single-Flush:0915 x 2134mm:0915 x 2134mm:241616:1 | Second Floor
M_Single-Flush:0915 x 2134mm:0915 x 2134mm:241681:1 | Second Floor
M_Single-Flush:0915 x 2134mm:0915 x 2134mm:241748:1 | Second Floor
M_Single-Flush:0915 x 2134mm:0915 x 2134mm:241789:1 | Second Floor
M_Single-Flush:0915 x 2134mm:0915 x 2134mm:241822:1 | Second Floor
M_Single-Flush:0915 x 2134mm:0915 x 2134mm:241869:1 | Second Floor
M_Single-Flush:0915 x 2134mm:0915 x 2134mm:241966:1 | Second Floor
M_Single-Flush:0915 x 2134mm:0915 x 2134mm:242003:1 | Second Floor
M_Single-Flush:0915 x 2134mm:0915 x 2134mm:242080:1 | Second Floor
M_Single-Flush:0915 x 2134mm Rated:0915 x 2134mm Rated:242185:1 | Second Floor
M_Single-Flush:0915 x 2134mm:0915 x 2134mm:242262:1 | Second Floor
M_Single-Flush:0915 x 2134mm:0915 x 2134mm:242319:1 | Second Floor
M_Double-Flush:1830 x 2134mm:1830 x 2134mm:250360:1 | Second Floor
M_Single-Flush:0915 x 2134mm:0915 x 2134mm:250444:1 | Second Floor
M_Single-Flush:0915 x 2134mm:0915 x 2134mm:250515:1 | Second Floor
M_Single-Flush:0915 x 2134mm:0915 x 2134mm:250602:1 | Second Floor
M_Double-Flush:1830 x 2134mm Exterior:1830 x 2134mm Exterior:252102:1 | First Floor
M_Double-Flush:1830 x 2134mm Exterior:1830 x 2134mm Exterior:252224:1 | First Floor
M_Single-Flush:0915 x 2134mm Exterior:0915 x 2134mm Exterior:252441:1 | First Floor
M_Single-Flush:0915 x 2134mm Exterior:0915 x 2134mm Exterior:252490:1 | First Floor
M_Double-Flush:1830 x 2134mm Exterior:1830 x 2134mm Exterior:252860:1 | First Floor
M_Fixed:1735 x 1000mm:1735 x 1000mm:253076:1 | First Floor
M_Fixed:1735 x 1000mm:1735 x 1000mm:253332:1 | First Floor
M_Fixed:1735 x 1000mm:1735 x 1000mm:253561:1 | First Floor
M_Fixed:1735 x 1000mm:1735 x 1000mm:253704:1 | First Floor
M_Fixed:1735 x 1000mm:1735 x 1000mm:253943:1 | First Floor
M_Fixed:1735 x 1000mm:1735 x 1000mm:254052:1 | First Floor
M_Fixed:1735 x 1000mm:1735 x 1000mm:254105:1 | First Floor
M_Fixed:1735 x 1000mm:1735 x 1000mm:254158:1 | First Floor
M_Fixed:1735 x 1000mm:1735 x 1000mm:254526:1 | First Floor
M_Fixed:1735 x 1000mm:1735 x 1000mm:254583:1 | First Floor
M_Fixed:1735 x 1000mm:1735 x 1000mm:254638:1 | First Floor
M_Fixed:1735 x 1000mm:1735 x 1000mm:254683:1 | First Floor
M_Fixed:1735 x 1000mm:1735 x 1000mm:254752:1 | First Floor
M_Fixed:1735 x 1000mm:1735 x 1000mm:259285:1 | Second Floor
M_Fixed:1735 x 1000mm:1735 x 1000mm:259348:1 | Second Floor
M_Fixed:1735 x 1000mm:1735 x 1000mm:259543:1 | Second Floor
M_Fixed:1735 x 1000mm:1735 x 1000mm:259606:1 | Second Floor
M_Fixed:1735 x 1000mm:1735 x 1000mm:259767:1 | Second Floor
M_Fixed:1735 x 1000mm:1735 x 1000mm:259922:1 | Second Floor
M_Fixed:1735 x 1000mm:1735 x 1000mm:260015:1 | Second Floor
M_Fixed:1735 x 1000mm:1735 x 1000mm:260209:1 | Second Floor
M_Fixed:1735 x 1000mm:1735 x 1000mm:260236:1 | Second Floor
M_Fixed:1735 x 1000mm:1735 x 1000mm:260343:1 | Second Floor
M_Fixed:1735 x 1000mm:1735 x 1000mm:260452:1 | Second Floor
M_Fixed:1735 x 1000mm:1735 x 1000mm:260595:1 | Second Floor
M_Fixed:1735 x 1000mm:1735 x 1000mm:260718:1 | Second Floor
M_Fixed:1735 x 1000mm:1735 x 1000mm:260833:1 | Second Floor
M_Fixed:1735 x 1000mm:1735 x 1000mm:260974:1 | Second Floor
M_Fixed:1735 x 1000mm:1735 x 1000mm:261025:1 | Second Floor
M_Fixed:1735 x 1000mm:1735 x 1000mm:261080:1 | Second Floor
M_Fixed:1735 x 1000mm:1735 x 1000mm:261135:1 | Second Floor
M_Fixed:1735 x 1000mm:1735 x 1000mm:261220:1 | Second Floor
M_Fixed:1735 x 1000mm:1735 x 1000mm:261267:1 | Second Floor
M_Fixed:1735 x 1000mm:1735 x 1000mm:261370:1 | Second Floor
M_Fixed:1735 x 1000mm:1735 x 1000mm:261427:1 | Second Floor
M_Fixed:1735 x 1000mm:1735 x 1000mm:261484:1 | Second Floor
M_Fixed:1735 x 1000mm:1735 x 1000mm:261527:1 | Second Floor
M_Fixed:1735 x 1000mm:1735 x 1000mm:261584:1 | Second Floor
M_Fixed:1735 x 1000mm:1735 x 1000mm:261637:1 | Second Floor
M_Fixed:1735 x 1000mm:1735 x 1000mm:261760:1 | Second Floor
M_Fixed:1735 x 1000mm:1735 x 1000mm:261827:1 | Second Floor
M_Fixed:1735 x 1000mm:1735 x 1000mm:261874:1 | Second Floor
M_Fixed:1735 x 1000mm:1735 x 1000mm:261927:1 | Second Floor
M_Fixed:1735 x 1000mm:1735 x 1000mm:261994:1 | Second Floor
M_Fixed:1735 x 1000mm:1735 x 1000mm:262059:1 | Second Floor
M_Fixed:1735 x 1000mm:1735 x 1000mm:262138:1 | Second Floor
M_Fixed:1735 x 1000mm:1735 x 1000mm:262496:1 | Second Floor
M_Fixed:1735 x 1000mm:1735 x 1000mm:262576:1 | Second Floor
M_Fixed:1735 x 1000mm:1735 x 1000mm:262643:1 | Second Floor
Basic Wall:Interior - Partition (92mm Stud):287482:2 | Second Floor | Pset_WallCommon - Reference: Basic Wall:Interior - Partition (92mm Stud); LoadBearing: no; ExtendToStructure: no; IsExternal: no; PSet_Revit_Constraints - Location Line: 2; Base Constraint: Second Floor; Base Offset: 0 m; Base is Attached: no; Base Extension Distance: 0 m; Top Constraint: Up to level: Second Floor; Unconnected Height: 3 m; Top Offset: 3 m; Top is Attached: no; Top Extension Distance: 0 m; Room Bounding: yes; Related to Mass: no; PSet_Revit_Other - InstallationDate: InstallationDate; SerialNumber: SerialNumber; WarrantyStartDate: WarrantyStartDate; BarCode: BarCode; AssetIdentifier: AssetIdentifier; TagNumber: TagNumber; PSet_Revit_Phasing - Phase Created: New Construction; PSet_Revit_Structural - Structural Usage: 0; PSet_Revit_Dimensions - Length: 1.0798 m; Area: 2.23771 m2; Volume: 0.277476 m3; PSet_Revit_Type_Construction - Wrapping at Inserts: 0; Wrapping at Ends: 2; Width: 0.124 m; Function: 0; PSet_Revit_Type_Graphics - Coarse Scale Fill Color: 0; PSet_Revit_Type_Identity Data - Manufacturer: Manufacturer; PSet_Revit_Type_Other - AccessibilityPerformance: AccessibilityPerformance; CodePerformance: CodePerformance; Color: Color; Constituents: Constituents; Features: Features; Finish: Finish; Grade: Grade; Material: Material; ModelReference: ModelReference; NominalHeight: NominalHeight; NominalLength: NominalLength; NominalWidth: NominalWidth; ProductionYear: ProductionYear; Reference: Reference; Shape: Shape; Size: Size; SustainabilityPerformance: SustainabilityPerformance; WarrantyDescription: WarrantyDescription; WarrantyDurationLabor: WarrantyDurationLabor; WarrantyDurationParts: WarrantyDurationParts; WarrantyGuarantorLabor: WarrantyGuarantorLabor; WarrantyGuarantorParts: WarrantyGuarantorParts; ExpectedLife: ExpectedLife; ReplacementCost: ReplacementCost; AssetAccountingType: FIXED; Classification Code: 23-25 40 11 11 11; Classification Description: Metal-Framed Gypsum Board Fixed Partitions; ModelLabel: ModelLabel
 | Second Floor | Pset_WallCommon - Reference: Basic Wall:Interior - Partition (92mm Stud); LoadBearing: no; ExtendToStructure: no; IsExternal: no; PSet_Revit_Constraints - Location Line: 0; Base Constraint: Second Floor; Base Offset: 0 m; Base is Attached: no; Base Extension Distance: 0 m; Top Constraint: Up to level: Roof - Main; Unconnected Height: 4.578 m; Top Offset: -0.102 m; Top is Attached: no; Top Extension Distance: 0 m; Room Bounding: yes; Related to Mass: no; PSet_Revit_Other - InstallationDate: InstallationDate; SerialNumber: SerialNumber; WarrantyStartDate: WarrantyStartDate; BarCode: BarCode; AssetIdentifier: AssetIdentifier; TagNumber: TagNumber; PSet_Revit_Phasing - Phase Created: New Construction; PSet_Revit_Structural - Structural Usage: 0; PSet_Revit_Dimensions - Length: 6.16325 m; Area: 16.1127 m2; Volume: 1.99797 m3; PSet_Revit_Type_Construction - Wrapping at Inserts: 0; Wrapping at Ends: 2; Width: 0.124 m; Function: 0; PSet_Revit_Type_Graphics - Coarse Scale Fill Color: 0; PSet_Revit_Type_Identity Data - Manufacturer: Manufacturer; PSet_Revit_Type_Other - AccessibilityPerformance: AccessibilityPerformance; CodePerformance: CodePerformance; Color: Color; Constituents: Constituents; Features: Features; Finish: Finish; Grade: Grade; Material: Material; ModelReference: ModelReference; NominalHeight: NominalHeight; NominalLength: NominalLength; NominalWidth: NominalWidth; ProductionYear: ProductionYear; Reference: Reference; Shape: Shape; Size: Size; SustainabilityPerformance: SustainabilityPerformance; WarrantyDescription: WarrantyDescription; WarrantyDurationLabor: WarrantyDurationLabor; WarrantyDurationParts: WarrantyDurationParts; WarrantyGuarantorLabor: WarrantyGuarantorLabor; WarrantyGuarantorParts: WarrantyGuarantorParts; ExpectedLife: ExpectedLife; ReplacementCost: ReplacementCost; AssetAccountingType: FIXED; Classification Code: 23-25 40 11 11 11; Classification Description: Metal-Framed Gypsum Board Fixed Partitions; ModelLabel: ModelLabel
Basic Wall:Exterior - Insul Panel on Mtl. Stud:290066:2 | Second Floor | Pset_WallCommon - Reference: Basic Wall:Exterior - Insul Panel on Mtl. Stud; LoadBearing: no; ExtendToStructure: no; IsExternal: yes; PSet_Revit_Constraints - Location Line: 2; Base Constraint: Second Floor; Base Offset: 3.4865 m; Base is Attached: no; Base Extension Distance: 0 m; Top Constraint: Up to level: Roof - Main; Unconnected Height: 1.6505 m; Top Offset: 0.457 m; Top is Attached: no; Top Extension Distance: 0 m; Room Bounding: yes; Related to Mass: no; PSet_Revit_Other - InstallationDate: InstallationDate; SerialNumber: SerialNumber; WarrantyStartDate: WarrantyStartDate; BarCode: BarCode; AssetIdentifier: AssetIdentifier; TagNumber: TagNumber; PSet_Revit_Phasing - Phase Created: New Construction; PSet_Revit_Structural - Structural Usage: 0; PSet_Revit_Dimensions - Length: 15.343 m; Area: 26.423 m2; Volume: 7.05495 m3; PSet_Revit_Type_Construction - Wrapping at Inserts: 0; Wrapping at Ends: 1; Width: 0.267 m; Function: 1; PSet_Revit_Type_Graphics - Coarse Scale Fill Color: 0; PSet_Revit_Type_Identity Data - Manufacturer: Manufacturer; PSet_Revit_Type_Other - AccessibilityPerformance: AccessibilityPerformance; CodePerformance: CodePerformance; Color: Color; Constituents: Constituents; Features: Features; Finish: Finish; Grade: Grade; Material: Material; ModelReference: ModelReference; NominalHeight: NominalHeight; NominalLength: NominalLength; NominalWidth: NominalWidth; ProductionYear: ProductionYear; Reference: Reference; Shape: Shape; Size: Size; SustainabilityPerformance: SustainabilityPerformance; WarrantyDescription: WarrantyDescription; WarrantyDurationLabor: WarrantyDurationLabor; WarrantyDurationParts: WarrantyDurationParts; WarrantyGuarantorLabor: WarrantyGuarantorLabor; WarrantyGuarantorParts: WarrantyGuarantorParts; ExpectedLife: ExpectedLife; ReplacementCost: ReplacementCost; AssetAccountingType: FIXED; Classification Code: 23-25 30 24 21; Classification Description: Metal Framed Structural Walls; ModelLabel: ModelLabel
Basic Wall:Exterior - Insul Panel on Mtl. Stud:293670:2 | Second Floor | Pset_WallCommon - Reference: Basic Wall:Exterior - Insul Panel on Mtl. Stud; LoadBearing: no; ExtendToStructure: no; IsExternal: yes; PSet_Revit_Constraints - Location Line: 2; Base Constraint: Second Floor; Base Offset: 0 m; Base is Attached: no; Base Extension Distance: 0 m; Top Constraint: Up to level: Second Floor; Unconnected Height: 2.64 m; Top Offset: 2.64 m; Top is Attached: no; Top Extension Distance: 0 m; Room Bounding: yes; Related to Mass: no; PSet_Revit_Other - InstallationDate: InstallationDate; SerialNumber: SerialNumber; WarrantyStartDate: WarrantyStartDate; BarCode: BarCode; AssetIdentifier: AssetIdentifier; TagNumber: TagNumber; PSet_Revit_Phasing - Phase Created: New Construction; PSet_Revit_Structural - Structural Usage: 0; PSet_Revit_Dimensions - Length: 2.7445 m; Area: 7.41764 m2; Volume: 1.98051 m3; PSet_Revit_Type_Construction - Wrapping at Inserts: 0; Wrapping at Ends: 1; Width: 0.267 m; Function: 1; PSet_Revit_Type_Graphics - Coarse Scale Fill Color: 0; PSet_Revit_Type_Identity Data - Manufacturer: Manufacturer; PSet_Revit_Type_Other - AccessibilityPerformance: AccessibilityPerformance; CodePerformance: CodePerformance; Color: Color; Constituents: Constituents; Features: Features; Finish: Finish; Grade: Grade; Material: Material; ModelReference: ModelReference; NominalHeight: NominalHeight; NominalLength: NominalLength; NominalWidth: NominalWidth; ProductionYear: ProductionYear; Reference: Reference; Shape: Shape; Size: Size; SustainabilityPerformance: SustainabilityPerformance; WarrantyDescription: WarrantyDescription; WarrantyDurationLabor: WarrantyDurationLabor; WarrantyDurationParts: WarrantyDurationParts; WarrantyGuarantorLabor: WarrantyGuarantorLabor; WarrantyGuarantorParts: WarrantyGuarantorParts; ExpectedLife: ExpectedLife; ReplacementCost: ReplacementCost; AssetAccountingType: FIXED; Classification Code: 23-25 30 24 21; Classification Description: Metal Framed Structural Walls; ModelLabel: ModelLabel
6 x  | Roof - Main | Pset_WallCommon - Reference: Basic Wall:Exterior - Insul Panel on Mtl. Stud; LoadBearing: no; ExtendToStructure: no; IsExternal: yes; PSet_Revit_Constraints - Location Line: 2; Base Constraint: Roof - Main; Base Offset: 0 m; Base is Attached: no; Base Extension Distance: 0 m; Top Constraint: Up to level: Roof - Main; Unconnected Height: 3.4 m; Top Offset: 3.4 m; Top is Attached: no; Top Extension Distance: 0 m; Room Bounding: yes; Related to Mass: no; PSet_Revit_Other - InstallationDate: InstallationDate; SerialNumber: SerialNumber; WarrantyStartDate: WarrantyStartDate; BarCode: BarCode; AssetIdentifier: AssetIdentifier; TagNumber: TagNumber; PSet_Revit_Phasing - Phase Created: New Construction; PSet_Revit_Structural - Structural Usage: 0; PSet_Revit_Dimensions - Length: 18.4025 m; Area: 31.9269 m2; Volume: 8.52447 m3; PSet_Revit_Type_Construction - Wrapping at Inserts: 0; Wrapping at Ends: 1; Width: 0.267 m; Function: 1; PSet_Revit_Type_Graphics - Coarse Scale Fill Color: 0; PSet_Revit_Type_Identity Data - Manufacturer: Manufacturer; PSet_Revit_Type_Other - AccessibilityPerformance: AccessibilityPerformance; CodePerformance: CodePerformance; Color: Color; Constituents: Constituents; Features: Features; Finish: Finish; Grade: Grade; Material: Material; ModelReference: ModelReference; NominalHeight: NominalHeight; NominalLength: NominalLength; NominalWidth: NominalWidth; ProductionYear: ProductionYear; Reference: Reference; Shape: Shape; Size: Size; SustainabilityPerformance: SustainabilityPerformance; WarrantyDescription: WarrantyDescription; WarrantyDurationLabor: WarrantyDurationLabor; WarrantyDurationParts: WarrantyDurationParts; WarrantyGuarantorLabor: WarrantyGuarantorLabor; WarrantyGuarantorParts: WarrantyGuarantorParts; ExpectedLife: ExpectedLife; ReplacementCost: ReplacementCost; AssetAccountingType: FIXED; Classification Code: 23-25 30 24 21; Classification Description: Metal Framed Structural Walls; ModelLabel: ModelLabel
Basic Wall:Exterior - Insul Panel on Mtl. Stud:309999:2 | Roof - Main | Pset_WallCommon - Reference: Basic Wall:Exterior - Insul Panel on Mtl. Stud; LoadBearing: no; ExtendToStructure: no; IsExternal: yes; PSet_Revit_Constraints - Location Line: 2; Base Constraint: Roof - Main; Base Offset: 0 m; Base is Attached: no; Base Extension Distance: 0 m; Top Constraint: Up to level: Roof - Main; Unconnected Height: 3.4 m; Top Offset: 3.4 m; Top is Attached: no; Top Extension Distance: 0 m; Room Bounding: yes; Related to Mass: no; PSet_Revit_Other - InstallationDate: InstallationDate; SerialNumber: SerialNumber; WarrantyStartDate: WarrantyStartDate; BarCode: BarCode; AssetIdentifier: AssetIdentifier; TagNumber: TagNumber; PSet_Revit_Phasing - Phase Created: New Construction; PSet_Revit_Structural - Structural Usage: 0; PSet_Revit_Dimensions - Length: 18.4025 m; Area: 31.9269 m2; Volume: 8.52447 m3; PSet_Revit_Type_Construction - Wrapping at Inserts: 0; Wrapping at Ends: 1; Width: 0.267 m; Function: 1; PSet_Revit_Type_Graphics - Coarse Scale Fill Color: 0; PSet_Revit_Type_Identity Data - Manufacturer: Manufacturer; PSet_Revit_Type_Other - AccessibilityPerformance: AccessibilityPerformance; CodePerformance: CodePerformance; Color: Color; Constituents: Constituents; Features: Features; Finish: Finish; Grade: Grade; Material: Material; ModelReference: ModelReference; NominalHeight: NominalHeight; NominalLength: NominalLength; NominalWidth: NominalWidth; ProductionYear: ProductionYear; Reference: Reference; Shape: Shape; Size: Size; SustainabilityPerformance: SustainabilityPerformance; WarrantyDescription: WarrantyDescription; WarrantyDurationLabor: WarrantyDurationLabor; WarrantyDurationParts: WarrantyDurationParts; WarrantyGuarantorLabor: WarrantyGuarantorLabor; WarrantyGuarantorParts: WarrantyGuarantorParts; ExpectedLife: ExpectedLife; ReplacementCost: ReplacementCost; AssetAccountingType: FIXED; Classification Code: 23-25 30 24 21; Classification Description: Metal Framed Structural Walls; ModelLabel: ModelLabel
M_Counter Top w Sink Hole:600mm Depth:600mm Depth:330055:1 | 1E30 | PSet_Revit_Other - InstallationDate: InstallationDate; SerialNumber: SerialNumber; WarrantyStartDate: WarrantyStartDate; BarCode: BarCode; AssetIdentifier: AssetIdentifier; TagNumber: TagNumber; PSet_Revit_Phasing - Phase Created: New Construction; PSet_Revit_Dimensions - Length: 1.27 m; Sink Location: 0.351918 m; Sink Location To Wall: 0.1 m; Sink Opening Depth: 0.378 m; Sink Opening Width: 0.4826 m; PSet_Revit_Type_Identity Data - Manufacturer: Manufacturer; OmniClass Number: 23.40.35.17.47.11; OmniClass Title: Kitchen Casework; PSet_Revit_Type_Other - AccessibilityPerformance: AccessibilityPerformance; CodePerformance: CodePerformance; Color: Color; Constituents: Constituents; Features: Features; Finish: Finish; Grade: Grade; Material: Material; ModelReference: ModelReference; NominalHeight: NominalHeight; NominalLength: NominalLength; NominalWidth: NominalWidth; ProductionYear: ProductionYear; Reference: Reference; Shape: Shape; Size: Size; SustainabilityPerformance: SustainabilityPerformance; WarrantyDescription: WarrantyDescription; WarrantyDurationLabor: WarrantyDurationLabor; WarrantyDurationParts: WarrantyDurationParts; WarrantyGuarantorLabor: WarrantyGuarantorLabor; WarrantyGuarantorParts: WarrantyGuarantorParts; ExpectedLife: ExpectedLife; ReplacementCost: ReplacementCost; AssetAccountingType: FIXED; ModelLabel: ModelLabel; Area: Area; PSet_Revit_Constraints - Level: First Floor; Host: Level : First Floor; Offset: 0 m; Moves With Nearby Elements: no; PSet_Revit_Type_Dimensions - Counter Thickness: 0.04 m; Depth: 0.625 m; Height: 0.9 m; PSet_Revit_Type_Materials and Finishes - Finish: Finish; PSet_Revit_Type_Construction - Construction Type: Construction Type
M_Counter Top w Sink Hole:600mm Depth:600mm Depth:330800:1 | 1E16 | PSet_Revit_Other - InstallationDate: InstallationDate; SerialNumber: SerialNumber; WarrantyStartDate: WarrantyStartDate; BarCode: BarCode; AssetIdentifier: AssetIdentifier; TagNumber: TagNumber; PSet_Revit_Phasing - Phase Created: New Construction; PSet_Revit_Dimensions - Length: 1.21 m; Sink Location: 0.908082 m; Sink Location To Wall: 0.113 m; Sink Opening Depth: 0.403931 m; Sink Opening Width: 0.4826 m; PSet_Revit_Type_Identity Data - Manufacturer: Manufacturer; OmniClass Number: 23.40.35.17.47.11; OmniClass Title: Kitchen Casework; PSet_Revit_Type_Other - AccessibilityPerformance: AccessibilityPerformance; CodePerformance: CodePerformance; Color: Color; Constituents: Constituents; Features: Features; Finish: Finish; Grade: Grade; Material: Material; ModelReference: ModelReference; NominalHeight: NominalHeight; NominalLength: NominalLength; NominalWidth: NominalWidth; ProductionYear: ProductionYear; Reference: Reference; Shape: Shape; Size: Size; SustainabilityPerformance: SustainabilityPerformance; WarrantyDescription: WarrantyDescription; WarrantyDurationLabor: WarrantyDurationLabor; WarrantyDurationParts: WarrantyDurationParts; WarrantyGuarantorLabor: WarrantyGuarantorLabor; WarrantyGuarantorParts: WarrantyGuarantorParts; ExpectedLife: ExpectedLife; ReplacementCost: ReplacementCost; AssetAccountingType: FIXED; ModelLabel: ModelLabel; Area: Area; PSet_Revit_Constraints - Level: First Floor; Host: Level : First Floor; Offset: 0 m; Moves With Nearby Elements: no; PSet_Revit_Type_Dimensions - Counter Thickness: 0.04 m; Depth: 0.625 m; Height: 0.9 m; PSet_Revit_Type_Materials and Finishes - Finish: Finish; PSet_Revit_Type_Construction - Construction Type: Construction Type
M_Counter Top w Sink Hole:600mm Depth:600mm Depth:331805:1 | 1B10 | PSet_Revit_Other - InstallationDate: InstallationDate; SerialNumber: SerialNumber; WarrantyStartDate: WarrantyStartDate; BarCode: BarCode; AssetIdentifier: AssetIdentifier; TagNumber: TagNumber; PSet_Revit_Phasing - Phase Created: New Construction; PSet_Revit_Dimensions - Length: 1.81 m; Sink Location: 0.263836 m; Sink Location To Wall: 0.1 m; Sink Opening Depth: 0.378 m; Sink Opening Width: 0.31515 m; PSet_Revit_Type_Identity Data - Manufacturer: Manufacturer; OmniClass Number: 23.40.35.17.47.11; OmniClass Title: Kitchen Casework; PSet_Revit_Type_Other - AccessibilityPerformance: AccessibilityPerformance; CodePerformance: CodePerformance; Color: Color; Constituents: Constituents; Features: Features; Finish: Finish; Grade: Grade; Material: Material; ModelReference: ModelReference; NominalHeight: NominalHeight; NominalLength: NominalLength; NominalWidth: NominalWidth; ProductionYear: ProductionYear; Reference: Reference; Shape: Shape; Size: Size; SustainabilityPerformance: SustainabilityPerformance; WarrantyDescription: WarrantyDescription; WarrantyDurationLabor: WarrantyDurationLabor; WarrantyDurationParts: WarrantyDurationParts; WarrantyGuarantorLabor: WarrantyGuarantorLabor; WarrantyGuarantorParts: WarrantyGuarantorParts; ExpectedLife: ExpectedLife; ReplacementCost: ReplacementCost; AssetAccountingType: FIXED; ModelLabel: ModelLabel; Area: Area; PSet_Revit_Constraints - Level: First Floor; Host: Level : First Floor; Offset: 0 m; Moves With Nearby Elements: no; PSet_Revit_Type_Dimensions - Counter Thickness: 0.04 m; Depth: 0.625 m; Height: 0.9 m; PSet_Revit_Type_Materials and Finishes - Finish: Finish; PSet_Revit_Type_Construction - Construction Type: Construction Type
M_Counter Top w Sink Hole:600mm Depth:600mm Depth:338411:1 | 2C17 | PSet_Revit_Other - InstallationDate: InstallationDate; SerialNumber: SerialNumber; WarrantyStartDate: WarrantyStartDate; BarCode: BarCode; AssetIdentifier: AssetIdentifier; TagNumber: TagNumber; PSet_Revit_Phasing - Phase Created: New Construction; PSet_Revit_Dimensions - Length: 2.46715 m; Sink Location: 2.14329 m; Sink Location To Wall: 0.1 m; Sink Opening Depth: 0.378 m; Sink Opening Width: 0.587 m; PSet_Revit_Type_Identity Data - Manufacturer: Manufacturer; OmniClass Number: 23.40.35.17.47.11; OmniClass Title: Kitchen Casework; PSet_Revit_Type_Other - AccessibilityPerformance: AccessibilityPerformance; CodePerformance: CodePerformance; Color: Color; Constituents: Constituents; Features: Features; Finish: Finish; Grade: Grade; Material: Material; ModelReference: ModelReference; NominalHeight: NominalHeight; NominalLength: NominalLength; NominalWidth: NominalWidth; ProductionYear: ProductionYear; Reference: Reference; Shape: Shape; Size: Size; SustainabilityPerformance: SustainabilityPerformance; WarrantyDescription: WarrantyDescription; WarrantyDurationLabor: WarrantyDurationLabor; WarrantyDurationParts: WarrantyDurationParts; WarrantyGuarantorLabor: WarrantyGuarantorLabor; WarrantyGuarantorParts: WarrantyGuarantorParts; ExpectedLife: ExpectedLife; ReplacementCost: ReplacementCost; AssetAccountingType: FIXED; ModelLabel: ModelLabel; Area: Area; PSet_Revit_Constraints - Level: Second Floor; Host: Level : Second Floor; Offset: 0 m; Moves With Nearby Elements: no; PSet_Revit_Type_Dimensions - Counter Thickness: 0.04 m; Depth: 0.625 m; Height: 0.9 m; PSet_Revit_Type_Materials and Finishes - Finish: Finish; PSet_Revit_Type_Construction - Construction Type: Construction Type
M_Counter Top w Sink Hole:600mm Depth:600mm Depth:338826:1 | 2C17 | PSet_Revit_Other - InstallationDate: InstallationDate; SerialNumber: SerialNumber; WarrantyStartDate: WarrantyStartDate; BarCode: BarCode; AssetIdentifier: AssetIdentifier; TagNumber: TagNumber; PSet_Revit_Phasing - Phase Created: New Construction; PSet_Revit_Dimensions - Length: 4.69696 m; Sink Location: 0.36704 m; Sink Location To Wall: 0.1 m; Sink Opening Depth: 0.378 m; Sink Opening Width: 0.587 m; PSet_Revit_Type_Identity Data - Manufacturer: Manufacturer; OmniClass Number: 23.40.35.17.47.11; OmniClass Title: Kitchen Casework; PSet_Revit_Type_Other - AccessibilityPerformance: AccessibilityPerformance; CodePerformance: CodePerformance; Color: Color; Constituents: Constituents; Features: Features; Finish: Finish; Grade: Grade; Material: Material; ModelReference: ModelReference; NominalHeight: NominalHeight; NominalLength: NominalLength; NominalWidth: NominalWidth; ProductionYear: ProductionYear; Reference: Reference; Shape: Shape; Size: Size; SustainabilityPerformance: SustainabilityPerformance; WarrantyDescription: WarrantyDescription; WarrantyDurationLabor: WarrantyDurationLabor; WarrantyDurationParts: WarrantyDurationParts; WarrantyGuarantorLabor: WarrantyGuarantorLabor; WarrantyGuarantorParts: WarrantyGuarantorParts; ExpectedLife: ExpectedLife; ReplacementCost: ReplacementCost; AssetAccountingType: FIXED; ModelLabel: ModelLabel; Area: Area; PSet_Revit_Constraints - Level: Second Floor; Host: Level : Second Floor; Offset: 0 m; Moves With Nearby Elements: no; PSet_Revit_Type_Dimensions - Counter Thickness: 0.04 m; Depth: 0.625 m; Height: 0.9 m; PSet_Revit_Type_Materials and Finishes - Finish: Finish; PSet_Revit_Type_Construction - Construction Type: Construction Type
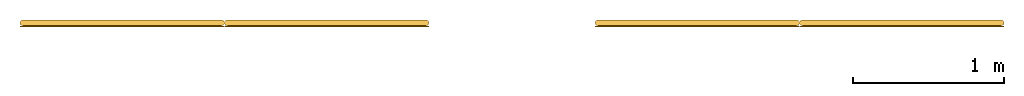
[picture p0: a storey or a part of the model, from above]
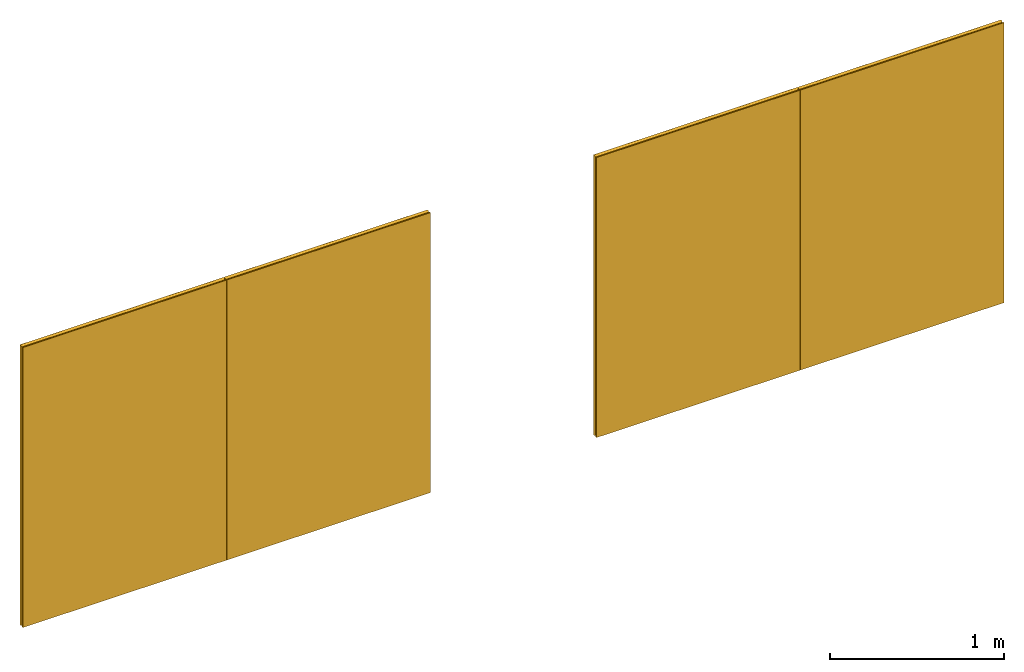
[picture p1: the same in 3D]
Properties of the parts of a building model (IFC2X3), part 7 of 11

# IfcOpeningElement: Opening (403)
Name | In
M_Counter Top w Sink Hole:600mm Depth:600mm Depth:341491:1 | 2C12 | PSet_Revit_Other - InstallationDate: InstallationDate; SerialNumber: SerialNumber; WarrantyStartDate: WarrantyStartDate; BarCode: BarCode; AssetIdentifier: AssetIdentifier; TagNumber: TagNumber; PSet_Revit_Phasing - Phase Created: New Construction; PSet_Revit_Dimensions - Length: 3.872 m; Sink Location: 1.03026 m; Sink Location To Wall: 0.1 m; Sink Opening Depth: 0.378 m; Sink Opening Width: 0.587 m; PSet_Revit_Type_Identity Data - Manufacturer: Manufacturer; OmniClass Number: 23.40.35.17.47.11; OmniClass Title: Kitchen Casework; PSet_Revit_Type_Other - AccessibilityPerformance: AccessibilityPerformance; CodePerformance: CodePerformance; Color: Color; Constituents: Constituents; Features: Features; Finish: Finish; Grade: Grade; Material: Material; ModelReference: ModelReference; NominalHeight: NominalHeight; NominalLength: NominalLength; NominalWidth: NominalWidth; ProductionYear: ProductionYear; Reference: Reference; Shape: Shape; Size: Size; SustainabilityPerformance: SustainabilityPerformance; WarrantyDescription: WarrantyDescription; WarrantyDurationLabor: WarrantyDurationLabor; WarrantyDurationParts: WarrantyDurationParts; WarrantyGuarantorLabor: WarrantyGuarantorLabor; WarrantyGuarantorParts: WarrantyGuarantorParts; ExpectedLife: ExpectedLife; ReplacementCost: ReplacementCost; AssetAccountingType: FIXED; ModelLabel: ModelLabel; Area: Area; PSet_Revit_Constraints - Level: Second Floor; Host: Level : Second Floor; Offset: 0 m; Moves With Nearby Elements: no; PSet_Revit_Type_Dimensions - Counter Thickness: 0.04 m; Depth: 0.625 m; Height: 0.9 m; PSet_Revit_Type_Materials and Finishes - Finish: Finish; PSet_Revit_Type_Construction - Construction Type: Construction Type
M_Counter Top w Sink Hole:600mm Depth:600mm Depth:342492:1 | 2C10 | PSet_Revit_Other - InstallationDate: InstallationDate; SerialNumber: SerialNumber; WarrantyStartDate: WarrantyStartDate; BarCode: BarCode; AssetIdentifier: AssetIdentifier; TagNumber: TagNumber; PSet_Revit_Phasing - Phase Created: New Construction; PSet_Revit_Dimensions - Length: 3.036 m; Sink Location: 1.346 m; Sink Location To Wall: 0.1 m; Sink Opening Depth: 0.378 m; Sink Opening Width: 0.587 m; PSet_Revit_Type_Identity Data - Manufacturer: Manufacturer; OmniClass Number: 23.40.35.17.47.11; OmniClass Title: Kitchen Casework; PSet_Revit_Type_Other - AccessibilityPerformance: AccessibilityPerformance; CodePerformance: CodePerformance; Color: Color; Constituents: Constituents; Features: Features; Finish: Finish; Grade: Grade; Material: Material; ModelReference: ModelReference; NominalHeight: NominalHeight; NominalLength: NominalLength; NominalWidth: NominalWidth; ProductionYear: ProductionYear; Reference: Reference; Shape: Shape; Size: Size; SustainabilityPerformance: SustainabilityPerformance; WarrantyDescription: WarrantyDescription; WarrantyDurationLabor: WarrantyDurationLabor; WarrantyDurationParts: WarrantyDurationParts; WarrantyGuarantorLabor: WarrantyGuarantorLabor; WarrantyGuarantorParts: WarrantyGuarantorParts; ExpectedLife: ExpectedLife; ReplacementCost: ReplacementCost; AssetAccountingType: FIXED; ModelLabel: ModelLabel; Area: Area; PSet_Revit_Constraints - Level: Second Floor; Host: Level : Second Floor; Offset: 0 m; Moves With Nearby Elements: no; PSet_Revit_Type_Dimensions - Counter Thickness: 0.04 m; Depth: 0.625 m; Height: 0.9 m; PSet_Revit_Type_Materials and Finishes - Finish: Finish; PSet_Revit_Type_Construction - Construction Type: Construction Type
M_Single-Flush:0915 x 2134mm:0915 x 2134mm:350102:1 | First Floor
M_Single-Flush:0915 x 2134mm:0915 x 2134mm:355218:1 | First Floor
M_Counter Top w Sink Hole:600mm Depth:600mm Depth:357065:1 | 1D22 | PSet_Revit_Other - InstallationDate: InstallationDate; SerialNumber: SerialNumber; WarrantyStartDate: WarrantyStartDate; BarCode: BarCode; AssetIdentifier: AssetIdentifier; TagNumber: TagNumber; PSet_Revit_Phasing - Phase Created: New Construction; PSet_Revit_Dimensions - Length: 3.05 m; Sink Location: 2.72545 m; Sink Location To Wall: 0.122044 m; Sink Opening Depth: 0.417956 m; Sink Opening Width: 0.4826 m; PSet_Revit_Type_Identity Data - Manufacturer: Manufacturer; OmniClass Number: 23.40.35.17.47.11; OmniClass Title: Kitchen Casework; PSet_Revit_Type_Other - AccessibilityPerformance: AccessibilityPerformance; CodePerformance: CodePerformance; Color: Color; Constituents: Constituents; Features: Features; Finish: Finish; Grade: Grade; Material: Material; ModelReference: ModelReference; NominalHeight: NominalHeight; NominalLength: NominalLength; NominalWidth: NominalWidth; ProductionYear: ProductionYear; Reference: Reference; Shape: Shape; Size: Size; SustainabilityPerformance: SustainabilityPerformance; WarrantyDescription: WarrantyDescription; WarrantyDurationLabor: WarrantyDurationLabor; WarrantyDurationParts: WarrantyDurationParts; WarrantyGuarantorLabor: WarrantyGuarantorLabor; WarrantyGuarantorParts: WarrantyGuarantorParts; ExpectedLife: ExpectedLife; ReplacementCost: ReplacementCost; AssetAccountingType: FIXED; ModelLabel: ModelLabel; Area: Area; PSet_Revit_Constraints - Level: First Floor; Host: Level : First Floor; Offset: 0 m; Moves With Nearby Elements: no; PSet_Revit_Type_Dimensions - Counter Thickness: 0.04 m; Depth: 0.625 m; Height: 0.9 m; PSet_Revit_Type_Materials and Finishes - Finish: Finish; PSet_Revit_Type_Construction - Construction Type: Construction Type
Basic Wall:Interior - Furring (38 mm Stud):358657:2 | First Floor | Pset_WallCommon - Reference: Basic Wall:Interior - Furring (38 mm Stud); LoadBearing: no; ExtendToStructure: no; IsExternal: no; PSet_Revit_Constraints - Location Line: 3; Base Constraint: First Floor; Base Offset: 0 m; Base is Attached: no; Base Extension Distance: 0 m; Top Constraint: Up to level: Second Floor; Unconnected Height: 4.468 m; Top Offset: -0.102 m; Top is Attached: no; Top Extension Distance: 0 m; Room Bounding: yes; Related to Mass: no; PSet_Revit_Other - InstallationDate: InstallationDate; SerialNumber: SerialNumber; WarrantyStartDate: WarrantyStartDate; BarCode: BarCode; AssetIdentifier: AssetIdentifier; TagNumber: TagNumber; PSet_Revit_Phasing - Phase Created: New Construction; PSet_Revit_Structural - Structural Usage: 0; PSet_Revit_Dimensions - Length: 12.505 m; Area: 40.6016 m2; Volume: 2.19249 m3; PSet_Revit_Type_Construction - Wrapping at Inserts: 0; Wrapping at Ends: 0; Width: 0.054 m; Function: 0; PSet_Revit_Type_Graphics - Coarse Scale Fill Color: 0; PSet_Revit_Type_Identity Data - Manufacturer: Manufacturer; PSet_Revit_Type_Other - AccessibilityPerformance: AccessibilityPerformance; CodePerformance: CodePerformance; Color: Color; Constituents: Constituents; Features: Features; Finish: Finish; Grade: Grade; Material: Material; ModelReference: ModelReference; NominalHeight: NominalHeight; NominalLength: NominalLength; NominalWidth: NominalWidth; ProductionYear: ProductionYear; Reference: Reference; Shape: Shape; Size: Size; SustainabilityPerformance: SustainabilityPerformance; WarrantyDescription: WarrantyDescription; WarrantyDurationLabor: WarrantyDurationLabor; WarrantyDurationParts: WarrantyDurationParts; WarrantyGuarantorLabor: WarrantyGuarantorLabor; WarrantyGuarantorParts: WarrantyGuarantorParts; ExpectedLife: ExpectedLife; ReplacementCost: ReplacementCost; AssetAccountingType: FIXED; Classification Code: 23-25 40 11 11 11; Classification Description: Metal-Framed Gypsum Board Fixed Partitions; ModelLabel: ModelLabel
M_Single-Flush:0915 x 2134mm:0915 x 2134mm:364769:1 | First Floor
 | First Floor | Pset_WallCommon - Reference: Basic Wall:Interior - Partition (92mm Stud); LoadBearing: no; ExtendToStructure: no; IsExternal: no; PSet_Revit_Constraints - Location Line: 2; Base Constraint: First Floor; Base Offset: 0 m; Base is Attached: no; Base Extension Distance: 0 m; Top Constraint: Up to level: Second Floor; Unconnected Height: 4.468 m; Top Offset: -0.102 m; Top is Attached: no; Top Extension Distance: 0 m; Room Bounding: yes; Related to Mass: no; PSet_Revit_Other - InstallationDate: InstallationDate; SerialNumber: SerialNumber; WarrantyStartDate: WarrantyStartDate; BarCode: BarCode; AssetIdentifier: AssetIdentifier; TagNumber: TagNumber; PSet_Revit_Phasing - Phase Created: New Construction; PSet_Revit_Structural - Structural Usage: 0; PSet_Revit_Dimensions - Length: 14.2555 m; Area: 56.2786 m2; Volume: 6.9424 m3; PSet_Revit_Type_Construction - Wrapping at Inserts: 0; Wrapping at Ends: 2; Width: 0.124 m; Function: 0; PSet_Revit_Type_Graphics - Coarse Scale Fill Color: 0; PSet_Revit_Type_Identity Data - Manufacturer: Manufacturer; PSet_Revit_Type_Other - AccessibilityPerformance: AccessibilityPerformance; CodePerformance: CodePerformance; Color: Color; Constituents: Constituents; Features: Features; Finish: Finish; Grade: Grade; Material: Material; ModelReference: ModelReference; NominalHeight: NominalHeight; NominalLength: NominalLength; NominalWidth: NominalWidth; ProductionYear: ProductionYear; Reference: Reference; Shape: Shape; Size: Size; SustainabilityPerformance: SustainabilityPerformance; WarrantyDescription: WarrantyDescription; WarrantyDurationLabor: WarrantyDurationLabor; WarrantyDurationParts: WarrantyDurationParts; WarrantyGuarantorLabor: WarrantyGuarantorLabor; WarrantyGuarantorParts: WarrantyGuarantorParts; ExpectedLife: ExpectedLife; ReplacementCost: ReplacementCost; AssetAccountingType: FIXED; Classification Code: 23-25 40 11 11 11; Classification Description: Metal-Framed Gypsum Board Fixed Partitions; ModelLabel: ModelLabel
M_Double-Flush:1730 x 2134mm:1730 x 2134mm:367888:1 | First Floor
 | Second Floor | Pset_WallCommon - Reference: Basic Wall:Exterior - Insul Panel on Mtl. Stud; LoadBearing: no; ExtendToStructure: no; IsExternal: yes; PSet_Revit_Constraints - Location Line: 0; Base Constraint: Second Floor; Base Offset: 3.4865 m; Base is Attached: no; Base Extension Distance: 0 m; Top Constraint: Up to level: Roof - Main; Unconnected Height: 2.5435 m; Top Offset: 1.35 m; Top is Attached: no; Top Extension Distance: 0 m; Room Bounding: yes; Related to Mass: no; PSet_Revit_Other - InstallationDate: InstallationDate; SerialNumber: SerialNumber; WarrantyStartDate: WarrantyStartDate; BarCode: BarCode; AssetIdentifier: AssetIdentifier; TagNumber: TagNumber; PSet_Revit_Phasing - Phase Created: New Construction; PSet_Revit_Structural - Structural Usage: 0; PSet_Revit_Dimensions - Length: 1.07919 m; Area: 1.18262 m2; Volume: 0.31576 m3; PSet_Revit_Type_Construction - Wrapping at Inserts: 0; Wrapping at Ends: 1; Width: 0.267 m; Function: 1; PSet_Revit_Type_Graphics - Coarse Scale Fill Color: 0; PSet_Revit_Type_Identity Data - Manufacturer: Manufacturer; PSet_Revit_Type_Other - AccessibilityPerformance: AccessibilityPerformance; CodePerformance: CodePerformance; Color: Color; Constituents: Constituents; Features: Features; Finish: Finish; Grade: Grade; Material: Material; ModelReference: ModelReference; NominalHeight: NominalHeight; NominalLength: NominalLength; NominalWidth: NominalWidth; ProductionYear: ProductionYear; Reference: Reference; Shape: Shape; Size: Size; SustainabilityPerformance: SustainabilityPerformance; WarrantyDescription: WarrantyDescription; WarrantyDurationLabor: WarrantyDurationLabor; WarrantyDurationParts: WarrantyDurationParts; WarrantyGuarantorLabor: WarrantyGuarantorLabor; WarrantyGuarantorParts: WarrantyGuarantorParts; ExpectedLife: ExpectedLife; ReplacementCost: ReplacementCost; AssetAccountingType: FIXED; Classification Code: 23-25 30 24 21; Classification Description: Metal Framed Structural Walls; ModelLabel: ModelLabel
Basic Wall:Exterior - Insul Panel on Mtl. Stud:378843:2 | Second Floor | Pset_WallCommon - Reference: Basic Wall:Exterior - Insul Panel on Mtl. Stud; LoadBearing: no; ExtendToStructure: no; IsExternal: yes; PSet_Revit_Constraints - Location Line: 2; Base Constraint: Second Floor; Base Offset: 2.1915 m; Base is Attached: no; Base Extension Distance: 0 m; Top Constraint: Up to level: Roof - Main; Unconnected Height: 1.697 m; Top Offset: -0.7915 m; Top is Attached: no; Top Extension Distance: 0 m; Room Bounding: yes; Related to Mass: no; PSet_Revit_Other - InstallationDate: InstallationDate; SerialNumber: SerialNumber; WarrantyStartDate: WarrantyStartDate; BarCode: BarCode; AssetIdentifier: AssetIdentifier; TagNumber: TagNumber; PSet_Revit_Phasing - Phase Created: New Construction; PSet_Revit_Structural - Structural Usage: 0; PSet_Revit_Dimensions - Length: 9.10423 m; Area: 16.4162 m2; Volume: 4.38313 m3; PSet_Revit_Type_Construction - Wrapping at Inserts: 0; Wrapping at Ends: 1; Width: 0.267 m; Function: 1; PSet_Revit_Type_Graphics - Coarse Scale Fill Color: 0; PSet_Revit_Type_Identity Data - Manufacturer: Manufacturer; PSet_Revit_Type_Other - AccessibilityPerformance: AccessibilityPerformance; CodePerformance: CodePerformance; Color: Color; Constituents: Constituents; Features: Features; Finish: Finish; Grade: Grade; Material: Material; ModelReference: ModelReference; NominalHeight: NominalHeight; NominalLength: NominalLength; NominalWidth: NominalWidth; ProductionYear: ProductionYear; Reference: Reference; Shape: Shape; Size: Size; SustainabilityPerformance: SustainabilityPerformance; WarrantyDescription: WarrantyDescription; WarrantyDurationLabor: WarrantyDurationLabor; WarrantyDurationParts: WarrantyDurationParts; WarrantyGuarantorLabor: WarrantyGuarantorLabor; WarrantyGuarantorParts: WarrantyGuarantorParts; ExpectedLife: ExpectedLife; ReplacementCost: ReplacementCost; AssetAccountingType: FIXED; Classification Code: 23-25 30 24 21; Classification Description: Metal Framed Structural Walls; ModelLabel: ModelLabel
 | Second Floor | Pset_WallCommon - Reference: Basic Wall:Interior - Partition (92mm Stud); LoadBearing: no; ExtendToStructure: no; IsExternal: no; PSet_Revit_Constraints - Location Line: 0; Base Constraint: Second Floor; Base Offset: 0 m; Base is Attached: no; Base Extension Distance: 0 m; Top Constraint: Up to level: Roof - Main; Unconnected Height: 4.578 m; Top Offset: -0.102 m; Top is Attached: no; Top Extension Distance: 0 m; Room Bounding: yes; Related to Mass: no; PSet_Revit_Other - InstallationDate: InstallationDate; SerialNumber: SerialNumber; WarrantyStartDate: WarrantyStartDate; BarCode: BarCode; AssetIdentifier: AssetIdentifier; TagNumber: TagNumber; PSet_Revit_Phasing - Phase Created: New Construction; PSet_Revit_Structural - Structural Usage: 0; PSet_Revit_Dimensions - Length: 6.12825 m; Area: 15.8474 m2; Volume: 1.96508 m3; PSet_Revit_Type_Construction - Wrapping at Inserts: 0; Wrapping at Ends: 2; Width: 0.124 m; Function: 0; PSet_Revit_Type_Graphics - Coarse Scale Fill Color: 0; PSet_Revit_Type_Identity Data - Manufacturer: Manufacturer; PSet_Revit_Type_Other - AccessibilityPerformance: AccessibilityPerformance; CodePerformance: CodePerformance; Color: Color; Constituents: Constituents; Features: Features; Finish: Finish; Grade: Grade; Material: Material; ModelReference: ModelReference; NominalHeight: NominalHeight; NominalLength: NominalLength; NominalWidth: NominalWidth; ProductionYear: ProductionYear; Reference: Reference; Shape: Shape; Size: Size; SustainabilityPerformance: SustainabilityPerformance; WarrantyDescription: WarrantyDescription; WarrantyDurationLabor: WarrantyDurationLabor; WarrantyDurationParts: WarrantyDurationParts; WarrantyGuarantorLabor: WarrantyGuarantorLabor; WarrantyGuarantorParts: WarrantyGuarantorParts; ExpectedLife: ExpectedLife; ReplacementCost: ReplacementCost; AssetAccountingType: FIXED; Classification Code: 23-25 40 11 11 11; Classification Description: Metal-Framed Gypsum Board Fixed Partitions; ModelLabel: ModelLabel
 | Second Floor | Pset_WallCommon - Reference: Basic Wall:Interior - Partition (92mm Stud); LoadBearing: no; ExtendToStructure: no; IsExternal: no; PSet_Revit_Constraints - Location Line: 2; Base Constraint: Second Floor; Base Offset: 0 m; Base is Attached: no; Base Extension Distance: 0 m; Top Constraint: Up to level: Roof - Main; Unconnected Height: 4.68 m; Top Offset: 0 m; Top is Attached: no; Top Extension Distance: 0 m; Room Bounding: yes; Related to Mass: no; PSet_Revit_Other - InstallationDate: InstallationDate; SerialNumber: SerialNumber; WarrantyStartDate: WarrantyStartDate; BarCode: BarCode; AssetIdentifier: AssetIdentifier; TagNumber: TagNumber; PSet_Revit_Phasing - Phase Created: New Construction; PSet_Revit_Structural - Structural Usage: 0; PSet_Revit_Dimensions - Length: 11.691 m; Area: 27.4777 m2; Volume: 3.40724 m3; PSet_Revit_Type_Construction - Wrapping at Inserts: 0; Wrapping at Ends: 2; Width: 0.124 m; Function: 0; PSet_Revit_Type_Graphics - Coarse Scale Fill Color: 0; PSet_Revit_Type_Identity Data - Manufacturer: Manufacturer; PSet_Revit_Type_Other - AccessibilityPerformance: AccessibilityPerformance; CodePerformance: CodePerformance; Color: Color; Constituents: Constituents; Features: Features; Finish: Finish; Grade: Grade; Material: Material; ModelReference: ModelReference; NominalHeight: NominalHeight; NominalLength: NominalLength; NominalWidth: NominalWidth; ProductionYear: ProductionYear; Reference: Reference; Shape: Shape; Size: Size; SustainabilityPerformance: SustainabilityPerformance; WarrantyDescription: WarrantyDescription; WarrantyDurationLabor: WarrantyDurationLabor; WarrantyDurationParts: WarrantyDurationParts; WarrantyGuarantorLabor: WarrantyGuarantorLabor; WarrantyGuarantorParts: WarrantyGuarantorParts; ExpectedLife: ExpectedLife; ReplacementCost: ReplacementCost; AssetAccountingType: FIXED; Classification Code: 23-25 40 11 11 11; Classification Description: Metal-Framed Gypsum Board Fixed Partitions; ModelLabel: ModelLabel
 | Second Floor | Pset_WallCommon - Reference: Basic Wall:Interior - Partition (92mm Stud); LoadBearing: no; ExtendToStructure: no; IsExternal: no; PSet_Revit_Constraints - Location Line: 2; Base Constraint: Second Floor; Base Offset: 0 m; Base is Attached: no; Base Extension Distance: 0 m; Top Constraint: Up to level: Roof - Main; Unconnected Height: 4.68 m; Top Offset: 0 m; Top is Attached: no; Top Extension Distance: 0 m; Room Bounding: yes; Related to Mass: no; PSet_Revit_Other - InstallationDate: InstallationDate; SerialNumber: SerialNumber; WarrantyStartDate: WarrantyStartDate; BarCode: BarCode; AssetIdentifier: AssetIdentifier; TagNumber: TagNumber; PSet_Revit_Phasing - Phase Created: New Construction; PSet_Revit_Structural - Structural Usage: 0; PSet_Revit_Dimensions - Length: 11.691 m; Area: 27.9217 m2; Volume: 3.46229 m3; PSet_Revit_Type_Construction - Wrapping at Inserts: 0; Wrapping at Ends: 2; Width: 0.124 m; Function: 0; PSet_Revit_Type_Graphics - Coarse Scale Fill Color: 0; PSet_Revit_Type_Identity Data - Manufacturer: Manufacturer; PSet_Revit_Type_Other - AccessibilityPerformance: AccessibilityPerformance; CodePerformance: CodePerformance; Color: Color; Constituents: Constituents; Features: Features; Finish: Finish; Grade: Grade; Material: Material; ModelReference: ModelReference; NominalHeight: NominalHeight; NominalLength: NominalLength; NominalWidth: NominalWidth; ProductionYear: ProductionYear; Reference: Reference; Shape: Shape; Size: Size; SustainabilityPerformance: SustainabilityPerformance; WarrantyDescription: WarrantyDescription; WarrantyDurationLabor: WarrantyDurationLabor; WarrantyDurationParts: WarrantyDurationParts; WarrantyGuarantorLabor: WarrantyGuarantorLabor; WarrantyGuarantorParts: WarrantyGuarantorParts; ExpectedLife: ExpectedLife; ReplacementCost: ReplacementCost; AssetAccountingType: FIXED; Classification Code: 23-25 40 11 11 11; Classification Description: Metal-Framed Gypsum Board Fixed Partitions; ModelLabel: ModelLabel
Basic Wall:Exterior - Insul Panel on Mtl. Stud:381802:2 | Second Floor | Pset_WallCommon - Reference: Basic Wall:Exterior - Insul Panel on Mtl. Stud; LoadBearing: no; ExtendToStructure: no; IsExternal: yes; PSet_Revit_Constraints - Location Line: 2; Base Constraint: Second Floor; Base Offset: 3.4865 m; Base is Attached: no; Base Extension Distance: 0 m; Top Constraint: Up to level: Roof - Main; Unconnected Height: 1.6505 m; Top Offset: 0.457 m; Top is Attached: no; Top Extension Distance: 0 m; Room Bounding: yes; Related to Mass: no; PSet_Revit_Other - InstallationDate: InstallationDate; SerialNumber: SerialNumber; WarrantyStartDate: WarrantyStartDate; BarCode: BarCode; AssetIdentifier: AssetIdentifier; TagNumber: TagNumber; PSet_Revit_Phasing - Phase Created: New Construction; PSet_Revit_Structural - Structural Usage: 0; PSet_Revit_Dimensions - Length: 15.343 m; Area: 26.423 m2; Volume: 7.05495 m3; PSet_Revit_Type_Construction - Wrapping at Inserts: 0; Wrapping at Ends: 1; Width: 0.267 m; Function: 1; PSet_Revit_Type_Graphics - Coarse Scale Fill Color: 0; PSet_Revit_Type_Identity Data - Manufacturer: Manufacturer; PSet_Revit_Type_Other - AccessibilityPerformance: AccessibilityPerformance; CodePerformance: CodePerformance; Color: Color; Constituents: Constituents; Features: Features; Finish: Finish; Grade: Grade; Material: Material; ModelReference: ModelReference; NominalHeight: NominalHeight; NominalLength: NominalLength; NominalWidth: NominalWidth; ProductionYear: ProductionYear; Reference: Reference; Shape: Shape; Size: Size; SustainabilityPerformance: SustainabilityPerformance; WarrantyDescription: WarrantyDescription; WarrantyDurationLabor: WarrantyDurationLabor; WarrantyDurationParts: WarrantyDurationParts; WarrantyGuarantorLabor: WarrantyGuarantorLabor; WarrantyGuarantorParts: WarrantyGuarantorParts; ExpectedLife: ExpectedLife; ReplacementCost: ReplacementCost; AssetAccountingType: FIXED; Classification Code: 23-25 30 24 21; Classification Description: Metal Framed Structural Walls; ModelLabel: ModelLabel
Basic Wall:Exterior - Insul Panel on Mtl. Stud:381931:2 | Roof - Main | Pset_WallCommon - Reference: Basic Wall:Exterior - Insul Panel on Mtl. Stud; LoadBearing: no; ExtendToStructure: no; IsExternal: yes; PSet_Revit_Constraints - Location Line: 2; Base Constraint: Roof - Main; Base Offset: 0 m; Base is Attached: no; Base Extension Distance: 0 m; Top Constraint: Up to level: Roof - Main; Unconnected Height: 3.4 m; Top Offset: 3.4 m; Top is Attached: no; Top Extension Distance: 0 m; Room Bounding: yes; Related to Mass: no; PSet_Revit_Other - InstallationDate: InstallationDate; SerialNumber: SerialNumber; WarrantyStartDate: WarrantyStartDate; BarCode: BarCode; AssetIdentifier: AssetIdentifier; TagNumber: TagNumber; PSet_Revit_Phasing - Phase Created: New Construction; PSet_Revit_Structural - Structural Usage: 0; PSet_Revit_Dimensions - Length: 18.4025 m; Area: 31.9269 m2; Volume: 8.52447 m3; PSet_Revit_Type_Construction - Wrapping at Inserts: 0; Wrapping at Ends: 1; Width: 0.267 m; Function: 1; PSet_Revit_Type_Graphics - Coarse Scale Fill Color: 0; PSet_Revit_Type_Identity Data - Manufacturer: Manufacturer; PSet_Revit_Type_Other - AccessibilityPerformance: AccessibilityPerformance; CodePerformance: CodePerformance; Color: Color; Constituents: Constituents; Features: Features; Finish: Finish; Grade: Grade; Material: Material; ModelReference: ModelReference; NominalHeight: NominalHeight; NominalLength: NominalLength; NominalWidth: NominalWidth; ProductionYear: ProductionYear; Reference: Reference; Shape: Shape; Size: Size; SustainabilityPerformance: SustainabilityPerformance; WarrantyDescription: WarrantyDescription; WarrantyDurationLabor: WarrantyDurationLabor; WarrantyDurationParts: WarrantyDurationParts; WarrantyGuarantorLabor: WarrantyGuarantorLabor; WarrantyGuarantorParts: WarrantyGuarantorParts; ExpectedLife: ExpectedLife; ReplacementCost: ReplacementCost; AssetAccountingType: FIXED; Classification Code: 23-25 30 24 21; Classification Description: Metal Framed Structural Walls; ModelLabel: ModelLabel
 | Second Floor | Pset_WallCommon - Reference: Basic Wall:Exterior - Insul Panel on Mtl. Stud; LoadBearing: no; ExtendToStructure: no; IsExternal: yes; PSet_Revit_Constraints - Location Line: 0; Base Constraint: Second Floor; Base Offset: 3.4865 m; Base is Attached: no; Base Extension Distance: 0 m; Top Constraint: Up to level: Roof - Main; Unconnected Height: 2.5435 m; Top Offset: 1.35 m; Top is Attached: no; Top Extension Distance: 0 m; Room Bounding: yes; Related to Mass: no; PSet_Revit_Other - InstallationDate: InstallationDate; SerialNumber: SerialNumber; WarrantyStartDate: WarrantyStartDate; BarCode: BarCode; AssetIdentifier: AssetIdentifier; TagNumber: TagNumber; PSet_Revit_Phasing - Phase Created: New Construction; PSet_Revit_Structural - Structural Usage: 0; PSet_Revit_Dimensions - Length: 1.08869 m; Area: 1.35432 m2; Volume: 0.361602 m3; PSet_Revit_Type_Construction - Wrapping at Inserts: 0; Wrapping at Ends: 1; Width: 0.267 m; Function: 1; PSet_Revit_Type_Graphics - Coarse Scale Fill Color: 0; PSet_Revit_Type_Identity Data - Manufacturer: Manufacturer; PSet_Revit_Type_Other - AccessibilityPerformance: AccessibilityPerformance; CodePerformance: CodePerformance; Color: Color; Constituents: Constituents; Features: Features; Finish: Finish; Grade: Grade; Material: Material; ModelReference: ModelReference; NominalHeight: NominalHeight; NominalLength: NominalLength; NominalWidth: NominalWidth; ProductionYear: ProductionYear; Reference: Reference; Shape: Shape; Size: Size; SustainabilityPerformance: SustainabilityPerformance; WarrantyDescription: WarrantyDescription; WarrantyDurationLabor: WarrantyDurationLabor; WarrantyDurationParts: WarrantyDurationParts; WarrantyGuarantorLabor: WarrantyGuarantorLabor; WarrantyGuarantorParts: WarrantyGuarantorParts; ExpectedLife: ExpectedLife; ReplacementCost: ReplacementCost; AssetAccountingType: FIXED; Classification Code: 23-25 30 24 21; Classification Description: Metal Framed Structural Walls; ModelLabel: ModelLabel
Basic Wall:Exterior - Insul Panel on Mtl. Stud:384376:2 | Second Floor | Pset_WallCommon - Reference: Basic Wall:Exterior - Insul Panel on Mtl. Stud; LoadBearing: no; ExtendToStructure: no; IsExternal: yes; PSet_Revit_Constraints - Location Line: 2; Base Constraint: Second Floor; Base Offset: 0 m; Base is Attached: no; Base Extension Distance: 0 m; Top Constraint: Up to level: Second Floor; Unconnected Height: 2.64 m; Top Offset: 2.64 m; Top is Attached: no; Top Extension Distance: 0 m; Room Bounding: yes; Related to Mass: no; PSet_Revit_Other - InstallationDate: InstallationDate; SerialNumber: SerialNumber; WarrantyStartDate: WarrantyStartDate; BarCode: BarCode; AssetIdentifier: AssetIdentifier; TagNumber: TagNumber; PSet_Revit_Phasing - Phase Created: New Construction; PSet_Revit_Structural - Structural Usage: 0; PSet_Revit_Dimensions - Length: 2.7445 m; Area: 7.39046 m2; Volume: 1.97325 m3; PSet_Revit_Type_Construction - Wrapping at Inserts: 0; Wrapping at Ends: 1; Width: 0.267 m; Function: 1; PSet_Revit_Type_Graphics - Coarse Scale Fill Color: 0; PSet_Revit_Type_Identity Data - Manufacturer: Manufacturer; PSet_Revit_Type_Other - AccessibilityPerformance: AccessibilityPerformance; CodePerformance: CodePerformance; Color: Color; Constituents: Constituents; Features: Features; Finish: Finish; Grade: Grade; Material: Material; ModelReference: ModelReference; NominalHeight: NominalHeight; NominalLength: NominalLength; NominalWidth: NominalWidth; ProductionYear: ProductionYear; Reference: Reference; Shape: Shape; Size: Size; SustainabilityPerformance: SustainabilityPerformance; WarrantyDescription: WarrantyDescription; WarrantyDurationLabor: WarrantyDurationLabor; WarrantyDurationParts: WarrantyDurationParts; WarrantyGuarantorLabor: WarrantyGuarantorLabor; WarrantyGuarantorParts: WarrantyGuarantorParts; ExpectedLife: ExpectedLife; ReplacementCost: ReplacementCost; AssetAccountingType: FIXED; Classification Code: 23-25 30 24 21; Classification Description: Metal Framed Structural Walls; ModelLabel: ModelLabel
Basic Wall:Interior - Furring (38 mm Stud):392344:2 | Second Floor | Pset_WallCommon - Reference: Basic Wall:Interior - Furring (38 mm Stud); LoadBearing: no; ExtendToStructure: no; IsExternal: no; PSet_Revit_Constraints - Location Line: 3; Base Constraint: Second Floor; Base Offset: 0 m; Base is Attached: no; Base Extension Distance: 0 m; Top Constraint: Up to level: Second Floor; Unconnected Height: 2.8 m; Top Offset: 2.8 m; Top is Attached: no; Top Extension Distance: 0 m; Room Bounding: yes; Related to Mass: no; PSet_Revit_Other - InstallationDate: InstallationDate; SerialNumber: SerialNumber; WarrantyStartDate: WarrantyStartDate; BarCode: BarCode; AssetIdentifier: AssetIdentifier; TagNumber: TagNumber; PSet_Revit_Phasing - Phase Created: New Construction; PSet_Revit_Structural - Structural Usage: 0; PSet_Revit_Dimensions - Length: 1.47394 m; Area: 2.95641 m2; Volume: 0.159646 m3; PSet_Revit_Type_Construction - Wrapping at Inserts: 0; Wrapping at Ends: 0; Width: 0.054 m; Function: 0; PSet_Revit_Type_Graphics - Coarse Scale Fill Color: 0; PSet_Revit_Type_Identity Data - Manufacturer: Manufacturer; PSet_Revit_Type_Other - AccessibilityPerformance: AccessibilityPerformance; CodePerformance: CodePerformance; Color: Color; Constituents: Constituents; Features: Features; Finish: Finish; Grade: Grade; Material: Material; ModelReference: ModelReference; NominalHeight: NominalHeight; NominalLength: NominalLength; NominalWidth: NominalWidth; ProductionYear: ProductionYear; Reference: Reference; Shape: Shape; Size: Size; SustainabilityPerformance: SustainabilityPerformance; WarrantyDescription: WarrantyDescription; WarrantyDurationLabor: WarrantyDurationLabor; WarrantyDurationParts: WarrantyDurationParts; WarrantyGuarantorLabor: WarrantyGuarantorLabor; WarrantyGuarantorParts: WarrantyGuarantorParts; ExpectedLife: ExpectedLife; ReplacementCost: ReplacementCost; AssetAccountingType: FIXED; Classification Code: 23-25 40 11 11 11; Classification Description: Metal-Framed Gypsum Board Fixed Partitions; ModelLabel: ModelLabel
M_Single-Flush:0915 x 2134mm:0915 x 2134mm:402047:1 | First Floor
M_Single-Flush:0915 x 2134mm:0915 x 2134mm:403890:1 | First Floor
M_Toilet Partition:0865 x 1500mm:0865 x 1500mm:408825:1 | Second Floor
M_Double-Flush:1830 x 2134mm Exterior:1830 x 2134mm Exterior:411107:1 | Second Floor
M_Toilet Partition:0865 x 1500mm:0865 x 1500mm:411832:1 | First Floor
M_Toilet Partition:0865 x 1500mm:0865 x 1500mm:412670:1 | First Floor
M_Toilet Partition:0865 x 1500mm:0865 x 1500mm:412771:1 | First Floor
M_Toilet Partition:0865 x 1500mm:0865 x 1500mm:412955:1 | Second Floor
M_Toilet Partition:0865 x 1500mm:0865 x 1500mm:413234:1 | Second Floor
M_Toilet Partition:0865 x 1500mm:0865 x 1500mm:413317:1 | Second Floor
M_Counter Top w Sink Hole:600mm Depth:600mm Depth:422054:1 | 1D02 | PSet_Revit_Other - InstallationDate: InstallationDate; SerialNumber: SerialNumber; WarrantyStartDate: WarrantyStartDate; BarCode: BarCode; AssetIdentifier: AssetIdentifier; TagNumber: TagNumber; PSet_Revit_Phasing - Phase Created: New Construction; PSet_Revit_Dimensions - Length: 1.2 m; Sink Location: 0.6 m; Sink Location To Wall: 0.16973 m; Sink Opening Depth: 0.391258 m; Sink Opening Width: 0.587 m; PSet_Revit_Type_Identity Data - Manufacturer: Manufacturer; OmniClass Number: 23.40.35.17.47.11; OmniClass Title: Kitchen Casework; PSet_Revit_Type_Other - AccessibilityPerformance: AccessibilityPerformance; CodePerformance: CodePerformance; Color: Color; Constituents: Constituents; Features: Features; Finish: Finish; Grade: Grade; Material: Material; ModelReference: ModelReference; NominalHeight: NominalHeight; NominalLength: NominalLength; NominalWidth: NominalWidth; ProductionYear: ProductionYear; Reference: Reference; Shape: Shape; Size: Size; SustainabilityPerformance: SustainabilityPerformance; WarrantyDescription: WarrantyDescription; WarrantyDurationLabor: WarrantyDurationLabor; WarrantyDurationParts: WarrantyDurationParts; WarrantyGuarantorLabor: WarrantyGuarantorLabor; WarrantyGuarantorParts: WarrantyGuarantorParts; ExpectedLife: ExpectedLife; ReplacementCost: ReplacementCost; AssetAccountingType: FIXED; ModelLabel: ModelLabel; Area: Area; PSet_Revit_Constraints - Level: First Floor; Host: Level : First Floor; Offset: 0 m; Moves With Nearby Elements: no; PSet_Revit_Type_Dimensions - Counter Thickness: 0.04 m; Depth: 0.625 m; Height: 0.9 m; PSet_Revit_Type_Materials and Finishes - Finish: Finish; PSet_Revit_Type_Construction - Construction Type: Construction Type
M_Counter Top w Sink Hole:600mm Depth:600mm Depth:422552:1 | 1D08 | PSet_Revit_Other - InstallationDate: InstallationDate; SerialNumber: SerialNumber; WarrantyStartDate: WarrantyStartDate; BarCode: BarCode; AssetIdentifier: AssetIdentifier; TagNumber: TagNumber; PSet_Revit_Phasing - Phase Created: New Construction; PSet_Revit_Dimensions - Length: 1.2 m; Sink Location: 0.6 m; Sink Location To Wall: 0.16973 m; Sink Opening Depth: 0.391258 m; Sink Opening Width: 0.587 m; PSet_Revit_Type_Identity Data - Manufacturer: Manufacturer; OmniClass Number: 23.40.35.17.47.11; OmniClass Title: Kitchen Casework; PSet_Revit_Type_Other - AccessibilityPerformance: AccessibilityPerformance; CodePerformance: CodePerformance; Color: Color; Constituents: Constituents; Features: Features; Finish: Finish; Grade: Grade; Material: Material; ModelReference: ModelReference; NominalHeight: NominalHeight; NominalLength: NominalLength; NominalWidth: NominalWidth; ProductionYear: ProductionYear; Reference: Reference; Shape: Shape; Size: Size; SustainabilityPerformance: SustainabilityPerformance; WarrantyDescription: WarrantyDescription; WarrantyDurationLabor: WarrantyDurationLabor; WarrantyDurationParts: WarrantyDurationParts; WarrantyGuarantorLabor: WarrantyGuarantorLabor; WarrantyGuarantorParts: WarrantyGuarantorParts; ExpectedLife: ExpectedLife; ReplacementCost: ReplacementCost; AssetAccountingType: FIXED; ModelLabel: ModelLabel; Area: Area; PSet_Revit_Constraints - Level: First Floor; Host: Level : First Floor; Offset: 0 m; Moves With Nearby Elements: no; PSet_Revit_Type_Dimensions - Counter Thickness: 0.04 m; Depth: 0.625 m; Height: 0.9 m; PSet_Revit_Type_Materials and Finishes - Finish: Finish; PSet_Revit_Type_Construction - Construction Type: Construction Type
M_Counter Top w Sink Hole:600mm Depth:600mm Depth:422728:1 | 1D10 | PSet_Revit_Other - InstallationDate: InstallationDate; SerialNumber: SerialNumber; WarrantyStartDate: WarrantyStartDate; BarCode: BarCode; AssetIdentifier: AssetIdentifier; TagNumber: TagNumber; PSet_Revit_Phasing - Phase Created: New Construction; PSet_Revit_Dimensions - Length: 1.2 m; Sink Location: 0.6 m; Sink Location To Wall: 0.16973 m; Sink Opening Depth: 0.391258 m; Sink Opening Width: 0.587 m; PSet_Revit_Type_Identity Data - Manufacturer: Manufacturer; OmniClass Number: 23.40.35.17.47.11; OmniClass Title: Kitchen Casework; PSet_Revit_Type_Other - AccessibilityPerformance: AccessibilityPerformance; CodePerformance: CodePerformance; Color: Color; Constituents: Constituents; Features: Features; Finish: Finish; Grade: Grade; Material: Material; ModelReference: ModelReference; NominalHeight: NominalHeight; NominalLength: NominalLength; NominalWidth: NominalWidth; ProductionYear: ProductionYear; Reference: Reference; Shape: Shape; Size: Size; SustainabilityPerformance: SustainabilityPerformance; WarrantyDescription: WarrantyDescription; WarrantyDurationLabor: WarrantyDurationLabor; WarrantyDurationParts: WarrantyDurationParts; WarrantyGuarantorLabor: WarrantyGuarantorLabor; WarrantyGuarantorParts: WarrantyGuarantorParts; ExpectedLife: ExpectedLife; ReplacementCost: ReplacementCost; AssetAccountingType: FIXED; ModelLabel: ModelLabel; Area: Area; PSet_Revit_Constraints - Level: First Floor; Host: Level : First Floor; Offset: 0 m; Moves With Nearby Elements: no; PSet_Revit_Type_Dimensions - Counter Thickness: 0.04 m; Depth: 0.625 m; Height: 0.9 m; PSet_Revit_Type_Materials and Finishes - Finish: Finish; PSet_Revit_Type_Construction - Construction Type: Construction Type
M_Counter Top w Sink Hole:600mm Depth:600mm Depth:422741:1 | 1D11 | PSet_Revit_Other - InstallationDate: InstallationDate; SerialNumber: SerialNumber; WarrantyStartDate: WarrantyStartDate; BarCode: BarCode; AssetIdentifier: AssetIdentifier; TagNumber: TagNumber; PSet_Revit_Phasing - Phase Created: New Construction; PSet_Revit_Dimensions - Length: 1.2 m; Sink Location: 0.6 m; Sink Location To Wall: 0.16973 m; Sink Opening Depth: 0.391258 m; Sink Opening Width: 0.587 m; PSet_Revit_Type_Identity Data - Manufacturer: Manufacturer; OmniClass Number: 23.40.35.17.47.11; OmniClass Title: Kitchen Casework; PSet_Revit_Type_Other - AccessibilityPerformance: AccessibilityPerformance; CodePerformance: CodePerformance; Color: Color; Constituents: Constituents; Features: Features; Finish: Finish; Grade: Grade; Material: Material; ModelReference: ModelReference; NominalHeight: NominalHeight; NominalLength: NominalLength; NominalWidth: NominalWidth; ProductionYear: ProductionYear; Reference: Reference; Shape: Shape; Size: Size; SustainabilityPerformance: SustainabilityPerformance; WarrantyDescription: WarrantyDescription; WarrantyDurationLabor: WarrantyDurationLabor; WarrantyDurationParts: WarrantyDurationParts; WarrantyGuarantorLabor: WarrantyGuarantorLabor; WarrantyGuarantorParts: WarrantyGuarantorParts; ExpectedLife: ExpectedLife; ReplacementCost: ReplacementCost; AssetAccountingType: FIXED; ModelLabel: ModelLabel; Area: Area; PSet_Revit_Constraints - Level: First Floor; Host: Level : First Floor; Offset: 0 m; Moves With Nearby Elements: no; PSet_Revit_Type_Dimensions - Counter Thickness: 0.04 m; Depth: 0.625 m; Height: 0.9 m; PSet_Revit_Type_Materials and Finishes - Finish: Finish; PSet_Revit_Type_Construction - Construction Type: Construction Type
M_Counter Top w Sink Hole:600mm Depth:600mm Depth:422814:1 | 1D13 | PSet_Revit_Other - InstallationDate: InstallationDate; SerialNumber: SerialNumber; WarrantyStartDate: WarrantyStartDate; BarCode: BarCode; AssetIdentifier: AssetIdentifier; TagNumber: TagNumber; PSet_Revit_Phasing - Phase Created: New Construction; PSet_Revit_Dimensions - Length: 1.2 m; Sink Location: 0.6 m; Sink Location To Wall: 0.16973 m; Sink Opening Depth: 0.391258 m; Sink Opening Width: 0.587 m; PSet_Revit_Type_Identity Data - Manufacturer: Manufacturer; OmniClass Number: 23.40.35.17.47.11; OmniClass Title: Kitchen Casework; PSet_Revit_Type_Other - AccessibilityPerformance: AccessibilityPerformance; CodePerformance: CodePerformance; Color: Color; Constituents: Constituents; Features: Features; Finish: Finish; Grade: Grade; Material: Material; ModelReference: ModelReference; NominalHeight: NominalHeight; NominalLength: NominalLength; NominalWidth: NominalWidth; ProductionYear: ProductionYear; Reference: Reference; Shape: Shape; Size: Size; SustainabilityPerformance: SustainabilityPerformance; WarrantyDescription: WarrantyDescription; WarrantyDurationLabor: WarrantyDurationLabor; WarrantyDurationParts: WarrantyDurationParts; WarrantyGuarantorLabor: WarrantyGuarantorLabor; WarrantyGuarantorParts: WarrantyGuarantorParts; ExpectedLife: ExpectedLife; ReplacementCost: ReplacementCost; AssetAccountingType: FIXED; ModelLabel: ModelLabel; Area: Area; PSet_Revit_Constraints - Level: First Floor; Host: Level : First Floor; Offset: 0 m; Moves With Nearby Elements: no; PSet_Revit_Type_Dimensions - Counter Thickness: 0.04 m; Depth: 0.625 m; Height: 0.9 m; PSet_Revit_Type_Materials and Finishes - Finish: Finish; PSet_Revit_Type_Construction - Construction Type: Construction Type
M_Counter Top w Sink Hole:600mm Depth:600mm Depth:422834:1 | 1D07 | PSet_Revit_Other - InstallationDate: InstallationDate; SerialNumber: SerialNumber; WarrantyStartDate: WarrantyStartDate; BarCode: BarCode; AssetIdentifier: AssetIdentifier; TagNumber: TagNumber; PSet_Revit_Phasing - Phase Created: New Construction; PSet_Revit_Dimensions - Length: 1.2 m; Sink Location: 0.6 m; Sink Location To Wall: 0.16973 m; Sink Opening Depth: 0.391258 m; Sink Opening Width: 0.587 m; PSet_Revit_Type_Identity Data - Manufacturer: Manufacturer; OmniClass Number: 23.40.35.17.47.11; OmniClass Title: Kitchen Casework; PSet_Revit_Type_Other - AccessibilityPerformance: AccessibilityPerformance; CodePerformance: CodePerformance; Color: Color; Constituents: Constituents; Features: Features; Finish: Finish; Grade: Grade; Material: Material; ModelReference: ModelReference; NominalHeight: NominalHeight; NominalLength: NominalLength; NominalWidth: NominalWidth; ProductionYear: ProductionYear; Reference: Reference; Shape: Shape; Size: Size; SustainabilityPerformance: SustainabilityPerformance; WarrantyDescription: WarrantyDescription; WarrantyDurationLabor: WarrantyDurationLabor; WarrantyDurationParts: WarrantyDurationParts; WarrantyGuarantorLabor: WarrantyGuarantorLabor; WarrantyGuarantorParts: WarrantyGuarantorParts; ExpectedLife: ExpectedLife; ReplacementCost: ReplacementCost; AssetAccountingType: FIXED; ModelLabel: ModelLabel; Area: Area; PSet_Revit_Constraints - Level: First Floor; Host: Level : First Floor; Offset: 0 m; Moves With Nearby Elements: no; PSet_Revit_Type_Dimensions - Counter Thickness: 0.04 m; Depth: 0.625 m; Height: 0.9 m; PSet_Revit_Type_Materials and Finishes - Finish: Finish; PSet_Revit_Type_Construction - Construction Type: Construction Type
M_Counter Top w Sink Hole:600mm Depth:600mm Depth:422836:1 | 1D09 | PSet_Revit_Other - InstallationDate: InstallationDate; SerialNumber: SerialNumber; WarrantyStartDate: WarrantyStartDate; BarCode: BarCode; AssetIdentifier: AssetIdentifier; TagNumber: TagNumber; PSet_Revit_Phasing - Phase Created: New Construction; PSet_Revit_Dimensions - Length: 1.2 m; Sink Location: 0.6 m; Sink Location To Wall: 0.16973 m; Sink Opening Depth: 0.391258 m; Sink Opening Width: 0.587 m; PSet_Revit_Type_Identity Data - Manufacturer: Manufacturer; OmniClass Number: 23.40.35.17.47.11; OmniClass Title: Kitchen Casework; PSet_Revit_Type_Other - AccessibilityPerformance: AccessibilityPerformance; CodePerformance: CodePerformance; Color: Color; Constituents: Constituents; Features: Features; Finish: Finish; Grade: Grade; Material: Material; ModelReference: ModelReference; NominalHeight: NominalHeight; NominalLength: NominalLength; NominalWidth: NominalWidth; ProductionYear: ProductionYear; Reference: Reference; Shape: Shape; Size: Size; SustainabilityPerformance: SustainabilityPerformance; WarrantyDescription: WarrantyDescription; WarrantyDurationLabor: WarrantyDurationLabor; WarrantyDurationParts: WarrantyDurationParts; WarrantyGuarantorLabor: WarrantyGuarantorLabor; WarrantyGuarantorParts: WarrantyGuarantorParts; ExpectedLife: ExpectedLife; ReplacementCost: ReplacementCost; AssetAccountingType: FIXED; ModelLabel: ModelLabel; Area: Area; PSet_Revit_Constraints - Level: First Floor; Host: Level : First Floor; Offset: 0 m; Moves With Nearby Elements: no; PSet_Revit_Type_Dimensions - Counter Thickness: 0.04 m; Depth: 0.625 m; Height: 0.9 m; PSet_Revit_Type_Materials and Finishes - Finish: Finish; PSet_Revit_Type_Construction - Construction Type: Construction Type
M_Counter Top w Sink Hole:600mm Depth:600mm Depth:422863:1 | 1D05 | PSet_Revit_Other - InstallationDate: InstallationDate; SerialNumber: SerialNumber; WarrantyStartDate: WarrantyStartDate; BarCode: BarCode; AssetIdentifier: AssetIdentifier; TagNumber: TagNumber; PSet_Revit_Phasing - Phase Created: New Construction; PSet_Revit_Dimensions - Length: 2.41 m; Sink Location: 1.205 m; Sink Location To Wall: 0.137017 m; Sink Opening Depth: 0.4064 m; Sink Opening Width: 0.587 m; PSet_Revit_Type_Identity Data - Manufacturer: Manufacturer; OmniClass Number: 23.40.35.17.47.11; OmniClass Title: Kitchen Casework; PSet_Revit_Type_Other - AccessibilityPerformance: AccessibilityPerformance; CodePerformance: CodePerformance; Color: Color; Constituents: Constituents; Features: Features; Finish: Finish; Grade: Grade; Material: Material; ModelReference: ModelReference; NominalHeight: NominalHeight; NominalLength: NominalLength; NominalWidth: NominalWidth; ProductionYear: ProductionYear; Reference: Reference; Shape: Shape; Size: Size; SustainabilityPerformance: SustainabilityPerformance; WarrantyDescription: WarrantyDescription; WarrantyDurationLabor: WarrantyDurationLabor; WarrantyDurationParts: WarrantyDurationParts; WarrantyGuarantorLabor: WarrantyGuarantorLabor; WarrantyGuarantorParts: WarrantyGuarantorParts; ExpectedLife: ExpectedLife; ReplacementCost: ReplacementCost; AssetAccountingType: FIXED; ModelLabel: ModelLabel; Area: Area; PSet_Revit_Constraints - Level: First Floor; Host: Level : First Floor; Offset: 0 m; Moves With Nearby Elements: no; PSet_Revit_Type_Dimensions - Counter Thickness: 0.04 m; Depth: 0.625 m; Height: 0.9 m; PSet_Revit_Type_Materials and Finishes - Finish: Finish; PSet_Revit_Type_Construction - Construction Type: Construction Type
M_Counter Top w Sink Hole:600mm Depth:600mm Depth:424042:1 | 1D28 | PSet_Revit_Other - InstallationDate: InstallationDate; SerialNumber: SerialNumber; WarrantyStartDate: WarrantyStartDate; BarCode: BarCode; AssetIdentifier: AssetIdentifier; TagNumber: TagNumber; PSet_Revit_Phasing - Phase Created: New Construction; PSet_Revit_Dimensions - Length: 1.2 m; Sink Location: 0.6 m; Sink Location To Wall: 0.16973 m; Sink Opening Depth: 0.391258 m; Sink Opening Width: 0.587 m; PSet_Revit_Type_Identity Data - Manufacturer: Manufacturer; OmniClass Number: 23.40.35.17.47.11; OmniClass Title: Kitchen Casework; PSet_Revit_Type_Other - AccessibilityPerformance: AccessibilityPerformance; CodePerformance: CodePerformance; Color: Color; Constituents: Constituents; Features: Features; Finish: Finish; Grade: Grade; Material: Material; ModelReference: ModelReference; NominalHeight: NominalHeight; NominalLength: NominalLength; NominalWidth: NominalWidth; ProductionYear: ProductionYear; Reference: Reference; Shape: Shape; Size: Size; SustainabilityPerformance: SustainabilityPerformance; WarrantyDescription: WarrantyDescription; WarrantyDurationLabor: WarrantyDurationLabor; WarrantyDurationParts: WarrantyDurationParts; WarrantyGuarantorLabor: WarrantyGuarantorLabor; WarrantyGuarantorParts: WarrantyGuarantorParts; ExpectedLife: ExpectedLife; ReplacementCost: ReplacementCost; AssetAccountingType: FIXED; ModelLabel: ModelLabel; Area: Area; PSet_Revit_Constraints - Level: First Floor; Host: Level : First Floor; Offset: 0 m; Moves With Nearby Elements: no; PSet_Revit_Type_Dimensions - Counter Thickness: 0.04 m; Depth: 0.625 m; Height: 0.9 m; PSet_Revit_Type_Materials and Finishes - Finish: Finish; PSet_Revit_Type_Construction - Construction Type: Construction Type
M_Counter Top w Sink Hole:600mm Depth:600mm Depth:424045:1 | 1D32 | PSet_Revit_Other - InstallationDate: InstallationDate; SerialNumber: SerialNumber; WarrantyStartDate: WarrantyStartDate; BarCode: BarCode; AssetIdentifier: AssetIdentifier; TagNumber: TagNumber; PSet_Revit_Phasing - Phase Created: New Construction; PSet_Revit_Dimensions - Length: 1.2 m; Sink Location: 0.6 m; Sink Location To Wall: 0.16973 m; Sink Opening Depth: 0.391258 m; Sink Opening Width: 0.587 m; PSet_Revit_Type_Identity Data - Manufacturer: Manufacturer; OmniClass Number: 23.40.35.17.47.11; OmniClass Title: Kitchen Casework; PSet_Revit_Type_Other - AccessibilityPerformance: AccessibilityPerformance; CodePerformance: CodePerformance; Color: Color; Constituents: Constituents; Features: Features; Finish: Finish; Grade: Grade; Material: Material; ModelReference: ModelReference; NominalHeight: NominalHeight; NominalLength: NominalLength; NominalWidth: NominalWidth; ProductionYear: ProductionYear; Reference: Reference; Shape: Shape; Size: Size; SustainabilityPerformance: SustainabilityPerformance; WarrantyDescription: WarrantyDescription; WarrantyDurationLabor: WarrantyDurationLabor; WarrantyDurationParts: WarrantyDurationParts; WarrantyGuarantorLabor: WarrantyGuarantorLabor; WarrantyGuarantorParts: WarrantyGuarantorParts; ExpectedLife: ExpectedLife; ReplacementCost: ReplacementCost; AssetAccountingType: FIXED; ModelLabel: ModelLabel; Area: Area; PSet_Revit_Constraints - Level: First Floor; Host: Level : First Floor; Offset: 0 m; Moves With Nearby Elements: no; PSet_Revit_Type_Dimensions - Counter Thickness: 0.04 m; Depth: 0.625 m; Height: 0.9 m; PSet_Revit_Type_Materials and Finishes - Finish: Finish; PSet_Revit_Type_Construction - Construction Type: Construction Type
M_Counter Top w Sink Hole:600mm Depth:600mm Depth:424067:1 | 1D34 | PSet_Revit_Other - InstallationDate: InstallationDate; SerialNumber: SerialNumber; WarrantyStartDate: WarrantyStartDate; BarCode: BarCode; AssetIdentifier: AssetIdentifier; TagNumber: TagNumber; PSet_Revit_Phasing - Phase Created: New Construction; PSet_Revit_Dimensions - Length: 1.2 m; Sink Location: 0.6 m; Sink Location To Wall: 0.16973 m; Sink Opening Depth: 0.391258 m; Sink Opening Width: 0.587 m; PSet_Revit_Type_Identity Data - Manufacturer: Manufacturer; OmniClass Number: 23.40.35.17.47.11; OmniClass Title: Kitchen Casework; PSet_Revit_Type_Other - AccessibilityPerformance: AccessibilityPerformance; CodePerformance: CodePerformance; Color: Color; Constituents: Constituents; Features: Features; Finish: Finish; Grade: Grade; Material: Material; ModelReference: ModelReference; NominalHeight: NominalHeight; NominalLength: NominalLength; NominalWidth: NominalWidth; ProductionYear: ProductionYear; Reference: Reference; Shape: Shape; Size: Size; SustainabilityPerformance: SustainabilityPerformance; WarrantyDescription: WarrantyDescription; WarrantyDurationLabor: WarrantyDurationLabor; WarrantyDurationParts: WarrantyDurationParts; WarrantyGuarantorLabor: WarrantyGuarantorLabor; WarrantyGuarantorParts: WarrantyGuarantorParts; ExpectedLife: ExpectedLife; ReplacementCost: ReplacementCost; AssetAccountingType: FIXED; ModelLabel: ModelLabel; Area: Area; PSet_Revit_Constraints - Level: First Floor; Host: Level : First Floor; Offset: 0 m; Moves With Nearby Elements: no; PSet_Revit_Type_Dimensions - Counter Thickness: 0.04 m; Depth: 0.625 m; Height: 0.9 m; PSet_Revit_Type_Materials and Finishes - Finish: Finish; PSet_Revit_Type_Construction - Construction Type: Construction Type
M_Counter Top w Sink Hole:600mm Depth:600mm Depth:424069:1 | 1D36 | PSet_Revit_Other - InstallationDate: InstallationDate; SerialNumber: SerialNumber; WarrantyStartDate: WarrantyStartDate; BarCode: BarCode; AssetIdentifier: AssetIdentifier; TagNumber: TagNumber; PSet_Revit_Phasing - Phase Created: New Construction; PSet_Revit_Dimensions - Length: 1.2 m; Sink Location: 0.6 m; Sink Location To Wall: 0.16973 m; Sink Opening Depth: 0.391258 m; Sink Opening Width: 0.587 m; PSet_Revit_Type_Identity Data - Manufacturer: Manufacturer; OmniClass Number: 23.40.35.17.47.11; OmniClass Title: Kitchen Casework; PSet_Revit_Type_Other - AccessibilityPerformance: AccessibilityPerformance; CodePerformance: CodePerformance; Color: Color; Constituents: Constituents; Features: Features; Finish: Finish; Grade: Grade; Material: Material; ModelReference: ModelReference; NominalHeight: NominalHeight; NominalLength: NominalLength; NominalWidth: NominalWidth; ProductionYear: ProductionYear; Reference: Reference; Shape: Shape; Size: Size; SustainabilityPerformance: SustainabilityPerformance; WarrantyDescription: WarrantyDescription; WarrantyDurationLabor: WarrantyDurationLabor; WarrantyDurationParts: WarrantyDurationParts; WarrantyGuarantorLabor: WarrantyGuarantorLabor; WarrantyGuarantorParts: WarrantyGuarantorParts; ExpectedLife: ExpectedLife; ReplacementCost: ReplacementCost; AssetAccountingType: FIXED; ModelLabel: ModelLabel; Area: Area; PSet_Revit_Constraints - Level: First Floor; Host: Level : First Floor; Offset: 0 m; Moves With Nearby Elements: no; PSet_Revit_Type_Dimensions - Counter Thickness: 0.04 m; Depth: 0.625 m; Height: 0.9 m; PSet_Revit_Type_Materials and Finishes - Finish: Finish; PSet_Revit_Type_Construction - Construction Type: Construction Type
M_Counter Top w Sink Hole:600mm Depth:600mm Depth:424107:1 | 1D38 | PSet_Revit_Other - InstallationDate: InstallationDate; SerialNumber: SerialNumber; WarrantyStartDate: WarrantyStartDate; BarCode: BarCode; AssetIdentifier: AssetIdentifier; TagNumber: TagNumber; PSet_Revit_Phasing - Phase Created: New Construction; PSet_Revit_Dimensions - Length: 1.2 m; Sink Location: 0.842659 m; Sink Location To Wall: 0.16973 m; Sink Opening Depth: 0.391258 m; Sink Opening Width: 0.587 m; PSet_Revit_Type_Identity Data - Manufacturer: Manufacturer; OmniClass Number: 23.40.35.17.47.11; OmniClass Title: Kitchen Casework; PSet_Revit_Type_Other - AccessibilityPerformance: AccessibilityPerformance; CodePerformance: CodePerformance; Color: Color; Constituents: Constituents; Features: Features; Finish: Finish; Grade: Grade; Material: Material; ModelReference: ModelReference; NominalHeight: NominalHeight; NominalLength: NominalLength; NominalWidth: NominalWidth; ProductionYear: ProductionYear; Reference: Reference; Shape: Shape; Size: Size; SustainabilityPerformance: SustainabilityPerformance; WarrantyDescription: WarrantyDescription; WarrantyDurationLabor: WarrantyDurationLabor; WarrantyDurationParts: WarrantyDurationParts; WarrantyGuarantorLabor: WarrantyGuarantorLabor; WarrantyGuarantorParts: WarrantyGuarantorParts; ExpectedLife: ExpectedLife; ReplacementCost: ReplacementCost; AssetAccountingType: FIXED; ModelLabel: ModelLabel; Area: Area; PSet_Revit_Constraints - Level: First Floor; Host: Level : First Floor; Offset: 0 m; Moves With Nearby Elements: no; PSet_Revit_Type_Dimensions - Counter Thickness: 0.04 m; Depth: 0.625 m; Height: 0.9 m; PSet_Revit_Type_Materials and Finishes - Finish: Finish; PSet_Revit_Type_Construction - Construction Type: Construction Type
M_Counter Top w Sink Hole:600mm Depth:600mm Depth:424226:1 | 1D35 | PSet_Revit_Other - InstallationDate: InstallationDate; SerialNumber: SerialNumber; WarrantyStartDate: WarrantyStartDate; BarCode: BarCode; AssetIdentifier: AssetIdentifier; TagNumber: TagNumber; PSet_Revit_Phasing - Phase Created: New Construction; PSet_Revit_Dimensions - Length: 1.2 m; Sink Location: 0.6 m; Sink Location To Wall: 0.16973 m; Sink Opening Depth: 0.391258 m; Sink Opening Width: 0.587 m; PSet_Revit_Type_Identity Data - Manufacturer: Manufacturer; OmniClass Number: 23.40.35.17.47.11; OmniClass Title: Kitchen Casework; PSet_Revit_Type_Other - AccessibilityPerformance: AccessibilityPerformance; CodePerformance: CodePerformance; Color: Color; Constituents: Constituents; Features: Features; Finish: Finish; Grade: Grade; Material: Material; ModelReference: ModelReference; NominalHeight: NominalHeight; NominalLength: NominalLength; NominalWidth: NominalWidth; ProductionYear: ProductionYear; Reference: Reference; Shape: Shape; Size: Size; SustainabilityPerformance: SustainabilityPerformance; WarrantyDescription: WarrantyDescription; WarrantyDurationLabor: WarrantyDurationLabor; WarrantyDurationParts: WarrantyDurationParts; WarrantyGuarantorLabor: WarrantyGuarantorLabor; WarrantyGuarantorParts: WarrantyGuarantorParts; ExpectedLife: ExpectedLife; ReplacementCost: ReplacementCost; AssetAccountingType: FIXED; ModelLabel: ModelLabel; Area: Area; PSet_Revit_Constraints - Level: First Floor; Host: Level : First Floor; Offset: 0 m; Moves With Nearby Elements: no; PSet_Revit_Type_Dimensions - Counter Thickness: 0.04 m; Depth: 0.625 m; Height: 0.9 m; PSet_Revit_Type_Materials and Finishes - Finish: Finish; PSet_Revit_Type_Construction - Construction Type: Construction Type
M_Counter Top w Sink Hole:600mm Depth:600mm Depth:424255:1 | 1D31 | PSet_Revit_Other - InstallationDate: InstallationDate; SerialNumber: SerialNumber; WarrantyStartDate: WarrantyStartDate; BarCode: BarCode; AssetIdentifier: AssetIdentifier; TagNumber: TagNumber; PSet_Revit_Phasing - Phase Created: New Construction; PSet_Revit_Dimensions - Length: 1.2 m; Sink Location: 0.6 m; Sink Location To Wall: 0.16973 m; Sink Opening Depth: 0.391258 m; Sink Opening Width: 0.587 m; PSet_Revit_Type_Identity Data - Manufacturer: Manufacturer; OmniClass Number: 23.40.35.17.47.11; OmniClass Title: Kitchen Casework; PSet_Revit_Type_Other - AccessibilityPerformance: AccessibilityPerformance; CodePerformance: CodePerformance; Color: Color; Constituents: Constituents; Features: Features; Finish: Finish; Grade: Grade; Material: Material; ModelReference: ModelReference; NominalHeight: NominalHeight; NominalLength: NominalLength; NominalWidth: NominalWidth; ProductionYear: ProductionYear; Reference: Reference; Shape: Shape; Size: Size; SustainabilityPerformance: SustainabilityPerformance; WarrantyDescription: WarrantyDescription; WarrantyDurationLabor: WarrantyDurationLabor; WarrantyDurationParts: WarrantyDurationParts; WarrantyGuarantorLabor: WarrantyGuarantorLabor; WarrantyGuarantorParts: WarrantyGuarantorParts; ExpectedLife: ExpectedLife; ReplacementCost: ReplacementCost; AssetAccountingType: FIXED; ModelLabel: ModelLabel; Area: Area; PSet_Revit_Constraints - Level: First Floor; Host: Level : First Floor; Offset: 0 m; Moves With Nearby Elements: no; PSet_Revit_Type_Dimensions - Counter Thickness: 0.04 m; Depth: 0.625 m; Height: 0.9 m; PSet_Revit_Type_Materials and Finishes - Finish: Finish; PSet_Revit_Type_Construction - Construction Type: Construction Type
M_Counter Top w Sink Hole:600mm Depth:600mm Depth:424493:1 | 1B04 | PSet_Revit_Other - InstallationDate: InstallationDate; SerialNumber: SerialNumber; WarrantyStartDate: WarrantyStartDate; BarCode: BarCode; AssetIdentifier: AssetIdentifier; TagNumber: TagNumber; PSet_Revit_Phasing - Phase Created: New Construction; PSet_Revit_Dimensions - Length: 2.5 m; Sink Location: 1.628 m; Sink Location To Wall: 0.1 m; Sink Opening Depth: 0.378 m; Sink Opening Width: 0.587 m; PSet_Revit_Type_Identity Data - Manufacturer: Manufacturer; OmniClass Number: 23.40.35.17.47.11; OmniClass Title: Kitchen Casework; PSet_Revit_Type_Other - AccessibilityPerformance: AccessibilityPerformance; CodePerformance: CodePerformance; Color: Color; Constituents: Constituents; Features: Features; Finish: Finish; Grade: Grade; Material: Material; ModelReference: ModelReference; NominalHeight: NominalHeight; NominalLength: NominalLength; NominalWidth: NominalWidth; ProductionYear: ProductionYear; Reference: Reference; Shape: Shape; Size: Size; SustainabilityPerformance: SustainabilityPerformance; WarrantyDescription: WarrantyDescription; WarrantyDurationLabor: WarrantyDurationLabor; WarrantyDurationParts: WarrantyDurationParts; WarrantyGuarantorLabor: WarrantyGuarantorLabor; WarrantyGuarantorParts: WarrantyGuarantorParts; ExpectedLife: ExpectedLife; ReplacementCost: ReplacementCost; AssetAccountingType: FIXED; ModelLabel: ModelLabel; Area: Area; PSet_Revit_Constraints - Level: First Floor; Host: Level : First Floor; Offset: 0 m; Moves With Nearby Elements: no; PSet_Revit_Type_Dimensions - Counter Thickness: 0.04 m; Depth: 0.625 m; Height: 0.9 m; PSet_Revit_Type_Materials and Finishes - Finish: Finish; PSet_Revit_Type_Construction - Construction Type: Construction Type
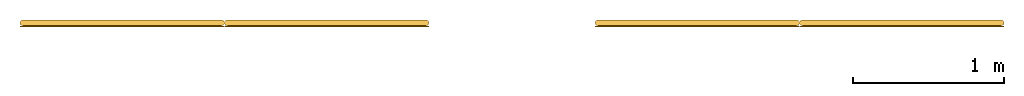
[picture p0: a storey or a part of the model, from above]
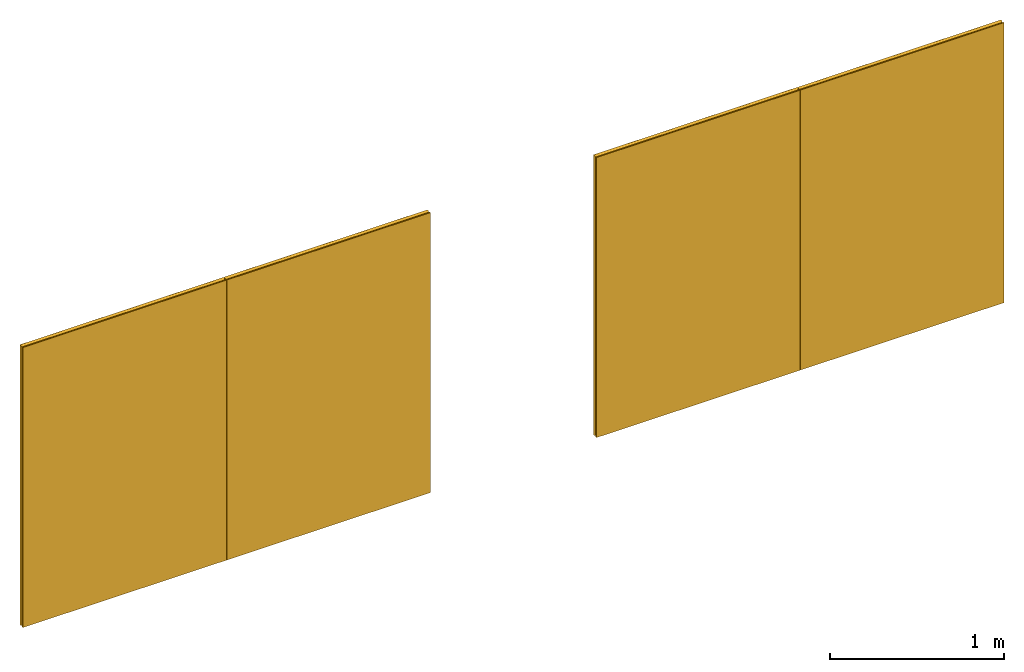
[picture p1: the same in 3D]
Properties of the parts of a building model (IFC2X3), part 8 of 11

# IfcOpeningElement: Opening (403)
Name | In
M_Counter Top w Sink Hole:600mm Depth:600mm Depth:424614:1 | 1B04 | PSet_Revit_Other - InstallationDate: InstallationDate; SerialNumber: SerialNumber; WarrantyStartDate: WarrantyStartDate; BarCode: BarCode; AssetIdentifier: AssetIdentifier; TagNumber: TagNumber; PSet_Revit_Phasing - Phase Created: New Construction; PSet_Revit_Dimensions - Length: 4.35711 m; Sink Location: 0.751909 m; Sink Location To Wall: 0.1 m; Sink Opening Depth: 0.378 m; Sink Opening Width: 0.587 m; PSet_Revit_Type_Identity Data - Manufacturer: Manufacturer; OmniClass Number: 23.40.35.17.47.11; OmniClass Title: Kitchen Casework; PSet_Revit_Type_Other - AccessibilityPerformance: AccessibilityPerformance; CodePerformance: CodePerformance; Color: Color; Constituents: Constituents; Features: Features; Finish: Finish; Grade: Grade; Material: Material; ModelReference: ModelReference; NominalHeight: NominalHeight; NominalLength: NominalLength; NominalWidth: NominalWidth; ProductionYear: ProductionYear; Reference: Reference; Shape: Shape; Size: Size; SustainabilityPerformance: SustainabilityPerformance; WarrantyDescription: WarrantyDescription; WarrantyDurationLabor: WarrantyDurationLabor; WarrantyDurationParts: WarrantyDurationParts; WarrantyGuarantorLabor: WarrantyGuarantorLabor; WarrantyGuarantorParts: WarrantyGuarantorParts; ExpectedLife: ExpectedLife; ReplacementCost: ReplacementCost; AssetAccountingType: FIXED; ModelLabel: ModelLabel; Area: Area; PSet_Revit_Constraints - Level: First Floor; Host: Level : First Floor; Offset: 0 m; Moves With Nearby Elements: no; PSet_Revit_Type_Dimensions - Counter Thickness: 0.04 m; Depth: 0.625 m; Height: 0.9 m; PSet_Revit_Type_Materials and Finishes - Finish: Finish; PSet_Revit_Type_Construction - Construction Type: Construction Type
M_Counter Top w Sink Hole:600mm Depth:600mm Depth:424797:1 | 1B04 | PSet_Revit_Other - InstallationDate: InstallationDate; SerialNumber: SerialNumber; WarrantyStartDate: WarrantyStartDate; BarCode: BarCode; AssetIdentifier: AssetIdentifier; TagNumber: TagNumber; PSet_Revit_Phasing - Phase Created: New Construction; PSet_Revit_Dimensions - Length: 2.57089 m; Sink Location: 1 m; Sink Location To Wall: 0.1 m; Sink Opening Depth: 0.378 m; Sink Opening Width: 0.587 m; PSet_Revit_Type_Identity Data - Manufacturer: Manufacturer; OmniClass Number: 23.40.35.17.47.11; OmniClass Title: Kitchen Casework; PSet_Revit_Type_Other - AccessibilityPerformance: AccessibilityPerformance; CodePerformance: CodePerformance; Color: Color; Constituents: Constituents; Features: Features; Finish: Finish; Grade: Grade; Material: Material; ModelReference: ModelReference; NominalHeight: NominalHeight; NominalLength: NominalLength; NominalWidth: NominalWidth; ProductionYear: ProductionYear; Reference: Reference; Shape: Shape; Size: Size; SustainabilityPerformance: SustainabilityPerformance; WarrantyDescription: WarrantyDescription; WarrantyDurationLabor: WarrantyDurationLabor; WarrantyDurationParts: WarrantyDurationParts; WarrantyGuarantorLabor: WarrantyGuarantorLabor; WarrantyGuarantorParts: WarrantyGuarantorParts; ExpectedLife: ExpectedLife; ReplacementCost: ReplacementCost; AssetAccountingType: FIXED; ModelLabel: ModelLabel; Area: Area; PSet_Revit_Constraints - Level: First Floor; Host: Level : First Floor; Offset: 0 m; Moves With Nearby Elements: no; PSet_Revit_Type_Dimensions - Counter Thickness: 0.04 m; Depth: 0.625 m; Height: 0.9 m; PSet_Revit_Type_Materials and Finishes - Finish: Finish; PSet_Revit_Type_Construction - Construction Type: Construction Type
M_Counter Top w Sink Hole:600mm Depth:600mm Depth:425594:1 | 2C14 | PSet_Revit_Other - InstallationDate: InstallationDate; SerialNumber: SerialNumber; WarrantyStartDate: WarrantyStartDate; BarCode: BarCode; AssetIdentifier: AssetIdentifier; TagNumber: TagNumber; PSet_Revit_Phasing - Phase Created: New Construction; PSet_Revit_Dimensions - Length: 2.10996 m; Sink Location: 0.338951 m; Sink Location To Wall: 0.1 m; Sink Opening Depth: 0.378 m; Sink Opening Width: 0.3556 m; PSet_Revit_Type_Identity Data - Manufacturer: Manufacturer; OmniClass Number: 23.40.35.17.47.11; OmniClass Title: Kitchen Casework; PSet_Revit_Type_Other - AccessibilityPerformance: AccessibilityPerformance; CodePerformance: CodePerformance; Color: Color; Constituents: Constituents; Features: Features; Finish: Finish; Grade: Grade; Material: Material; ModelReference: ModelReference; NominalHeight: NominalHeight; NominalLength: NominalLength; NominalWidth: NominalWidth; ProductionYear: ProductionYear; Reference: Reference; Shape: Shape; Size: Size; SustainabilityPerformance: SustainabilityPerformance; WarrantyDescription: WarrantyDescription; WarrantyDurationLabor: WarrantyDurationLabor; WarrantyDurationParts: WarrantyDurationParts; WarrantyGuarantorLabor: WarrantyGuarantorLabor; WarrantyGuarantorParts: WarrantyGuarantorParts; ExpectedLife: ExpectedLife; ReplacementCost: ReplacementCost; AssetAccountingType: FIXED; ModelLabel: ModelLabel; Area: Area; PSet_Revit_Constraints - Level: Second Floor; Host: Level : Second Floor; Offset: 0 m; Moves With Nearby Elements: no; PSet_Revit_Type_Dimensions - Counter Thickness: 0.04 m; Depth: 0.625 m; Height: 0.9 m; PSet_Revit_Type_Materials and Finishes - Finish: Finish; PSet_Revit_Type_Construction - Construction Type: Construction Type
M_Counter Top w Sink Hole:600mm Depth:600mm Depth:426710:1 | 2C09 | PSet_Revit_Other - InstallationDate: InstallationDate; SerialNumber: SerialNumber; WarrantyStartDate: WarrantyStartDate; BarCode: BarCode; AssetIdentifier: AssetIdentifier; TagNumber: TagNumber; PSet_Revit_Phasing - Phase Created: New Construction; PSet_Revit_Dimensions - Length: 2.10996 m; Sink Location: 0.338951 m; Sink Location To Wall: 0.1 m; Sink Opening Depth: 0.378 m; Sink Opening Width: 0.3556 m; PSet_Revit_Type_Identity Data - Manufacturer: Manufacturer; OmniClass Number: 23.40.35.17.47.11; OmniClass Title: Kitchen Casework; PSet_Revit_Type_Other - AccessibilityPerformance: AccessibilityPerformance; CodePerformance: CodePerformance; Color: Color; Constituents: Constituents; Features: Features; Finish: Finish; Grade: Grade; Material: Material; ModelReference: ModelReference; NominalHeight: NominalHeight; NominalLength: NominalLength; NominalWidth: NominalWidth; ProductionYear: ProductionYear; Reference: Reference; Shape: Shape; Size: Size; SustainabilityPerformance: SustainabilityPerformance; WarrantyDescription: WarrantyDescription; WarrantyDurationLabor: WarrantyDurationLabor; WarrantyDurationParts: WarrantyDurationParts; WarrantyGuarantorLabor: WarrantyGuarantorLabor; WarrantyGuarantorParts: WarrantyGuarantorParts; ExpectedLife: ExpectedLife; ReplacementCost: ReplacementCost; AssetAccountingType: FIXED; ModelLabel: ModelLabel; Area: Area; PSet_Revit_Constraints - Level: Second Floor; Host: Level : Second Floor; Offset: 0 m; Moves With Nearby Elements: no; PSet_Revit_Type_Dimensions - Counter Thickness: 0.04 m; Depth: 0.625 m; Height: 0.9 m; PSet_Revit_Type_Materials and Finishes - Finish: Finish; PSet_Revit_Type_Construction - Construction Type: Construction Type
M_Counter Top w Sink Hole:600mm Depth:600mm Depth:426720:1 | 2C06 | PSet_Revit_Other - InstallationDate: InstallationDate; SerialNumber: SerialNumber; WarrantyStartDate: WarrantyStartDate; BarCode: BarCode; AssetIdentifier: AssetIdentifier; TagNumber: TagNumber; PSet_Revit_Phasing - Phase Created: New Construction; PSet_Revit_Dimensions - Length: 2.10996 m; Sink Location: 0.338951 m; Sink Location To Wall: 0.1 m; Sink Opening Depth: 0.378 m; Sink Opening Width: 0.3556 m; PSet_Revit_Type_Identity Data - Manufacturer: Manufacturer; OmniClass Number: 23.40.35.17.47.11; OmniClass Title: Kitchen Casework; PSet_Revit_Type_Other - AccessibilityPerformance: AccessibilityPerformance; CodePerformance: CodePerformance; Color: Color; Constituents: Constituents; Features: Features; Finish: Finish; Grade: Grade; Material: Material; ModelReference: ModelReference; NominalHeight: NominalHeight; NominalLength: NominalLength; NominalWidth: NominalWidth; ProductionYear: ProductionYear; Reference: Reference; Shape: Shape; Size: Size; SustainabilityPerformance: SustainabilityPerformance; WarrantyDescription: WarrantyDescription; WarrantyDurationLabor: WarrantyDurationLabor; WarrantyDurationParts: WarrantyDurationParts; WarrantyGuarantorLabor: WarrantyGuarantorLabor; WarrantyGuarantorParts: WarrantyGuarantorParts; ExpectedLife: ExpectedLife; ReplacementCost: ReplacementCost; AssetAccountingType: FIXED; ModelLabel: ModelLabel; Area: Area; PSet_Revit_Constraints - Level: Second Floor; Host: Level : Second Floor; Offset: 0 m; Moves With Nearby Elements: no; PSet_Revit_Type_Dimensions - Counter Thickness: 0.04 m; Depth: 0.625 m; Height: 0.9 m; PSet_Revit_Type_Materials and Finishes - Finish: Finish; PSet_Revit_Type_Construction - Construction Type: Construction Type
M_Counter Top w Sink Hole:600mm Depth:600mm Depth:426730:1 | 2C04 | PSet_Revit_Other - InstallationDate: InstallationDate; SerialNumber: SerialNumber; WarrantyStartDate: WarrantyStartDate; BarCode: BarCode; AssetIdentifier: AssetIdentifier; TagNumber: TagNumber; PSet_Revit_Phasing - Phase Created: New Construction; PSet_Revit_Dimensions - Length: 2.10996 m; Sink Location: 0.338951 m; Sink Location To Wall: 0.1 m; Sink Opening Depth: 0.378 m; Sink Opening Width: 0.3556 m; PSet_Revit_Type_Identity Data - Manufacturer: Manufacturer; OmniClass Number: 23.40.35.17.47.11; OmniClass Title: Kitchen Casework; PSet_Revit_Type_Other - AccessibilityPerformance: AccessibilityPerformance; CodePerformance: CodePerformance; Color: Color; Constituents: Constituents; Features: Features; Finish: Finish; Grade: Grade; Material: Material; ModelReference: ModelReference; NominalHeight: NominalHeight; NominalLength: NominalLength; NominalWidth: NominalWidth; ProductionYear: ProductionYear; Reference: Reference; Shape: Shape; Size: Size; SustainabilityPerformance: SustainabilityPerformance; WarrantyDescription: WarrantyDescription; WarrantyDurationLabor: WarrantyDurationLabor; WarrantyDurationParts: WarrantyDurationParts; WarrantyGuarantorLabor: WarrantyGuarantorLabor; WarrantyGuarantorParts: WarrantyGuarantorParts; ExpectedLife: ExpectedLife; ReplacementCost: ReplacementCost; AssetAccountingType: FIXED; ModelLabel: ModelLabel; Area: Area; PSet_Revit_Constraints - Level: Second Floor; Host: Level : Second Floor; Offset: 0 m; Moves With Nearby Elements: no; PSet_Revit_Type_Dimensions - Counter Thickness: 0.04 m; Depth: 0.625 m; Height: 0.9 m; PSet_Revit_Type_Materials and Finishes - Finish: Finish; PSet_Revit_Type_Construction - Construction Type: Construction Type
M_Counter Top w Sink Hole:600mm Depth:600mm Depth:426738:1 | 2C02 | PSet_Revit_Other - InstallationDate: InstallationDate; SerialNumber: SerialNumber; WarrantyStartDate: WarrantyStartDate; BarCode: BarCode; AssetIdentifier: AssetIdentifier; TagNumber: TagNumber; PSet_Revit_Phasing - Phase Created: New Construction; PSet_Revit_Dimensions - Length: 2.10996 m; Sink Location: 0.338951 m; Sink Location To Wall: 0.1 m; Sink Opening Depth: 0.378 m; Sink Opening Width: 0.3556 m; PSet_Revit_Type_Identity Data - Manufacturer: Manufacturer; OmniClass Number: 23.40.35.17.47.11; OmniClass Title: Kitchen Casework; PSet_Revit_Type_Other - AccessibilityPerformance: AccessibilityPerformance; CodePerformance: CodePerformance; Color: Color; Constituents: Constituents; Features: Features; Finish: Finish; Grade: Grade; Material: Material; ModelReference: ModelReference; NominalHeight: NominalHeight; NominalLength: NominalLength; NominalWidth: NominalWidth; ProductionYear: ProductionYear; Reference: Reference; Shape: Shape; Size: Size; SustainabilityPerformance: SustainabilityPerformance; WarrantyDescription: WarrantyDescription; WarrantyDurationLabor: WarrantyDurationLabor; WarrantyDurationParts: WarrantyDurationParts; WarrantyGuarantorLabor: WarrantyGuarantorLabor; WarrantyGuarantorParts: WarrantyGuarantorParts; ExpectedLife: ExpectedLife; ReplacementCost: ReplacementCost; AssetAccountingType: FIXED; ModelLabel: ModelLabel; Area: Area; PSet_Revit_Constraints - Level: Second Floor; Host: Level : Second Floor; Offset: 0 m; Moves With Nearby Elements: no; PSet_Revit_Type_Dimensions - Counter Thickness: 0.04 m; Depth: 0.625 m; Height: 0.9 m; PSet_Revit_Type_Materials and Finishes - Finish: Finish; PSet_Revit_Type_Construction - Construction Type: Construction Type
M_Counter Top w Sink Hole:600mm Depth:600mm Depth:426746:1 | 2A09 | PSet_Revit_Other - InstallationDate: InstallationDate; SerialNumber: SerialNumber; WarrantyStartDate: WarrantyStartDate; BarCode: BarCode; AssetIdentifier: AssetIdentifier; TagNumber: TagNumber; PSet_Revit_Phasing - Phase Created: New Construction; PSet_Revit_Dimensions - Length: 2.10996 m; Sink Location: 0.338951 m; Sink Location To Wall: 0.1 m; Sink Opening Depth: 0.378 m; Sink Opening Width: 0.3556 m; PSet_Revit_Type_Identity Data - Manufacturer: Manufacturer; OmniClass Number: 23.40.35.17.47.11; OmniClass Title: Kitchen Casework; PSet_Revit_Type_Other - AccessibilityPerformance: AccessibilityPerformance; CodePerformance: CodePerformance; Color: Color; Constituents: Constituents; Features: Features; Finish: Finish; Grade: Grade; Material: Material; ModelReference: ModelReference; NominalHeight: NominalHeight; NominalLength: NominalLength; NominalWidth: NominalWidth; ProductionYear: ProductionYear; Reference: Reference; Shape: Shape; Size: Size; SustainabilityPerformance: SustainabilityPerformance; WarrantyDescription: WarrantyDescription; WarrantyDurationLabor: WarrantyDurationLabor; WarrantyDurationParts: WarrantyDurationParts; WarrantyGuarantorLabor: WarrantyGuarantorLabor; WarrantyGuarantorParts: WarrantyGuarantorParts; ExpectedLife: ExpectedLife; ReplacementCost: ReplacementCost; AssetAccountingType: FIXED; ModelLabel: ModelLabel; Area: Area; PSet_Revit_Constraints - Level: Second Floor; Host: Level : Second Floor; Offset: 0 m; Moves With Nearby Elements: no; PSet_Revit_Type_Dimensions - Counter Thickness: 0.04 m; Depth: 0.625 m; Height: 0.9 m; PSet_Revit_Type_Materials and Finishes - Finish: Finish; PSet_Revit_Type_Construction - Construction Type: Construction Type
M_Counter Top w Sink Hole:600mm Depth:600mm Depth:426758:1 | 2A08 | PSet_Revit_Other - InstallationDate: InstallationDate; SerialNumber: SerialNumber; WarrantyStartDate: WarrantyStartDate; BarCode: BarCode; AssetIdentifier: AssetIdentifier; TagNumber: TagNumber; PSet_Revit_Phasing - Phase Created: New Construction; PSet_Revit_Dimensions - Length: 2.10996 m; Sink Location: 0.338951 m; Sink Location To Wall: 0.1 m; Sink Opening Depth: 0.378 m; Sink Opening Width: 0.3556 m; PSet_Revit_Type_Identity Data - Manufacturer: Manufacturer; OmniClass Number: 23.40.35.17.47.11; OmniClass Title: Kitchen Casework; PSet_Revit_Type_Other - AccessibilityPerformance: AccessibilityPerformance; CodePerformance: CodePerformance; Color: Color; Constituents: Constituents; Features: Features; Finish: Finish; Grade: Grade; Material: Material; ModelReference: ModelReference; NominalHeight: NominalHeight; NominalLength: NominalLength; NominalWidth: NominalWidth; ProductionYear: ProductionYear; Reference: Reference; Shape: Shape; Size: Size; SustainabilityPerformance: SustainabilityPerformance; WarrantyDescription: WarrantyDescription; WarrantyDurationLabor: WarrantyDurationLabor; WarrantyDurationParts: WarrantyDurationParts; WarrantyGuarantorLabor: WarrantyGuarantorLabor; WarrantyGuarantorParts: WarrantyGuarantorParts; ExpectedLife: ExpectedLife; ReplacementCost: ReplacementCost; AssetAccountingType: FIXED; ModelLabel: ModelLabel; Area: Area; PSet_Revit_Constraints - Level: Second Floor; Host: Level : Second Floor; Offset: 0 m; Moves With Nearby Elements: no; PSet_Revit_Type_Dimensions - Counter Thickness: 0.04 m; Depth: 0.625 m; Height: 0.9 m; PSet_Revit_Type_Materials and Finishes - Finish: Finish; PSet_Revit_Type_Construction - Construction Type: Construction Type
M_Counter Top w Sink Hole:600mm Depth:600mm Depth:426806:1 | 2A07 | PSet_Revit_Other - InstallationDate: InstallationDate; SerialNumber: SerialNumber; WarrantyStartDate: WarrantyStartDate; BarCode: BarCode; AssetIdentifier: AssetIdentifier; TagNumber: TagNumber; PSet_Revit_Phasing - Phase Created: New Construction; PSet_Revit_Dimensions - Length: 2.10996 m; Sink Location: 0.338951 m; Sink Location To Wall: 0.1 m; Sink Opening Depth: 0.378 m; Sink Opening Width: 0.3556 m; PSet_Revit_Type_Identity Data - Manufacturer: Manufacturer; OmniClass Number: 23.40.35.17.47.11; OmniClass Title: Kitchen Casework; PSet_Revit_Type_Other - AccessibilityPerformance: AccessibilityPerformance; CodePerformance: CodePerformance; Color: Color; Constituents: Constituents; Features: Features; Finish: Finish; Grade: Grade; Material: Material; ModelReference: ModelReference; NominalHeight: NominalHeight; NominalLength: NominalLength; NominalWidth: NominalWidth; ProductionYear: ProductionYear; Reference: Reference; Shape: Shape; Size: Size; SustainabilityPerformance: SustainabilityPerformance; WarrantyDescription: WarrantyDescription; WarrantyDurationLabor: WarrantyDurationLabor; WarrantyDurationParts: WarrantyDurationParts; WarrantyGuarantorLabor: WarrantyGuarantorLabor; WarrantyGuarantorParts: WarrantyGuarantorParts; ExpectedLife: ExpectedLife; ReplacementCost: ReplacementCost; AssetAccountingType: FIXED; ModelLabel: ModelLabel; Area: Area; PSet_Revit_Constraints - Level: Second Floor; Host: Level : Second Floor; Offset: 0 m; Moves With Nearby Elements: no; PSet_Revit_Type_Dimensions - Counter Thickness: 0.04 m; Depth: 0.625 m; Height: 0.9 m; PSet_Revit_Type_Materials and Finishes - Finish: Finish; PSet_Revit_Type_Construction - Construction Type: Construction Type
M_Counter Top w Sink Hole:600mm Depth:600mm Depth:426851:1 | 2A06 | PSet_Revit_Other - InstallationDate: InstallationDate; SerialNumber: SerialNumber; WarrantyStartDate: WarrantyStartDate; BarCode: BarCode; AssetIdentifier: AssetIdentifier; TagNumber: TagNumber; PSet_Revit_Phasing - Phase Created: New Construction; PSet_Revit_Dimensions - Length: 2.10996 m; Sink Location: 0.338951 m; Sink Location To Wall: 0.1 m; Sink Opening Depth: 0.378 m; Sink Opening Width: 0.3556 m; PSet_Revit_Type_Identity Data - Manufacturer: Manufacturer; OmniClass Number: 23.40.35.17.47.11; OmniClass Title: Kitchen Casework; PSet_Revit_Type_Other - AccessibilityPerformance: AccessibilityPerformance; CodePerformance: CodePerformance; Color: Color; Constituents: Constituents; Features: Features; Finish: Finish; Grade: Grade; Material: Material; ModelReference: ModelReference; NominalHeight: NominalHeight; NominalLength: NominalLength; NominalWidth: NominalWidth; ProductionYear: ProductionYear; Reference: Reference; Shape: Shape; Size: Size; SustainabilityPerformance: SustainabilityPerformance; WarrantyDescription: WarrantyDescription; WarrantyDurationLabor: WarrantyDurationLabor; WarrantyDurationParts: WarrantyDurationParts; WarrantyGuarantorLabor: WarrantyGuarantorLabor; WarrantyGuarantorParts: WarrantyGuarantorParts; ExpectedLife: ExpectedLife; ReplacementCost: ReplacementCost; AssetAccountingType: FIXED; ModelLabel: ModelLabel; Area: Area; PSet_Revit_Constraints - Level: Second Floor; Host: Level : Second Floor; Offset: 0 m; Moves With Nearby Elements: no; PSet_Revit_Type_Dimensions - Counter Thickness: 0.04 m; Depth: 0.625 m; Height: 0.9 m; PSet_Revit_Type_Materials and Finishes - Finish: Finish; PSet_Revit_Type_Construction - Construction Type: Construction Type
M_Counter Top w Sink Hole:600mm Depth:600mm Depth:426911:1 | 2A05 | PSet_Revit_Other - InstallationDate: InstallationDate; SerialNumber: SerialNumber; WarrantyStartDate: WarrantyStartDate; BarCode: BarCode; AssetIdentifier: AssetIdentifier; TagNumber: TagNumber; PSet_Revit_Phasing - Phase Created: New Construction; PSet_Revit_Dimensions - Length: 2.10996 m; Sink Location: 0.338951 m; Sink Location To Wall: 0.1 m; Sink Opening Depth: 0.378 m; Sink Opening Width: 0.3556 m; PSet_Revit_Type_Identity Data - Manufacturer: Manufacturer; OmniClass Number: 23.40.35.17.47.11; OmniClass Title: Kitchen Casework; PSet_Revit_Type_Other - AccessibilityPerformance: AccessibilityPerformance; CodePerformance: CodePerformance; Color: Color; Constituents: Constituents; Features: Features; Finish: Finish; Grade: Grade; Material: Material; ModelReference: ModelReference; NominalHeight: NominalHeight; NominalLength: NominalLength; NominalWidth: NominalWidth; ProductionYear: ProductionYear; Reference: Reference; Shape: Shape; Size: Size; SustainabilityPerformance: SustainabilityPerformance; WarrantyDescription: WarrantyDescription; WarrantyDurationLabor: WarrantyDurationLabor; WarrantyDurationParts: WarrantyDurationParts; WarrantyGuarantorLabor: WarrantyGuarantorLabor; WarrantyGuarantorParts: WarrantyGuarantorParts; ExpectedLife: ExpectedLife; ReplacementCost: ReplacementCost; AssetAccountingType: FIXED; ModelLabel: ModelLabel; Area: Area; PSet_Revit_Constraints - Level: Second Floor; Host: Level : Second Floor; Offset: 0 m; Moves With Nearby Elements: no; PSet_Revit_Type_Dimensions - Counter Thickness: 0.04 m; Depth: 0.625 m; Height: 0.9 m; PSet_Revit_Type_Materials and Finishes - Finish: Finish; PSet_Revit_Type_Construction - Construction Type: Construction Type
 | Second Floor | Pset_WallCommon - Reference: Basic Wall:Interior - Partition (92mm Stud); LoadBearing: no; ExtendToStructure: no; IsExternal: no; PSet_Revit_Constraints - Location Line: 2; Base Constraint: Second Floor; Base Offset: 0 m; Base is Attached: no; Base Extension Distance: 0 m; Top Constraint: Up to level: Roof - Main; Unconnected Height: 4.578 m; Top Offset: -0.102 m; Top is Attached: no; Top Extension Distance: 0 m; Room Bounding: yes; Related to Mass: no; PSet_Revit_Other - InstallationDate: InstallationDate; SerialNumber: SerialNumber; WarrantyStartDate: WarrantyStartDate; BarCode: BarCode; AssetIdentifier: AssetIdentifier; TagNumber: TagNumber; PSet_Revit_Phasing - Phase Created: New Construction; PSet_Revit_Structural - Structural Usage: 0; PSet_Revit_Dimensions - Length: 3.98706 m; Area: 16.0163 m2; Volume: 1.94988 m3; PSet_Revit_Type_Construction - Wrapping at Inserts: 0; Wrapping at Ends: 2; Width: 0.124 m; Function: 0; PSet_Revit_Type_Graphics - Coarse Scale Fill Color: 0; PSet_Revit_Type_Identity Data - Manufacturer: Manufacturer; PSet_Revit_Type_Other - AccessibilityPerformance: AccessibilityPerformance; CodePerformance: CodePerformance; Color: Color; Constituents: Constituents; Features: Features; Finish: Finish; Grade: Grade; Material: Material; ModelReference: ModelReference; NominalHeight: NominalHeight; NominalLength: NominalLength; NominalWidth: NominalWidth; ProductionYear: ProductionYear; Reference: Reference; Shape: Shape; Size: Size; SustainabilityPerformance: SustainabilityPerformance; WarrantyDescription: WarrantyDescription; WarrantyDurationLabor: WarrantyDurationLabor; WarrantyDurationParts: WarrantyDurationParts; WarrantyGuarantorLabor: WarrantyGuarantorLabor; WarrantyGuarantorParts: WarrantyGuarantorParts; ExpectedLife: ExpectedLife; ReplacementCost: ReplacementCost; AssetAccountingType: FIXED; Classification Code: 23-25 40 11 11 11; Classification Description: Metal-Framed Gypsum Board Fixed Partitions; ModelLabel: ModelLabel
M_Single-Flush:0915 x 2134mm Rated:0915 x 2134mm Rated:471867:1 | First Floor
24 x :1 | First Floor
13 x :1 | Second Floor

# IfcPlate: Chain Link Fence Panel (5)
In: First Floor
Type - ElementType: Chain Link Fence Panel; PredefinedType: CURTAIN_PANEL
Material: Metal - Chain Link
PSet_Revit_Dimensions - Height: 2 m
PSet_Revit_Other - InstallationDate: InstallationDate; SerialNumber: SerialNumber; WarrantyStartDate: WarrantyStartDate; BarCode: BarCode; AssetIdentifier: AssetIdentifier; TagNumber: TagNumber
PSet_Revit_Phasing - Phase Created: New Construction
PSet_Revit_Type_Dimensions - Thickness: 0.008 m
PSet_Revit_Type_Constraints - Offset: 0.025 m
PSet_Revit_Type_Materials and Finishes - Material: Metal - Chain Link; Finish: Finish
PSet_Revit_Type_Identity Data - Manufacturer: Manufacturer
PSet_Revit_Type_Construction - Construction Type: Construction Type
PSet_Revit_Type_Other - AccessibilityPerformance: AccessibilityPerformance; CodePerformance: CodePerformance; Color: Color; Constituents: Constituents; Features: Features; Finish: Finish; Grade: Grade; Material: Material; ModelReference: ModelReference; NominalHeight: NominalHeight; NominalLength: NominalLength; NominalWidth: NominalWidth; ProductionYear: ProductionYear; Reference: Reference; Shape: Shape; Size: Size; SustainabilityPerformance: SustainabilityPerformance; WarrantyDescription: WarrantyDescription; WarrantyDurationLabor: WarrantyDurationLabor; WarrantyDurationParts: WarrantyDurationParts; WarrantyGuarantorLabor: WarrantyGuarantorLabor; WarrantyGuarantorParts: WarrantyGuarantorParts; ExpectedLife: ExpectedLife; ReplacementCost: ReplacementCost; AssetAccountingType: FIXED; ModelLabel: ModelLabel
Name (System Panel:Chain Link Fence Panel:Chain Link Fence Panel:...) | Area (m2) | Width (m)
346964 | 0.825153 | 0.412576
346971 | 2.12074 | 1.06037
346975 | 3.29826 | 1.64913
347581 | 2.2 | 1.1
347585 | 2.2 | 1.1

# IfcPlate: Glazed (167)
Type - ElementType: Glazed; PredefinedType: CURTAIN_PANEL
Material: Glass
PSet_Revit_Other - InstallationDate: InstallationDate; SerialNumber: SerialNumber; WarrantyStartDate: WarrantyStartDate; BarCode: BarCode; AssetIdentifier: AssetIdentifier; TagNumber: TagNumber
PSet_Revit_Phasing - Phase Created: New Construction
PSet_Revit_Type_Dimensions - Thickness: 0.025 m
PSet_Revit_Type_Constraints - Offset: 0.037 m
PSet_Revit_Type_Materials and Finishes - Material: Glass; Finish: Finish
PSet_Revit_Type_Identity Data - Manufacturer: Manufacturer
PSet_Revit_Type_Construction - Construction Type: Construction Type
PSet_Revit_Type_Other - AccessibilityPerformance: AccessibilityPerformance; CodePerformance: CodePerformance; Color: Color; Constituents: Constituents; Features: Features; Finish: Finish; Grade: Grade; Material: Material; ModelReference: ModelReference; NominalHeight: NominalHeight; NominalLength: NominalLength; NominalWidth: NominalWidth; ProductionYear: ProductionYear; Reference: Reference; Shape: Shape; Size: Size; SustainabilityPerformance: SustainabilityPerformance; WarrantyDescription: WarrantyDescription; WarrantyDurationLabor: WarrantyDurationLabor; WarrantyDurationParts: WarrantyDurationParts; WarrantyGuarantorLabor: WarrantyGuarantorLabor; WarrantyGuarantorParts: WarrantyGuarantorParts; ExpectedLife: ExpectedLife; ReplacementCost: ReplacementCost; AssetAccountingType: FIXED; ModelLabel: ModelLabel
Name (System Panel:Glazed:Glazed:...) | In | Area (m2) | Width (m) | Height (m)
281382 | Second Floor | 3.30289 | 1.43604 | 2.3
281401 | Second Floor | 3.36039 | 1.46104 | 2.3
281403 | Second Floor | 3.36039 | 1.46104 | 2.3
281405 | Second Floor | 3.30289 | 1.43604 | 2.3
281016 | Second Floor | 3.04721 | 1.32488 | 2.3
281023 | Second Floor | 3.10471 | 1.34988 | 2.3
281025 | Second Floor | 3.10471 | 1.34988 | 2.3
281027 | Second Floor | 3.10471 | 1.34988 | 2.3
281029 | Second Floor | 3.10471 | 1.34988 | 2.3
281031 | Second Floor | 3.10471 | 1.34988 | 2.3
281033 | Second Floor | 3.10471 | 1.34988 | 2.3
281035 | Second Floor | 3.04721 | 1.32488 | 2.3
256999 | First Floor | 1.41987 | 0.925 | 1.535
257004 | First Floor | 2.22614 | 1.45026 | 1.535
257006 | First Floor | 2.22614 | 1.45026 | 1.535
257008 | First Floor | 1.41987 | 0.925 | 1.535
258060 | First Floor | 1.41987 | 0.925 | 1.535
258062 | First Floor | 2.22575 | 1.45 | 1.535
258064 | First Floor | 2.22575 | 1.45 | 1.535
258066 | First Floor | 1.41987 | 0.925 | 1.535
258776 | First Floor | 2.18737 | 1.425 | 1.535
258778 | First Floor | 1.45825 | 0.95 | 1.535
258780 | First Floor | 2.18737 | 1.425 | 1.535
263356 | First Floor | 2.17387 | 0.935 | 2.325
263361 | First Floor | 2.17387 | 0.935 | 2.325
263363 | First Floor | 1.22485 | 0.935 | 1.31
263364 | First Floor | 2.358 | 1.8 | 1.31
263365 | First Floor | 1.22485 | 0.935 | 1.31
264722 | First Floor | 0.014025 | 0.935 | 0.015
264723 | First Floor | 0.027 | 1.8 | 0.015
264724 | First Floor | 0.014025 | 0.935 | 0.015
264726 | First Floor | 1.17943
264727 | First Floor | 2.52727
264728 | First Floor | 1.17943
283073 | First Floor | 0.44525 | 1.37 | 0.325
285039 | First Floor | 0.974174 | 0.418999 | 2.325
283423 | First Floor | 1.89487 | 0.815 | 2.325
283426 | First Floor | 0.264875 | 0.815 | 0.325
283651 | First Floor | 2.32887 | 1.00167 | 2.325
283655 | First Floor | 2.387 | 1.02667 | 2.325
283657 | First Floor | 2.32887 | 1.00167 | 2.325
283659 | First Floor | 0.325542 | 1.00167 | 0.325
283660 | First Floor | 0.333667 | 1.02667 | 0.325
283661 | First Floor | 0.325542 | 1.00167 | 0.325
283768 | First Floor | 1.89487 | 0.815 | 2.325
283771 | First Floor | 0.264875 | 0.815 | 0.325
283883 | First Floor | 0.976499 | 0.419999 | 2.325
283887 | First Floor | 0.445103 | 1.36955 | 0.325
284082 | First Floor | 2.32887 | 1.00167 | 2.325
284088 | First Floor | 2.387 | 1.02667 | 2.325
284090 | First Floor | 2.32887 | 1.00167 | 2.325
284092 | First Floor | 0.325542 | 1.00167 | 0.325
284093 | First Floor | 0.333667 | 1.02667 | 0.325
284094 | First Floor | 0.325542 | 1.00167 | 0.325
284568 | First Floor | 0.6228 | 0.692 | 0.9
284573 | First Floor | 0.6228 | 0.692 | 0.9
285991 | Second Floor | 2.63969 | 1.14769 | 2.3
285996 | Second Floor | 2.69719 | 1.17269 | 2.3
285998 | Second Floor | 2.69719 | 1.17269 | 2.3
286000 | Second Floor | 2.63969 | 1.14769 | 2.3
295591 | Second Floor | 1.72396
295596 | Second Floor | 1.61114
295598 | Second Floor | 1.72396
314094 | Second Floor | 0.867787
314095 | Second Floor | 1.11108
314096 | Second Floor | 0.867788
296058 | Second Floor | 2.07949
296063 | Second Floor | 2.01808
296065 | Second Floor | 2.01713
296067 | Second Floor | 2.08124
298262 | Roof - Main | 1.85896
298267 | Roof - Main | 1.84829
298269 | Roof - Main | 1.78843
298271 | Roof - Main | 1.78793
298273 | Roof - Main | 1.84672
298275 | Roof - Main | 1.85755
300136 | Roof - Main | 1.91225
300142 | Roof - Main | 1.86507
300148 | Roof - Main | 1.86505
300150 | Roof - Main | 1.91222
304459 | Roof - Main | 1.82612
304460 | Roof - Main | 1.82611
301676 | Roof - Main | 1.13476 | 1.2444 | 0.911894
301680 | Roof - Main | 1.15755 | 1.2694 | 0.911894
301682 | Roof - Main | 1.15755 | 1.2694 | 0.911894
301684 | Roof - Main | 1.15755 | 1.2694 | 0.911894
301686 | Roof - Main | 1.15755 | 1.2694 | 0.911894
301688 | Roof - Main | 1.13476 | 1.2444 | 0.911894
301690 | Roof - Main | 1.69394
301691 | Roof - Main | 1.73032 | 1.2694 | 1.36311
301692 | Roof - Main | 1.73032 | 1.2694 | 1.36311
301693 | Roof - Main | 1.73032 | 1.2694 | 1.36311
301694 | Roof - Main | 1.73032 | 1.2694 | 1.36311
301695 | Roof - Main | 1.69394
307707 | Roof - Main | 0.171878
307708 | Roof - Main | 0.609917
307709 | Roof - Main | 0.830402
307710 | Roof - Main | 0.830402
307711 | Roof - Main | 0.609917
307712 | Roof - Main | 0.171878
303220 | Roof - Main | 1.11251 | 1.22 | 0.911894
303225 | Roof - Main | 1.13531 | 1.245 | 0.911894
303227 | Roof - Main | 1.13531 | 1.245 | 0.911894
303229 | Roof - Main | 1.11251 | 1.22 | 0.911894
303245 | Roof - Main | 0.900489 | 1.22 | 0.738106
303246 | Roof - Main | 0.918941 | 1.245 | 0.738106
303247 | Roof - Main | 0.918941 | 1.245 | 0.738106
303248 | Roof - Main | 0.900489 | 1.22 | 0.738106
356368 | First Floor | 0.7335 | 0.815 | 0.9
303241 | Roof - Main | 1.13683 | 1.24667 | 0.911894
303243 | Roof - Main | 1.11403 | 1.22167 | 0.911894
303254 | Roof - Main | 0.920172 | 1.24667 | 0.738106
303255 | Roof - Main | 0.901719 | 1.22167 | 0.738106
374931 | Roof - Main | 1.11403 | 1.22167 | 0.911894
374932 | Roof - Main | 0.901719 | 1.22167 | 0.738106
303231 | Roof - Main | 1.21373 | 1.331 | 0.911894
303233 | Roof - Main | 1.21373 | 1.331 | 0.911894
303235 | Roof - Main | 1.21373 | 1.331 | 0.911894
303237 | Roof - Main | 1.19093 | 1.306 | 0.911894
303249 | Roof - Main | 0.982418 | 1.331 | 0.738106
303250 | Roof - Main | 0.982418 | 1.331 | 0.738106
303251 | Roof - Main | 0.982418 | 1.331 | 0.738106
303252 | Roof - Main | 0.963966 | 1.306 | 0.738106
375155 | Roof - Main | 1.19093 | 1.306 | 0.911894
375156 | Roof - Main | 0.963966 | 1.306 | 0.738106
379198 | Second Floor | 2.98741 | 1.29888 | 2.3
379204 | Second Floor | 3.04491 | 1.32388 | 2.3
379206 | Second Floor | 3.04491 | 1.32388 | 2.3
379208 | Second Floor | 3.04491 | 1.32388 | 2.3
379210 | Second Floor | 3.04491 | 1.32388 | 2.3
379212 | Second Floor | 3.04491 | 1.32388 | 2.3
379214 | Second Floor | 3.04491 | 1.32388 | 2.3
379216 | Second Floor | 2.98741 | 1.29888 | 2.3
379240 | Second Floor | 2.63969 | 1.14769 | 2.3
379242 | Second Floor | 2.69719 | 1.17269 | 2.3
379244 | Second Floor | 2.69719 | 1.17269 | 2.3
379246 | Second Floor | 2.63969 | 1.14769 | 2.3
381805 | Roof - Main | 1.85896
381807 | Roof - Main | 1.84829
381809 | Roof - Main | 1.78843
381811 | Roof - Main | 1.78793
381813 | Roof - Main | 1.84672
381815 | Roof - Main | 1.85755
381860 | Roof - Main | 1.11251 | 1.22 | 0.911894
381862 | Roof - Main | 1.13531 | 1.245 | 0.911894
381864 | Roof - Main | 1.13531 | 1.245 | 0.911894
381866 | Roof - Main | 1.11251 | 1.22 | 0.911894
381880 | Roof - Main | 0.900489 | 1.22 | 0.738106
381881 | Roof - Main | 0.918941 | 1.245 | 0.738106
381882 | Roof - Main | 0.918941 | 1.245 | 0.738106
381883 | Roof - Main | 0.900489 | 1.22 | 0.738106
381876 | Roof - Main | 1.13683 | 1.24667 | 0.911894
381878 | Roof - Main | 1.11403 | 1.22167 | 0.911894
381888 | Roof - Main | 0.920172 | 1.24667 | 0.738106
381889 | Roof - Main | 0.901719 | 1.22167 | 0.738106
381960 | Roof - Main | 1.11403 | 1.22167 | 0.911894
381961 | Roof - Main | 0.901719 | 1.22167 | 0.738106
381868 | Roof - Main | 1.21373 | 1.331 | 0.911894
381870 | Roof - Main | 1.21373 | 1.331 | 0.911894
381872 | Roof - Main | 1.21373 | 1.331 | 0.911894
381874 | Roof - Main | 1.19093 | 1.306 | 0.911894
381884 | Roof - Main | 0.982418 | 1.331 | 0.738106
381885 | Roof - Main | 0.982418 | 1.331 | 0.738106
381886 | Roof - Main | 0.982418 | 1.331 | 0.738106
381887 | Roof - Main | 0.963966 | 1.306 | 0.738106
381971 | Roof - Main | 1.19093 | 1.306 | 0.911894
381972 | Roof - Main | 0.963966 | 1.306 | 0.738106

# IfcRailing: Railing:1100mm Guard Rail (9)
Pset_RailingCommon - Reference: Railing:1100mm Guard Rail; IsExternal: no; Height: 1.1
PSet_Revit_Constraints - Base Offset: 0 m
PSet_Revit_Other - InstallationDate: InstallationDate; SerialNumber: SerialNumber; WarrantyStartDate: WarrantyStartDate; BarCode: BarCode; AssetIdentifier: AssetIdentifier; TagNumber: TagNumber
PSet_Revit_Phasing - Phase Created: New Construction
PSet_Revit_Type_Construction - Railing Height: 1.1 m; Baluster Offset: -0.025 m; Use Landing Height Adjustment: 0; Landing Height Adjustment: 0 m; Angled Joins: 0; Tangent Joins: 2; Rail Connections: 0
PSet_Revit_Type_Identity Data - Manufacturer: Manufacturer
PSet_Revit_Type_Other - AccessibilityPerformance: AccessibilityPerformance; CodePerformance: CodePerformance; Color: Color; Constituents: Constituents; Features: Features; Finish: Finish; Grade: Grade; Material: Material; ModelReference: ModelReference; NominalHeight: NominalHeight; NominalLength: NominalLength; NominalWidth: NominalWidth; ProductionYear: ProductionYear; Reference: Reference; Shape: Shape; Size: Size; SustainabilityPerformance: SustainabilityPerformance; WarrantyDescription: WarrantyDescription; WarrantyDurationLabor: WarrantyDurationLabor; WarrantyDurationParts: WarrantyDurationParts; WarrantyGuarantorLabor: WarrantyGuarantorLabor; WarrantyGuarantorParts: WarrantyGuarantorParts; ExpectedLife: ExpectedLife; ReplacementCost: ReplacementCost; AssetAccountingType: FIXED; Classification Code: 23-30 80 11; Classification Description: Guardrails; ModelLabel: ModelLabel
Name (Railing:1100mm Guard Rail:...) | In | Length (m)
221234 | First Floor | 10.5256
221238 | First Floor | 13.9367
250952 | First Floor | 13.6455
250956 | First Floor | 9.70191
251724 | First Floor | 9.90791
251728 | First Floor | 13.6115
288074 | Second Floor | 6.70505 | PSet_Revit_Constraints - Base Level: Second Floor
288269 | Second Floor | 6.63004 | PSet_Revit_Constraints - Base Level: Second Floor
419500 | First Floor | 1.624 | PSet_Revit_Constraints - Base Level: First Floor

# IfcSlab: Stair:Concrete Pan - 180mm Max Riser 280mm Tread (3)
In: First Floor
PredefinedType: LANDING
Name (Stair:Concrete Pan - 180mm Max Riser 280mm Tread:...)
221039:1
250693:1
251180:1

# IfcStair: Stair:Concrete Pan - 180mm Max Riser 280mm Tread (3)
In: First Floor
ShapeType: HALF_TURN_STAIR
Pset_StairCommon - Reference: Stair:Concrete Pan - 180mm Max Riser 280mm Tread; NumberOfRiser: 26; NumberOfTreads: 25; RiserHeight: 0.175769 m; TreadLength: 0.28 m; IsExternal: no
PSet_Revit_Dimensions - Width: 1 m; Desired Number of Risers: 26; Actual Number of Risers: 26; Actual Riser Height: 0.175769 m; Actual Tread Depth: 0.28 m
PSet_Revit_Constraints - Base Level: First Floor; Base Offset: 0 m; Top Level: Second Floor; Top Offset: 0 m
PSet_Revit_Graphics - Up text: UP; Down text: DN; Up label: yes; Up arrow: yes; Down label: yes; Down arrow: yes; Show Up arrow in all views: no
PSet_Revit_Other - InstallationDate: InstallationDate; SerialNumber: SerialNumber; WarrantyStartDate: WarrantyStartDate; BarCode: BarCode; AssetIdentifier: AssetIdentifier; TagNumber: TagNumber
PSet_Revit_Phasing - Phase Created: New Construction
PSet_Revit_Type_Identity Data - Manufacturer: Manufacturer
PSet_Revit_Type_Construction - Extend Below Base: 0 m; Monolithic Stairs: no; Landing Overlap: 0.076 m; Underside of Winder: 1; Function: 0
PSet_Revit_Type_Treads - Minimum Tread Depth: 0.28 m; Tread Thickness: 0.05 m; Nosing Length: 0 m; Apply Nosing Profile: 0
PSet_Revit_Type_Risers - Maximum Riser Height: 0.18 m; Begin with Riser: yes; End with Riser: yes; Riser Type: 1; Riser Thickness: 0.0125 m; Riser to Tread Connection: 0
PSet_Revit_Type_Stringers - Trim Stringers at Top: 2; Right Stringer: 1; Left Stringer: 1; Middle Stringers: 0; Stringer Thickness: 0.05 m; Stringer Height: 0.4 m; Open Stringer Offset: 0 m; Stringer Carriage Height: 0.152 m; Landing Carriage Height: 0.303271 m
PSet_Revit_Type_Materials and Finishes - Tread Material: Concrete - Cast in Situ Lightweight; Riser Material: Concrete - Cast in Situ Lightweight; Stringer Material: Metal - Steel
PSet_Revit_Type_Graphics - Break Symbol in Plan: yes; Text Size: 0.0082021; Text Font: Arial
PSet_Revit_Type_Other - AccessibilityPerformance: AccessibilityPerformance; CodePerformance: CodePerformance; Color: Color; Constituents: Constituents; Features: Features; Finish: Finish; Grade: Grade; Material: Material; ModelReference: ModelReference; NominalHeight: NominalHeight; NominalLength: NominalLength; NominalWidth: NominalWidth; ProductionYear: ProductionYear; Reference: Reference; Shape: Shape; Size: Size; SustainabilityPerformance: SustainabilityPerformance; WarrantyDescription: WarrantyDescription; WarrantyDurationLabor: WarrantyDurationLabor; WarrantyDurationParts: WarrantyDurationParts; WarrantyGuarantorLabor: WarrantyGuarantorLabor; WarrantyGuarantorParts: WarrantyGuarantorParts; ExpectedLife: ExpectedLife; ReplacementCost: ReplacementCost; AssetAccountingType: FIXED; Classification Code: 23-30 70 21; Classification Description: Stairs; ModelLabel: ModelLabel
Name (Stair:Concrete Pan - 180mm Max Riser 280mm Tread:...)
221039
250693
251180

# IfcStairFlight: Stair:Concrete Pan - 180mm Max Riser 280mm Tread (6)
In: First Floor
RiserHeight: 0.576671 m; TreadLength: 0.918635 m
Pset_StairFlightCommon - Reference: Stair:Concrete Pan - 180mm Max Riser 280mm Tread; RiserHeight: 0.175769 m; TreadLength: 0.28 m; TreadLengthAtInnerSide: 0.28 m; TreadLengthAtOffset: 0.28 m
Name (Stair:Concrete Pan - 180mm Max Riser 280mm Tread:...) | NumberOfRiser = Pset_StairFlightCommon, NumberOfRiser | NumberOfTreads = Pset_StairFlightCommon, NumberOfTreads | WalkingLineOffset (m) | WaistThickness (m)
221039:1 | 12 | 11 | 0.55 | 1.1
221039:2 | 14 | 13 | 0.55 | 1.1
250693:1 | 12 | 11 | 0.55 | 1.1
250693:2 | 14 | 13 | 0.55 | 1.1
251180:1 | 12 | 11 | 0.525 | 1.05
251180:2 | 14 | 13 | 0.525 | 1.05

# IfcWall: Basic Wall:Exterior - Insul Panel on Mtl. Stud:130954 (8)
Material: Insulation - Insulated Panel 0.042 m, Metal - Firring 0.038 m, Wood - Sheathing - plywood 0.019 m, Metal - Stud Layer 0.152 m, Plasterboard 0.016 m
Pset_WallCommon - Reference: Basic Wall:Exterior - Insul Panel on Mtl. Stud; LoadBearing: no; ExtendToStructure: no; IsExternal: yes
PSet_Revit_Constraints - Location Line: 2; Base is Attached: no; Base Extension Distance: 0 m; Top is Attached: no; Top Extension Distance: 0 m; Room Bounding: yes; Related to Mass: no
PSet_Revit_Other - InstallationDate: InstallationDate; SerialNumber: SerialNumber; WarrantyStartDate: WarrantyStartDate; BarCode: BarCode; AssetIdentifier: AssetIdentifier; TagNumber: TagNumber
PSet_Revit_Phasing - Phase Created: New Construction
PSet_Revit_Structural - Structural Usage: 0
PSet_Revit_Type_Construction - Wrapping at Inserts: 0; Wrapping at Ends: 1; Width: 0.267 m; Function: 1
PSet_Revit_Type_Graphics - Coarse Scale Fill Color: 0
PSet_Revit_Type_Identity Data - Manufacturer: Manufacturer
PSet_Revit_Type_Other - AccessibilityPerformance: AccessibilityPerformance; CodePerformance: CodePerformance; Color: Color; Constituents: Constituents; Features: Features; Finish: Finish; Grade: Grade; Material: Material; ModelReference: ModelReference; NominalHeight: NominalHeight; NominalLength: NominalLength; NominalWidth: NominalWidth; ProductionYear: ProductionYear; Reference: Reference; Shape: Shape; Size: Size; SustainabilityPerformance: SustainabilityPerformance; WarrantyDescription: WarrantyDescription; WarrantyDurationLabor: WarrantyDurationLabor; WarrantyDurationParts: WarrantyDurationParts; WarrantyGuarantorLabor: WarrantyGuarantorLabor; WarrantyGuarantorParts: WarrantyGuarantorParts; ExpectedLife: ExpectedLife; ReplacementCost: ReplacementCost; AssetAccountingType: FIXED; Classification Code: 23-25 30 24 21; Classification Description: Metal Framed Structural Walls; ModelLabel: ModelLabel
Name (Basic Wall:Exterior - Insul Panel on Mtl. Stud:...) | In | Base Constraint | Base Offset (m) | Unconnected Height (m) | Top Offset (m) | Length (m) | Area (m2) | Volume (m3)
290055 | Second Floor | Second Floor | 2.1915 | 1.697 | -0.7915 | 9.10423 | 16.7496 | 4.47214 | PSet_Revit_Constraints - Top Constraint: Up to level: Roof - Main
307047 | Roof - Main | Roof - Main | 0.12 | 2.9082 | -0.102 | 10.312 | 15.3269 | 4.09231
307184 | Roof - Main | Roof - Main | 0.12 | 2.9082 | -0.102 | 1 | 2.17687 | 0.581223
307686 | Roof - Main | Roof - Main | 0.12 | 2.9082 | -0.102 | 1 | 2.17687 | 0.581223
375596 | Roof - Main | Roof - Main | 0.12 | 2.9082 | -0.102 | 1 | 2.9673 | 0.79227
375598 | Roof - Main | Roof - Main | 0.12 | 2.9082 | -0.102 | 1.03444 | 2.6818 | 0.716042
381982 | Roof - Main | Roof - Main | 0.12 | 2.9082 | -0.102 | 1 | 2.9673 | 0.79227
381984 | Roof - Main | Roof - Main | 0.12 | 2.9082 | -0.102 | 1.03444 | 2.6818 | 0.716042

# IfcWall: Basic Wall:Interior - Furring (38 mm Stud):128404, Basic Wall:Interior - Furring (38 mm Stud):396777
In: Second Floor
Material: Metal - Stud Layer 0.038 m, Plasterboard 0.016 m
Pset_WallCommon - Reference: Basic Wall:Interior - Furring (38 mm Stud); LoadBearing: no; ExtendToStructure: no; IsExternal: no
PSet_Revit_Constraints - Location Line: 3; Base Constraint: Second Floor; Base Offset: 1.55 m; Base is Attached: no; Base Extension Distance: 0 m; Top Constraint: Up to level: Roof - Main; Unconnected Height: 1.8165 m; Top Offset: -1.3135 m; Top is Attached: no; Top Extension Distance: 0 m; Room Bounding: yes; Related to Mass: no
PSet_Revit_Other - InstallationDate: InstallationDate; SerialNumber: SerialNumber; WarrantyStartDate: WarrantyStartDate; BarCode: BarCode; AssetIdentifier: AssetIdentifier; TagNumber: TagNumber
PSet_Revit_Phasing - Phase Created: New Construction
PSet_Revit_Structural - Structural Usage: 0
PSet_Revit_Dimensions - Length: 4.005 m; Area: 7.11341 m2; Volume: 0.374752 m3
PSet_Revit_Type_Construction - Wrapping at Inserts: 0; Wrapping at Ends: 0; Width: 0.054 m; Function: 0
PSet_Revit_Type_Graphics - Coarse Scale Fill Color: 0
PSet_Revit_Type_Identity Data - Manufacturer: Manufacturer
PSet_Revit_Type_Other - AccessibilityPerformance: AccessibilityPerformance; CodePerformance: CodePerformance; Color: Color; Constituents: Constituents; Features: Features; Finish: Finish; Grade: Grade; Material: Material; ModelReference: ModelReference; NominalHeight: NominalHeight; NominalLength: NominalLength; NominalWidth: NominalWidth; ProductionYear: ProductionYear; Reference: Reference; Shape: Shape; Size: Size; SustainabilityPerformance: SustainabilityPerformance; WarrantyDescription: WarrantyDescription; WarrantyDurationLabor: WarrantyDurationLabor; WarrantyDurationParts: WarrantyDurationParts; WarrantyGuarantorLabor: WarrantyGuarantorLabor; WarrantyGuarantorParts: WarrantyGuarantorParts; ExpectedLife: ExpectedLife; ReplacementCost: ReplacementCost; AssetAccountingType: FIXED; Classification Code: 23-25 40 11 11 11; Classification Description: Metal-Framed Gypsum Board Fixed Partitions; ModelLabel: ModelLabel

# IfcWall: Basic Wall:Interior - Partition (92mm Stud):128360 (6)
Material: Plasterboard 0.016 m, Metal - Stud Layer 0.092 m, Plasterboard 0.016 m
Pset_WallCommon - Reference: Basic Wall:Interior - Partition (92mm Stud); LoadBearing: no; ExtendToStructure: no; IsExternal: no
PSet_Revit_Constraints - Location Line: 2; Base is Attached: no; Base Extension Distance: 0 m; Top is Attached: no; Top Extension Distance: 0 m; Room Bounding: yes; Related to Mass: no
PSet_Revit_Other - InstallationDate: InstallationDate; SerialNumber: SerialNumber; WarrantyStartDate: WarrantyStartDate; BarCode: BarCode; AssetIdentifier: AssetIdentifier; TagNumber: TagNumber
PSet_Revit_Phasing - Phase Created: New Construction
PSet_Revit_Structural - Structural Usage: 0
PSet_Revit_Type_Construction - Wrapping at Inserts: 0; Wrapping at Ends: 2; Width: 0.124 m; Function: 0
PSet_Revit_Type_Graphics - Coarse Scale Fill Color: 0
PSet_Revit_Type_Identity Data - Manufacturer: Manufacturer
PSet_Revit_Type_Other - AccessibilityPerformance: AccessibilityPerformance; CodePerformance: CodePerformance; Color: Color; Constituents: Constituents; Features: Features; Finish: Finish; Grade: Grade; Material: Material; ModelReference: ModelReference; NominalHeight: NominalHeight; NominalLength: NominalLength; NominalWidth: NominalWidth; ProductionYear: ProductionYear; Reference: Reference; Shape: Shape; Size: Size; SustainabilityPerformance: SustainabilityPerformance; WarrantyDescription: WarrantyDescription; WarrantyDurationLabor: WarrantyDurationLabor; WarrantyDurationParts: WarrantyDurationParts; WarrantyGuarantorLabor: WarrantyGuarantorLabor; WarrantyGuarantorParts: WarrantyGuarantorParts; ExpectedLife: ExpectedLife; ReplacementCost: ReplacementCost; AssetAccountingType: FIXED; Classification Code: 23-25 40 11 11 11; Classification Description: Metal-Framed Gypsum Board Fixed Partitions; ModelLabel: ModelLabel
Name (Basic Wall:Interior - Partition (92mm Stud):...) | In | Base Constraint | Base Offset (m) | Top Constraint | Unconnected Height (m) | Top Offset (m) | Length (m) | Area (m2) | Volume (m3)
287145 | First Floor | First Floor | 3.8 | Up to level: Second Floor | 3.77 | 3 | 1.0798 | 4.63209 | 0.574379
287660 | Second Floor | Second Floor | 0 | Up to level: Roof - Main | 4.578 | -0.102 | 3.836 | 16.0008 | 1.9841
314078 | First Floor | First Floor | 3.8 | Up to level: Second Floor | 0.65 | -0.12 | 4.147 | 5.43461 | 0.673638
314431 | First Floor | First Floor | 0.89 | Up to level: Second Floor | 3.578 | -0.102 | 1.135 | 2.16704 | 0.268713
379018 | First Floor | First Floor | 3.8 | Up to level: Second Floor | 3.77 | 3 | 1.0798 | 4.98443 | 0.61807
399407 | Roof - Main | Roof - Main | 0 | Up to level: Roof - Main | 4.22126 | 4.22126 | 8.31148 | 31.7988 | 3.94302

# IfcWallStandardCase: Basic Wall:Exterior - Insul Panel on Mtl. Stud:130954 (72)
Material: Insulation - Insulated Panel 0.042 m, Metal - Firring 0.038 m, Wood - Sheathing - plywood 0.019 m, Metal - Stud Layer 0.152 m, Plasterboard 0.016 m
Pset_WallCommon - Reference: Basic Wall:Exterior - Insul Panel on Mtl. Stud; LoadBearing: no; ExtendToStructure: no; IsExternal: yes
PSet_Revit_Constraints - Base is Attached: no; Base Extension Distance: 0 m; Top is Attached: no; Top Extension Distance: 0 m; Room Bounding: yes; Related to Mass: no
PSet_Revit_Other - InstallationDate: InstallationDate; SerialNumber: SerialNumber; WarrantyStartDate: WarrantyStartDate; BarCode: BarCode; AssetIdentifier: AssetIdentifier; TagNumber: TagNumber
PSet_Revit_Phasing - Phase Created: New Construction
PSet_Revit_Structural - Structural Usage: 0
PSet_Revit_Type_Construction - Wrapping at Inserts: 0; Wrapping at Ends: 1; Width: 0.267 m; Function: 1
PSet_Revit_Type_Graphics - Coarse Scale Fill Color: 0
PSet_Revit_Type_Identity Data - Manufacturer: Manufacturer
PSet_Revit_Type_Other - AccessibilityPerformance: AccessibilityPerformance; CodePerformance: CodePerformance; Color: Color; Constituents: Constituents; Features: Features; Finish: Finish; Grade: Grade; Material: Material; ModelReference: ModelReference; NominalHeight: NominalHeight; NominalLength: NominalLength; NominalWidth: NominalWidth; ProductionYear: ProductionYear; Reference: Reference; Shape: Shape; Size: Size; SustainabilityPerformance: SustainabilityPerformance; WarrantyDescription: WarrantyDescription; WarrantyDurationLabor: WarrantyDurationLabor; WarrantyDurationParts: WarrantyDurationParts; WarrantyGuarantorLabor: WarrantyGuarantorLabor; WarrantyGuarantorParts: WarrantyGuarantorParts; ExpectedLife: ExpectedLife; ReplacementCost: ReplacementCost; AssetAccountingType: FIXED; Classification Code: 23-25 30 24 21; Classification Description: Metal Framed Structural Walls; ModelLabel: ModelLabel
Name (Basic Wall:Exterior - Insul Panel on Mtl. Stud:...) | In | Location Line | Base Constraint | Base Offset (m) | Top Constraint | Unconnected Height (m) | Top Offset (m) | Length (m) | Area (m2) | Volume (m3)
141634 | First Floor | 2 | First Floor | 0 | Up to level: Second Floor | 5.027 | 0.457 | 3.00599 | 14.44 | 3.85548
141681 | First Floor | 2 | First Floor | 0 | Up to level: Second Floor | 3.9495 | -0.6205 | 0.964 | 3.80732 | 1.01655
141807 | First Floor | 2 | First Floor | 0 | Up to level: Second Floor | 3.9495 | -0.6205 | 0.964 | 3.80732 | 1.01655
142286 | First Floor | 2 | First Floor | 0 | Up to level: Second Floor | 5.027 | 0.457 | 6.05 | 31.7556 | 8.47873
142426 | First Floor | 2 | First Floor | 0 | Up to level: Second Floor | 3.9495 | -0.6205 | 0.36 | 2.47634 | 0.661182
142525 | First Floor | 2 | First Floor | 0 | Up to level: Second Floor | 3.9495 | -0.6205 | 0.36 | 2.47634 | 0.661182
142629 | First Floor | 2 | First Floor | 0 | Up to level: Second Floor | 3.9495 | -0.6205 | 0.36 | 2.47634 | 0.661182
142775 | First Floor | 2 | First Floor | 0 | Up to level: Second Floor | 3.9495 | -0.6205 | 0.36 | 2.47634 | 0.661182
142840 | First Floor | 2 | First Floor | 0 | Up to level: Second Floor | 4.57 | 0 | 3.153 | 13.2719 | 3.54359
143026 | First Floor | 2 | First Floor | 0 | Up to level: Second Floor | 3.9495 | -0.6205 | 0.965 | 3.81127 | 1.01761
143132 | First Floor | 2 | First Floor | 0 | Up to level: Second Floor | 3.9495 | -0.6205 | 0.965 | 3.55775 | 0.94992
143236 | First Floor | 2 | First Floor | 0 | Up to level: Second Floor | 5.027 | 0.457 | 9.07 | 44.8628 | 11.9784
145747 | Second Floor | 2 | Second Floor | 0 | Up to level: Roof - Main | 5.137 | 0.457 | 6.01556 | 30.9019 | 8.25082
145802 | Second Floor | 2 | Second Floor | 0 | Up to level: Roof - Main | 5.137 | 0.457 | 3.483 | 17.3271 | 4.62634
145867 | Second Floor | 2 | Second Floor | 0 | Up to level: Roof - Main | 5.137 | 0.457 | 6.05 | 31.0788 | 8.29805
143081 | First Floor | 2 | First Floor | 0 | Up to level: Second Floor | 3.9495 | -0.6205 | 1.657 | 4.59171 | 1.22599
187224 | First Floor | 2 | First Floor | 0 | Up to level: Second Floor | 4.468 | -0.102 | 6.033 | 23.0502 | 6.15441
141763 | First Floor | 2 | First Floor | 0 | Up to level: Second Floor | 3.9495 | -0.6205 | 1.817 | 5.22363 | 1.39471
187053 | First Floor | 2 | First Floor | 0 | Up to level: Second Floor | 4.468 | -0.102 | 2.044 | 5.33616 | 1.42475
186606 | First Floor | 2 | First Floor | 0 | Up to level: Second Floor | 4.468 | -0.102 | 6.033 | 25.0028 | 6.67576
142496 | First Floor | 2 | First Floor | 0 | Up to level: Second Floor | 3.9495 | -0.6205 | 1.779 | 4.01903 | 1.07308
142721 | First Floor | 2 | First Floor | 0 | Up to level: Second Floor | 3.9495 | -0.6205 | 1.792 | 4.07038 | 1.08679
141152 | First Floor | 2 | First Floor | 0 | Up to level: Second Floor | 5.027 | 0.457 | 32.333 | 153.657 | 41.0265
142977 | First Floor | 2 | First Floor | 0 | Up to level: Second Floor | 5.027 | 0.457 | 11.743 | 57.1532 | 15.2599
142394 | First Floor | 2 | First Floor | 0 | Up to level: Second Floor | 4.57 | 0 | 6.378 | 26.2751 | 7.01545
142601 | First Floor | 2 | First Floor | 0 | Up to level: Second Floor | 4.57 | 0 | 13.338 | 56.4301 | 15.0307
140707 | First Floor | 2 | First Floor | 0 | Up to level: Second Floor | 4.57 | 0 | 16.7065 | 70.0188 | 18.695
140832 | First Floor | 2 | First Floor | 0 | Up to level: Second Floor | 4.57 | 0 | 20.06 | 89.9392 | 24.0138
140972 | First Floor | 2 | First Floor | 0 | Up to level: Second Floor | 5.027 | 0.457 | 10.04 | 45.2661 | 12.086
142014 | First Floor | 2 | First Floor | 0 | Up to level: Second Floor | 5.027 | 0.457 | 17.0815 | 75.7958 | 20.2375
256262 | First Floor | 2 | First Floor | 0 | Up to level: First Floor | 0.905 | 0.905 | 5.00051 | 4.52546 | 1.2083
256419 | First Floor | 2 | First Floor | 0 | Up to level: Second Floor | 5.027 | 0.457 | 2.5365 | 13.2782 | 3.54529
256655 | First Floor | 2 | First Floor | 2.54 | Up to level: Second Floor | 2.487 | 0.457 | 5.00051 | 12.4363 | 3.32049
258057 | First Floor | 2 | First Floor | 0 | Up to level: First Floor | 0.905 | 0.905 | 5 | 4.525 | 1.20817
258058 | First Floor | 2 | First Floor | 2.54 | Up to level: Second Floor | 2.487 | 0.457 | 5 | 12.435 | 3.32015
258773 | First Floor | 2 | First Floor | 0 | Up to level: First Floor | 0.905 | 0.905 | 4 | 3.62 | 0.96654
258774 | First Floor | 2 | First Floor | 2.54 | Up to level: Second Floor | 2.487 | 0.457 | 4 | 9.948 | 2.65612
146031 | Second Floor | 2 | Second Floor | 0 | Up to level: Roof - Main | 5.137 | 0.457 | 35.51 | 165.428 | 44.1694
144524 | Second Floor | 2 | Second Floor | 0 | Up to level: Roof - Main | 5.137 | 0.457 | 16.7065 | 75.4877 | 20.1552
144932 | Second Floor | 2 | Second Floor | 0 | Up to level: Roof - Main | 5.137 | 0.457 | 19.9665 | 90.8333 | 24.2525
145344 | Second Floor | 2 | Second Floor | 0 | Up to level: Roof - Main | 5.137 | 0.457 | 47.493 | 224.887 | 60.0447
145577 | Second Floor | 2 | Second Floor | 0 | Up to level: Roof - Main | 5.137 | 0.457 | 8.61 | 40.7596 | 10.8828
267324 | First Floor | 2 | First Floor | 3 | Up to level: Second Floor | 2.027 | 0.457 | 1.767 | 3.348 | 0.893916
267401 | First Floor | 2 | First Floor | 3 | Up to level: Second Floor | 1.57 | 0 | 1.779 | 2.53951 | 0.67805
267487 | First Floor | 2 | First Floor | 3 | Up to level: Second Floor | 1.57 | 0 | 1.792 | 2.55992 | 0.6835
267608 | First Floor | 2 | First Floor | 3 | Up to level: Second Floor | 2.027 | 0.457 | 1.817 | 3.42954 | 0.915688
268199 | First Floor | 2 | First Floor | 0 | Up to level: Second Floor | 4.57 | 0 | 3.483 | 15.3901 | 4.10914
290066 | Second Floor | 2 | Second Floor | 3.4865 | Up to level: Roof - Main | 1.6505 | 0.457 | 15.343 | 26.423 | 7.05495
293670 | Second Floor | 2 | Second Floor | 0 | Up to level: Second Floor | 2.64 | 2.64 | 2.7445 | 7.41764 | 1.98051
297616 | Roof - Main | 2 | Roof - Main | 0 |  | 1.35083 | -0.102 | 6.8035 | 9.19036 | 2.09499
307120 | Roof - Main | 2 | Roof - Main | 0.12 |  | 2.9082 | -0.102 | 1.83905 | 5.34831 | 1.428
307295 | Roof - Main | 2 | Roof - Main | 0.12 |  | 3.3 | -0.102 | 0.241454 | 1.23735 | 0.330372
307685 | Roof - Main | 2 | Roof - Main | 0.12 |  | 2.9082 | -0.102 | 1.83905 | 6.12479 | 1.63532
307687 | Roof - Main | 2 | Roof - Main | 0.12 |  | 2.9082 | -0.102 | 0.241454 | 1.09044 | 0.291147
309999 | Roof - Main | 2 | Roof - Main | 0 | Up to level: Roof - Main | 3.4 | 3.4 | 18.4025 | 31.9269 | 8.52447
375597 | Roof - Main | 2 | Roof - Main | 0.12 |  | 2.9082 | -0.102 | 1.83905 | 5.34831 | 1.428
376077 | Roof - Main | 2 | Roof - Main | 1.67814 |  | 1.74186 | -0.102 | 1.12108 | 1.72023 | 0.459301
376708 | Second Floor | 0 | Second Floor | 3.4865 | Up to level: Roof - Main | 2.5435 | 1.35 | 1.07919 | 1.18262 | 0.31576
378843 | Second Floor | 2 | Second Floor | 2.1915 | Up to level: Roof - Main | 1.697 | -0.7915 | 9.10423 | 16.4162 | 4.38313
381802 | Second Floor | 2 | Second Floor | 3.4865 | Up to level: Roof - Main | 1.6505 | 0.457 | 15.343 | 26.423 | 7.05495
381803 | Roof - Main | 2 | Roof - Main | 0 |  | 1.35083 | -0.102 | 6.8035 | 9.19036 | 2.09499
381931 | Roof - Main | 2 | Roof - Main | 0 | Up to level: Roof - Main | 3.4 | 3.4 | 18.4025 | 31.9269 | 8.52447
381983 | Roof - Main | 2 | Roof - Main | 0.12 |  | 2.9082 | -0.102 | 1.83905 | 5.34831 | 1.428
382036 | Second Floor | 0 | Second Floor | 3.4865 | Up to level: Roof - Main | 2.5435 | 1.35 | 1.08869 | 1.35432 | 0.361602
382926 | Roof - Main | 2 | Roof - Main | 1.67814 |  | 1.74186 | -0.102 | 1.12108 | 1.72023 | 0.459301
383730 | Second Floor | 2 | Second Floor | 2.1915 | Up to level: Second Floor | 0.8785 | 3.07 | 1.0195 | 0.778351 | 0.111304
384186 | Second Floor | 2 | Second Floor | 2.1915 | Up to level: Second Floor | 0.8785 | 3.07 | 0.886 | 0.778351 | 0.111304
384376 | Second Floor | 2 | Second Floor | 0 | Up to level: Second Floor | 2.64 | 2.64 | 2.7445 | 7.39046 | 1.97325
145481 | Second Floor | 2 | Second Floor | 0 | Up to level: Roof - Main | 5.137 | 0.457 | 40.5774 | 195.866 | 52.2962
263032 | First Floor | 2 | First Floor | 0 | Up to level: Second Floor | 4.57 | 0 | 19.9665 | 83.182 | 22.2096
257918 | First Floor | 2 | First Floor | 0 | Up to level: Second Floor | 5.027 | 0.457 | 4.935 | 23.0732 | 6.16055
258588 | First Floor | 2 | First Floor | 0 | Up to level: Second Floor | 5.027 | 0.457 | 13.2565 | 62.1068 | 16.5825

# IfcWallStandardCase: Basic Wall:Interior - Furring (152 mm Stud):138413 (30)
Material: Metal - Stud Layer 0.152 m, Plasterboard 0.016 m
Pset_WallCommon - Reference: Basic Wall:Interior - Furring (152 mm Stud); LoadBearing: no; ExtendToStructure: no; IsExternal: no
PSet_Revit_Constraints - Base Offset: 0 m; Base is Attached: no; Base Extension Distance: 0 m; Top Offset: -0.102 m; Top is Attached: no; Top Extension Distance: 0 m; Room Bounding: yes; Related to Mass: no
PSet_Revit_Other - InstallationDate: InstallationDate; SerialNumber: SerialNumber; WarrantyStartDate: WarrantyStartDate; BarCode: BarCode; AssetIdentifier: AssetIdentifier; TagNumber: TagNumber
PSet_Revit_Phasing - Phase Created: New Construction
PSet_Revit_Structural - Structural Usage: 0
PSet_Revit_Type_Construction - Wrapping at Inserts: 0; Wrapping at Ends: 0; Width: 0.168 m; Function: 0
PSet_Revit_Type_Graphics - Coarse Scale Fill Color: 0
PSet_Revit_Type_Identity Data - Manufacturer: Manufacturer
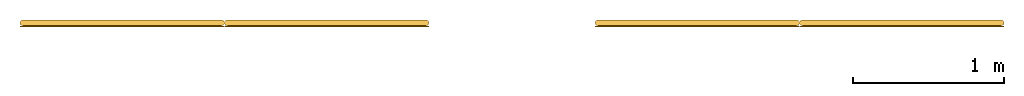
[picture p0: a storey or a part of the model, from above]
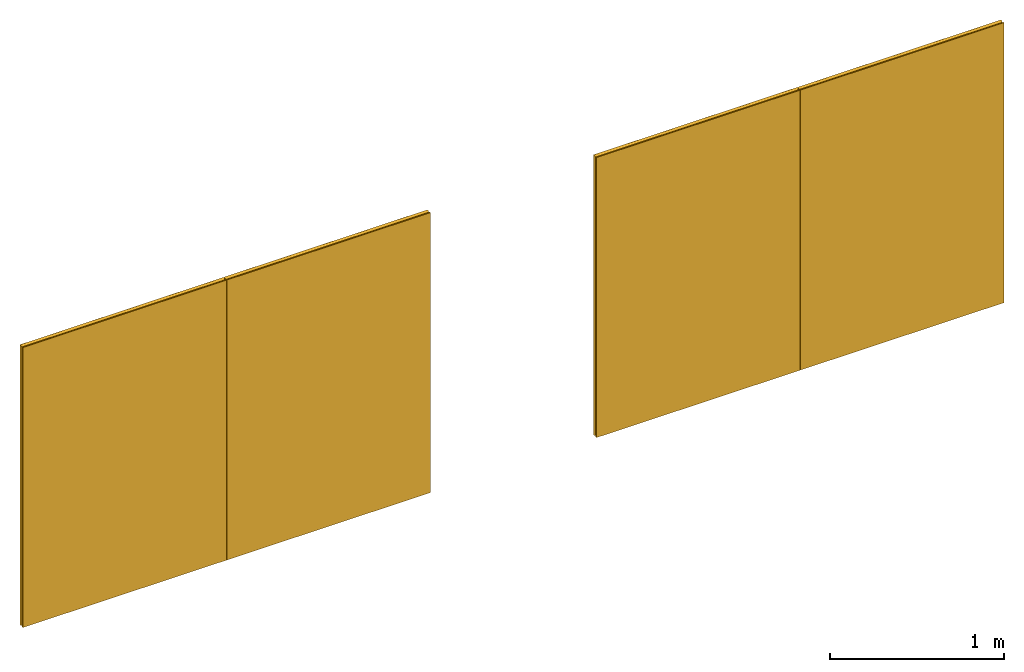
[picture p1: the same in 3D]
Properties of the parts of a building model (IFC2X3), part 9 of 11

# IfcWallStandardCase: Basic Wall:Interior - Furring (152 mm Stud):138413 (30)
PSet_Revit_Type_Other - AccessibilityPerformance: AccessibilityPerformance; CodePerformance: CodePerformance; Color: Color; Constituents: Constituents; Features: Features; Finish: Finish; Grade: Grade; Material: Material; ModelReference: ModelReference; NominalHeight: NominalHeight; NominalLength: NominalLength; NominalWidth: NominalWidth; ProductionYear: ProductionYear; Reference: Reference; Shape: Shape; Size: Size; SustainabilityPerformance: SustainabilityPerformance; WarrantyDescription: WarrantyDescription; WarrantyDurationLabor: WarrantyDurationLabor; WarrantyDurationParts: WarrantyDurationParts; WarrantyGuarantorLabor: WarrantyGuarantorLabor; WarrantyGuarantorParts: WarrantyGuarantorParts; ExpectedLife: ExpectedLife; ReplacementCost: ReplacementCost; AssetAccountingType: FIXED; Classification Code: 23-25 40 11 11 11; Classification Description: Metal-Framed Gypsum Board Fixed Partitions; ModelLabel: ModelLabel
Name (Basic Wall:Interior - Furring (152 mm Stud):...) | In | Location Line | Base Constraint | Top Constraint | Unconnected Height (m) | Length (m) | Area (m2) | Volume (m3)
146808 | First Floor | 3 | First Floor | Up to level: Second Floor | 4.468 | 2.2585 | 9.21748 | 1.54854
153298 | First Floor | 3 | First Floor | Up to level: Second Floor | 4.468 | 4.115 | 18.2294 | 3.06255
159081 | First Floor | 3 | First Floor | Up to level: Second Floor | 4.468 | 2.091 | 8.94494 | 1.47648
159470 | First Floor | 3 | First Floor | Up to level: Second Floor | 4.468 | 1.221 | 5.05778 | 0.849706
159888 | First Floor | 3 | First Floor | Up to level: Second Floor | 4.468 | 1.1252 | 4.71463 | 0.792058
160767 | First Floor | 3 | First Floor | Up to level: Second Floor | 4.468 | 1.3 | 5.25437 | 0.882734
165650 | First Floor | 0 | First Floor | Up to level: Second Floor | 4.468 | 4.129 | 18.6104 | 3.12654
165900 | First Floor | 0 | First Floor | Up to level: Second Floor | 4.468 | 4.08 | 17.9167 | 3.01
166580 | First Floor | 3 | First Floor | Up to level: Second Floor | 4.468 | 1.99 | 8.89132 | 1.49374
170001 | First Floor | 0 | First Floor | Up to level: Second Floor | 4.468 | 2.786 | 11.8938 | 1.96202
170108 | First Floor | 0 | First Floor | Up to level: Second Floor | 4.468 | 2.786 | 11.8938 | 1.96202
171798 | First Floor | 0 | First Floor | Up to level: Second Floor | 4.468 | 4.8445 | 20.9281 | 3.51592
176335 | First Floor | 0 | First Floor | Up to level: Second Floor | 4.468 | 0.966 | 3.76206 | 0.632025
179985 | First Floor | 0 | First Floor | Up to level: Second Floor | 4.468 | 0.3925 | 1.53252 | 0.257464
180035 | First Floor | 0 | First Floor | Up to level: Second Floor | 4.468 | 5.7458 | 24.7005 | 4.14968
180342 | First Floor | 3 | First Floor | Up to level: Second Floor | 4.468 | 2.101 | 8.98962 | 1.51026
180708 | First Floor | 0 | First Floor | Up to level: Second Floor | 4.468 | 2.101 | 8.98962 | 1.51026
181043 | First Floor | 0 | First Floor | Up to level: Second Floor | 4.468 | 1.914 | 7.99772 | 1.34362
184583 | First Floor | 3 | First Floor | Up to level: Second Floor | 4.468 | 9.15715 | 25.9775 | 4.36421
184791 | First Floor | 3 | First Floor | Up to level: Second Floor | 4.468 | 0.314 | 1.30466 | 0.219182
184857 | First Floor | 3 | First Floor | Up to level: Second Floor | 4.468 | 4.20715 | 18.5428 | 3.11519
187521 | First Floor | 0 | First Floor | Up to level: Second Floor | 4.468 | 0.3925 | 1.53252 | 0.257464
187569 | First Floor | 0 | First Floor | Up to level: Second Floor | 4.468 | 2.1736 | 9.05932 | 1.52197
189364 | First Floor | 0 | First Floor | Up to level: Second Floor | 4.468 | 0.3925 | 1.53252 | 0.257464
189473 | First Floor | 0 | First Floor | Up to level: Second Floor | 4.468 | 9.8144 | 43.1984 | 7.25733
206270 | Second Floor | 0 | Second Floor | Up to level: Roof - Main | 4.578 | 2.6485 | 11.7975 | 1.94584
209687 | Second Floor | 2 | Second Floor | Up to level: Roof - Main | 4.578 | 2.796 | 12.2324 | 2.01891
209762 | Second Floor | 2 | Second Floor | Up to level: Roof - Main | 4.578 | 2.796 | 12.2324 | 2.01891
212054 | Second Floor | 0 | Second Floor | Up to level: Roof - Main | 4.578 | 1.1883 | 5.03261 | 0.845478
231965 | First Floor | 0 | First Floor | Up to level: Second Floor | 4.468 | 1.956 | 8.18538 | 1.37514

# IfcWallStandardCase: Basic Wall:Interior - Furring (38 mm Stud):128404 (450)
Material: Metal - Stud Layer 0.038 m, Plasterboard 0.016 m
Pset_WallCommon - Reference: Basic Wall:Interior - Furring (38 mm Stud); LoadBearing: no; ExtendToStructure: no; IsExternal: no
PSet_Revit_Constraints - Base is Attached: no; Base Extension Distance: 0 m; Top is Attached: no; Top Extension Distance: 0 m; Room Bounding: yes; Related to Mass: no
PSet_Revit_Other - InstallationDate: InstallationDate; SerialNumber: SerialNumber; WarrantyStartDate: WarrantyStartDate; BarCode: BarCode; AssetIdentifier: AssetIdentifier; TagNumber: TagNumber
PSet_Revit_Phasing - Phase Created: New Construction
PSet_Revit_Structural - Structural Usage: 0
PSet_Revit_Type_Construction - Wrapping at Inserts: 0; Wrapping at Ends: 0; Width: 0.054 m; Function: 0
PSet_Revit_Type_Graphics - Coarse Scale Fill Color: 0
PSet_Revit_Type_Identity Data - Manufacturer: Manufacturer
PSet_Revit_Type_Other - AccessibilityPerformance: AccessibilityPerformance; CodePerformance: CodePerformance; Color: Color; Constituents: Constituents; Features: Features; Finish: Finish; Grade: Grade; Material: Material; ModelReference: ModelReference; NominalHeight: NominalHeight; NominalLength: NominalLength; NominalWidth: NominalWidth; ProductionYear: ProductionYear; Reference: Reference; Shape: Shape; Size: Size; SustainabilityPerformance: SustainabilityPerformance; WarrantyDescription: WarrantyDescription; WarrantyDurationLabor: WarrantyDurationLabor; WarrantyDurationParts: WarrantyDurationParts; WarrantyGuarantorLabor: WarrantyGuarantorLabor; WarrantyGuarantorParts: WarrantyGuarantorParts; ExpectedLife: ExpectedLife; ReplacementCost: ReplacementCost; AssetAccountingType: FIXED; Classification Code: 23-25 40 11 11 11; Classification Description: Metal-Framed Gypsum Board Fixed Partitions; ModelLabel: ModelLabel
Name (Basic Wall:Interior - Furring (38 mm Stud):...) | In | Location Line | Base Constraint | Base Offset (m) | Top Constraint | Unconnected Height (m) | Top Offset (m) | Length (m) | Area (m2) | Volume (m3)
157409 | First Floor | 3 | First Floor | 0 | Up to level: Second Floor | 4.468 | -0.102 | 5.145 | 20.3736 | 0.885925
159409 | First Floor | 0 | First Floor | 0 | Up to level: Second Floor | 4.468 | -0.102 | 0.269 | 1.14381 | 0.0617656
163167 | First Floor | 0 | First Floor | 0 | Up to level: Second Floor | 4.468 | -0.102 | 0.225 | 1.40295 | 0.0757594
163196 | First Floor | 0 | First Floor | 0 | Up to level: Second Floor | 4.468 | -0.102 | 0.406 | 1.57274 | 0.0849277
163220 | First Floor | 0 | First Floor | 0 | Up to level: Second Floor | 4.468 | -0.102 | 0.393 | 1.87656 | 0.101334
163306 | First Floor | 0 | First Floor | 0 | Up to level: Second Floor | 4.468 | -0.102 | 0.406 | 2.05528 | 0.110985
163325 | First Floor | 0 | First Floor | 0 | Up to level: Second Floor | 4.468 | -0.102 | 0.371 | 1.25998 | 0.0680387
163375 | First Floor | 0 | First Floor | 0 | Up to level: Second Floor | 4.468 | -0.102 | 0.371 | 1.25998 | 0.0680387
163465 | First Floor | 0 | First Floor | 0 | Up to level: Second Floor | 4.468 | -0.102 | 0.4495 | 1.53252 | 0.0827563
163496 | First Floor | 0 | First Floor | 0 | Up to level: Second Floor | 4.468 | -0.102 | 0.406 | 1.57274 | 0.0849277
166510 | First Floor | 3 | First Floor | 0 | Up to level: Second Floor | 4.468 | -0.102 | 1.99 | 8.33729 | 0.450214
168930 | First Floor | 0 | First Floor | 0 | Up to level: Second Floor | 4.468 | -0.102 | 0.406 | 1.81401 | 0.0979564
168966 | First Floor | 0 | First Floor | 0 | Up to level: Second Floor | 4.468 | -0.102 | 0.631 | 2.42166 | 0.130769
169233 | First Floor | 0 | First Floor | 0 | Up to level: Second Floor | 4.468 | -0.102 | 0.215 | 1.35827 | 0.0733467
169261 | First Floor | 0 | First Floor | 0 | Up to level: Second Floor | 4.468 | -0.102 | 0.406 | 1.81401 | 0.0979564
169521 | First Floor | 0 | First Floor | 0 | Up to level: Second Floor | 4.468 | -0.102 | 0.406 | 1.81401 | 0.0979564
169542 | First Floor | 0 | First Floor | 0 | Up to level: Second Floor | 4.468 | -0.102 | 0.406 | 1.81401 | 0.0979564
169566 | First Floor | 0 | First Floor | 0 | Up to level: Second Floor | 4.468 | -0.102 | 0.406 | 1.81401 | 0.0979564
169630 | First Floor | 0 | First Floor | 0 | Up to level: Second Floor | 4.468 | -0.102 | 0.406 | 1.81401 | 0.0979564
171555 | First Floor | 0 | First Floor | 0 | Up to level: Second Floor | 4.468 | -0.102 | 4.8445 | 20.9281 | 1.13012
171627 | First Floor | 0 | First Floor | 0 | Up to level: Second Floor | 4.468 | -0.102 | 0.29 | 1.69784 | 0.0916834
175457 | First Floor | 0 | First Floor | 0 | Up to level: Second Floor | 4.468 | -0.102 | 0.406 | 2.05528 | 0.110985
175497 | First Floor | 0 | First Floor | 0 | Up to level: Second Floor | 4.468 | -0.102 | 1.336 | 5.96925 | 0.322339
175530 | First Floor | 0 | First Floor | 0 | Up to level: Second Floor | 4.468 | -0.102 | 0.406 | 1.81401 | 0.0979564
175568 | First Floor | 0 | First Floor | 0 | Up to level: Second Floor | 4.468 | -0.102 | 1.336 | 5.72798 | 0.309311
176876 | First Floor | 0 | First Floor | 0 | Up to level: Second Floor | 4.468 | -0.102 | 0.4495 | 1.53252 | 0.0827563
176933 | First Floor | 0 | First Floor | 0 | Up to level: Second Floor | 4.468 | -0.102 | 0.535 | 2.6808 | 0.144763
177543 | First Floor | 0 | First Floor | 0 | Up to level: Second Floor | 4.468 | -0.102 | 0.4495 | 1.53252 | 0.0827563
177597 | First Floor | 0 | First Floor | 0 | Up to level: Second Floor | 4.468 | -0.102 | 4.446 | 19.4582 | 1.05074
177617 | First Floor | 0 | First Floor | 0 | Up to level: Second Floor | 4.468 | -0.102 | 0.4495 | 1.29125 | 0.0697276
178764 | First Floor | 3 | First Floor | 0 | Up to level: First Floor | 2.5 | 2.5 | 0.495 | 1.15 | 0.0621
178886 | First Floor | 3 | First Floor | 0 | Up to level: First Floor | 3 | 3 | 0.495 | 1.38 | 0.07452
179154 | First Floor | 3 | First Floor | 0 | Up to level: Second Floor | 4.468 | -0.102 | 0.314975 | 1.36767 | 0.0738543
180220 | First Floor | 0 | First Floor | 0 | Up to level: Second Floor | 4.468 | -0.102 | 0.907672 | 3.8991 | 0.210551
180241 | First Floor | 0 | First Floor | 0 | Up to level: Second Floor | 4.468 | -0.102 | 0.4495 | 1.29125 | 0.0697276
180357 | First Floor | 0 | First Floor | 0 | Up to level: Second Floor | 4.468 | -0.102 | 0.269 | 1.69784 | 0.0916834
180382 | First Floor | 0 | First Floor | 0 | Up to level: Second Floor | 4.468 | -0.102 | 0.404 | 1.5638 | 0.0844452
180412 | First Floor | 0 | First Floor | 0 | Up to level: Second Floor | 4.468 | -0.102 | 0.1975 | 0.88243 | 0.0476512
180453 | First Floor | 0 | First Floor | 0 | Up to level: Second Floor | 4.468 | -0.102 | 0.81 | 3.61908 | 0.19543
180479 | First Floor | 0 | First Floor | 0 | Up to level: Second Floor | 4.468 | -0.102 | 0.440975 | 1.57262 | 0.0849217
186087 | First Floor | 0 | First Floor | 0 | Up to level: Second Floor | 4.468 | -0.102 | 0.388 | 1.5772 | 0.085169
186112 | First Floor | 0 | First Floor | 0 | Up to level: Second Floor | 4.468 | -0.102 | 0.591 | 2.24294 | 0.121119
188118 | First Floor | 3 | First Floor | 0 | Up to level: Second Floor | 4.468 | -0.102 | 0.388 | 1.5772 | 0.085169
188181 | First Floor | 3 | First Floor | 0 | Up to level: Second Floor | 4.468 | -0.102 | 4.9704 | 21.8101 | 1.17774
188205 | First Floor | 3 | First Floor | 0 | Up to level: Second Floor | 4.468 | -0.102 | 0.388 | 1.5772 | 0.085169
188319 | First Floor | 3 | First Floor | 0 | Up to level: Second Floor | 4.468 | -0.102 | 0.441 | 1.57274 | 0.0849279
188686 | First Floor | 0 | First Floor | 0 | Up to level: Second Floor | 4.468 | -0.102 | 0.388 | 1.5772 | 0.085169
188717 | First Floor | 0 | First Floor | 0 | Up to level: Second Floor | 4.468 | -0.102 | 0.7914 | 3.13832 | 0.169469
188917 | First Floor | 3 | First Floor | 0 | Up to level: Second Floor | 4.468 | -0.102 | 0.4665 | 1.36721 | 0.0738292
188970 | First Floor | 3 | First Floor | 0 | Up to level: Second Floor | 4.468 | -0.102 | 0.4495 | 1.53252 | 0.0827563
188999 | First Floor | 3 | First Floor | 0 | Up to level: Second Floor | 4.468 | -0.102 | 0.423 | 1.64869 | 0.0805848
194444 | Second Floor | 2 | Second Floor | 0 | Up to level: Roof - Main | 4.578 | -0.102 | 6.44109 | 29.3271 | 1.58366
197514 | Second Floor | 2 | Second Floor | 0 | Up to level: Second Floor | 3 | 3 | 0.475637 | 1.69391 | 0.0914712
197561 | Second Floor | 2 | Second Floor | 0 | Up to level: Second Floor | 3 | 3 | 1.18347 | 3.55042 | 0.191723
197593 | Second Floor | 2 | Second Floor | 0 | Up to level: Second Floor | 3 | 3 | 0.475637 | 1.15991 | 0.0626352
197692 | Second Floor | 0 | Second Floor | 0 | Up to level: Roof - Main | 3.3665 | -1.3135 | 0.475637 | 1.4834 | 0.0801039
197726 | Second Floor | 0 | Second Floor | 0 | Up to level: Roof - Main | 3.3665 | -1.3135 | 4.74673 | 15.6802 | 0.846733
199666 | Second Floor | 2 | Second Floor | 0 | Up to level: Roof - Main | 4.578 | -0.102 | 0.406 | 1.73506 | 0.0936933
203404 | Second Floor | 2 | Second Floor | 0 | Up to level: Second Floor | 3.3532 | 3.3532 | 5.10275 | 16.8121 | 0.907854
206181 | Second Floor | 2 | Second Floor | 0 | Up to level: Roof - Main | 4.578 | -0.102 | 3.7095 | 16.2473 | 0.868703
206370 | Second Floor | 2 | Second Floor | 0 | Up to level: Roof - Main | 4.578 | -0.102 | 1.061 | 4.44982 | 0.24029
206857 | Second Floor | 0 | Second Floor | 0 | Up to level: Roof - Main | 4.578 | -0.102 | 0.483939 | 1.72791 | 0.0933074
206921 | Second Floor | 0 | Second Floor | 0 | Up to level: Roof - Main | 4.578 | -0.102 | 5.8045 | 25.8382 | 1.39527
207085 | Second Floor | 0 | Second Floor | 0 | Up to level: Roof - Main | 4.578 | -0.102 | 0.483939 | 1.72791 | 0.0933074
207119 | Second Floor | 0 | Second Floor | 0 | Up to level: Roof - Main | 4.578 | -0.102 | 0.870997 | 3.98742 | 0.215321
207143 | Second Floor | 0 | Second Floor | 0 | Up to level: Roof - Main | 4.578 | -0.102 | 0.483939 | 1.4807 | 0.0799579
212081 | Second Floor | 0 | Second Floor | 0 | Up to level: Roof - Main | 4.578 | -0.102 | 0.234 | 1.17197 | 0.0632863
219184 | Second Floor | 2 | Second Floor | 0 | Up to level: Roof - Main | 4.578 | -0.102 | 6.44109 | 28.6733 | 1.53971
219313 | Second Floor | 2 | Second Floor | 0 | Up to level: Roof - Main | 4.578 | -0.102 | 0.261 | 1.31846 | 0.0711971
219415 | Second Floor | 2 | Second Floor | 0 | Up to level: Roof - Main | 4.578 | -0.102 | 6.69364 | 30.6435 | 1.65475
220330 | Second Floor | 2 | Second Floor | 0 | Up to level: Roof - Main | 4.578 | -0.102 | 0.371 | 1.53821 | 0.0830632
220355 | Second Floor | 2 | Second Floor | 0 | Up to level: Second Floor | 2.8 | 2.8 | 0.475637 | 1.42978 | 0.0772083
251812 | First Floor | 0 | First Floor | 0 | Up to level: Second Floor | 4.468 | -0.102 | 0.721025 | 3.06516 | 0.165519
251841 | First Floor | 0 | First Floor | 0 | Up to level: Second Floor | 4.468 | -0.102 | 0.406 | 1.81401 | 0.0979564
251918 | First Floor | 0 | First Floor | 0 | Up to level: Second Floor | 4.468 | -0.102 | 0.721025 | 2.82389 | 0.15249
255255 | First Floor | 0 | First Floor | 0 | Up to level: Second Floor | 4.468 | -0.102 | 0.4495 | 1.53252 | 0.0827563
255324 | First Floor | 0 | First Floor | 0 | Up to level: Second Floor | 4.468 | -0.102 | 2.868 | 12.573 | 0.678939
255437 | First Floor | 0 | First Floor | 0 | Up to level: Second Floor | 4.468 | -0.102 | 0.4495 | 1.53252 | 0.0827563
286193 | Second Floor | 3 | Second Floor | 0 | Up to level: Second Floor | 3 | 3 | 0.38176 | 0.773279 | 0.0417571
347963 | First Floor | 0 | First Floor | 0 | Up to level: Second Floor | 4.468 | -0.102 | 0.4499 | 1.53431 | 0.0828528
347994 | First Floor | 0 | First Floor | 0 | Up to level: Second Floor | 4.468 | -0.102 | 0.4495 | 1.29125 | 0.0697276
348052 | First Floor | 0 | First Floor | 0 | Up to level: Second Floor | 4.468 | -0.102 | 0.5914 | 2.486 | 0.134244
348079 | First Floor | 0 | First Floor | 0 | Up to level: Second Floor | 4.468 | -0.102 | 0.4495 | 1.29125 | 0.0697276
348362 | First Floor | 3 | First Floor | 0 | Up to level: Second Floor | 4.468 | -0.102 | 0.4495 | 1.53252 | 0.0827563
348387 | First Floor | 3 | First Floor | 0 | Up to level: Second Floor | 4.468 | -0.102 | 0.4495 | 1.29125 | 0.0697276
348540 | First Floor | 2 | First Floor | 0 | Up to level: Second Floor | 4.468 | -0.102 | 0.406 | 1.93464 | 0.104471
348822 | First Floor | 3 | First Floor | 0 | Up to level: Second Floor | 4.468 | -0.102 | 0.388 | 1.5772 | 0.085169
348849 | First Floor | 3 | First Floor | 0 | Up to level: Second Floor | 4.468 | -0.102 | 0.406 | 1.81401 | 0.0979564
348876 | First Floor | 3 | First Floor | 0 | Up to level: Second Floor | 4.468 | -0.102 | 0.388 | 1.33593 | 0.0721403
348979 | First Floor | 3 | First Floor | 0 | Up to level: Second Floor | 4.468 | -0.102 | 0.4495 | 1.53252 | 0.0827563
349009 | First Floor | 3 | First Floor | 0 | Up to level: Second Floor | 4.468 | -0.102 | 0.4595 | 1.33593 | 0.0721403
349427 | First Floor | 0 | First Floor | 0 | Up to level: Second Floor | 4.468 | -0.102 | 0.4495 | 1.53252 | 0.0827563
351146 | First Floor | 3 | First Floor | 0 | Up to level: Second Floor | 4.468 | -0.102 | 0.439 | 1.80507 | 0.0974739
351978 | First Floor | 3 | First Floor | 0 | Up to level: First Floor | 3 | 3 | 0.161 | 0.3345 | 0.018063
352095 | First Floor | 3 | First Floor | 0 | Up to level: First Floor | 2.5 | 2.5 | 0.495 | 1.15 | 0.0621
352096 | First Floor | 3 | First Floor | 0 | Up to level: First Floor | 2.5 | 2.5 | 0.495 | 1.15 | 0.0621
352097 | First Floor | 3 | First Floor | 0 | Up to level: First Floor | 2.5 | 2.5 | 0.161 | 0.2675 | 0.014445
352168 | First Floor | 3 | First Floor | 0 | Up to level: First Floor | 3 | 3 | 0.495 | 1.38 | 0.07452
352169 | First Floor | 3 | First Floor | 0 | Up to level: First Floor | 2.5 | 2.5 | 0.495 | 1.15 | 0.0621
352170 | First Floor | 3 | First Floor | 0 | Up to level: First Floor | 3 | 3 | 0.161 | 0.3345 | 0.018063
352519 | First Floor | 3 | First Floor | 0 | Up to level: Second Floor | 4.468 | -0.102 | 0.475975 | 1.8139 | 0.0979504
352549 | First Floor | 3 | First Floor | 0 | Up to level: Second Floor | 4.468 | -0.102 | 0.406 | 1.25998 | 0.0680387
352593 | First Floor | 3 | First Floor | 0 | Up to level: First Floor | 3 | 3 | 0.495 | 1.38 | 0.07452
352620 | First Floor | 3 | First Floor | 0 | Up to level: First Floor | 3 | 3 | 0.161 | 0.4695 | 0.025353
352643 | First Floor | 3 | First Floor | 0 | Up to level: First Floor | 2.5 | 2.5 | 0.866 | 2.03 | 0.10962
352743 | First Floor | 3 | First Floor | 0 | Up to level: First Floor | 2.5 | 2.5 | 0.866 | 2.165 | 0.11691
352744 | First Floor | 3 | First Floor | 0 | Up to level: First Floor | 2.5 | 2.5 | 0.495 | 1.15 | 0.0621
352745 | First Floor | 3 | First Floor | 0 | Up to level: First Floor | 2.5 | 2.5 | 0.161 | 0.2675 | 0.014445
352754 | First Floor | 3 | First Floor | 0 | Up to level: First Floor | 2.5 | 2.5 | 0.517 | 1.15 | 0.0621
352755 | First Floor | 3 | First Floor | 0 | Up to level: First Floor | 3 | 3 | 0.517 | 1.38 | 0.07452
352756 | First Floor | 3 | First Floor | 0 | Up to level: First Floor | 3 | 3 | 0.161 | 0.3345 | 0.018063
352847 | First Floor | 3 | First Floor | 0 | Up to level: First Floor | 2.8 | 2.8 | 0.0718739 | 0.201247 | 0.0108673
352888 | First Floor | 3 | First Floor | 0 | Up to level: Second Floor | 4.468 | -0.102 | 0.406 | 1.81401 | 0.0979564
352932 | First Floor | 3 | First Floor | 0 | Up to level: Second Floor | 4.468 | -0.102 | 0.232874 | 0.486448 | 0.0262682
353144 | First Floor | 3 | First Floor | 0 | Up to level: First Floor | 3 | 3 | 0.517 | 1.38 | 0.07452
353145 | First Floor | 3 | First Floor | 0 | Up to level: First Floor | 2.5 | 2.5 | 0.809 | 1.88 | 0.10152
353146 | First Floor | 3 | First Floor | 0 | Up to level: First Floor | 3 | 3 | 0.181 | 0.3945 | 0.021303
353216 | First Floor | 3 | First Floor | 0 | Up to level: Second Floor | 4.468 | -0.102 | 0.406 | 2.05528 | 0.110985
353263 | First Floor | 3 | First Floor | 0 | Up to level: First Floor | 2.5 | 2.5 | 2.001 | 5.0025 | 0.270135
353286 | First Floor | 3 | First Floor | 0 | Up to level: First Floor | 3 | 3 | 0.176 | 0.5415 | 0.029241
353321 | First Floor | 3 | First Floor | 0 | Up to level: First Floor | 3 | 3 | 0.517 | 1.218 | 0.065772
353452 | First Floor | 3 | First Floor | 0 | Up to level: First Floor | 3 | 3 | 0.517 | 1.38 | 0.07452
353479 | First Floor | 3 | First Floor | 0 | Up to level: First Floor | 3 | 3 | 0.181 | 0.5295 | 0.028593
353515 | First Floor | 3 | First Floor | 0 | Up to level: First Floor | 2.5 | 2.5 | 0.809 | 1.745 | 0.09423
353585 | First Floor | 3 | First Floor | 0 | Up to level: First Floor | 2.5 | 2.5 | 0.866 | 2.165 | 0.11691
353610 | First Floor | 3 | First Floor | 0 | Up to level: First Floor | 3 | 3 | 0.181 | 0.5565 | 0.030051
353642 | First Floor | 3 | First Floor | 0 | Up to level: First Floor | 3 | 3 | 0.495 | 1.38 | 0.07452
353693 | First Floor | 3 | First Floor | 0 | Up to level: Second Floor | 4.468 | -0.102 | 0.406 | 1.50125 | 0.0810674
353724 | First Floor | 3 | First Floor | 0 | Up to level: Second Floor | 4.468 | -0.102 | 0.536 | 1.84082 | 0.0994041
354128 | First Floor | 3 | First Floor | 0 | Up to level: Second Floor | 4.468 | -0.102 | 0.406 | 1.93464 | 0.104471
354162 | First Floor | 3 | First Floor | 0 | Up to level: Second Floor | 4.468 | -0.102 | 0.23 | 1.02764 | 0.0554926
354199 | First Floor | 3 | First Floor | 0 | Up to level: Second Floor | 4.468 | -0.102 | 0.474 | 2.11783 | 0.114363
354241 | First Floor | 3 | First Floor | 0 | Up to level: Second Floor | 4.468 | -0.102 | 0.261 | 1.16615 | 0.0629721
354284 | First Floor | 3 | First Floor | 0 | Up to level: Second Floor | 4.468 | -0.102 | 0.655 | 2.52889 | 0.13656
354322 | First Floor | 3 | First Floor | 0 | Up to level: Second Floor | 4.468 | -0.102 | 0.225 | 0.84892 | 0.0458417
354367 | First Floor | 3 | First Floor | 0 | Up to level: Second Floor | 4.468 | -0.102 | 0.406 | 1.57274 | 0.0764832
354757 | First Floor | 3 | First Floor | 0 | Up to level: Second Floor | 4.468 | -0.102 | 7.612 | 34.1311 | 1.84308
354790 | First Floor | 3 | First Floor | 0 | Up to level: Second Floor | 4.468 | -0.102 | 0.406 | 1.81401 | 0.0979564
354853 | First Floor | 3 | First Floor | 0 | Up to level: Second Floor | 4.468 | -0.102 | 7.612 | 34.0104 | 1.83656
354878 | First Floor | 3 | First Floor | 0 | Up to level: Second Floor | 4.468 | -0.102 | 0.406 | 1.57274 | 0.0764832
355029 | First Floor | 3 | First Floor | 0 | Up to level: Second Floor | 4.468 | -0.102 | 1.192 | 4.82991 | 0.260815
355360 | First Floor | 3 | First Floor | 0 | Up to level: Second Floor | 4.468 | -0.102 | 0.355 | 1.3845 | 0.0747632
355533 | First Floor | 3 | First Floor | 0 | Up to level: Second Floor | 4.468 | -0.102 | 0.4025 | 1.86309 | 0.100607
355549 | First Floor | 3 | First Floor | 0 | Up to level: Second Floor | 4.468 | -0.102 | 0.406 | 1.81401 | 0.0979564
355570 | First Floor | 3 | First Floor | 0 | Up to level: Second Floor | 4.468 | -0.102 | 0.4025 | 1.79837 | 0.097112
355664 | First Floor | 3 | First Floor | 0 | Up to level: Second Floor | 4.468 | -0.102 | 0.406 | 1.57274 | 0.0849277
355859 | First Floor | 3 | First Floor | 0 | Up to level: Second Floor | 4.468 | -0.102 | 0.646 | 3.00696 | 0.162376
355883 | First Floor | 3 | First Floor | 0 | Up to level: Second Floor | 4.468 | -0.102 | 0.414 | 1.84975 | 0.0998866
355910 | First Floor | 3 | First Floor | 0 | Up to level: Second Floor | 4.468 | -0.102 | 0.646 | 2.3323 | 0.125944
355969 | First Floor | 3 | First Floor | 0 | Up to level: Second Floor | 4.468 | -0.102 | 0.414 | 1.60848 | 0.0784134
356100 | First Floor | 3 | First Floor | 0 | Up to level: Second Floor | 4.468 | -0.102 | 0.4495 | 1.53252 | 0.0827563
356128 | First Floor | 3 | First Floor | 0 | Up to level: Second Floor | 4.468 | -0.102 | 0.406 | 1.25998 | 0.0680387
356169 | First Floor | 3 | First Floor | 0 | Up to level: Second Floor | 4.468 | -0.102 | 0.4495 | 1.29125 | 0.0697276
356839 | First Floor | 3 | First Floor | 0 | Up to level: Second Floor | 4.468 | -0.102 | 0.4495 | 1.53252 | 0.0827563
356864 | First Floor | 3 | First Floor | 0 | Up to level: Second Floor | 4.468 | -0.102 | 0.406 | 1.81401 | 0.0979564
356902 | First Floor | 3 | First Floor | 0 | Up to level: Second Floor | 4.468 | -0.102 | 0.4495 | 1.29125 | 0.0697276
356950 | First Floor | 3 | First Floor | 0 | Up to level: Second Floor | 4.468 | -0.102 | 0.611 | 2.57357 | 0.138973
356984 | First Floor | 3 | First Floor | 0 | Up to level: Second Floor | 4.468 | -0.102 | 0.406 | 1.25998 | 0.0680387
357037 | First Floor | 3 | First Floor | 0 | Up to level: Second Floor | 4.468 | -0.102 | 0.611 | 2.3323 | 0.125944
357660 | First Floor | 3 | First Floor | 0 | Up to level: Second Floor | 4.468 | -0.102 | 0.388 | 1.5772 | 0.085169
357679 | First Floor | 3 | First Floor | 0 | Up to level: Second Floor | 4.468 | -0.102 | 0.371 | 1.25998 | 0.0680387
357839 | First Floor | 3 | First Floor | 0 | Up to level: Second Floor | 4.468 | -0.102 | 0.371452 | 1.50327 | 0.0811764
357869 | First Floor | 3 | First Floor | 0 | Up to level: Second Floor | 4.468 | -0.102 | 0.406 | 1.81401 | 0.0979564
357891 | First Floor | 3 | First Floor | 0 | Up to level: Second Floor | 4.468 | -0.102 | 0.371452 | 1.26199 | 0.0681477
358187 | First Floor | 3 | First Floor | 0 | Up to level: Second Floor | 4.468 | -0.102 | 0.534 | 2.07315 | 0.11195
358225 | First Floor | 3 | First Floor | 0 | Up to level: Second Floor | 4.468 | -0.102 | 0.406452 | 1.26199 | 0.0681477
358281 | First Floor | 3 | First Floor | 0 | Up to level: Second Floor | 4.468 | -0.102 | 0.534 | 2.14464 | 0.115811
358310 | First Floor | 3 | First Floor | 0 | Up to level: First Floor | 3 | 3 | 0.459546 | 1.37864 | 0.0744465
358336 | First Floor | 3 | First Floor | 0 | Up to level: First Floor | 3 | 3 | 0.181 | 0.5295 | 0.028593
358375 | First Floor | 3 | First Floor | 0 | Up to level: First Floor | 2.5 | 2.5 | 0.494546 | 1.01387 | 0.0547487
358542 | First Floor | 3 | First Floor | 0 | Up to level: Second Floor | 4.468 | -0.102 | 0.349 | 1.30466 | 0.0704514
358564 | First Floor | 3 | First Floor | 0 | Up to level: First Floor | 3 | 3 | 0.181 | 0.5565 | 0.030051
358592 | First Floor | 3 | First Floor | 0 | Up to level: First Floor | 3 | 3 | 0.459998 | 1.21799 | 0.0657717
358657 | First Floor | 3 | First Floor | 0 | Up to level: Second Floor | 4.468 | -0.102 | 12.505 | 40.6016 | 2.19249
358689 | First Floor | 3 | First Floor | 0 | Up to level: First Floor | 3 | 3 | 0.459998 | 1.37999 | 0.0745197
358713 | First Floor | 3 | First Floor | 0 | Up to level: First Floor | 3 | 3 | 0.176 | 0.5145 | 0.027783
358745 | First Floor | 3 | First Floor | 0 | Up to level: First Floor | 2.5 | 2.5 | 0.832 | 2.08 | 0.11232
358815 | First Floor | 3 | First Floor | 0 | Up to level: Second Floor | 4.468 | -0.102 | 0.371 | 1.31311 | 0.070908
358934 | First Floor | 3 | First Floor | 0 | Up to level: First Floor | 2.5 | 2.5 | 0.866 | 1.99 | 0.10746
358961 | First Floor | 3 | First Floor | 0 | Up to level: First Floor | 3 | 3 | 0.181 | 0.5565 | 0.030051
358985 | First Floor | 3 | First Floor | 0 | Up to level: First Floor | 3 | 3 | 0.46 | 1.218 | 0.065772
359079 | First Floor | 3 | First Floor | 0 | Up to level: First Floor | 3 | 3 | 0.495002 | 1.38001 | 0.0745203
359111 | First Floor | 3 | First Floor | 0 | Up to level: First Floor | 3 | 3 | 0.161 | 0.4695 | 0.025353
359150 | First Floor | 3 | First Floor | 0 | Up to level: First Floor | 2.5 | 2.5 | 0.866002 | 2.165 | 0.11691
359306 | First Floor | 3 | First Floor | 0 | Up to level: Second Floor | 4.468 | -0.102 | 3.40597 | 15.0298 | 0.811607
360564 | First Floor | 3 | First Floor | 0 | Up to level: Second Floor | 4.468 | -0.102 | 1.316 | 6.12116 | 0.330543
360606 | First Floor | 3 | First Floor | 0 | Up to level: First Floor | 2.5 | 2.5 | 0.866 | 2.165 | 0.11691
360629 | First Floor | 3 | First Floor | 0 | Up to level: First Floor | 3 | 3 | 0.161 | 0.4965 | 0.026811
360671 | First Floor | 3 | First Floor | 0 | Up to level: First Floor | 3 | 3 | 0.495 | 1.38 | 0.07452
360707 | First Floor | 3 | First Floor | 0 | Up to level: Second Floor | 4.468 | -0.102 | 1.155 | 5.20018 | 0.28081
360735 | First Floor | 3 | First Floor | 0 | Up to level: Second Floor | 4.468 | -0.102 | 0.406 | 1.57274 | 0.0849277
360851 | First Floor | 3 | First Floor | 0 | Up to level: First Floor | 3 | 3 | 0.495 | 1.38 | 0.07452
360852 | First Floor | 3 | First Floor | 0 | Up to level: First Floor | 3 | 3 | 0.161 | 0.4695 | 0.025353
360853 | First Floor | 3 | First Floor | 0 | Up to level: First Floor | 2.5 | 2.5 | 0.495 | 1.015 | 0.05481
360864 | First Floor | 3 | First Floor | 0 | Up to level: First Floor | 2.5 | 2.5 | 0.495 | 1.15 | 0.0621
360865 | First Floor | 3 | First Floor | 0 | Up to level: First Floor | 3 | 3 | 0.161 | 0.4965 | 0.026811
360866 | First Floor | 3 | First Floor | 0 | Up to level: First Floor | 3 | 3 | 0.495 | 1.218 | 0.065772
361033 | First Floor | 3 | First Floor | 0 | Up to level: Second Floor | 4.468 | -0.102 | 0.4495 | 1.53252 | 0.0827563
361063 | First Floor | 3 | First Floor | 0 | Up to level: Second Floor | 4.468 | -0.102 | 0.760912 | 3.0021 | 0.162114
361137 | First Floor | 3 | First Floor | 0 | Up to level: Second Floor | 4.468 | -0.102 | 0.4495 | 1.53252 | 0.0827563
361163 | First Floor | 3 | First Floor | 0 | Up to level: Second Floor | 4.468 | -0.102 | 0.52279 | 2.33583 | 0.126135
361185 | First Floor | 3 | First Floor | 0 | Up to level: Second Floor | 4.468 | -0.102 | 0.4495 | 1.29125 | 0.0697276
361246 | First Floor | 3 | First Floor | 0 | Up to level: Second Floor | 4.468 | -0.102 | 0.4495 | 1.53252 | 0.0827563
361303 | First Floor | 3 | First Floor | 0 | Up to level: Second Floor | 4.468 | -0.102 | 4.446 | 19.8647 | 1.0727
361327 | First Floor | 3 | First Floor | 0 | Up to level: Second Floor | 4.468 | -0.102 | 0.4495 | 1.29125 | 0.0697276
361500 | First Floor | 3 | First Floor | 0 | Up to level: Second Floor | 4.468 | -0.102 | 0.303 | 1.09913 | 0.0593529
361528 | First Floor | 3 | First Floor | 0 | Up to level: Second Floor | 4.468 | -0.102 | 0.966 | 4.31609 | 0.233069
361552 | First Floor | 3 | First Floor | 0 | Up to level: Second Floor | 4.468 | -0.102 | 0.325 | 1.05445 | 0.0569402
361698 | First Floor | 3 | First Floor | 0 | Up to level: Second Floor | 4.468 | -0.102 | 8.86 | 39.4301 | 2.12923
361757 | First Floor | 3 | First Floor | 0 | Up to level: Second Floor | 4.468 | -0.102 | 0.1915 | 0.61435 | 0.0331749
361861 | First Floor | 3 | First Floor | 0 | Up to level: Second Floor | 4.468 | -0.102 | 8.20515 | 36.2665 | 1.95819
361920 | First Floor | 3 | First Floor | 0 | Up to level: Second Floor | 4.468 | -0.102 | 0.406 | 1.25998 | 0.0680387
362162 | First Floor | 3 | First Floor | 0 | Up to level: Second Floor | 4.468 | -0.102 | 2.055 | 8.78409 | 0.474341
362447 | First Floor | 3 | First Floor | 0 | Up to level: Second Floor | 4.468 | -0.102 | 0.2956 | 0.512033 | 0.0276498
362490 | First Floor | 3 | First Floor | 0 | Up to level: Second Floor | 4.468 | -0.102 | 1.1252 | 5.02739 | 0.271479
362521 | First Floor | 3 | First Floor | 0 | Up to level: Second Floor | 4.468 | -0.102 | 0.2956 | 0.824793 | 0.0445388
362624 | First Floor | 3 | First Floor | 0 | Up to level: Second Floor | 4.468 | -0.102 | 0.269 | 1.32253 | 0.0714165
362669 | First Floor | 3 | First Floor | 0 | Up to level: Second Floor | 4.468 | -0.102 | 2.091 | 8.94494 | 0.483027
362804 | First Floor | 3 | First Floor | 0 | Up to level: Second Floor | 4.468 | -0.102 | 1.221 | 5.05778 | 0.27312
362860 | First Floor | 3 | First Floor | 0 | Up to level: Second Floor | 4.468 | -0.102 | 0.4495 | 1.53252 | 0.0827563
362884 | First Floor | 3 | First Floor | 0 | Up to level: Second Floor | 4.468 | -0.102 | 0.4495 | 1.29125 | 0.0697276
363004 | First Floor | 3 | First Floor | 0 | Up to level: Second Floor | 4.468 | -0.102 | 0.4665 | 1.60848 | 0.0868579
363028 | First Floor | 3 | First Floor | 0 | Up to level: Second Floor | 4.468 | -0.102 | 0.772002 | 3.44931 | 0.186263
363050 | First Floor | 3 | First Floor | 0 | Up to level: Second Floor | 4.468 | -0.102 | 0.4665 | 1.36721 | 0.0738292
363093 | First Floor | 3 | First Floor | 0 | Up to level: Second Floor | 4.468 | -0.102 | 0.4665 | 1.60848 | 0.0868579
363139 | First Floor | 3 | First Floor | 0 | Up to level: Second Floor | 4.468 | -0.102 | 0.958498 | 3.56545 | 0.192534
363331 | First Floor | 3 | First Floor | 0 | Up to level: Second Floor | 4.468 | -0.102 | 0.406 | 2.05528 | 0.110985
363372 | First Floor | 3 | First Floor | 0 | Up to level: Second Floor | 4.468 | -0.102 | 0.816 | 3.64589 | 0.196878
363400 | First Floor | 3 | First Floor | 0 | Up to level: Second Floor | 4.468 | -0.102 | 0.406 | 1.81401 | 0.0979564
363430 | First Floor | 3 | First Floor | 0 | Up to level: Second Floor | 4.468 | -0.102 | 0.816 | 3.40462 | 0.183849
363603 | First Floor | 3 | First Floor | 0 | Up to level: Second Floor | 4.468 | -0.102 | 0.617 | 2.50208 | 0.135112
363635 | First Floor | 3 | First Floor | 0 | Up to level: Second Floor | 4.468 | -0.102 | 1.476 | 6.19712 | 0.334644
363700 | First Floor | 3 | First Floor | 0 | Up to level: Second Floor | 4.468 | -0.102 | 1.476 | 6.03627 | 0.325958
363768 | First Floor | 3 | First Floor | 0 | Up to level: Second Floor | 4.468 | -0.102 | 0.596 | 2.42166 | 0.130769
364023 | First Floor | 3 | First Floor | 0 | Up to level: Second Floor | 4.468 | -0.102 | 0.4495 | 1.53252 | 0.0827563
364040 | First Floor | 3 | First Floor | 0 | Up to level: Second Floor | 4.468 | -0.102 | 0.526975 | 1.85858 | 0.100363
364152 | First Floor | 3 | First Floor | 0 | Up to level: Second Floor | 4.468 | -0.102 | 1.3375 | 5.50011 | 0.297006
364183 | First Floor | 3 | First Floor | 0 | Up to level: Second Floor | 4.468 | -0.102 | 0.4665 | 1.36721 | 0.0738292
364258 | First Floor | 3 | First Floor | 0 | Up to level: Second Floor | 4.468 | -0.102 | 0.128 | 0.415524 | 0.0224383
364288 | First Floor | 3 | First Floor | 0 | Up to level: Second Floor | 4.468 | -0.102 | 0.6945 | 2.45513 | 0.132577
364544 | First Floor | 3 | First Floor | 0 | Up to level: Second Floor | 4.468 | -0.102 | 0.250606 | 1.24035 | 0.0669787
364589 | First Floor | 3 | First Floor | 0 | Up to level: Second Floor | 4.468 | -0.102 | 0.739 | 3.30185 | 0.1783
364620 | First Floor | 3 | First Floor | 0 | Up to level: Second Floor | 4.468 | -0.102 | 0.156 | 0.697008 | 0.0376384
364660 | First Floor | 3 | First Floor | 0 | Up to level: Second Floor | 4.468 | -0.102 | 0.7 | 2.88633 | 0.147417
364692 | First Floor | 3 | First Floor | 0 | Up to level: Second Floor | 4.468 | -0.102 | 0.19 | 0.728284 | 0.0393273
364911 | First Floor | 3 | First Floor | 0 | Up to level: Second Floor | 4.468 | -0.102 | 0.406 | 2.05528 | 0.110985
364949 | First Floor | 3 | First Floor | 0 | Up to level: Second Floor | 4.468 | -0.102 | 1.841 | 8.22559 | 0.444182
364980 | First Floor | 3 | First Floor | 0 | Up to level: Second Floor | 4.468 | -0.102 | 0.25 | 1.117 | 0.060318
365033 | First Floor | 3 | First Floor | 0 | Up to level: Second Floor | 4.468 | -0.102 | 1.435 | 6.41158 | 0.346225
365065 | First Floor | 3 | First Floor | 0 | Up to level: Second Floor | 4.468 | -0.102 | 0.156 | 0.697008 | 0.0376384
365095 | First Floor | 3 | First Floor | 0 | Up to level: Second Floor | 4.468 | -0.102 | 0.406 | 1.57274 | 0.0849277
365307 | First Floor | 3 | First Floor | 0 | Up to level: Second Floor | 4.468 | -0.102 | 1.3 | 5.25437 | 0.283736
365371 | First Floor | 3 | First Floor | 0 | Up to level: Second Floor | 4.468 | -0.102 | 0.388 | 1.5772 | 0.085169
365392 | First Floor | 3 | First Floor | 0 | Up to level: Second Floor | 4.468 | -0.102 | 0.406 | 1.81401 | 0.0979564
365413 | First Floor | 3 | First Floor | 0 | Up to level: Second Floor | 4.468 | -0.102 | 0.388 | 1.33593 | 0.0721403
365504 | First Floor | 3 | First Floor | 0 | Up to level: Second Floor | 4.468 | -0.102 | 0.4495 | 1.53252 | 0.0827563
365525 | First Floor | 3 | First Floor | 0 | Up to level: Second Floor | 4.468 | -0.102 | 0.406 | 1.81401 | 0.0979564
365544 | First Floor | 3 | First Floor | 0 | Up to level: Second Floor | 4.468 | -0.102 | 0.4495 | 1.29125 | 0.0697276
365669 | First Floor | 3 | First Floor | 0 | Up to level: Second Floor | 4.468 | -0.102 | 0.406 | 2.05528 | 0.110985
365700 | First Floor | 3 | First Floor | 0 | Up to level: Second Floor | 4.468 | -0.102 | 0.406 | 1.81401 | 0.0979564
365729 | First Floor | 3 | First Floor | 0 | Up to level: Second Floor | 4.468 | -0.102 | 0.406 | 1.81401 | 0.0979564
365773 | First Floor | 3 | First Floor | 0 | Up to level: Second Floor | 4.468 | -0.102 | 0.406 | 1.57274 | 0.0849277
365862 | First Floor | 3 | First Floor | 0 | Up to level: Second Floor | 4.468 | -0.102 | 0.406 | 1.93464 | 0.104471
365923 | First Floor | 3 | First Floor | 0 | Up to level: Second Floor | 4.468 | -0.102 | 4.59 | 20.5081 | 1.10744
365943 | First Floor | 3 | First Floor | 0 | Up to level: Second Floor | 4.468 | -0.102 | 0.406 | 1.81401 | 0.0979564
366008 | First Floor | 3 | First Floor | 0 | Up to level: Second Floor | 4.468 | -0.102 | 4.59 | 20.2668 | 1.08597
366074 | First Floor | 3 | First Floor | 0 | Up to level: Second Floor | 4.468 | -0.102 | 0.4495 | 1.53252 | 0.0827563
366099 | First Floor | 3 | First Floor | 0 | Up to level: Second Floor | 4.468 | -0.102 | 0.406 | 1.81401 | 0.0979564
366113 | First Floor | 3 | First Floor | 0 | Up to level: Second Floor | 4.468 | -0.102 | 0.4495 | 1.29125 | 0.0697276
366327 | First Floor | 3 | First Floor | 0 | Up to level: Second Floor | 4.468 | -0.102 | 1.306 | 5.52245 | 0.298212
366367 | First Floor | 3 | First Floor | 0 | Up to level: Second Floor | 4.468 | -0.102 | 0.423 | 1.33593 | 0.0721403
366430 | First Floor | 3 | First Floor | 0 | Up to level: Second Floor | 4.468 | -0.102 | 1.306 | 5.59394 | 0.302073
366458 | First Floor | 3 | First Floor | 0 | Up to level: Second Floor | 4.468 | -0.102 | 0.423 | 1.33593 | 0.0721403
366630 | First Floor | 3 | First Floor | 0 | Up to level: Second Floor | 4.468 | -0.102 | 0.739426 | 3.54503 | 0.191431
366694 | First Floor | 3 | First Floor | 0 | Up to level: Second Floor | 4.468 | -0.102 | 0.471 | 1.70678 | 0.0921659
366760 | First Floor | 3 | First Floor | 0 | Up to level: Second Floor | 4.468 | -0.102 | 0.471 | 1.70678 | 0.0921659
366871 | First Floor | 3 | First Floor | 0 | Up to level: Second Floor | 4.468 | -0.102 | 1 | 4.3518 | 0.234997
366898 | First Floor | 3 | First Floor | 0 | Up to level: Second Floor | 4.468 | -0.102 | 0.406 | 1.81401 | 0.0979564
366915 | First Floor | 3 | First Floor | 0 | Up to level: Second Floor | 4.468 | -0.102 | 5.346 | 23.8859 | 1.28984
366955 | First Floor | 3 | First Floor | 0 | Up to level: Second Floor | 4.468 | -0.102 | 0.195001 | 0.871263 | 0.0470482
366996 | First Floor | 3 | First Floor | 0 | Up to level: Second Floor | 4.468 | -0.102 | 0.414 | 1.84975 | 0.0998866
367022 | First Floor | 3 | First Floor | 0 | Up to level: Second Floor | 4.468 | -0.102 | 0.195001 | 0.629991 | 0.0340195
367103 | First Floor | 3 | First Floor | 0 | Up to level: Second Floor | 4.468 | -0.102 | 0.406 | 1.81401 | 0.0979564
367159 | First Floor | 3 | First Floor | 0 | Up to level: Second Floor | 4.468 | -0.102 | 2.331 | 10.0173 | 0.540932
367254 | First Floor | 3 | First Floor | 0 | Up to level: Second Floor | 4.468 | -0.102 | 0.4495 | 1.53252 | 0.0827563
367279 | First Floor | 3 | First Floor | 0 | Up to level: Second Floor | 4.468 | -0.102 | 0.4495 | 1.29125 | 0.0697276
367324 | First Floor | 3 | First Floor | 0 | Up to level: Second Floor | 4.468 | -0.102 | 0.4495 | 1.53252 | 0.0827563
367352 | First Floor | 3 | First Floor | 0 | Up to level: Second Floor | 4.468 | -0.102 | 0.406 | 1.81401 | 0.0979564
367373 | First Floor | 3 | First Floor | 0 | Up to level: Second Floor | 4.468 | -0.102 | 0.4495 | 1.29125 | 0.0697276
367823 | First Floor | 3 | First Floor | 0 | Up to level: Second Floor | 4.468 | -0.102 | 1.08107 | 4.3544 | 0.235137
367846 | First Floor | 3 | First Floor | 0 | Up to level: Second Floor | 4.468 | -0.102 | 0.471 | 1.70678 | 0.0921659
367966 | First Floor | 3 | First Floor | 0 | Up to level: Second Floor | 4.468 | -0.102 | 0.375 | 1.51912 | 0.0820325
367994 | First Floor | 3 | First Floor | 0 | Up to level: Second Floor | 4.468 | -0.102 | 0.449499 | 1.29125 | 0.0697274
368047 | First Floor | 3 | First Floor | 0 | Up to level: Second Floor | 4.468 | -0.102 | 0.449499 | 1.53252 | 0.0827561
368070 | First Floor | 3 | First Floor | 0 | Up to level: Second Floor | 4.468 | -0.102 | 0.406 | 1.81401 | 0.0979564
368101 | First Floor | 3 | First Floor | 0 | Up to level: Second Floor | 4.468 | -0.102 | 0.449499 | 1.29125 | 0.0697274
368181 | First Floor | 3 | First Floor | 0 | Up to level: Second Floor | 4.468 | -0.102 | 0.4495 | 1.53252 | 0.0827563
368214 | First Floor | 3 | First Floor | 0 | Up to level: Second Floor | 4.468 | -0.102 | 0.4495 | 1.29125 | 0.0697276
368361 | First Floor | 3 | First Floor | 0 | Up to level: Second Floor | 4.468 | -0.102 | 0.4495 | 1.53252 | 0.0827563
368387 | First Floor | 3 | First Floor | 0 | Up to level: Second Floor | 4.468 | -0.102 | 0.406 | 1.81401 | 0.0979564
368407 | First Floor | 3 | First Floor | 0 | Up to level: Second Floor | 4.468 | -0.102 | 0.406 | 1.81401 | 0.0979564
368432 | First Floor | 3 | First Floor | 0 | Up to level: Second Floor | 4.468 | -0.102 | 0.4495 | 1.29125 | 0.0697276
369896 | First Floor | 3 | First Floor | 2.5 | Up to level: First Floor | 0.5 | 3 | 1.764 | 0.882 | 0.047628
370029 | First Floor | 3 | First Floor | 0 | Up to level: First Floor | 2.5 | 2.5 | 0.494546 | 1.15 | 0.0620997
370199 | First Floor | 3 | First Floor | 0 | Up to level: Second Floor | 4.468 | -0.102 | 0.406452 | 1.63399 | 0.0882357
370495 | First Floor | 3 | First Floor | 2.5 | Up to level: First Floor | 0.5 | 3 | 3.284 | 1.642 | 0.088668
370983 | First Floor | 3 | First Floor | 2.5 | Up to level: First Floor | 0.5 | 3 | 1.764 | 0.882 | 0.047628
371075 | First Floor | 3 | First Floor | 2.5 | Up to level: First Floor | 0.5 | 3 | 4.77403 | 2.38701 | 0.128899
377559 | First Floor | 3 | First Floor | 2.8 | Up to level: Second Floor | 1.77 | 0 | 5.02797 | 8.83756 | 0.477228
377594 | First Floor | 3 | First Floor | 2.8 | Up to level: Second Floor | 1.77 | 0 | 2.774 | 4.75245 | 0.256632
378052 | First Floor | 3 | First Floor | 2.5 | Up to level: First Floor | 0.5 | 3 | 1.764 | 0.882 | 0.047628
378076 | First Floor | 3 | First Floor | 2.5 | Up to level: First Floor | 0.5 | 3 | 4.774 | 2.387 | 0.128898
378104 | First Floor | 3 | First Floor | 2.5 | Up to level: First Floor | 0.5 | 3 | 3.33775 | 1.66887 | 0.0901192
378209 | First Floor | 3 | First Floor | 2.5 | Up to level: First Floor | 0.5 | 3 | 3.33775 | 1.66887 | 0.0901192
379583 | Second Floor | 3 | Second Floor | 0 | Up to level: Second Floor | 2.8 | 2.8 | 0.41676 | 1.06893 | 0.0577221
379615 | Second Floor | 3 | Second Floor | 0 | Up to level: Roof - Main | 4.578 | -0.102 | 0.205 | 0.93849 | 0.0506785
379701 | Second Floor | 3 | Second Floor | 0 | Up to level: Roof - Main | 4.578 | -0.102 | 7.03 | 32.1833 | 1.7379
379749 | Second Floor | 3 | Second Floor | 0 | Up to level: Roof - Main | 4.578 | -0.102 | 0.406 | 1.85867 | 0.100368
379832 | Second Floor | 3 | Second Floor | 0 | Up to level: Roof - Main | 4.578 | -0.102 | 7.44676 | 34.2515 | 1.84958
384802 | Second Floor | 3 | Second Floor | 0 | Up to level: Roof - Main | 4.68 | 0 | 0.333 | 1.6848 | 0.0909792
384836 | Second Floor | 3 | Second Floor | 0 | Up to level: Roof - Main | 4.68 | 0 | 0.406 | 1.90008 | 0.102604
384864 | Second Floor | 3 | Second Floor | 0 | Up to level: Roof - Main | 4.68 | 0 | 0.483939 | 1.51369 | 0.0817395
384996 | Second Floor | 3 | Second Floor | 0 | Up to level: Roof - Main | 4.68 | 0 | 0.4865 | 1.7784 | 0.0960336
385014 | Second Floor | 3 | Second Floor | 0 | Up to level: Roof - Main | 4.68 | 0 | 0.676 | 3.16368 | 0.170839
385034 | Second Floor | 3 | Second Floor | 0 | Up to level: Roof - Main | 4.68 | 0 | 0.4865 | 1.52568 | 0.0823867
385155 | Second Floor | 3 | Second Floor | 0 | Up to level: Roof - Main | 4.68 | 0 | 0.483834 | 1.76592 | 0.0953599
385183 | Second Floor | 3 | Second Floor | 0 | Up to level: Roof - Main | 4.68 | 0 | 1.08005 | 5.05463 | 0.27295
385205 | Second Floor | 3 | Second Floor | 0 | Up to level: Roof - Main | 4.68 | 0 | 0.483834 | 1.5132 | 0.0817131
385337 | Second Floor | 3 | Second Floor | 0 | Up to level: Roof - Main | 4.68 | 0 | 0.483834 | 1.76592 | 0.0953599
385579 | Second Floor | 3 | Second Floor | 0 | Up to level: Roof - Main | 4.68 | 0 | 3.57525 | 16.7322 | 0.903538
385615 | Second Floor | 3 | Second Floor | 0 | Up to level: Roof - Main | 4.68 | 0 | 0.483834 | 1.5132 | 0.0817131
385670 | Second Floor | 3 | Second Floor | 0 | Up to level: Roof - Main | 4.68 | 0 | 0.483834 | 1.76592 | 0.0953599
385704 | Second Floor | 3 | Second Floor | 0 | Up to level: Roof - Main | 4.68 | 0 | 0.952697 | 4.45862 | 0.240766
385726 | Second Floor | 3 | Second Floor | 0 | Up to level: Roof - Main | 4.68 | 0 | 0.483834 | 1.5132 | 0.0817131
385956 | Second Floor | 3 | Second Floor | 0 | Up to level: Roof - Main | 4.68 | 0 | 0.4495 | 1.60524 | 0.086683
385979 | Second Floor | 3 | Second Floor | 0 | Up to level: Roof - Main | 4.68 | 0 | 0.473939 | 1.46689 | 0.0792122
386051 | Second Floor | 3 | Second Floor | 0 | Up to level: Roof - Main | 4.68 | 0 | 0.4495 | 1.60524 | 0.086683
386083 | Second Floor | 3 | Second Floor | 0 | Up to level: Roof - Main | 4.68 | 0 | 0.634915 | 2.9714 | 0.160456
386101 | Second Floor | 3 | Second Floor | 0 | Up to level: Roof - Main | 4.68 | 0 | 0.4495 | 1.35252 | 0.0730361
386213 | Second Floor | 3 | Second Floor | 0 | Up to level: Roof - Main | 4.68 | 0 | 0.4495 | 1.60524 | 0.086683
386266 | Second Floor | 3 | Second Floor | 0 | Up to level: Roof - Main | 4.68 | 0 | 3.59308 | 16.8156 | 0.908044
386284 | Second Floor | 3 | Second Floor | 0 | Up to level: Roof - Main | 4.68 | 0 | 0.4495 | 1.35252 | 0.0730361
386575 | Second Floor | 3 | Second Floor | 0 | Up to level: Roof - Main | 4.68 | 0 | 0.596 | 3.042 | 0.164268
386614 | Second Floor | 3 | Second Floor | 0 | Up to level: Roof - Main | 4.68 | 0 | 0.801 | 3.74868 | 0.202429
386647 | Second Floor | 3 | Second Floor | 0 | Up to level: Roof - Main | 4.68 | 0 | 0.596 | 2.78928 | 0.150621
386679 | Second Floor | 3 | Second Floor | 0 | Up to level: Roof - Main | 4.68 | 0 | 0.801 | 3.49596 | 0.188782
387052 | Second Floor | 3 | Second Floor | 0 | Up to level: Roof - Main | 4.68 | 0 | 0.596 | 3.042 | 0.164268
387094 | Second Floor | 3 | Second Floor | 0 | Up to level: Roof - Main | 4.68 | 0 | 0.406 | 1.90008 | 0.102604
387126 | Second Floor | 3 | Second Floor | 0 | Up to level: Roof - Main | 4.68 | 0 | 0.596 | 2.78928 | 0.150621
387163 | Second Floor | 3 | Second Floor | 0 | Up to level: Roof - Main | 4.68 | 0 | 0.406 | 1.64736 | 0.0889574
387557 | Second Floor | 3 | Second Floor | 0 | Up to level: Roof - Main | 4.68 | 0 | 0.641 | 2.83608 | 0.153148
387610 | Second Floor | 3 | Second Floor | 0 | Up to level: Roof - Main | 4.68 | 0 | 0.976 | 4.56768 | 0.246655
387672 | Second Floor | 3 | Second Floor | 0 | Up to level: Roof - Main | 4.68 | 0 | 0.676 | 3.16368 | 0.170839
387730 | Second Floor | 3 | Second Floor | 0 | Up to level: Roof - Main | 4.68 | 0 | 0.781 | 3.53147 | 0.1907
387774 | Second Floor | 3 | Second Floor | 0 | Up to level: Roof - Main | 4.68 | 0 | 0.44 | 2.0592 | 0.102544
387805 | Second Floor | 3 | Second Floor | 0 | Up to level: Roof - Main | 4.68 | 0 | 0.195 | 0.65988 | 0.0356335
388119 | Second Floor | 3 | Second Floor | 0 | Up to level: Roof - Main | 4.578 | -0.102 | 0.406 | 1.85867 | 0.100368
388120 | Second Floor | 3 | Second Floor | 0 | Up to level: Roof - Main | 4.578 | -0.102 | 0.976 | 4.46813 | 0.241279
388121 | Second Floor | 3 | Second Floor | 0 | Up to level: Roof - Main | 4.578 | -0.102 | 0.406 | 1.85867 | 0.100368
388122 | Second Floor | 3 | Second Floor | 0 | Up to level: Roof - Main | 4.578 | -0.102 | 0.976 | 4.46813 | 0.241279
388433 | Second Floor | 3 | Second Floor | 0 | Up to level: Roof - Main | 4.578 | -0.102 | 0.756025 | 3.46108 | 0.186898
388434 | Second Floor | 3 | Second Floor | 0 | Up to level: Roof - Main | 4.578 | -0.102 | 0.436 | 1.99601 | 0.107784
388435 | Second Floor | 3 | Second Floor | 0 | Up to level: Roof - Main | 4.578 | -0.102 | 0.756025 | 3.46108 | 0.186898
388436 | Second Floor | 3 | Second Floor | 0 | Up to level: Roof - Main | 4.578 | -0.102 | 0.436 | 1.99601 | 0.107784
388643 | Second Floor | 3 | Second Floor | 0 | Up to level: Roof - Main | 4.578 | -0.102 | 0.705 | 3.06726 | 0.165632
388667 | Second Floor | 3 | Second Floor | 0 | Up to level: Roof - Main | 4.578 | -0.102 | 0.406 | 1.85867 | 0.100368
388696 | Second Floor | 3 | Second Floor | 0 | Up to level: Roof - Main | 4.578 | -0.102 | 0.705 | 2.82005 | 0.152283
388917 | Second Floor | 2 | Second Floor | 0 | Up to level: Roof - Main | 4.578 | -0.102 | 0.416 | 2.02805 | 0.109515
389313 | Second Floor | 3 | Second Floor | 0 | Up to level: Roof - Main | 4.578 | -0.102 | 0.4495 | 1.57025 | 0.0847937
389358 | Second Floor | 3 | Second Floor | 0 | Up to level: Roof - Main | 4.578 | -0.102 | 0.698561 | 2.79057 | 0.150691
389436 | Second Floor | 3 | Second Floor | 0 | Up to level: Roof - Main | 4.578 | -0.102 | 0.4495 | 1.57025 | 0.0847937
389507 | Second Floor | 3 | Second Floor | 0 | Up to level: Roof - Main | 4.578 | -0.102 | 4.446 | 20.3538 | 1.0991
389537 | Second Floor | 3 | Second Floor | 0 | Up to level: Roof - Main | 4.578 | -0.102 | 0.4495 | 1.32304 | 0.0714443
389663 | Second Floor | 3 | Second Floor | 0 | Up to level: Second Floor | 2.1054 | 2.1054 | 0.4505 | 0.724258 | 0.0391099
389693 | Second Floor | 3 | Second Floor | 0 | Up to level: Second Floor | 2.1054 | 2.1054 | 0.796 | 1.6759 | 0.0904985
389719 | Second Floor | 3 | Second Floor | 0 | Up to level: Second Floor | 2.1054 | 2.1054 | 0.4505 | 0.610566 | 0.0329706
390490 | Second Floor | 3 | Second Floor | 0 | Up to level: Roof - Main | 4.578 | -0.102 | 0.265 | 1.05294 | 0.0568588
390522 | Second Floor | 3 | Second Floor | 0 | Up to level: Roof - Main | 4.578 | -0.102 | 0.23 | 1.05294 | 0.0568588
390574 | Second Floor | 3 | Second Floor | 0 | Up to level: Roof - Main | 4.578 | -0.102 | 0.44 | 2.01432 | 0.108773
390609 | Second Floor | 3 | Second Floor | 0 | Up to level: Roof - Main | 4.578 | -0.102 | 0.261 | 1.19486 | 0.0645223
390641 | Second Floor | 3 | Second Floor | 0 | Up to level: Roof - Main | 4.578 | -0.102 | 0.705 | 2.82005 | 0.152283
390788 | Second Floor | 3 | Second Floor | 0 | Up to level: Roof - Main | 4.578 | -0.102 | 0.406 | 1.85867 | 0.100368
390789 | Second Floor | 3 | Second Floor | 0 | Up to level: Roof - Main | 4.578 | -0.102 | 0.406 | 1.85867 | 0.100368
390790 | Second Floor | 3 | Second Floor | 0 | Up to level: Roof - Main | 4.578 | -0.102 | 0.406 | 1.85867 | 0.100368
390791 | Second Floor | 3 | Second Floor | 0 | Up to level: Roof - Main | 4.578 | -0.102 | 0.406 | 1.85867 | 0.100368
390816 | Second Floor | 3 | Second Floor | 0 | Up to level: Roof - Main | 4.578 | -0.102 | 0.406 | 1.85867 | 0.100368
390817 | Second Floor | 3 | Second Floor | 0 | Up to level: Roof - Main | 4.578 | -0.102 | 0.406 | 1.85867 | 0.100368
390818 | Second Floor | 3 | Second Floor | 0 | Up to level: Roof - Main | 4.578 | -0.102 | 0.406 | 1.85867 | 0.100368
390819 | Second Floor | 3 | Second Floor | 0 | Up to level: Roof - Main | 4.578 | -0.102 | 0.406 | 1.85867 | 0.100368
390877 | Second Floor | 3 | Second Floor | 0 | Up to level: Roof - Main | 4.578 | -0.102 | 0.265 | 1.05294 | 0.0568588
390913 | Second Floor | 3 | Second Floor | 0 | Up to level: Roof - Main | 4.578 | -0.102 | 0.406 | 1.85867 | 0.100368
390936 | Second Floor | 3 | Second Floor | 0 | Up to level: Roof - Main | 4.578 | -0.102 | 0.265 | 0.805728 | 0.0435093
392112 | Second Floor | 3 | Second Floor | 0 | Up to level: Roof - Main | 4.578 | -0.102 | 0.4495 | 1.57025 | 0.0847937
392224 | Second Floor | 3 | Second Floor | 0 | Up to level: Roof - Main | 4.578 | -0.102 | 4.3148 | 19.7532 | 1.06667
392246 | Second Floor | 3 | Second Floor | 0 | Up to level: Roof - Main | 4.578 | -0.102 | 0.4495 | 1.32304 | 0.0714443
392297 | Second Floor | 3 | Second Floor | 0 | Up to level: Second Floor | 2.8 | 2.8 | 0.4495 | 0.9604 | 0.0518616
392344 | Second Floor | 3 | Second Floor | 0 | Up to level: Second Floor | 2.8 | 2.8 | 1.47394 | 2.95641 | 0.159646
393263 | Second Floor | 3 | Second Floor | 0 | Up to level: Roof - Main | 4.578 | -0.102 | 0.541 | 2.31647 | 0.125089
393287 | Second Floor | 3 | Second Floor | 0 | Up to level: Roof - Main | 4.578 | -0.102 | 0.4495 | 1.32304 | 0.0714443
393463 | Second Floor | 3 | Second Floor | 0 | Up to level: Roof - Main | 4.578 | -0.102 | 0.676 | 3.09473 | 0.167115
393508 | Second Floor | 3 | Second Floor | 0 | Up to level: Roof - Main | 4.578 | -0.102 | 0.295 | 0.782837 | 0.0422732
393547 | Second Floor | 3 | Second Floor | 0 | Up to level: Roof - Main | 4.578 | -0.102 | 0.27 | 0.988849 | 0.0533978
393578 | Second Floor | 3 | Second Floor | 0 | Up to level: Roof - Main | 4.578 | -0.102 | 0.111 | 0.755371 | 0.04079
393618 | Second Floor | 3 | Second Floor | 0 | Up to level: Roof - Main | 4.578 | -0.102 | 0.406 | 1.85867 | 0.100368
393644 | Second Floor | 3 | Second Floor | 0 | Up to level: Roof - Main | 4.578 | -0.102 | 0.406 | 1.291 | 0.0697138
393736 | Second Floor | 3 | Second Floor | 0 | Up to level: Roof - Main | 4.578 | -0.102 | 0.616025 | 2.82016 | 0.152289
393737 | Second Floor | 3 | Second Floor | 0 | Up to level: Roof - Main | 4.578 | -0.102 | 0.406 | 1.85867 | 0.100368
393738 | Second Floor | 3 | Second Floor | 0 | Up to level: Roof - Main | 4.578 | -0.102 | 0.616025 | 2.82016 | 0.152289
393739 | Second Floor | 3 | Second Floor | 0 | Up to level: Roof - Main | 4.578 | -0.102 | 0.406 | 1.85867 | 0.100368
393862 | Second Floor | 3 | Second Floor | 0 | Up to level: Roof - Main | 4.578 | -0.102 | 0.851 | 3.73565 | 0.201725
393892 | Second Floor | 3 | Second Floor | 0 | Up to level: Roof - Main | 4.578 | -0.102 | 0.371 | 1.291 | 0.0697138
393950 | Second Floor | 3 | Second Floor | 0 | Up to level: Roof - Main | 4.578 | -0.102 | 0.371 | 1.53821 | 0.0830632
393970 | Second Floor | 3 | Second Floor | 0 | Up to level: Roof - Main | 4.578 | -0.102 | 0.811 | 3.30532 | 0.178487
394048 | Second Floor | 3 | Second Floor | 0 | Up to level: Roof - Main | 4.578 | -0.102 | 0.405 | 1.69386 | 0.0914684
394092 | Second Floor | 3 | Second Floor | 0 | Up to level: Roof - Main | 4.578 | -0.102 | 0.406 | 1.85867 | 0.100368
394119 | Second Floor | 3 | Second Floor | 0 | Up to level: Roof - Main | 4.578 | -0.102 | 0.405 | 1.44665 | 0.078119
394193 | Second Floor | 3 | Second Floor | 0 | Up to level: Roof - Main | 4.578 | -0.102 | 0.4495 | 1.57025 | 0.0847937
394216 | Second Floor | 3 | Second Floor | 0 | Up to level: Roof - Main | 4.578 | -0.102 | 0.406 | 1.85867 | 0.100368
394233 | Second Floor | 3 | Second Floor | 0 | Up to level: Roof - Main | 4.578 | -0.102 | 0.4495 | 1.32304 | 0.0714443
394312 | Second Floor | 3 | Second Floor | 0 | Up to level: Roof - Main | 4.578 | -0.102 | 0.4495 | 1.57025 | 0.0847937
394333 | Second Floor | 3 | Second Floor | 0 | Up to level: Roof - Main | 4.578 | -0.102 | 0.406 | 1.85867 | 0.100368
394351 | Second Floor | 3 | Second Floor | 0 | Up to level: Roof - Main | 4.578 | -0.102 | 0.4495 | 1.32304 | 0.0714443
394422 | Second Floor | 3 | Second Floor | 0 | Up to level: Roof - Main | 4.578 | -0.102 | 0.4495 | 1.57025 | 0.0847937
394440 | Second Floor | 3 | Second Floor | 0 | Up to level: Roof - Main | 4.578 | -0.102 | 0.483511 | 2.21351 | 0.11953
394452 | Second Floor | 3 | Second Floor | 0 | Up to level: Roof - Main | 4.578 | -0.102 | 0.4495 | 1.32304 | 0.0714443
394518 | Second Floor | 3 | Second Floor | 0 | Up to level: Roof - Main | 4.578 | -0.102 | 0.4495 | 1.57025 | 0.0847937
394533 | Second Floor | 3 | Second Floor | 0 | Up to level: Roof - Main | 4.578 | -0.102 | 0.621492 | 2.11042 | 0.113963
394604 | Second Floor | 3 | Second Floor | 0 | Up to level: Roof - Main | 4.578 | -0.102 | 0.4495 | 1.57025 | 0.0847937
394660 | Second Floor | 3 | Second Floor | 0 | Up to level: Roof - Main | 4.578 | -0.102 | 2.62401 | 12.0127 | 0.648686
394672 | Second Floor | 3 | Second Floor | 0 | Up to level: Roof - Main | 4.578 | -0.102 | 0.4495 | 1.32304 | 0.0714443
394804 | Second Floor | 3 | Second Floor | 0 | Up to level: Roof - Main | 4.578 | -0.102 | 0.4495 | 1.57025 | 0.0847937
394831 | Second Floor | 3 | Second Floor | 0 | Up to level: Roof - Main | 4.578 | -0.102 | 2.641 | 11.6831 | 0.630885
394996 | Second Floor | 3 | Second Floor | 0 | Up to level: Roof - Main | 4.578 | -0.102 | 3.181 | 14.4024 | 0.777729
395014 | Second Floor | 3 | Second Floor | 0 | Up to level: Roof - Main | 4.578 | -0.102 | 0.415061 | 1.16538 | 0.0629306
395119 | Second Floor | 3 | Second Floor | 0 | Up to level: Roof - Main | 4.578 | -0.102 | 0.415061 | 1.41259 | 0.0762801
395153 | Second Floor | 3 | Second Floor | 0 | Up to level: Roof - Main | 4.578 | -0.102 | 1.985 | 8.67989 | 0.468714
395226 | Second Floor | 3 | Second Floor | 0 | Up to level: Roof - Main | 4.578 | -0.102 | 1.391 | 6.20777 | 0.335219
395240 | Second Floor | 3 | Second Floor | 0 | Up to level: Roof - Main | 4.578 | -0.102 | 0.415061 | 1.16538 | 0.0629306
395310 | Second Floor | 3 | Second Floor | 0 | Up to level: Roof - Main | 4.578 | -0.102 | 0.415061 | 1.41259 | 0.0762801
395332 | Second Floor | 3 | Second Floor | 0 | Up to level: Roof - Main | 4.578 | -0.102 | 0.620975 | 2.43538 | 0.131511
395438 | Second Floor | 3 | Second Floor | 0 | Up to level: Roof - Main | 4.578 | -0.102 | 0.66 | 2.86125 | 0.154507
395460 | Second Floor | 3 | Second Floor | 0 | Up to level: Roof - Main | 4.578 | -0.102 | 0.415061 | 1.16538 | 0.0629306
395566 | Second Floor | 3 | Second Floor | 0 | Up to level: Roof - Main | 4.578 | -0.102 | 0.415061 | 1.41259 | 0.0762801
395610 | Second Floor | 3 | Second Floor | 0 | Up to level: Roof - Main | 4.578 | -0.102 | 5.4095 | 24.0299 | 1.29762
396498 | Second Floor | 3 | Second Floor | 1.55 | Up to level: Roof - Main | 1.8165 | -1.3135 | 3.64797 | 6.46488 | 0.340583
398670 | Second Floor | 3 | Second Floor | 0 | Up to level: Roof - Main | 4.578 | -0.102 | 0.261 | 0.650076 | 0.0351041
398743 | Second Floor | 3 | Second Floor | 0 | Up to level: Roof - Main | 4.578 | -0.102 | 1.1985 | 4.91906 | 0.265629
398821 | Second Floor | 3 | Second Floor | 0 | Up to level: Roof - Main | 4.578 | -0.102 | 1.37425 | 5.72364 | 0.309077
398964 | Second Floor | 3 | Second Floor | 0 | Up to level: Roof - Main | 4.578 | -0.102 | 1.37425 | 5.72364 | 0.309077
399279 | Second Floor | 3 | Second Floor | 0 | Up to level: Second Floor | 3.3532 | 3.3532 | 0.41676 | 0.86432 | 0.0466733

# IfcWallStandardCase: Basic Wall:Interior - Partition (92mm Stud):128360 (460)
Material: Plasterboard 0.016 m, Metal - Stud Layer 0.092 m, Plasterboard 0.016 m
Pset_WallCommon - Reference: Basic Wall:Interior - Partition (92mm Stud); LoadBearing: no; ExtendToStructure: no; IsExternal: no
PSet_Revit_Constraints - Base is Attached: no; Base Extension Distance: 0 m; Top is Attached: no; Top Extension Distance: 0 m; Room Bounding: yes; Related to Mass: no
PSet_Revit_Other - InstallationDate: InstallationDate; SerialNumber: SerialNumber; WarrantyStartDate: WarrantyStartDate; BarCode: BarCode; AssetIdentifier: AssetIdentifier; TagNumber: TagNumber
PSet_Revit_Phasing - Phase Created: New Construction
PSet_Revit_Structural - Structural Usage: 0
PSet_Revit_Type_Construction - Wrapping at Inserts: 0; Wrapping at Ends: 2; Width: 0.124 m; Function: 0
PSet_Revit_Type_Graphics - Coarse Scale Fill Color: 0
PSet_Revit_Type_Identity Data - Manufacturer: Manufacturer
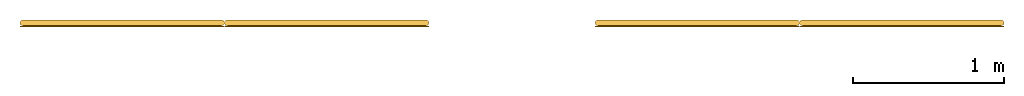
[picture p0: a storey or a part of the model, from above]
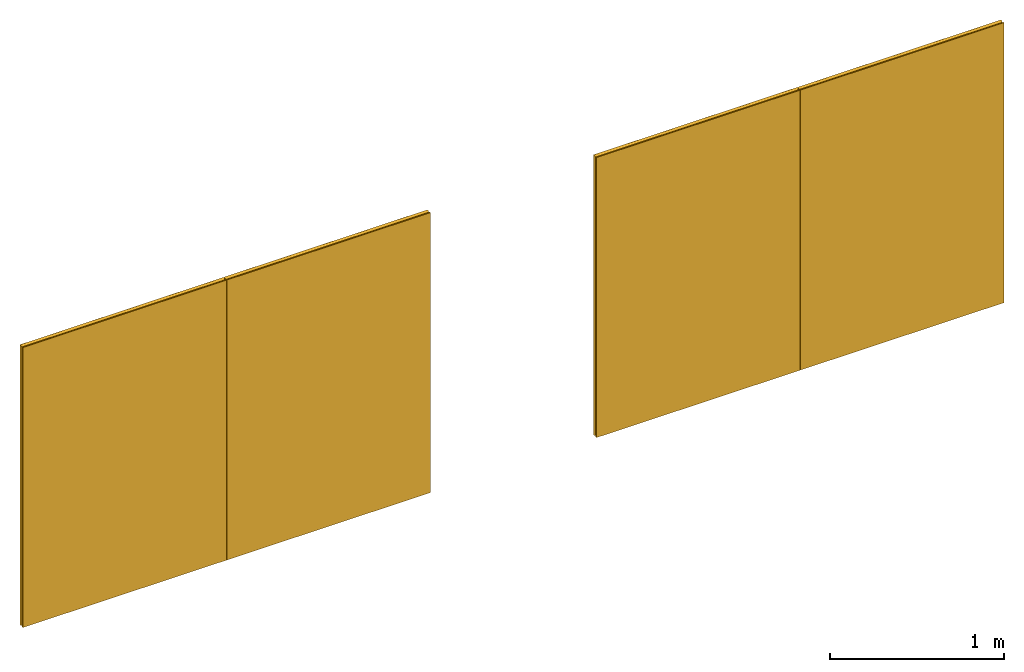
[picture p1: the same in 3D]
Properties of the parts of a building model (IFC2X3), part 10 of 11

# IfcWallStandardCase: Basic Wall:Interior - Partition (92mm Stud):128360 (460)
PSet_Revit_Type_Other - AccessibilityPerformance: AccessibilityPerformance; CodePerformance: CodePerformance; Color: Color; Constituents: Constituents; Features: Features; Finish: Finish; Grade: Grade; Material: Material; ModelReference: ModelReference; NominalHeight: NominalHeight; NominalLength: NominalLength; NominalWidth: NominalWidth; ProductionYear: ProductionYear; Reference: Reference; Shape: Shape; Size: Size; SustainabilityPerformance: SustainabilityPerformance; WarrantyDescription: WarrantyDescription; WarrantyDurationLabor: WarrantyDurationLabor; WarrantyDurationParts: WarrantyDurationParts; WarrantyGuarantorLabor: WarrantyGuarantorLabor; WarrantyGuarantorParts: WarrantyGuarantorParts; ExpectedLife: ExpectedLife; ReplacementCost: ReplacementCost; AssetAccountingType: FIXED; Classification Code: 23-25 40 11 11 11; Classification Description: Metal-Framed Gypsum Board Fixed Partitions; ModelLabel: ModelLabel
Name (Basic Wall:Interior - Partition (92mm Stud):...) | In | Location Line | Base Constraint | Base Offset (m) | Top Constraint | Unconnected Height (m) | Top Offset (m) | Length (m) | Area (m2) | Volume (m3)
146535 | First Floor | 2 | First Floor | 0 | Up to level: Second Floor | 4.468 | -0.102 | 3.1845 | 13.3549 | 1.656
146611 | First Floor | 2 | First Floor | 0 | Up to level: Second Floor | 4.468 | -0.102 | 3.1845 | 13.3549 | 1.656
146700 | First Floor | 2 | First Floor | 0 | Up to level: Second Floor | 4.468 | -0.102 | 3.1845 | 13.3549 | 1.656
148401 | First Floor | 2 | First Floor | 0 | Up to level: Second Floor | 4.468 | -0.102 | 3.3795 | 14.7801 | 1.83274
149246 | First Floor | 2 | First Floor | 0 | Up to level: Second Floor | 4.468 | -0.102 | 4.33 | 18.7924 | 2.33026
149397 | First Floor | 2 | First Floor | 0 | Up to level: Second Floor | 4.468 | -0.102 | 5.969 | 26.5489 | 3.29206
151435 | First Floor | 2 | First Floor | 0 | Up to level: Second Floor | 4.468 | -0.102 | 1.685 | 7.68496 | 0.952935
151682 | First Floor | 2 | First Floor | 0 | Up to level: Second Floor | 4.468 | -0.102 | 4.016 | 17.3895 | 2.15629
151971 | First Floor | 2 | First Floor | 0 | Up to level: Second Floor | 4.468 | -0.102 | 2.0379 | 8.78588 | 1.08945
152411 | First Floor | 2 | First Floor | 0 | Up to level: Second Floor | 4.468 | -0.102 | 3.6345 | 15.3655 | 1.90532
152982 | First Floor | 2 | First Floor | 0 | Up to level: Second Floor | 4.468 | -0.102 | 2.666 | 12.4657 | 1.54575
153012 | First Floor | 2 | First Floor | 0 | Up to level: Second Floor | 4.468 | -0.102 | 0.41 | 1.6755 | 0.207762
153048 | First Floor | 2 | First Floor | 0 | Up to level: Second Floor | 4.468 | -0.102 | 0.654728 | 2.37959 | 0.294024
153264 | First Floor | 2 | First Floor | 0 | Up to level: Second Floor | 4.468 | -0.102 | 1.406 | 6.77796 | 0.840467
154235 | First Floor | 2 | First Floor | 0 | Up to level: Second Floor | 4.468 | -0.102 | 1.99 | 8.89132 | 1.10252
154324 | First Floor | 2 | First Floor | 0 | Up to level: Second Floor | 4.468 | -0.102 | 2.745 | 11.5542 | 1.39659
155047 | First Floor | 2 | First Floor | 0 | Up to level: Second Floor | 4.468 | -0.102 | 4.046 | 18.0775 | 2.24161
155123 | First Floor | 2 | First Floor | 0 | Up to level: Second Floor | 4.468 | -0.102 | 3.47 | 15.1063 | 1.87318
155624 | First Floor | 2 | First Floor | 0 | Up to level: Second Floor | 4.468 | -0.102 | 4.046 | 17.5235 | 2.17291
155724 | First Floor | 2 | First Floor | 0 | Up to level: Second Floor | 4.468 | -0.102 | 4.046 | 17.5235 | 2.17291
155873 | First Floor | 2 | First Floor | 0 | Up to level: Second Floor | 4.468 | -0.102 | 1.06 | 4.89246 | 0.606665
155961 | First Floor | 2 | First Floor | 0 | Up to level: Second Floor | 4.468 | -0.102 | 4.046 | 17.5235 | 2.17291
156253 | First Floor | 2 | First Floor | 0 | Up to level: Second Floor | 4.468 | -0.102 | 3.855 | 17.5012 | 2.17014
156280 | First Floor | 2 | First Floor | 0 | Up to level: Second Floor | 4.468 | -0.102 | 0.474001 | 1.5638 | 0.193912
156311 | First Floor | 2 | First Floor | 0 | Up to level: Second Floor | 4.468 | -0.102 | 0.225 | 1.55933 | 0.193357
156859 | First Floor | 2 | First Floor | 0 | Up to level: Second Floor | 4.468 | -0.102 | 1.27132 | 5.73581 | 0.704929
156940 | First Floor | 2 | First Floor | 0 | Up to level: Second Floor | 4.468 | -0.102 | 3.87377 | 17.308 | 2.14619
157022 | First Floor | 2 | First Floor | 0 | Up to level: Second Floor | 4.468 | -0.102 | 1.13413 | 4.83655 | 0.593421
157155 | First Floor | 2 | First Floor | 0 | Up to level: Second Floor | 4.468 | -0.102 | 7.12229 | 31.961 | 3.94418
157922 | First Floor | 2 | First Floor | 0 | Up to level: Second Floor | 4.468 | -0.102 | 4.04645 | 17.5255 | 2.17316
157956 | First Floor | 2 | First Floor | 0 | Up to level: Second Floor | 4.468 | -0.102 | 1.09 | 4.87012 | 0.603895
158257 | First Floor | 2 | First Floor | 0 | Up to level: Second Floor | 4.468 | -0.102 | 12.017 | 54.0896 | 6.70711
158321 | First Floor | 2 | First Floor | 0 | Up to level: Second Floor | 4.468 | -0.102 | 0.520952 | 2.0506 | 0.254274
158879 | First Floor | 2 | First Floor | 0 | Up to level: Second Floor | 4.468 | -0.102 | 2.581 | 11.3755 | 1.41057
158994 | First Floor | 2 | First Floor | 0 | Up to level: Second Floor | 4.468 | -0.102 | 0.5545 | 2.20049 | 0.272861
159338 | First Floor | 2 | First Floor | 0 | Up to level: Second Floor | 4.468 | -0.102 | 1.552 | 6.77796 | 0.840467
159731 | First Floor | 2 | First Floor | 0 | Up to level: Second Floor | 4.468 | -0.102 | 5.7654 | 25.8581 | 3.2064
159791 | First Floor | 2 | First Floor | 0 | Up to level: Second Floor | 4.468 | -0.102 | 1.6828 | 7.36237 | 0.912934
159977 | First Floor | 2 | First Floor | 0 | Up to level: Second Floor | 4.468 | -0.102 | 0.942 | 4.2446 | 0.52633
160155 | First Floor | 2 | First Floor | 0 | Up to level: Second Floor | 4.468 | -0.102 | 8.8985 | 38.885 | 4.82174
160242 | First Floor | 2 | First Floor | 0 | Up to level: Second Floor | 4.468 | -0.102 | 3.561 | 15.2001 | 1.88482
160527 | First Floor | 2 | First Floor | 0 | Up to level: Second Floor | 4.468 | -0.102 | 3.355 | 14.2797 | 1.77069
160673 | First Floor | 2 | First Floor | 0 | Up to level: Second Floor | 4.468 | -0.102 | 3.355 | 14.8338 | 1.83939
161054 | First Floor | 2 | First Floor | 0 | Up to level: Second Floor | 4.468 | -0.102 | 4.04645 | 17.5255 | 2.17316
161156 | First Floor | 2 | First Floor | 0 | Up to level: Second Floor | 4.468 | -0.102 | 3.675 | 16.0222 | 1.98676
161602 | First Floor | 2 | First Floor | 0 | Up to level: Second Floor | 4.468 | -0.102 | 0.54 | 2.41272 | 0.299177
161658 | First Floor | 2 | First Floor | 0 | Up to level: Second Floor | 4.468 | -0.102 | 3.174 | 12.0934 | 1.49958
161701 | First Floor | 2 | First Floor | 0 | Up to level: Second Floor | 4.468 | -0.102 | 0.54 | 2.41272 | 0.299177
162361 | First Floor | 2 | First Floor | 0 | Up to level: Second Floor | 4.468 | -0.102 | 8.8985 | 38.885 | 4.82174
162455 | First Floor | 2 | First Floor | 0 | Up to level: Second Floor | 4.468 | -0.102 | 3.147 | 13.9044 | 1.72415
162700 | First Floor | 2 | First Floor | 0 | Up to level: Second Floor | 4.468 | -0.102 | 2.756 | 12.3138 | 1.52691
162757 | First Floor | 2 | First Floor | 0 | Up to level: Second Floor | 4.468 | -0.102 | 6.026 | 26.3701 | 3.2699
162882 | First Floor | 2 | First Floor | 0 | Up to level: Second Floor | 4.468 | -0.102 | 2.756 | 11.7598 | 1.45821
163139 | First Floor | 2 | First Floor | 0 | Up to level: Second Floor | 4.468 | -0.102 | 4.494 | 19.8379 | 2.4599
163280 | First Floor | 2 | First Floor | 0 | Up to level: Second Floor | 4.468 | -0.102 | 5.934 | 26.2718 | 3.25771
163518 | First Floor | 2 | First Floor | 0 | Up to level: Second Floor | 4.468 | -0.102 | 4.529 | 20.392 | 2.5286
163889 | First Floor | 2 | First Floor | 0 | Up to level: Second Floor | 4.468 | -0.102 | 6.257 | 27.9563 | 3.46658
164042 | First Floor | 2 | First Floor | 0 | Up to level: Second Floor | 4.468 | -0.102 | 4.0145 | 17.0633 | 2.11585
164520 | First Floor | 2 | First Floor | 0 | Up to level: Second Floor | 4.468 | -0.102 | 6.546 | 28.6935 | 3.55799
165137 | First Floor | 2 | First Floor | 0 | Up to level: Second Floor | 4.468 | -0.102 | 4.466 | 19.9541 | 2.47431
166480 | First Floor | 2 | First Floor | 0 | Up to level: Second Floor | 4.468 | -0.102 | 3.014 | 12.8142 | 1.58896
167070 | First Floor | 2 | First Floor | 0 | Up to level: Second Floor | 4.468 | -0.102 | 1.09 | 4.87012 | 0.603895
167115 | First Floor | 2 | First Floor | 0 | Up to level: Second Floor | 4.468 | -0.102 | 2.04 | 8.56069 | 1.06153
167177 | First Floor | 2 | First Floor | 0 | Up to level: Second Floor | 4.468 | -0.102 | 2.006 | 8.40878 | 1.04269
167282 | First Floor | 2 | First Floor | 0 | Up to level: Second Floor | 4.468 | -0.102 | 4.046 | 17.5235 | 2.17291
167574 | First Floor | 2 | First Floor | 0 | Up to level: Second Floor | 4.468 | -0.102 | 3.675 | 16.2635 | 2.01668
167959 | First Floor | 2 | First Floor | 0 | Up to level: Second Floor | 4.468 | -0.102 | 0.195 | 1.02764 | 0.127427
168175 | First Floor | 2 | First Floor | 0 | Up to level: Second Floor | 4.468 | -0.102 | 4.046 | 17.5235 | 2.17291
168358 | First Floor | 2 | First Floor | 0 | Up to level: Second Floor | 4.468 | -0.102 | 4.046 | 17.5235 | 2.17291
168439 | First Floor | 2 | First Floor | 0 | Up to level: Second Floor | 4.468 | -0.102 | 4.046 | 17.5235 | 2.17291
168555 | First Floor | 2 | First Floor | 0 | Up to level: Second Floor | 4.468 | -0.102 | 4.046 | 17.5235 | 2.17291
168647 | First Floor | 2 | First Floor | 0 | Up to level: Second Floor | 4.468 | -0.102 | 4.046 | 17.5235 | 2.17291
168819 | First Floor | 2 | First Floor | 0 | Up to level: Second Floor | 4.468 | -0.102 | 5.974 | 26.4506 | 3.27987
169076 | First Floor | 2 | First Floor | 0 | Up to level: Second Floor | 4.468 | -0.102 | 6.704 | 29.7122 | 3.68431
169411 | First Floor | 2 | First Floor | 0 | Up to level: Second Floor | 4.468 | -0.102 | 4.905 | 21.5179 | 2.66822
169827 | First Floor | 2 | First Floor | 0 | Up to level: Second Floor | 4.468 | -0.102 | 6.58 | 28.8454 | 3.57683
169940 | First Floor | 2 | First Floor | 0 | Up to level: Second Floor | 4.468 | -0.102 | 3.846 | 16.6299 | 2.06211
170379 | First Floor | 2 | First Floor | 0 | Up to level: Second Floor | 4.468 | -0.102 | 3.28 | 14.101 | 1.74852
170601 | First Floor | 2 | First Floor | 0 | Up to level: Second Floor | 4.468 | -0.102 | 6.58 | 28.8454 | 3.57683
170711 | First Floor | 2 | First Floor | 0 | Up to level: Second Floor | 4.468 | -0.102 | 2.99 | 12.8053 | 1.58786
170877 | First Floor | 2 | First Floor | 0 | Up to level: Second Floor | 4.468 | -0.102 | 2.956 | 12.6534 | 1.56902
170968 | First Floor | 2 | First Floor | 0 | Up to level: Second Floor | 4.468 | -0.102 | 2.956 | 12.6534 | 1.56902
171989 | First Floor | 2 | First Floor | 0 | Up to level: Second Floor | 4.468 | -0.102 | 3.502 | 14.9946 | 1.85933
172725 | First Floor | 2 | First Floor | 0 | Up to level: Second Floor | 4.468 | -0.102 | 1.026 | 4.58417 | 0.568437
172783 | First Floor | 2 | First Floor | 0 | Up to level: Second Floor | 4.468 | -0.102 | 1.985 | 8.86898 | 1.09975
172821 | First Floor | 2 | First Floor | 0 | Up to level: Second Floor | 4.468 | -0.102 | 2.529 | 10.9019 | 1.35184
172871 | First Floor | 2 | First Floor | 0 | Up to level: Second Floor | 4.468 | -0.102 | 1.026 | 4.03014 | 0.499737
173265 | First Floor | 2 | First Floor | 0 | Up to level: Second Floor | 4.468 | -0.102 | 8.954 | 39.7652 | 4.93088
173576 | First Floor | 2 | First Floor | 0 | Up to level: Second Floor | 4.468 | -0.102 | 2.715 | 11.733 | 1.45489
173607 | First Floor | 2 | First Floor | 0 | Up to level: Second Floor | 4.468 | -0.102 | 0.474 | 1.5638 | 0.193911
173634 | First Floor | 2 | First Floor | 0 | Up to level: Second Floor | 4.468 | -0.102 | 0.1975 | 0.88243 | 0.109421
173752 | First Floor | 2 | First Floor | 0 | Up to level: Second Floor | 4.468 | -0.102 | 3.086 | 13.2342 | 1.64104
174069 | First Floor | 2 | First Floor | 0 | Up to level: Second Floor | 4.468 | -0.102 | 3.086 | 13.2342 | 1.64104
174172 | First Floor | 2 | First Floor | 0 | Up to level: Second Floor | 4.468 | -0.102 | 3.2245 | 14.0876 | 1.74686
174331 | First Floor | 2 | First Floor | 0 | Up to level: Second Floor | 4.468 | -0.102 | 3.2245 | 13.5336 | 1.67816
175856 | First Floor | 2 | First Floor | 0 | Up to level: Second Floor | 4.468 | -0.102 | 0.175025 | 1.12653 | 0.139689
176115 | First Floor | 2 | First Floor | 0 | Up to level: Second Floor | 4.468 | -0.102 | 0.965001 | 4.15524 | 0.51525
176216 | First Floor | 2 | First Floor | 0 | Up to level: Second Floor | 4.468 | -0.102 | 2.368 | 10.6785 | 1.32414
176445 | First Floor | 2 | First Floor | 0 | Up to level: Second Floor | 4.468 | -0.102 | 2.636 | 11.7776 | 1.46043
177029 | First Floor | 2 | First Floor | 0 | Up to level: Second Floor | 4.468 | -0.102 | 2.17947 | 9.26205 | 1.14849
177861 | First Floor | 2 | First Floor | 0 | Up to level: Second Floor | 4.468 | -0.102 | 1.69497 | 7.1755 | 0.889762
178162 | First Floor | 2 | First Floor | 0 | Up to level: Second Floor | 4.468 | -0.102 | 0.44 | 1.41189 | 0.175074
178188 | First Floor | 2 | First Floor | 0 | Up to level: Second Floor | 4.468 | -0.102 | 0.1975 | 0.88243 | 0.109421
178246 | First Floor | 2 | First Floor | 0 | Up to level: Second Floor | 4.468 | -0.102 | 3.786 | 16.3618 | 2.02887
178357 | First Floor | 2 | First Floor | 0 | Up to level: Second Floor | 4.468 | -0.102 | 3.786 | 16.3618 | 2.02887
178495 | First Floor | 2 | First Floor | 0 | Up to level: Second Floor | 4.468 | -0.102 | 0.259878 | 1.28177 | 0.158939
178785 | First Floor | 2 | First Floor | 0 | Up to level: Second Floor | 4.468 | -0.102 | 0.09887 | 0.509251 | 0.0631471
178836 | First Floor | 2 | First Floor | 0 | Up to level: Second Floor | 4.468 | -0.102 | 1.80628 | 8.12358 | 1.00732
179554 | First Floor | 2 | First Floor | 0 | Up to level: Second Floor | 4.468 | -0.102 | 7.52 | 33.5994 | 4.16632
179768 | First Floor | 2 | First Floor | 0 | Up to level: Second Floor | 4.468 | -0.102 | 4.2745 | 18.779 | 2.3286
180081 | First Floor | 2 | First Floor | 0 | Up to level: Second Floor | 4.468 | -0.102 | 3.882 | 16.6924 | 2.06986
180133 | First Floor | 2 | First Floor | 0 | Up to level: Second Floor | 4.468 | -0.102 | 3.882 | 16.6924 | 2.06986
180570 | First Floor | 2 | First Floor | 0 | Up to level: Second Floor | 4.468 | -0.102 | 2.502 | 10.5266 | 1.3053
180854 | First Floor | 2 | First Floor | 0 | Up to level: Second Floor | 4.468 | -0.102 | 2.736 | 12.2244 | 1.51583
180953 | First Floor | 2 | First Floor | 0 | Up to level: Second Floor | 4.468 | -0.102 | 2.736 | 11.6704 | 1.41099
181483 | First Floor | 2 | First Floor | 0 | Up to level: Second Floor | 4.468 | -0.102 | 2.9245 | 12.1932 | 1.51195
181546 | First Floor | 2 | First Floor | 0 | Up to level: Second Floor | 4.468 | -0.102 | 2.9245 | 12.1932 | 1.51195
181696 | First Floor | 2 | First Floor | 0 | Up to level: Second Floor | 4.468 | -0.102 | 0.4765 | 1.53252 | 0.190033
181834 | First Floor | 2 | First Floor | 0 | Up to level: Second Floor | 4.468 | -0.102 | 4.756 | 20.6958 | 2.56628
182084 | First Floor | 2 | First Floor | 0 | Up to level: Second Floor | 4.468 | -0.102 | 8.41603 | 38.1568 | 4.73145
182216 | First Floor | 2 | First Floor | 0 | Up to level: Second Floor | 4.468 | -0.102 | 2.37 | 10.0351 | 1.24436
182288 | First Floor | 2 | First Floor | 0 | Up to level: Second Floor | 4.468 | -0.102 | 2.37 | 10.0351 | 1.24436
182526 | First Floor | 2 | First Floor | 0 | Up to level: Second Floor | 4.468 | -0.102 | 11.1934 | 49.4581 | 6.1328
183351 | First Floor | 2 | First Floor | 0 | Up to level: Second Floor | 4.468 | -0.102 | 6.04603 | 26.4596 | 3.28099
183428 | First Floor | 2 | First Floor | 0 | Up to level: Second Floor | 4.468 | -0.102 | 1.2596 | 6.01964 | 0.712086
183461 | First Floor | 2 | First Floor | 0 | Up to level: Second Floor | 4.468 | -0.102 | 0.938196 | 4.74589 | 0.519791
183511 | First Floor | 2 | First Floor | 0 | Up to level: Second Floor | 4.468 | -0.102 | 0.314561 | 1.29071 | 0.125699
183690 | First Floor | 2 | First Floor | 0 | Up to level: Second Floor | 4.468 | -0.102 | 2.416 | 10.7947 | 1.33854
183948 | First Floor | 2 | First Floor | 0 | Up to level: Second Floor | 4.468 | -0.102 | 2.416 | 10.7947 | 1.33854
184036 | First Floor | 2 | First Floor | 0 | Up to level: Second Floor | 4.468 | -0.102 | 2.416 | 10.2407 | 1.26984
184898 | First Floor | 2 | First Floor | 0 | Up to level: Second Floor | 4.468 | -0.102 | 0.6501 | 2.25232 | 0.279288
185755 | First Floor | 2 | First Floor | 0 | Up to level: Second Floor | 4.468 | -0.102 | 4.253 | 18.4484 | 2.2876
185917 | First Floor | 2 | First Floor | 0 | Up to level: Second Floor | 4.468 | -0.102 | 0.23 | 1.58167 | 0.196127
185954 | First Floor | 2 | First Floor | 0 | Up to level: Second Floor | 4.468 | -0.102 | 0.474 | 1.5638 | 0.193911
185975 | First Floor | 2 | First Floor | 0 | Up to level: Second Floor | 4.468 | -0.102 | 0.23 | 1.58167 | 0.196127
186038 | First Floor | 2 | First Floor | 0 | Up to level: Second Floor | 4.468 | -0.102 | 2.723 | 11.6123 | 1.43993
186316 | First Floor | 2 | First Floor | 0 | Up to level: Second Floor | 4.468 | -0.102 | 2.503 | 10.6294 | 1.31804
186334 | First Floor | 2 | First Floor | 0 | Up to level: Second Floor | 4.468 | -0.102 | 0.225 | 1.55933 | 0.193357
186369 | First Floor | 2 | First Floor | 0 | Up to level: Second Floor | 4.468 | -0.102 | 0.474 | 1.5638 | 0.193911
186390 | First Floor | 2 | First Floor | 0 | Up to level: Second Floor | 4.468 | -0.102 | 0.225 | 1.55933 | 0.193357
186460 | First Floor | 2 | First Floor | 0 | Up to level: Second Floor | 4.468 | -0.102 | 1.4615 | 5.65649 | 0.701405
186699 | First Floor | 2 | First Floor | 0 | Up to level: Second Floor | 4.468 | -0.102 | 3.4375 | 14.4853 | 1.79617
186803 | First Floor | 2 | First Floor | 0 | Up to level: Second Floor | 4.468 | -0.102 | 2.911 | 12.4523 | 1.54409
187435 | First Floor | 2 | First Floor | 0 | Up to level: Second Floor | 4.468 | -0.102 | 0.315001 | 1.96146 | 0.24322
187465 | First Floor | 2 | First Floor | 0 | Up to level: Second Floor | 4.468 | -0.102 | 0.523228 | 1.46429 | 0.181572
187622 | First Floor | 2 | First Floor | 0 | Up to level: Second Floor | 4.468 | -0.102 | 3.5891 | 15.1626 | 1.88016
187711 | First Floor | 2 | First Floor | 0 | Up to level: Second Floor | 4.468 | -0.102 | 3.5891 | 15.1626 | 1.88016
187793 | First Floor | 2 | First Floor | 0 | Up to level: Second Floor | 4.468 | -0.102 | 3.326 | 14.3065 | 1.77401
187906 | First Floor | 2 | First Floor | 0 | Up to level: Second Floor | 4.468 | -0.102 | 3.6606 | 15.8015 | 1.95939
188628 | First Floor | 2 | First Floor | 0 | Up to level: Second Floor | 4.468 | -0.102 | 1.015 | 4.258 | 0.527992
188883 | First Floor | 2 | First Floor | 0 | Up to level: Second Floor | 4.468 | -0.102 | 2.185 | 9.48556 | 1.17621
189500 | First Floor | 2 | First Floor | 0 | Up to level: Second Floor | 4.468 | -0.102 | 6.2185 | 26.9108 | 3.33693
189772 | First Floor | 2 | First Floor | 0 | Up to level: Second Floor | 4.468 | -0.102 | 3.0885 | 12.9259 | 1.60281
192010 | Second Floor | 2 | Second Floor | 0 | Up to level: Roof - Main | 4.578 | -0.102 | 3.5545 | 15.3775 | 1.90681
192107 | Second Floor | 2 | Second Floor | 0 | Up to level: Roof - Main | 4.578 | -0.102 | 3.105 | 13.8072 | 1.7121
192229 | Second Floor | 2 | Second Floor | 0 | Up to level: Roof - Main | 4.578 | -0.102 | 2.155 | 10.0258 | 1.2432
192284 | Second Floor | 2 | Second Floor | 0 | Up to level: Roof - Main | 4.578 | -0.102 | 0.66 | 3.02148 | 0.374664
192577 | Second Floor | 2 | Second Floor | 0 | Up to level: Roof - Main | 4.578 | -0.102 | 3.14 | 13.8072 | 1.7121
192662 | Second Floor | 2 | Second Floor | 0 | Up to level: Roof - Main | 4.578 | -0.102 | 3.105 | 13.8072 | 1.7121
192737 | Second Floor | 2 | Second Floor | 0 | Up to level: Roof - Main | 4.578 | -0.102 | 3.52006 | 15.2198 | 1.88726
192805 | Second Floor | 2 | Second Floor | 0 | Up to level: Roof - Main | 4.578 | -0.102 | 3.52006 | 15.2198 | 1.88726
192933 | Second Floor | 2 | Second Floor | 0 | Up to level: Roof - Main | 4.578 | -0.102 | 3.52006 | 15.2198 | 1.88726
193276 | Second Floor | 2 | Second Floor | 0 | Up to level: Roof - Main | 4.578 | -0.102 | 3.52006 | 15.2198 | 1.88726
193487 | Second Floor | 2 | Second Floor | 0 | Up to level: Roof - Main | 4.578 | -0.102 | 3.52006 | 15.2198 | 1.88726
193547 | Second Floor | 2 | Second Floor | 0 | Up to level: Roof - Main | 4.578 | -0.102 | 3.52006 | 15.2198 | 1.88726
193681 | Second Floor | 2 | Second Floor | 0 | Up to level: Roof - Main | 4.578 | -0.102 | 3.52006 | 15.2198 | 1.88726
193766 | Second Floor | 2 | Second Floor | 0 | Up to level: Roof - Main | 4.578 | -0.102 | 3.52006 | 15.2198 | 1.88726
194554 | Second Floor | 2 | Second Floor | 0 | Up to level: Roof - Main | 4.578 | -0.102 | 1.005 | 4.60089 | 0.57051
194626 | Second Floor | 2 | Second Floor | 0 | Up to level: Roof - Main | 4.578 | -0.102 | 0.933 | 3.98744 | 0.494442
194848 | Second Floor | 2 | Second Floor | 0 | Up to level: Roof - Main | 4.578 | -0.102 | 2.623 | 11.7243 | 1.45381
194886 | Second Floor | 2 | Second Floor | 0 | Up to level: Roof - Main | 4.578 | -0.102 | 0.225 | 1.59772 | 0.198117
194918 | Second Floor | 2 | Second Floor | 0 | Up to level: Roof - Main | 4.578 | -0.102 | 0.439 | 1.84951 | 0.229339
194995 | Second Floor | 2 | Second Floor | 0 | Up to level: Roof - Main | 4.578 | -0.102 | 1.035 | 5.14567 | 0.638063
195068 | Second Floor | 2 | Second Floor | 0 | Up to level: Roof - Main | 4.578 | -0.102 | 3.666 | 16.7829 | 2.08109
195163 | Second Floor | 2 | Second Floor | 0 | Up to level: Roof - Main | 4.578 | -0.102 | 5.816 | 26.6256 | 3.30158
195212 | Second Floor | 2 | Second Floor | 0 | Up to level: Roof - Main | 4.578 | -0.102 | 3.666 | 16.2153 | 2.01069
195392 | Second Floor | 2 | Second Floor | 0 | Up to level: Roof - Main | 4.578 | -0.102 | 0.728638 | 3.90337 | 0.413627
195440 | Second Floor | 2 | Second Floor | 0 | Up to level: Roof - Main | 4.578 | -0.102 | 0.900805 | 3.72248 | 0.426392
196851 | Second Floor | 2 | Second Floor | 0 | Up to level: Roof - Main | 4.578 | -0.102 | 4.04 | 18.2113 | 2.2582
197013 | Second Floor | 2 | Second Floor | 0 | Up to level: Roof - Main | 4.578 | -0.102 | 5.878 | 27.1933 | 3.37197
197057 | Second Floor | 2 | Second Floor | 0 | Up to level: Roof - Main | 4.578 | -0.102 | 0.6 | 2.7468 | 0.340603
198188 | Second Floor | 2 | Second Floor | 0 | Up to level: Roof - Main | 4.578 | -0.102 | 3.37317 | 13.87 | 1.71988
198367 | Second Floor | 2 | Second Floor | 0 | Up to level: Roof - Main | 4.578 | -0.102 | 1 | 4.578 | 0.567672
198442 | Second Floor | 2 | Second Floor | 0 | Up to level: Roof - Main | 4.578 | -0.102 | 7.475 | 33.8131 | 4.19283
198501 | Second Floor | 2 | Second Floor | 0 | Up to level: Roof - Main | 4.578 | -0.102 | 2.809 | 12.8596 | 1.59459
198638 | Second Floor | 2 | Second Floor | 0 | Up to level: Roof - Main | 4.578 | -0.102 | 5.08156 | 23.2634 | 2.88466
199438 | Second Floor | 2 | Second Floor | 0 | Up to level: Roof - Main | 4.578 | -0.102 | 1.75944 | 7.48704 | 0.928392
199825 | Second Floor | 2 | Second Floor | 0 | Up to level: Roof - Main | 4.578 | -0.102 | 2.36464 | 10.2576 | 1.23581
199929 | Second Floor | 2 | Second Floor | 0 | Up to level: Roof - Main | 4.578 | -0.102 | 1.43991 | 6.49893 | 0.805867
200839 | Second Floor | 2 | Second Floor | 0 | Up to level: Roof - Main | 4.578 | -0.102 | 0.27976 | 1.68818 | 0.209335
200901 | Second Floor | 2 | Second Floor | 0 | Up to level: Roof - Main | 4.578 | -0.102 | 1.37425 | 6.29132 | 0.780123
201121 | Second Floor | 2 | Second Floor | 0 | Up to level: Roof - Main | 4.578 | -0.102 | 0.30676 | 1.68818 | 0.209335
201161 | Second Floor | 2 | Second Floor | 0 | Up to level: Roof - Main | 4.578 | -0.102 | 1.37425 | 6.29132 | 0.780123
201190 | Second Floor | 2 | Second Floor | 0 | Up to level: Roof - Main | 4.578 | -0.102 | 0.30676 | 1.12051 | 0.138943
201997 | Second Floor | 2 | Second Floor | 0 | Up to level: Roof - Main | 4.578 | -0.102 | 3.87 | 17.3094 | 2.14637
202103 | Second Floor | 2 | Second Floor | 0 | Up to level: Roof - Main | 4.578 | -0.102 | 3.87 | 17.3094 | 2.14637
202661 | Second Floor | 2 | Second Floor | 0 | Up to level: Second Floor | 3 | 3 | 1.0443 | 3.1329 | 0.388479
203842 | Second Floor | 2 | Second Floor | 0.0284366 | Up to level: Second Floor | 2.077 | 2.10544 | 1.12556 | 2.20902 | 0.273919
204593 | Second Floor | 2 | Second Floor | 0 | Up to level: Roof - Main | 4.578 | -0.102 | 3.465 | 14.644 | 1.81586
204658 | Second Floor | 2 | Second Floor | 0 | Up to level: Roof - Main | 4.578 | -0.102 | 3.5 | 14.6178 | 1.8126
204720 | Second Floor | 2 | Second Floor | 0 | Up to level: Roof - Main | 4.578 | -0.102 | 3.5 | 14.6086 | 1.81146
205408 | Second Floor | 2 | Second Floor | 0 | Up to level: Roof - Main | 4.578 | -0.102 | 3.225 | 14.3566 | 1.78022
205858 | Second Floor | 2 | Second Floor | 0 | Up to level: Roof - Main | 4.578 | -0.102 | 3.6745 | 15.9269 | 1.97493
206118 | Second Floor | 2 | Second Floor | 0 | Up to level: Roof - Main | 4.578 | -0.102 | 3.6745 | 15.9269 | 1.97493
206466 | Second Floor | 2 | Second Floor | 0 | Up to level: Roof - Main | 4.578 | -0.102 | 0.5635 | 2.25238 | 0.244099
206508 | Second Floor | 2 | Second Floor | 0 | Up to level: Roof - Main | 4.578 | -0.102 | 0.138439 | 1.20144 | 0.113783
206781 | Second Floor | 2 | Second Floor | 0 | Up to level: Roof - Main | 4.578 | -0.102 | 2.44056 | 10.7654 | 1.33492
206989 | Second Floor | 2 | Second Floor | 0 | Up to level: Roof - Main | 4.578 | -0.102 | 2.44056 | 10.7654 | 1.33492
207218 | Second Floor | 2 | Second Floor | 0 | Up to level: Roof - Main | 4.578 | -0.102 | 2.9245 | 12.4934 | 1.54918
208108 | Second Floor | 2 | Second Floor | 0 | Up to level: Roof - Main | 4.578 | -0.102 | 6.156 | 27.6145 | 3.4242
208256 | Second Floor | 2 | Second Floor | 0 | Up to level: Roof - Main | 4.578 | -0.102 | 1.896 | 8.67989 | 1.07631
208377 | Second Floor | 2 | Second Floor | 0 | Up to level: Roof - Main | 4.578 | -0.102 | 3.855 | 17.8084 | 2.20824
208413 | Second Floor | 2 | Second Floor | 0 | Up to level: Roof - Main | 4.578 | -0.102 | 0.474 | 1.6023 | 0.198685
208435 | Second Floor | 2 | Second Floor | 0 | Up to level: Roof - Main | 4.578 | -0.102 | 0.225 | 1.59772 | 0.198118
209003 | Second Floor | 2 | Second Floor | 0 | Up to level: Roof - Main | 4.578 | -0.102 | 2.335 | 10.2822 | 1.27499
209049 | Second Floor | 2 | Second Floor | 0 | Up to level: Roof - Main | 4.578 | -0.102 | 1.82497 | 8.51497 | 1.05586
209118 | Second Floor | 2 | Second Floor | 0 | Up to level: Roof - Main | 4.578 | -0.102 | 4.256 | 18.9163 | 2.34562
209338 | Second Floor | 2 | Second Floor | 0 | Up to level: Roof - Main | 4.578 | -0.102 | 7.59 | 34.1793 | 4.23824
209489 | Second Floor | 2 | Second Floor | 0 | Up to level: Roof - Main | 4.578 | -0.102 | 4.77 | 21.2694 | 2.6374
209550 | Second Floor | 2 | Second Floor | 0 | Up to level: Roof - Main | 4.578 | -0.102 | 4.77 | 21.2694 | 2.6374
209581 | Second Floor | 2 | Second Floor | 0 | Up to level: Roof - Main | 4.578 | -0.102 | 3.926 | 17.4056 | 2.15829
209920 | Second Floor | 2 | Second Floor | 0 | Up to level: Roof - Main | 4.578 | -0.102 | 3.556 | 15.7117 | 1.94825
209992 | Second Floor | 2 | Second Floor | 0 | Up to level: Roof - Main | 4.578 | -0.102 | 3.556 | 15.7117 | 1.94825
210335 | Second Floor | 2 | Second Floor | 0 | Up to level: Roof - Main | 4.578 | -0.102 | 5.095 | 23.4851 | 2.91216
210761 | Second Floor | 2 | Second Floor | 0 | Up to level: Roof - Main | 4.578 | -0.102 | 3.84894 | 16.7254 | 2.07395
210789 | Second Floor | 2 | Second Floor | 0 | Up to level: Roof - Main | 4.578 | -0.102 | 0.474 | 1.6023 | 0.198685
210817 | Second Floor | 2 | Second Floor | 0 | Up to level: Roof - Main | 4.578 | -0.102 | 0.195 | 0.89271 | 0.110696
210953 | Second Floor | 2 | Second Floor | 0 | Up to level: Roof - Main | 4.578 | -0.102 | 3.84894 | 16.7254 | 2.07395
211192 | Second Floor | 2 | Second Floor | 0 | Up to level: Roof - Main | 4.578 | -0.102 | 3.3651 | 14.998 | 1.85975
211628 | Second Floor | 2 | Second Floor | 0 | Up to level: Roof - Main | 4.578 | -0.102 | 3.3651 | 14.998 | 1.85975
211765 | Second Floor | 2 | Second Floor | 0 | Up to level: Roof - Main | 4.578 | -0.102 | 3.3651 | 14.998 | 1.85975
211942 | Second Floor | 2 | Second Floor | 0 | Up to level: Roof - Main | 4.578 | -0.102 | 0.385939 | 1.15566 | 0.143302
212320 | Second Floor | 2 | Second Floor | 0 | Up to level: Roof - Main | 4.578 | -0.102 | 2.548 | 11.3809 | 1.37509
213032 | Second Floor | 2 | Second Floor | 0 | Up to level: Roof - Main | 4.578 | -0.102 | 13.7585 | 62.6591 | 7.76973
213098 | Second Floor | 2 | Second Floor | 0 | Up to level: Roof - Main | 4.578 | -0.102 | 6.544 | 29.7982 | 3.69498
213164 | Second Floor | 2 | Second Floor | 0 | Up to level: Roof - Main | 4.578 | -0.102 | 0.257 | 1.05294 | 0.130565
213843 | Second Floor | 2 | Second Floor | 0 | Up to level: Roof - Main | 4.578 | -0.102 | 3.209 | 15.0982 | 1.87218
214461 | Second Floor | 2 | Second Floor | 0 | Up to level: Roof - Main | 4.578 | -0.102 | 1.096 | 5.01749 | 0.622169
214891 | Second Floor | 2 | Second Floor | 0 | Up to level: Roof - Main | 4.578 | -0.102 | 13.8645 | 62.5767 | 7.75951
214958 | Second Floor | 2 | Second Floor | 0 | Up to level: Roof - Main | 4.578 | -0.102 | 2.629 | 11.6281 | 1.44189
215010 | Second Floor | 2 | Second Floor | 0 | Up to level: Roof - Main | 4.578 | -0.102 | 3.19 | 14.0361 | 1.74048
216242 | Second Floor | 2 | Second Floor | 0 | Up to level: Roof - Main | 4.578 | -0.102 | 6.086 | 27.294 | 3.38446
216262 | Second Floor | 2 | Second Floor | 0 | Up to level: Roof - Main | 4.578 | -0.102 | 0.23 | 1.62061 | 0.200956
216283 | Second Floor | 2 | Second Floor | 0 | Up to level: Roof - Main | 4.578 | -0.102 | 0.474 | 1.6023 | 0.198685
216300 | Second Floor | 2 | Second Floor | 0 | Up to level: Roof - Main | 4.578 | -0.102 | 0.23 | 1.62061 | 0.200956
216832 | Second Floor | 2 | Second Floor | 0 | Up to level: Roof - Main | 4.578 | -0.102 | 5.51 | 24.9409 | 3.09268
216946 | Second Floor | 2 | Second Floor | 0 | Up to level: Roof - Main | 4.578 | -0.102 | 1.528 | 6.71135 | 0.832207
217063 | Second Floor | 2 | Second Floor | 0 | Up to level: Roof - Main | 4.578 | -0.102 | 3 | 13.1663 | 1.63262
217124 | Second Floor | 2 | Second Floor | 0 | Up to level: Roof - Main | 4.578 | -0.102 | 7.156 | 32.1925 | 3.99187
217198 | Second Floor | 2 | Second Floor | 0 | Up to level: Roof - Main | 4.578 | -0.102 | 3.586 | 15.849 | 1.96528
217901 | Second Floor | 2 | Second Floor | 0 | Up to level: Roof - Main | 4.578 | -0.102 | 3.87389 | 17.167 | 2.12871
217949 | Second Floor | 2 | Second Floor | 0 | Up to level: Roof - Main | 4.578 | -0.102 | 0.9764 | 4.7538 | 0.589471
217991 | Second Floor | 2 | Second Floor | 0 | Up to level: Roof - Main | 4.578 | -0.102 | 1.069 | 5.03122 | 0.623872
218285 | Second Floor | 2 | Second Floor | 0 | Up to level: Roof - Main | 4.578 | -0.102 | 0.972 | 4.02864 | 0.499551
218539 | Second Floor | 2 | Second Floor | 0 | Up to level: Roof - Main | 4.578 | -0.102 | 4.46 | 19.8502 | 2.46143
218812 | Second Floor | 2 | Second Floor | 0 | Up to level: Roof - Main | 4.578 | -0.102 | 5.69064 | 26.1753 | 3.2096
218895 | Second Floor | 2 | Second Floor | 0 | Up to level: Roof - Main | 4.578 | -0.102 | 1.352 | 5.90562 | 0.732297
218987 | Second Floor | 2 | Second Floor | 0 | Up to level: Roof - Main | 4.578 | -0.102 | 1.556 | 7.12337 | 0.883298
219029 | Second Floor | 2 | Second Floor | 0 | Up to level: Roof - Main | 4.578 | -0.102 | 2.576 | 11.2253 | 1.39193
219089 | Second Floor | 2 | Second Floor | 0 | Up to level: Roof - Main | 4.578 | -0.102 | 3.45 | 15.2264 | 1.88808
220699 | First Floor | 2 | First Floor | 3.8 | Up to level: Second Floor | 3.77 | 3 | 6.42173 | 24.0239 | 2.97896
146380 | First Floor | 3 | First Floor | 0 | Up to level: Second Floor | 4.468 | -0.102 | 11.6715 | 45.971 | 5.7004
147026 | First Floor | 3 | First Floor | 0 | Up to level: Second Floor | 4.468 | -0.102 | 2.2195 | 7.09062 | 0.843098
147363 | First Floor | 2 | First Floor | 0 | Up to level: Second Floor | 4.468 | -0.102 | 2.799 | 10.3969 | 1.28922
151575 | First Floor | 2 | First Floor | 0 | Up to level: Second Floor | 4.468 | -0.102 | 6.4645 | 24.1047 | 2.98898
152109 | First Floor | 2 | First Floor | 0 | Up to level: Second Floor | 4.468 | -0.102 | 4.4266 | 17.8254 | 2.21035
152188 | First Floor | 2 | First Floor | 0 | Up to level: Second Floor | 4.468 | -0.102 | 3.185 | 11.8803 | 1.47316
152014 | First Floor | 2 | First Floor | 0 | Up to level: Second Floor | 4.468 | -0.102 | 2.65 | 9.33356 | 1.15736
152889 | First Floor | 2 | First Floor | 0 | Up to level: Second Floor | 4.468 | -0.102 | 1.782 | 5.61171 | 0.695853
172351 | First Floor | 2 | First Floor | 0 | Up to level: Second Floor | 4.468 | -0.102 | 7.326 | 30.78 | 3.78058
172683 | First Floor | 2 | First Floor | 0 | Up to level: Second Floor | 4.468 | -0.102 | 6.2845 | 23.3004 | 2.88925
174245 | First Floor | 2 | First Floor | 0 | Up to level: Second Floor | 4.468 | -0.102 | 5.9245 | 21.692 | 2.6898
173558 | First Floor | 2 | First Floor | 0 | Up to level: Second Floor | 4.468 | -0.102 | 8.6845 | 32.6251 | 4.04551
174960 | First Floor | 2 | First Floor | 0 | Up to level: Second Floor | 4.468 | -0.102 | 7.3235 | 30.0517 | 3.72641
176488 | First Floor | 2 | First Floor | 0 | Up to level: Second Floor | 4.468 | -0.102 | 2.425 | 8.48464 | 1.0521
175951 | First Floor | 2 | First Floor | 0 | Up to level: Second Floor | 4.468 | -0.102 | 7.074 | 28.9481 | 3.58956
171321 | First Floor | 2 | First Floor | 0 | Up to level: Second Floor | 4.468 | -0.102 | 7.7585 | 28.0029 | 3.47236
176083 | First Floor | 2 | First Floor | 0 | Up to level: Second Floor | 4.57 | 0 | 6.945 | 27.9934 | 3.43504
153789 | First Floor | 2 | First Floor | 0 | Up to level: Second Floor | 4.468 | -0.102 | 3.794 | 14.6237 | 1.81334
224851 | First Floor | 2 | First Floor | 0 | Up to level: Second Floor | 4.468 | -0.102 | 1.834 | 5.68767 | 0.705271
154875 | First Floor | 2 | First Floor | 0 | Up to level: Second Floor | 4.468 | -0.102 | 5.715 | 21.2317 | 2.63274
160919 | First Floor | 2 | First Floor | 0 | Up to level: Second Floor | 4.468 | -0.102 | 4.045 | 15.7228 | 1.94963
156128 | First Floor | 2 | First Floor | 0 | Up to level: Second Floor | 4.468 | -0.102 | 12.206 | 46.726 | 5.79402
158808 | First Floor | 2 | First Floor | 0 | Up to level: Second Floor | 4.468 | -0.102 | 4.04645 | 15.5729 | 1.93104
157843 | First Floor | 2 | First Floor | 0 | Up to level: Second Floor | 4.468 | -0.102 | 12.344 | 49.2952 | 6.07646
159174 | First Floor | 2 | First Floor | 0 | Up to level: Second Floor | 4.468 | -0.102 | 1.817 | 5.61171 | 0.695853
147540 | First Floor | 2 | First Floor | 0 | Up to level: Second Floor | 4.468 | -0.102 | 6.117 | 23.4255 | 2.90477
148548 | First Floor | 2 | First Floor | 0 | Up to level: Second Floor | 4.468 | -0.102 | 4.529 | 18.1623 | 2.25213
148449 | First Floor | 2 | First Floor | 0 | Up to level: Second Floor | 4.468 | -0.102 | 2.966 | 10.7454 | 1.33244
148027 | First Floor | 2 | First Floor | 0 | Up to level: Second Floor | 4.468 | -0.102 | 5.934 | 24.6811 | 3.06046
161485 | First Floor | 2 | First Floor | 0 | Up to level: Second Floor | 4.468 | -0.102 | 1.56 | 5.01747 | 0.622166
161575 | First Floor | 2 | First Floor | 0 | Up to level: Second Floor | 4.468 | -0.102 | 1.56 | 5.01747 | 0.622166
161970 | First Floor | 2 | First Floor | 0 | Up to level: Second Floor | 4.468 | -0.102 | 4.494 | 18.1266 | 2.2477
166897 | First Floor | 2 | First Floor | 0 | Up to level: Second Floor | 4.468 | -0.102 | 4.046 | 15.5709 | 1.93079
167763 | First Floor | 2 | First Floor | 0 | Up to level: Second Floor | 4.468 | -0.102 | 6.704 | 28.1215 | 3.48707
164924 | First Floor | 2 | First Floor | 0 | Up to level: Second Floor | 4.468 | -0.102 | 18.395 | 72.0282 | 8.93149
165494 | First Floor | 2 | First Floor | 0 | Up to level: Second Floor | 4.468 | -0.102 | 3.794 | 15.3743 | 1.90641
228493 | First Floor | 2 | First Floor | 0 | Up to level: Second Floor | 4.468 | -0.102 | 1.834 | 5.68767 | 0.705271
178094 | First Floor | 2 | First Floor | 0 | Up to level: Second Floor | 4.468 | -0.102 | 5.126 | 18.9977 | 2.35572
228833 | First Floor | 2 | First Floor | 0 | Up to level: Second Floor | 4.468 | -0.102 | 1.834 | 5.68767 | 0.705271
177813 | First Floor | 2 | First Floor | 0 | Up to level: Second Floor | 4.468 | -0.102 | 4.07 | 15.6781 | 1.94409
177773 | First Floor | 2 | First Floor | 0 | Up to level: Second Floor | 4.468 | -0.102 | 1.834 | 6.2417 | 0.773971
179359 | First Floor | 2 | First Floor | 0 | Up to level: Second Floor | 4.468 | -0.102 | 8.285 | 32.9558 | 4.08652
180522 | First Floor | 2 | First Floor | 0 | Up to level: Second Floor | 4.468 | -0.102 | 1.994 | 6.40255 | 0.793916
179634 | First Floor | 2 | First Floor | 0 | Up to level: Second Floor | 4.468 | -0.102 | 2.714 | 10.2718 | 1.23757
179860 | First Floor | 2 | First Floor | 0 | Up to level: Second Floor | 4.468 | -0.102 | 7.76447 | 27.9604 | 3.46708
179701 | First Floor | 2 | First Floor | 0 | Up to level: Second Floor | 4.468 | -0.102 | 1.834 | 5.68767 | 0.705271
181936 | First Floor | 2 | First Floor | 0 | Up to level: Second Floor | 4.468 | -0.102 | 1.834 | 5.50628 | 0.682779
183218 | First Floor | 2 | First Floor | 0 | Up to level: Second Floor | 4.468 | -0.102 | 13.625 | 52.2588 | 6.48009
182173 | First Floor | 2 | First Floor | 0 | Up to level: Second Floor | 4.468 | -0.102 | 8.30603 | 33.2061 | 4.11756
188823 | First Floor | 2 | First Floor | 0 | Up to level: Second Floor | 4.468 | -0.102 | 4.253 | 17.0498 | 2.11417
231160 | First Floor | 2 | First Floor | 0 | Up to level: Second Floor | 4.468 | -0.102 | 1.817 | 5.61171 | 0.695853
185166 | First Floor | 2 | First Floor | 0 | Up to level: Second Floor | 4.468 | -0.102 | 7.2149 | 29.9641 | 3.71555
185345 | First Floor | 2 | First Floor | 0 | Up to level: Second Floor | 4.468 | -0.102 | 4.253 | 16.4958 | 2.04547
189690 | First Floor | 2 | First Floor | 0 | Up to level: Second Floor | 4.468 | -0.102 | 6.2985 | 23.363 | 2.89701
188486 | First Floor | 2 | First Floor | 0 | Up to level: Second Floor | 4.468 | -0.102 | 9.94827 | 41.9422 | 5.20084
186167 | First Floor | 2 | First Floor | 0 | Up to level: Second Floor | 4.468 | -0.102 | 17.696 | 77.6672 | 9.63073
231922 | First Floor | 2 | First Floor | 0 | Up to level: Second Floor | 4.468 | -0.102 | 2.924 | 10.5578 | 1.27303
164812 | First Floor | 2 | First Floor | 0 | Up to level: Second Floor | 4.468 | -0.102 | 10.626 | 45.5244 | 5.64502
162146 | First Floor | 2 | First Floor | 0 | Up to level: Second Floor | 4.468 | -0.102 | 16.135 | 66.3897 | 8.23233
170283 | First Floor | 2 | First Floor | 0 | Up to level: Second Floor | 4.468 | -0.102 | 6.58 | 24.9402 | 3.09258
164694 | First Floor | 2 | First Floor | 0 | Up to level: Second Floor | 4.468 | -0.102 | 18.766 | 71.7699 | 8.89946
232773 | First Floor | 2 | First Floor | 0 | Up to level: Second Floor | 4.468 | -0.102 | 1.834 | 5.68767 | 0.705271
164156 | First Floor | 2 | First Floor | 0 | Up to level: Second Floor | 4.468 | -0.102 | 10.6905 | 44.9391 | 5.57244
185718 | First Floor | 2 | First Floor | 0 | Up to level: Second Floor | 4.468 | -0.102 | 7.1605 | 27.7684 | 3.44329
185879 | First Floor | 2 | First Floor | 0 | Up to level: Second Floor | 4.468 | -0.102 | 7.2745 | 29.6764 | 3.67987
165239 | First Floor | 2 | First Floor | 0 | Up to level: Second Floor | 4.468 | -0.102 | 1.635 | 5.75022 | 0.713028
234058 | First Floor | 2 | First Floor | 0 | Up to level: Second Floor | 4.468 | -0.102 | 1.834 | 5.68767 | 0.705271
191720 | Second Floor | 2 | Second Floor | 0 | Up to level: Roof - Main | 4.578 | -0.102 | 1.488 | 4.57562 | 0.567377
192339 | Second Floor | 2 | Second Floor | 0 | Up to level: Roof - Main | 4.578 | -0.102 | 2.784 | 10.7925 | 1.33828
216351 | Second Floor | 2 | Second Floor | 0 | Up to level: Roof - Main | 4.578 | -0.102 | 1.8 | 5.72012 | 0.709295
216568 | Second Floor | 2 | Second Floor | 0 | Up to level: Roof - Main | 4.578 | -0.102 | 4.286 | 17.101 | 2.12053
235306 | Second Floor | 2 | Second Floor | 0 | Up to level: Roof - Main | 4.578 | -0.102 | 1.834 | 5.87577 | 0.728595
217475 | Second Floor | 2 | Second Floor | 0 | Up to level: Roof - Main | 4.578 | -0.102 | 11.718 | 46.1184 | 5.71868
194487 | Second Floor | 2 | Second Floor | 0 | Up to level: Roof - Main | 4.578 | -0.102 | 1.799 | 6.44344 | 0.798987
193946 | Second Floor | 2 | Second Floor | 0 | Up to level: Roof - Main | 4.578 | -0.102 | 4.4545 | 17.5451 | 2.17559
196742 | Second Floor | 2 | Second Floor | 0 | Up to level: Roof - Main | 4.578 | -0.102 | 7.189 | 30.5512 | 3.78835
195851 | Second Floor | 2 | Second Floor | 0 | Up to level: Roof - Main | 4.578 | -0.102 | 4.4545 | 18.1128 | 2.24598
195567 | Second Floor | 2 | Second Floor | 0 | Up to level: Roof - Main | 4.578 | -0.102 | 3.441 | 13.2326 | 1.64084
195311 | Second Floor | 2 | Second Floor | 0 | Up to level: Roof - Main | 4.578 | -0.102 | 1.14791 | 3.70394 | 0.424092
194732 | Second Floor | 2 | Second Floor | 0 | Up to level: Roof - Main | 4.578 | -0.102 | 2.94697 | 11.415 | 1.41546
197178 | Second Floor | 2 | Second Floor | 0 | Up to level: Roof - Main | 4.578 | -0.102 | 1.834 | 5.87577 | 0.728595
196610 | Second Floor | 2 | Second Floor | 0 | Up to level: Roof - Main | 4.38 | -0.3 | 7.96064 | 31.4877 | 3.90447
197100 | Second Floor | 2 | Second Floor | 0 | Up to level: Roof - Main | 4.578 | -0.102 | 1.834 | 5.87577 | 0.728595
217712 | Second Floor | 2 | Second Floor | 0 | Up to level: Roof - Main | 4.578 | -0.102 | 5.62358 | 23.3959 | 2.90109
194392 | Second Floor | 2 | Second Floor | 0 | Up to level: Roof - Main | 4.578 | -0.102 | 5.64 | 21.9147 | 2.71742
214263 | Second Floor | 2 | Second Floor | 0 | Up to level: Roof - Main | 4.68 | 0 | 13.9086 | 62.8493 | 7.79331
213933 | Second Floor | 2 | Second Floor | 0 | Up to level: Roof - Main | 4.578 | -0.102 | 13.7585 | 60.1388 | 7.45721
215810 | Second Floor | 2 | Second Floor | 0 | Up to level: Roof - Main | 4.578 | -0.102 | 1.834 | 6.43624 | 0.798094
212763 | Second Floor | 2 | Second Floor | 0 | Up to level: Roof - Main | 4.578 | -0.102 | 3.749 | 14.8029 | 1.83556
214572 | Second Floor | 2 | Second Floor | 0 | Up to level: Roof - Main | 4.578 | -0.102 | 1.609 | 5.00595 | 0.620738
214393 | Second Floor | 2 | Second Floor | 0 | Up to level: Roof - Main | 4.578 | -0.102 | 10.3964 | 45.5187 | 5.64431
201038 | Second Floor | 2 | Second Floor | 0 | Up to level: Roof - Main | 4.578 | -0.102 | 7.03 | 29.6631 | 3.67822
201491 | Second Floor | 2 | Second Floor | 0 | Up to level: Roof - Main | 4.578 | -0.102 | 11.285 | 49.3027 | 6.11353
201310 | Second Floor | 2 | Second Floor | 0 | Up to level: Roof - Main | 4.578 | -0.102 | 7.03 | 25.7578 | 3.19397
208754 | Second Floor | 2 | Second Floor | 0 | Up to level: Roof - Main | 4.578 | -0.102 | 6.909 | 29.2693 | 3.6294
208828 | Second Floor | 2 | Second Floor | 0 | Up to level: Roof - Main | 4.578 | -0.102 | 2.83296 | 10.449 | 1.29568
204811 | Second Floor | 2 | Second Floor | 0 | Up to level: Roof - Main | 4.578 | -0.102 | 1.834 | 6.44344 | 0.798987
205171 | Second Floor | 2 | Second Floor | 0 | Up to level: Roof - Main | 4.578 | -0.102 | 7.686 | 29.3287 | 3.63676
205286 | Second Floor | 2 | Second Floor | 0 | Up to level: Roof - Main | 4.578 | -0.102 | 1.834 | 6.44344 | 0.798987
205331 | Second Floor | 2 | Second Floor | 0 | Up to level: Roof - Main | 4.578 | -0.102 | 1.9834 | 7.1274 | 0.883797
204115 | Second Floor | 2 | Second Floor | 0 | Up to level: Roof - Main | 4.578 | -0.102 | 12.745 | 50.6964 | 6.28635
239984 | Second Floor | 2 | Second Floor | 0 | Up to level: Roof - Main | 4.578 | -0.102 | 1.424 | 3.99879 | 0.49585
205727 | Second Floor | 2 | Second Floor | 0 | Up to level: Roof - Main | 4.578 | -0.102 | 6.3716 | 24.9801 | 3.09754
205241 | Second Floor | 2 | Second Floor | 0 | Up to level: Roof - Main | 4.578 | -0.102 | 8.326 | 31.6909 | 3.92967
206323 | Second Floor | 2 | Second Floor | 0 | Up to level: Roof - Main | 4.578 | -0.102 | 1.98044 | 6.44545 | 0.799236
207492 | Second Floor | 2 | Second Floor | 0 | Up to level: Roof - Main | 4.578 | -0.102 | 10.136 | 40.5448 | 5.02755
207601 | Second Floor | 2 | Second Floor | 0 | Up to level: Roof - Main | 4.578 | -0.102 | 8.326 | 33.6435 | 4.1718
212840 | Second Floor | 2 | Second Floor | 0 | Up to level: Roof - Main | 4.578 | -0.102 | 7.834 | 33.3438 | 4.13463
211999 | Second Floor | 2 | Second Floor | 0 | Up to level: Roof - Main | 4.578 | -0.102 | 2.02 | 6.72728 | 0.834182
210724 | Second Floor | 2 | Second Floor | 0 | Up to level: Roof - Main | 4.578 | -0.102 | 20.795 | 83.0764 | 10.3015
210194 | Second Floor | 2 | Second Floor | 0 | Up to level: Roof - Main | 4.578 | -0.102 | 8.164 | 35.175 | 4.3617
207456 | Second Floor | 2 | Second Floor | 0 | Up to level: Roof - Main | 4.578 | -0.102 | 1.86844 | 6.03343 | 0.748145
206694 | Second Floor | 2 | Second Floor | 0 | Up to level: Roof - Main | 4.578 | -0.102 | 11.295 | 43.6142 | 5.40816
213603 | Second Floor | 2 | Second Floor | 0 | Up to level: Roof - Main | 4.68 | 0 | 6.224 | 25.4758 | 3.159
198335 | Second Floor | 2 | Second Floor | 0 | Up to level: Roof - Main | 4.578 | -0.102 | 1.889 | 6.10074 | 0.756492
198725 | Second Floor | 2 | Second Floor | 0 | Up to level: Roof - Main | 4.578 | -0.102 | 3.7405 | 12.6777 | 1.56598
210458 | Second Floor | 2 | Second Floor | 0 | Up to level: Roof - Main | 4.578 | -0.102 | 8.16144 | 35.1632 | 4.36024
270222 | First Floor | 2 | First Floor | 2.4 | Up to level: Second Floor | 2.068 | -0.102 | 1.817 | 3.50112 | 0.434139
270324 | First Floor | 2 | First Floor | 2.5 | Up to level: Second Floor | 1.968 | -0.102 | 4.599 | 8.92882 | 1.10717
270462 | First Floor | 2 | First Floor | 3 | Up to level: Second Floor | 1.468 | -0.102 | 1.009 | 1.44158 | 0.178755
270507 | First Floor | 2 | First Floor | 2.5 | Up to level: Second Floor | 1.968 | -0.102 | 1.009 | 1.93258 | 0.239639
270737 | First Floor | 2 | First Floor | 2.4 | Up to level: Second Floor | 2.068 | -0.102 | 1.834 | 3.53628 | 0.438499
270815 | First Floor | 2 | First Floor | 2.4 | Up to level: Second Floor | 2.068 | -0.102 | 1.215 | 2.51262 | 0.311565
270956 | First Floor | 2 | First Floor | 2.4 | Up to level: Second Floor | 2.068 | -0.102 | 3.49875 | 7.01474 | 0.869828
271284 | First Floor | 2 | First Floor | 3 | Up to level: Second Floor | 1.468 | -0.102 | 2.126 | 3.12097 | 0.387
271369 | First Floor | 2 | First Floor | 2.4 | Up to level: Second Floor | 2.068 | -0.102 | 1.861 | 3.72033 | 0.461321
271549 | First Floor | 2 | First Floor | 2.4 | Up to level: Second Floor | 2.068 | -0.102 | 2.044 | 3.97056 | 0.492349
271771 | First Floor | 2 | First Floor | 2.4 | Up to level: Second Floor | 2.068 | -0.102 | 1.834 | 3.53628 | 0.438499
274956 | Second Floor | 2 | Second Floor | 2.4 | Up to level: Roof - Main | 2.178 | -0.102 | 0.915 | 1.99287 | 0.247116
275024 | Second Floor | 2 | Second Floor | 2.4 | Up to level: Roof - Main | 2.178 | -0.102 | 1.832 | 3.93129 | 0.48748
275171 | Second Floor | 2 | Second Floor | 2.4 | Up to level: Roof - Main | 2.178 | -0.102 | 1.6704 | 3.5031 | 0.434384
276194 | Second Floor | 2 | Second Floor | 2.4 | Up to level: Roof - Main | 2.178 | -0.102 | 1.834 | 3.72438 | 0.461823
276334 | Second Floor | 2 | Second Floor | 2.4 | Up to level: Roof - Main | 2.178 | -0.102 | 1.86844 | 3.79939 | 0.471124
281298 | Second Floor | 2 | Second Floor | 0 | Up to level: Roof - Main | 4.578 | -0.102 | 7.41176 | 34.2117 | 4.24226
281637 | Second Floor | 2 | Second Floor | 2.4 | Up to level: Roof - Main | 2.178 | -0.102 | 1.83 | 3.98574 | 0.494232
281847 | Second Floor | 2 | Second Floor | 2.4 | Up to level: Roof - Main | 2.28 | 0 | 4.77403 | 10.8578 | 1.34636
282168 | Second Floor | 2 | Second Floor | 2.4 | Up to level: Roof - Main | 2.28 | 0 | 6.17592 | 14.0905 | 1.74722
285430 | Second Floor | 2 | Second Floor | 0 | Up to level: Roof - Main | 2.0715 | -2.6085 | 4.71173 | 9.76034 | 1.21028
287482 | Second Floor | 2 | Second Floor | 0 | Up to level: Second Floor | 3 | 3 | 1.0798 | 2.23771 | 0.277476
288035 | Second Floor | 0 | Second Floor | 0 | Up to level: Roof - Main | 4.578 | -0.102 | 6.16325 | 16.1127 | 1.99797
296926 | Second Floor | 2 | Second Floor | 0 | Up to level: Second Floor | 2.0715 | 2.0715 | 5.00575 | 10.241 | 1.22048
311808 | First Floor | 2 | First Floor | 3.8 | Up to level: Second Floor | 0.668 | -0.102 | 6.79231 | 4.4523 | 0.55082 | PSet_Revit_Graphics - Center Mark Visible: no
312802 | First Floor | 2 | First Floor | 3.8 | Up to level: Second Floor | 0.668 | -0.102 | 6.7777 | 4.44291 | 0.549728 | PSet_Revit_Graphics - Center Mark Visible: no
314357 | First Floor | 2 | First Floor | 0.89 | Up to level: Second Floor | 3.578 | -0.102 | 1.135 | 2.16704 | 0.268713
317136 | First Floor | 2 | First Floor | 2.8 | Up to level: Second Floor | 1.65 | -0.12 | 6.20679 | 10.1389 | 1.25722
318614 | First Floor | 2 | First Floor | 3 | Up to level: Second Floor | 1.468 | -0.102 | 1.764 | 2.58955 | 0.321104
344740 | First Floor | 2 | First Floor | 2.8 | Up to level: Second Floor | 1.65 | -0.12 | 1.532 | 2.4255 | 0.300762
344918 | First Floor | 2 | First Floor | 2.8 | Up to level: Second Floor | 1.65 | -0.12 | 1.497 | 2.5146 | 0.31181
345208 | First Floor | 2 | First Floor | 2.8 | Up to level: Second Floor | 1.65 | -0.12 | 1.54455 | 2.3439 | 0.290644
345255 | First Floor | 2 | First Floor | 2.8 | Up to level: Second Floor | 1.65 | -0.12 | 6.22 | 10.263 | 1.27261
345315 | First Floor | 2 | First Floor | 2.8 | Up to level: Second Floor | 1.65 | -0.12 | 3.204 | 5.2866 | 0.655538
345352 | First Floor | 2 | First Floor | 2.8 | Up to level: Second Floor | 1.65 | -0.12 | 6.22 | 10.263 | 1.27261
345388 | First Floor | 2 | First Floor | 2.8 | Up to level: Second Floor | 1.65 | -0.12 | 1.545 | 2.34465 | 0.290737
345471 | First Floor | 2 | First Floor | 2.8 | Up to level: Second Floor | 1.65 | -0.12 | 3.23 | 5.3295 | 0.660858
346616 | First Floor | 2 | First Floor | 2.8 | Up to level: Second Floor | 1.65 | -0.12 | 3.204 | 5.2866 | 0.655538
349706 | First Floor | 2 | First Floor | 0 | Up to level: Second Floor | 4.468 | -0.102 | 6.378 | 28.2199 | 3.49927
166136 | First Floor | 2 | First Floor | 0 | Up to level: Second Floor | 4.468 | -0.102 | 6.365 | 24.2566 | 3.00782
355187 | First Floor | 2 | First Floor | 0 | Up to level: Second Floor | 4.468 | -0.102 | 1.023 | 2.37688 | 0.294733
359473 | First Floor | 2 | First Floor | 0 | Up to level: First Floor | 0.89 | 0.89 | 0.974 | 0.8188 | 0.101531
359581 | First Floor | 2 | First Floor | 0 | Up to level: First Floor | 0.89 | 0.89 | 1.009 | 0.87398 | 0.108374
363189 | First Floor | 2 | First Floor | 0 | Up to level: Second Floor | 4.468 | -0.102 | 4.887 | 21.5938 | 2.67764
156775 | First Floor | 2 | First Floor | 0 | Up to level: Second Floor | 4.468 | -0.102 | 15.323 | 60.3757 | 7.48659
365229 | First Floor | 2 | First Floor | 0 | Up to level: Second Floor | 4.468 | -0.102 | 3.605 | 15.7095 | 1.94798
149814 | First Floor | 2 | First Floor | 0 | Up to level: Second Floor | 4.468 | -0.102 | 1.784 | 4.03782 | 0.50069
368597 | First Floor | 2 | First Floor | 0 | Up to level: Second Floor | 4.468 | -0.102 | 0.350025 | 1.56391 | 0.193925
379092 | First Floor | 2 | First Floor | 3.8 | Up to level: Second Floor | 3.77 | 3 | 6.42173 | 23.9026 | 2.96392
379238 | Second Floor | 2 | Second Floor | 2.4 | Up to level: Roof - Main | 2.28 | 0 | 4.80902 | 10.8686 | 1.3477
379260 | Second Floor | 0 | Second Floor | 0 | Up to level: Roof - Main | 4.578 | -0.102 | 6.12825 | 15.8474 | 1.96508
381311 | Second Floor | 2 | Second Floor | 0 | Up to level: Roof - Main | 4.68 | 0 | 11.691 | 27.4777 | 3.40724
381589 | Second Floor | 2 | Second Floor | 0 | Up to level: Roof - Main | 4.68 | 0 | 11.691 | 27.9217 | 3.46229
387897 | Second Floor | 2 | Second Floor | 0 | Up to level: Roof - Main | 4.578 | -0.102 | 0.195 | 1.01632 | 0.126023
388351 | Second Floor | 2 | Second Floor | 0 | Up to level: Roof - Main | 4.578 | -0.102 | 4.035 | 18.0648 | 2.24003
390124 | Second Floor | 2 | Second Floor | 0 | Up to level: Roof - Main | 4.578 | -0.102 | 0.27976 | 1.12051 | 0.138943
391258 | Second Floor | 2 | Second Floor | 0 | Up to level: Roof - Main | 4.578 | -0.102 | 0.415 | 2.30731 | 0.286107
391315 | Second Floor | 2 | Second Floor | 0 | Up to level: Roof - Main | 4.578 | -0.102 | 1.1985 | 4.91906 | 0.609964
391540 | Second Floor | 2 | Second Floor | 0 | Up to level: Roof - Main | 4.578 | -0.102 | 3.119 | 14.1552 | 1.75524
392438 | Second Floor | 2 | Second Floor | 0 | Up to level: Second Floor | 0.89 | 0.89 | 1.33747 | 1.13517 | 0.140761
396063 | Second Floor | 2 | Second Floor | 0 | Up to level: Second Floor | 3 | 3 | 0.360025 | 1.45208 | 0.180057
399102 | Second Floor | 2 | Second Floor | 0 | Up to level: Second Floor | 3.3532 | 3.3532 | 6.09325 | 20.3145 | 2.519
400713 | Second Floor | 2 | Second Floor | 0 | Up to level: Roof - Main | 4.578 | -0.102 | 0.24 | 0.814884 | 0.101046
158475 | First Floor | 2 | First Floor | 0 | Up to level: Second Floor | 4.468 | -0.102 | 1.635 | 5.19619 | 0.644328
403859 | First Floor | 2 | First Floor | 0 | Up to level: Second Floor | 4.468 | -0.102 | 1.834 | 5.68767 | 0.705271
439929 | Second Floor | 2 | Second Floor | 0 | Up to level: Roof - Main | 4.578 | -0.102 | 3.818 | 17.195 | 2.13218
442141 | Second Floor | 2 | Second Floor | 0 | Up to level: Roof - Main | 4.578 | -0.102 | 0.732 | 2.92992 | 0.36331
170491 | First Floor | 2 | First Floor | 0 | Up to level: Second Floor | 4.468 | -0.102 | 6.58 | 26.8928 | 3.33471
356578 | First Floor | 2 | First Floor | 0 | Up to level: Second Floor | 4.468 | -0.102 | 4.494 | 18.1266 | 2.2477
355734 | First Floor | 2 | First Floor | 0 | Up to level: Second Floor | 4.468 | -0.102 | 5.6975 | 21.4306 | 2.65739
354436 | First Floor | 2 | First Floor | 0 | Up to level: Second Floor | 4.468 | -0.102 | 12.578 | 50.6177 | 6.27659
369550 | First Floor | 2 | First Floor | 0 | Up to level: Second Floor | 4.468 | -0.102 | 4.09402 | 11.8802 | 1.47315
368550 | First Floor | 2 | First Floor | 0 | Up to level: Second Floor | 4.468 | -0.102 | 2.0898 | 6.98696 | 0.866384
404985 | First Floor | 2 | First Floor | 0 | Up to level: Second Floor | 4.468 | -0.102 | 4.4385 | 17.0051 | 2.10863
234588 | Second Floor | 2 | Second Floor | 0 | Up to level: Roof - Main | 4.578 | -0.102 | 5.372 | 22.5168 | 2.79208
235927 | Second Floor | 2 | Second Floor | 0 | Up to level: Roof - Main | 4.578 | -0.102 | 32.32 | 127.04 | 15.7529
439833 | Second Floor | 2 | Second Floor | 0 | Up to level: Roof - Main | 4.578 | -0.102 | 3.98706 | 16.0163 | 1.94988
391583 | Second Floor | 2 | Second Floor | 0 | Up to level: Roof - Main | 4.578 | -0.102 | 3.119 | 11.905 | 1.47622
386438 | Second Floor | 2 | Second Floor | 0 | Up to level: Roof - Main | 4.578 | -0.102 | 2.185 | 7.64288 | 0.947717
386945 | Second Floor | 2 | Second Floor | 0 | Up to level: Roof - Main | 4.578 | -0.102 | 6.309 | 24.7302 | 3.06654
387394 | Second Floor | 2 | Second Floor | 0 | Up to level: Roof - Main | 4.578 | -0.102 | 5.739 | 21.9605 | 2.7231
366211 | First Floor | 2 | First Floor | 0 | Up to level: Second Floor | 4.468 | -0.102 | 14.2555 | 56.2786 | 6.9424

# IfcWallStandardCase: Basic Wall:Interior - Plumbing (152mm Stud):128382 (13)
Material: Plasterboard 0.016 m, Metal - Stud Layer 0.152 m, Plasterboard 0.016 m
Pset_WallCommon - Reference: Basic Wall:Interior - Plumbing (152mm Stud); LoadBearing: no; ExtendToStructure: no; IsExternal: no
PSet_Revit_Constraints - Base Offset: 0 m; Base is Attached: no; Base Extension Distance: 0 m; Top Offset: -0.102 m; Top is Attached: no; Top Extension Distance: 0 m; Room Bounding: yes; Related to Mass: no
PSet_Revit_Other - InstallationDate: InstallationDate; SerialNumber: SerialNumber; WarrantyStartDate: WarrantyStartDate; BarCode: BarCode; AssetIdentifier: AssetIdentifier; TagNumber: TagNumber
PSet_Revit_Phasing - Phase Created: New Construction
PSet_Revit_Structural - Structural Usage: 0
PSet_Revit_Type_Construction - Wrapping at Inserts: 0; Wrapping at Ends: 2; Width: 0.184 m; Function: 0
PSet_Revit_Type_Graphics - Coarse Scale Fill Color: 0
PSet_Revit_Type_Identity Data - Manufacturer: Manufacturer
PSet_Revit_Type_Other - AccessibilityPerformance: AccessibilityPerformance; CodePerformance: CodePerformance; Color: Color; Constituents: Constituents; Features: Features; Finish: Finish; Grade: Grade; Material: Material; ModelReference: ModelReference; NominalHeight: NominalHeight; NominalLength: NominalLength; NominalWidth: NominalWidth; ProductionYear: ProductionYear; Reference: Reference; Shape: Shape; Size: Size; SustainabilityPerformance: SustainabilityPerformance; WarrantyDescription: WarrantyDescription; WarrantyDurationLabor: WarrantyDurationLabor; WarrantyDurationParts: WarrantyDurationParts; WarrantyGuarantorLabor: WarrantyGuarantorLabor; WarrantyGuarantorParts: WarrantyGuarantorParts; ExpectedLife: ExpectedLife; ReplacementCost: ReplacementCost; AssetAccountingType: FIXED; Classification Code: 23-25 40 11 11 11; Classification Description: Metal-Framed Gypsum Board Fixed Partitions; ModelLabel: ModelLabel
Name (Basic Wall:Interior - Plumbing (152mm Stud):...) | In | Location Line | Base Constraint | Top Constraint | Unconnected Height (m) | Length (m) | Area (m2) | Volume (m3)
154583 | First Floor | 2 | First Floor | Up to level: Second Floor | 4.468 | 2.055 | 8.78409 | 1.61627
160049 | First Floor | 2 | First Floor | Up to level: Second Floor | 4.468 | 1.7178 | 7.1211 | 1.31028
162997 | First Floor | 2 | First Floor | Up to level: Second Floor | 4.468 | 2.756 | 11.7598 | 2.12766
177380 | First Floor | 2 | First Floor | Up to level: Second Floor | 4.468 | 1.69497 | 7.1755 | 1.32029
218034 | Second Floor | 2 | Second Floor | Up to level: Roof - Main | 4.578 | 0.94 | 4.44066 | 0.817081
218119 | Second Floor | 2 | Second Floor | Up to level: Roof - Main | 4.578 | 1.09778 | 4.75096 | 0.874176
218394 | Second Floor | 2 | Second Floor | Up to level: Roof - Main | 4.578 | 1.68933 | 7.16607 | 1.31856
218438 | Second Floor | 2 | Second Floor | Up to level: Roof - Main | 4.578 | 1.68933 | 7.16607 | 1.31856
219536 | Second Floor | 2 | Second Floor | Up to level: Roof - Main | 4.578 | 6.69364 | 30.6435 | 5.60892
426449 | Second Floor | 2 | Second Floor | Up to level: Roof - Main | 4.578 | 0.645 | 2.8292 | 0.520574
439314 | Second Floor | 2 | Second Floor | Up to level: Roof - Main | 4.578 | 3.154 | 13.734 | 2.52706
439798 | Second Floor | 2 | Second Floor | Up to level: Roof - Main | 4.578 | 0.6 | 2.7468 | 0.505411
439952 | Second Floor | 3 | Second Floor | Up to level: Roof - Main | 4.578 | 0.6 | 2.7468 | 0.505411

# IfcWallStandardCase: Basic Wall:Interior - Rated 1-HR (92mm Stud):128426 (30)
Material: Type-X Plasterboard 0.016 m, Metal - Stud Layer 0.092 m, Type-X Plasterboard 0.016 m
Pset_WallCommon - Reference: Basic Wall:Interior - Rated 1-HR (92mm Stud); LoadBearing: no; ExtendToStructure: no; IsExternal: no; FireRating: 1 HR
PSet_Revit_Constraints - Location Line: 2; Base Offset: 0 m; Base is Attached: no; Base Extension Distance: 0 m; Top is Attached: no; Top Extension Distance: 0 m; Room Bounding: yes; Related to Mass: no
PSet_Revit_Other - InstallationDate: InstallationDate; SerialNumber: SerialNumber; WarrantyStartDate: WarrantyStartDate; BarCode: BarCode; AssetIdentifier: AssetIdentifier; TagNumber: TagNumber
PSet_Revit_Phasing - Phase Created: New Construction
PSet_Revit_Structural - Structural Usage: 0
PSet_Revit_Type_Construction - Wrapping at Inserts: 0; Wrapping at Ends: 0; Width: 0.124 m; Function: 0
PSet_Revit_Type_Graphics - Coarse Scale Fill Pattern: Solid fill; Coarse Scale Fill Color: 8421504
PSet_Revit_Type_Identity Data - Manufacturer: Manufacturer; Fire Rating: 1 HR
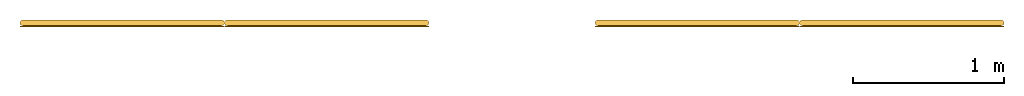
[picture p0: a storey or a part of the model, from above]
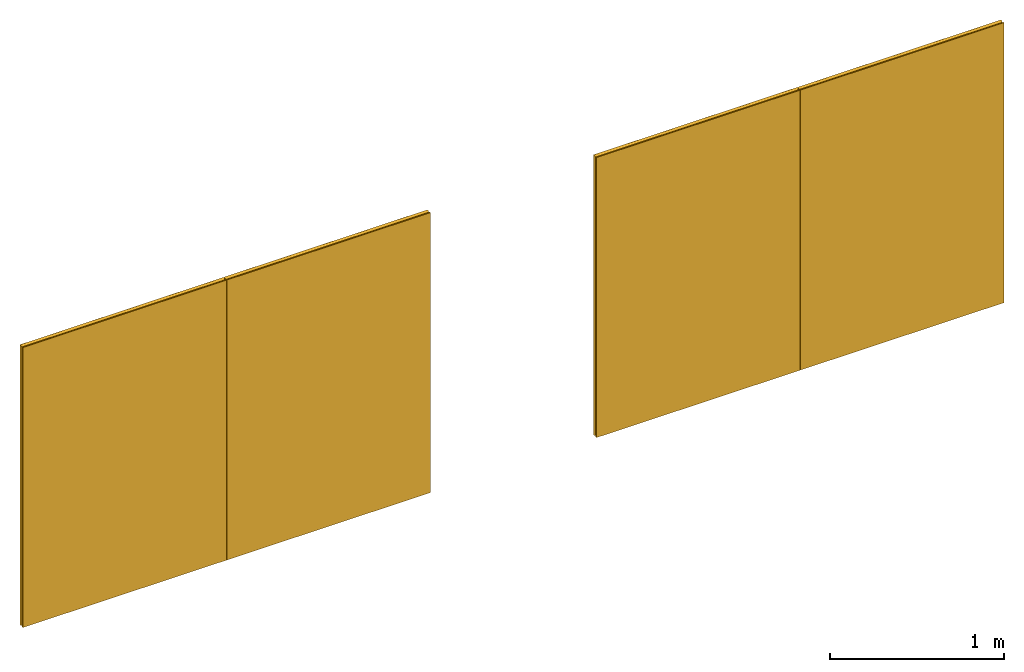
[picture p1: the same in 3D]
Properties of the parts of a building model (IFC2X3), part 11 of 11

# IfcWallStandardCase: Basic Wall:Interior - Rated 1-HR (92mm Stud):128426 (30)
PSet_Revit_Type_Other - AccessibilityPerformance: AccessibilityPerformance; CodePerformance: CodePerformance; Color: Color; Constituents: Constituents; Features: Features; Finish: Finish; Grade: Grade; Material: Material; ModelReference: ModelReference; NominalHeight: NominalHeight; NominalLength: NominalLength; NominalWidth: NominalWidth; ProductionYear: ProductionYear; Reference: Reference; Shape: Shape; Size: Size; SustainabilityPerformance: SustainabilityPerformance; WarrantyDescription: WarrantyDescription; WarrantyDurationLabor: WarrantyDurationLabor; WarrantyDurationParts: WarrantyDurationParts; WarrantyGuarantorLabor: WarrantyGuarantorLabor; WarrantyGuarantorParts: WarrantyGuarantorParts; ExpectedLife: ExpectedLife; ReplacementCost: ReplacementCost; AssetAccountingType: FIXED; Classification Code: 23-25 40 11 11 11; Classification Description: Metal-Framed Gypsum Board Fixed Partitions; ModelLabel: ModelLabel
Name (Basic Wall:Interior - Rated 1-HR (92mm Stud):...) | In | Base Constraint | Top Constraint | Unconnected Height (m) | Top Offset (m) | Length (m) | Area (m2) | Volume (m3)
150014 | First Floor | First Floor | Up to level: Second Floor | 4.468 | -0.102 | 2.544 | 11.9206 | 1.47816
150101 | First Floor | First Floor | Up to level: Second Floor | 4.468 | -0.102 | 4.205 | 18.7879 | 2.3297
150201 | First Floor | First Floor | Up to level: Second Floor | 3.82 | -0.75 | 1.199 | 4.58018 | 0.567942
150384 | First Floor | First Floor | Up to level: Second Floor | 3.82 | -0.75 | 0.485 | 1.61586 | 0.200367
150598 | First Floor | First Floor | Up to level: Second Floor | 4.468 | -0.102 | 2.015 | 9.0432 | 1.12136
150741 | First Floor | First Floor | Up to level: Second Floor | 4.468 | -0.102 | 5.799 | 25.3559 | 3.14413
164254 | First Floor | First Floor | Up to level: Second Floor | 4.468 | -0.102 | 0.8045 | 3.27504 | 0.406105
164331 | First Floor | First Floor | Up to level: Second Floor | 4.468 | -0.102 | 2.8458 | 12.715 | 1.57666
164366 | First Floor | First Floor | Up to level: Second Floor | 4.468 | -0.102 | 0.8045 | 2.72101 | 0.337405
181424 | First Floor | First Floor | Up to level: Second Floor | 4.57 | 0 | 6.156 | 28.1329 | 3.48848
181598 | First Floor | First Floor | Up to level: Second Floor | 4.57 | 0 | 2.9245 | 12.4715 | 1.54647
182600 | First Floor | First Floor | Up to level: Second Floor | 4.468 | -0.102 | 2.3692 | 11.1396 | 1.38131
182913 | First Floor | First Floor | Up to level: Second Floor | 4.468 | -0.102 | 1.8385 | 8.21442 | 1.01859
182976 | First Floor | First Floor | Up to level: Second Floor | 4.468 | -0.102 | 2.3692 | 8.63426 | 1.07065
190562 | Second Floor | Second Floor | Up to level: Roof - Main | 4.578 | -0.102 | 5.78 | 27.0285 | 3.35153
190644 | Second Floor | Second Floor | Up to level: Roof - Main | 4.578 | -0.102 | 2.544 | 11.6464 | 1.44416
190765 | Second Floor | Second Floor | Up to level: Roof - Main | 4.578 | -0.102 | 6.175 | 27.5412 | 3.41511
190897 | Second Floor | Second Floor | Up to level: Roof - Main | 4.578 | -0.102 | 0.983999 | 3.93707 | 0.488197
190934 | Second Floor | Second Floor | Up to level: Roof - Main | 4.578 | -0.102 | 0.360001 | 1.64808 | 0.204362
202370 | Second Floor | Second Floor | Up to level: Roof - Main | 4.578 | -0.102 | 2.3592 | 11.3681 | 1.40964
202408 | Second Floor | Second Floor | Up to level: Roof - Main | 4.578 | -0.102 | 1.8385 | 8.41665 | 1.04366
202564 | Second Floor | Second Floor | Up to level: Roof - Main | 4.578 | -0.102 | 2.3592 | 8.28142 | 1.0269
204955 | Second Floor | Second Floor | Up to level: Roof - Main | 4.578 | -0.102 | 1.8385 | 8.04465 | 0.997537
207318 | Second Floor | Second Floor | Up to level: Roof - Main | 4.578 | -0.102 | 2.9245 | 12.4934 | 1.54918
150462 | First Floor | First Floor | Up to level: Second Floor | 3.82 | -0.75 | 1.594 | 4.13647 | 0.512922
181343 | First Floor | First Floor | Up to level: Second Floor | 4.468 | -0.102 | 2.9245 | 10.7946 | 1.33853
191306 | Second Floor | Second Floor | Up to level: Roof - Main | 4.578 | -0.102 | 1.694 | 6.37019 | 0.789904
207426 | Second Floor | Second Floor | Up to level: Roof - Main | 4.578 | -0.102 | 2.9245 | 10.5408 | 1.30705
368590 | First Floor | First Floor | Up to level: Second Floor | 4.468 | -0.102 | 1.8385 | 7.66039 | 0.949888
384656 | Second Floor | Second Floor | Up to level: Roof - Main | 4.578 | -0.102 | 6.156 | 28.466 | 3.52978

# IfcWallStandardCase: Basic Wall:Interior - Toilet Partition (25mm):128491 (10)
Material: Laminate - Ivory, Matte 0.025 m
Pset_WallCommon - Reference: Basic Wall:Interior - Toilet Partition (25mm); LoadBearing: no; ExtendToStructure: no; IsExternal: no; FireRating: 2 HR
PSet_Revit_Constraints - Location Line: 2; Base is Attached: no; Base Extension Distance: 0 m; Top is Attached: no; Top Extension Distance: 0 m; Room Bounding: no; Related to Mass: no
PSet_Revit_Other - InstallationDate: InstallationDate; SerialNumber: SerialNumber; WarrantyStartDate: WarrantyStartDate; BarCode: BarCode; AssetIdentifier: AssetIdentifier; TagNumber: TagNumber
PSet_Revit_Phasing - Phase Created: New Construction
PSet_Revit_Structural - Structural Usage: 0
PSet_Revit_Type_Construction - Wrapping at Inserts: 0; Wrapping at Ends: 0; Width: 0.025 m; Function: 0
PSet_Revit_Type_Graphics - Coarse Scale Fill Color: 0
PSet_Revit_Type_Identity Data - Manufacturer: Manufacturer; Fire Rating: 2 HR
PSet_Revit_Type_Other - AccessibilityPerformance: AccessibilityPerformance; CodePerformance: CodePerformance; Color: Color; Constituents: Constituents; Features: Features; Finish: Finish; Grade: Grade; Material: Material; ModelReference: ModelReference; NominalHeight: NominalHeight; NominalLength: NominalLength; NominalWidth: NominalWidth; ProductionYear: ProductionYear; Reference: Reference; Shape: Shape; Size: Size; SustainabilityPerformance: SustainabilityPerformance; WarrantyDescription: WarrantyDescription; WarrantyDurationLabor: WarrantyDurationLabor; WarrantyDurationParts: WarrantyDurationParts; WarrantyGuarantorLabor: WarrantyGuarantorLabor; WarrantyGuarantorParts: WarrantyGuarantorParts; ExpectedLife: ExpectedLife; ReplacementCost: ReplacementCost; AssetAccountingType: FIXED; Classification Code: 23-25 40 14 14 11 11; Classification Description: Metal Toilet Compartments and Urinal Screens; ModelLabel: ModelLabel
Name (Basic Wall:Interior - Toilet Partition (25mm):...) | In | Base Constraint | Base Offset (m) | Top Constraint | Unconnected Height (m) | Top Offset (m) | Length (m) | Area (m2) | Volume (m3)
408771 | Second Floor | Second Floor | 0 | Up to level: Roof - Main | 4.578 | -0.102 | 1.79 | 6.89712 | 0.172428
411532 | First Floor | First Floor | 0.25 | Up to level: First Floor | 1.5 | 1.75 | 1.5715 | 2.2125 | 0.0553125
411446 | First Floor | First Floor | 0.25 | Up to level: First Floor | 1.5 | 1.75 | 3.1945 | 1.9035 | 0.0475875
412769 | First Floor | First Floor | 0.25 | Up to level: First Floor | 1.5 | 1.75 | 1.5715 | 2.2125 | 0.0553125
412768 | First Floor | First Floor | 0.25 | Up to level: First Floor | 1.5 | 1.75 | 1.5655 | 0.976501 | 0.0244125
412884 | Second Floor | Second Floor | 0.25 | Up to level: Second Floor | 1.5 | 1.75 | 0.159585 | 0.258128 | 0.0064532
412921 | Second Floor | Second Floor | 0.25 | Up to level: Second Floor | 1.5 | 1.75 | 1.5745 | 0.907498 | 0.0226875
413182 | Second Floor | Second Floor | 0.25 | Up to level: Second Floor | 1.5 | 1.75 | 1.6295 | 2.2875 | 0.0571875
413112 | Second Floor | Second Floor | 0.25 | Up to level: Second Floor | 1.5 | 1.75 | 2.95609 | 1.65313 | 0.0413282
409027 | Second Floor | Second Floor | 0 | Up to level: Roof - Main | 4.578 | -0.102 | 1.544 | 5.4871 | 0.137177

# IfcWindow: 1735 x 1000mm (58)
Type - ParameterTakesPrecedence: no; Sizeable: no
OverallHeight: 1.735 m; OverallWidth: 1 m
Pset_WindowCommon - Reference: M_Fixed:1735 x 1000mm; IsExternal: yes; FireRating: FireRating
PSet_Revit_Constraints - Sill Height: 0.905 m
PSet_Revit_Other - Head Height: 2.64 m; InstallationDate: InstallationDate; SerialNumber: SerialNumber; WarrantyStartDate: WarrantyStartDate; BarCode: BarCode; AssetIdentifier: AssetIdentifier; TagNumber: TagNumber
PSet_Revit_Phasing - Phase Created: New Construction
PSet_Revit_Type_Materials and Finishes - Frame Exterior Material: Sash; Frame Interior Material: Sash; Glass Pane Material: Glass; Sash: Sash
PSet_Revit_Type_Dimensions - Height: 1.735 m; Default Sill Height: 0.915 m; Width: 1 m; Window Inset: 0.019 m
PSet_Revit_Type_Construction - Wall Closure: 0; Construction Type: Construction Type
PSet_Revit_Type_Identity Data - Manufacturer: Manufacturer; Type Mark: 19; OmniClass Number: 23.30.20.17.11; OmniClass Title: Fixed Windows
PSet_Revit_Type_Other - AccessibilityPerformance: AccessibilityPerformance; CodePerformance: CodePerformance; ConfigurationType: ConfigurationType; FireRating: FireRating; GlazingAreaFraction: GlazingAreaFraction; OperationType: OperationType; Area: Area; Color: Color; Constituents: Constituents; Features: Features; Finish: Finish; Grade: Grade; Material: Material; ModelReference: ModelReference; NominalHeight: NominalHeight; NominalLength: NominalLength; NominalWidth: NominalWidth; ProductionYear: ProductionYear; Reference: Reference; Shape: Shape; Size: Size; SustainabilityPerformance: SustainabilityPerformance; WarrantyDescription: WarrantyDescription; WarrantyDurationLabor: WarrantyDurationLabor; WarrantyDurationParts: WarrantyDurationParts; WarrantyGuarantorLabor: WarrantyGuarantorLabor; WarrantyGuarantorParts: WarrantyGuarantorParts; ExpectedLife: ExpectedLife; ReplacementCost: ReplacementCost; AssetAccountingType: FIXED; ModelLabel: ModelLabel
Name (M_Fixed:1735 x 1000mm:1735 x 1000mm:...) | In | Level | Mark
253076 | First Floor | First Floor | 8
253332 | First Floor | First Floor | 9
253561 | First Floor | First Floor | 10
253704 | First Floor | First Floor | 11
253943 | First Floor | First Floor | 12
254052 | First Floor | First Floor | 13
254105 | First Floor | First Floor | 14
254158 | First Floor | First Floor | 15
254526 | First Floor | First Floor | 21
254583 | First Floor | First Floor | 22
254638 | First Floor | First Floor | 23
254683 | First Floor | First Floor | 24
254752 | First Floor | First Floor | 25
259285 | Second Floor | Second Floor | 32
259348 | Second Floor | Second Floor | 33
259543 | Second Floor | Second Floor | 34
259606 | Second Floor | Second Floor | 35
259767 | Second Floor | Second Floor | 36
259922 | Second Floor | Second Floor | 37
260015 | Second Floor | Second Floor | 38
260209 | Second Floor | Second Floor | 39
260236 | Second Floor | Second Floor | 40
260343 | Second Floor | Second Floor | 41
260452 | Second Floor | Second Floor | 42
260595 | Second Floor | Second Floor | 43
260718 | Second Floor | Second Floor | 44
260833 | Second Floor | Second Floor | 45
260974 | Second Floor | Second Floor | 46
261025 | Second Floor | Second Floor | 47
261080 | Second Floor | Second Floor | 48
261135 | Second Floor | Second Floor | 49
261220 | Second Floor | Second Floor | 50
261267 | Second Floor | Second Floor | 51
261370 | Second Floor | Second Floor | 52
261427 | Second Floor | Second Floor | 53
261484 | Second Floor | Second Floor | 54
261527 | Second Floor | Second Floor | 55
261584 | Second Floor | Second Floor | 56
261637 | Second Floor | Second Floor | 57
261760 | Second Floor | Second Floor | 58
261827 | Second Floor | Second Floor | 59
261874 | Second Floor | Second Floor | 60
261927 | Second Floor | Second Floor | 61
261994 | Second Floor | Second Floor | 62
262059 | Second Floor | Second Floor | 63
262138 | Second Floor | Second Floor | 64
262496 | Second Floor | Second Floor | 65
262576 | Second Floor | Second Floor | 66
262643 | Second Floor | Second Floor | 67
254221 | First Floor | First Floor | 16
254294 | First Floor | First Floor | 17
254345 | First Floor | First Floor | 18
254424 | First Floor | First Floor | 19
254479 | First Floor | First Floor | 20
254843 | First Floor | First Floor | 26
254940 | First Floor | First Floor | 27
254989 | First Floor | First Floor | 28
255048 | First Floor | First Floor | 29
